VERSION 5.8 ;
BUSBITCHARS "[]" ;
DIVIDERCHAR "/" ;
UNITS
    DATABASE MICRONS 1000 ;
END UNITS

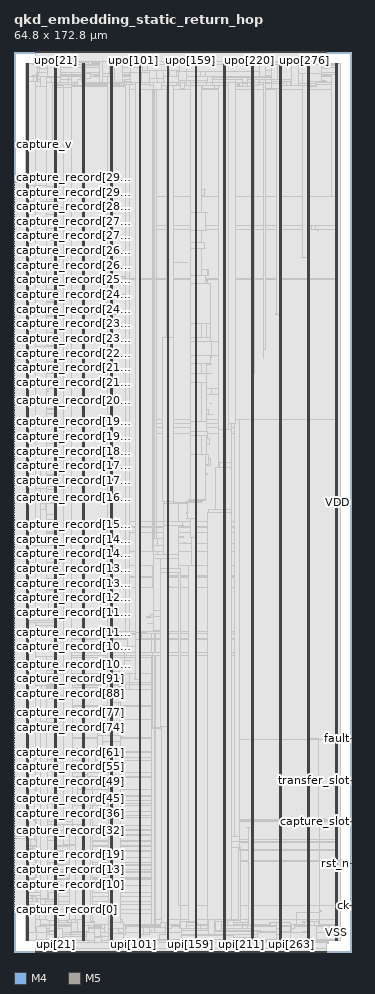
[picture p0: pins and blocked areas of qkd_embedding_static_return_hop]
MACRO qkd_embedding_static_return_hop
  FOREIGN qkd_embedding_static_return_hop 0 0 ;
  CLASS BLOCK ;
  SIZE 64.8 BY 172.8 ;
  PIN capture_record[0]
    DIRECTION INPUT ;
    USE SIGNAL ;
    PORT
      LAYER M4 ;
        RECT  -0.072 8.208 0.072 8.232 ;
    END
  END capture_record[0]
  PIN capture_record[100]
    DIRECTION INPUT ;
    USE SIGNAL ;
    PORT
      LAYER M4 ;
        RECT  -0.072 55.2 0.072 55.224 ;
    END
  END capture_record[100]
  PIN capture_record[101]
    DIRECTION INPUT ;
    USE SIGNAL ;
    PORT
      LAYER M4 ;
        RECT  -0.072 55.68 0.072 55.704 ;
    END
  END capture_record[101]
  PIN capture_record[102]
    DIRECTION INPUT ;
    USE SIGNAL ;
    PORT
      LAYER M4 ;
        RECT  -0.072 56.16 0.072 56.184 ;
    END
  END capture_record[102]
  PIN capture_record[103]
    DIRECTION INPUT ;
    USE SIGNAL ;
    PORT
      LAYER M4 ;
        RECT  -0.072 56.592 0.072 56.616 ;
    END
  END capture_record[103]
  PIN capture_record[104]
    DIRECTION INPUT ;
    USE SIGNAL ;
    PORT
      LAYER M4 ;
        RECT  -0.072 57.072 0.072 57.096 ;
    END
  END capture_record[104]
  PIN capture_record[105]
    DIRECTION INPUT ;
    USE SIGNAL ;
    PORT
      LAYER M4 ;
        RECT  -0.072 57.552 0.072 57.576 ;
    END
  END capture_record[105]
  PIN capture_record[106]
    DIRECTION INPUT ;
    USE SIGNAL ;
    PORT
      LAYER M4 ;
        RECT  -0.072 58.032 0.072 58.056 ;
    END
  END capture_record[106]
  PIN capture_record[107]
    DIRECTION INPUT ;
    USE SIGNAL ;
    PORT
      LAYER M4 ;
        RECT  -0.072 58.512 0.072 58.536 ;
    END
  END capture_record[107]
  PIN capture_record[108]
    DIRECTION INPUT ;
    USE SIGNAL ;
    PORT
      LAYER M4 ;
        RECT  -0.072 58.944 0.072 58.968 ;
    END
  END capture_record[108]
  PIN capture_record[109]
    DIRECTION INPUT ;
    USE SIGNAL ;
    PORT
      LAYER M4 ;
        RECT  -0.072 59.424 0.072 59.448 ;
    END
  END capture_record[109]
  PIN capture_record[10]
    DIRECTION INPUT ;
    USE SIGNAL ;
    PORT
      LAYER M4 ;
        RECT  -0.072 12.912 0.072 12.936 ;
    END
  END capture_record[10]
  PIN capture_record[110]
    DIRECTION INPUT ;
    USE SIGNAL ;
    PORT
      LAYER M4 ;
        RECT  -0.072 59.904 0.072 59.928 ;
    END
  END capture_record[110]
  PIN capture_record[111]
    DIRECTION INPUT ;
    USE SIGNAL ;
    PORT
      LAYER M4 ;
        RECT  -0.072 60.384 0.072 60.408 ;
    END
  END capture_record[111]
  PIN capture_record[112]
    DIRECTION INPUT ;
    USE SIGNAL ;
    PORT
      LAYER M4 ;
        RECT  -0.072 60.864 0.072 60.888 ;
    END
  END capture_record[112]
  PIN capture_record[113]
    DIRECTION INPUT ;
    USE SIGNAL ;
    PORT
      LAYER M4 ;
        RECT  -0.072 61.296 0.072 61.32 ;
    END
  END capture_record[113]
  PIN capture_record[114]
    DIRECTION INPUT ;
    USE SIGNAL ;
    PORT
      LAYER M4 ;
        RECT  -0.072 61.776 0.072 61.8 ;
    END
  END capture_record[114]
  PIN capture_record[115]
    DIRECTION INPUT ;
    USE SIGNAL ;
    PORT
      LAYER M4 ;
        RECT  -0.072 62.256 0.072 62.28 ;
    END
  END capture_record[115]
  PIN capture_record[116]
    DIRECTION INPUT ;
    USE SIGNAL ;
    PORT
      LAYER M4 ;
        RECT  -0.072 62.736 0.072 62.76 ;
    END
  END capture_record[116]
  PIN capture_record[117]
    DIRECTION INPUT ;
    USE SIGNAL ;
    PORT
      LAYER M4 ;
        RECT  -0.072 63.168 0.072 63.192 ;
    END
  END capture_record[117]
  PIN capture_record[118]
    DIRECTION INPUT ;
    USE SIGNAL ;
    PORT
      LAYER M4 ;
        RECT  -0.072 63.648 0.072 63.672 ;
    END
  END capture_record[118]
  PIN capture_record[119]
    DIRECTION INPUT ;
    USE SIGNAL ;
    PORT
      LAYER M4 ;
        RECT  -0.072 64.128 0.072 64.152 ;
    END
  END capture_record[119]
  PIN capture_record[11]
    DIRECTION INPUT ;
    USE SIGNAL ;
    PORT
      LAYER M4 ;
        RECT  -0.072 13.392 0.072 13.416 ;
    END
  END capture_record[11]
  PIN capture_record[120]
    DIRECTION INPUT ;
    USE SIGNAL ;
    PORT
      LAYER M4 ;
        RECT  -0.072 64.608 0.072 64.632 ;
    END
  END capture_record[120]
  PIN capture_record[121]
    DIRECTION INPUT ;
    USE SIGNAL ;
    PORT
      LAYER M4 ;
        RECT  -0.072 65.088 0.072 65.112 ;
    END
  END capture_record[121]
  PIN capture_record[122]
    DIRECTION INPUT ;
    USE SIGNAL ;
    PORT
      LAYER M4 ;
        RECT  -0.072 65.52 0.072 65.544 ;
    END
  END capture_record[122]
  PIN capture_record[123]
    DIRECTION INPUT ;
    USE SIGNAL ;
    PORT
      LAYER M4 ;
        RECT  -0.072 66 0.072 66.024 ;
    END
  END capture_record[123]
  PIN capture_record[124]
    DIRECTION INPUT ;
    USE SIGNAL ;
    PORT
      LAYER M4 ;
        RECT  -0.072 66.48 0.072 66.504 ;
    END
  END capture_record[124]
  PIN capture_record[125]
    DIRECTION INPUT ;
    USE SIGNAL ;
    PORT
      LAYER M4 ;
        RECT  -0.072 66.96 0.072 66.984 ;
    END
  END capture_record[125]
  PIN capture_record[126]
    DIRECTION INPUT ;
    USE SIGNAL ;
    PORT
      LAYER M4 ;
        RECT  -0.072 67.44 0.072 67.464 ;
    END
  END capture_record[126]
  PIN capture_record[127]
    DIRECTION INPUT ;
    USE SIGNAL ;
    PORT
      LAYER M4 ;
        RECT  -0.072 67.872 0.072 67.896 ;
    END
  END capture_record[127]
  PIN capture_record[128]
    DIRECTION INPUT ;
    USE SIGNAL ;
    PORT
      LAYER M4 ;
        RECT  -0.072 68.352 0.072 68.376 ;
    END
  END capture_record[128]
  PIN capture_record[129]
    DIRECTION INPUT ;
    USE SIGNAL ;
    PORT
      LAYER M4 ;
        RECT  -0.072 68.832 0.072 68.856 ;
    END
  END capture_record[129]
  PIN capture_record[12]
    DIRECTION INPUT ;
    USE SIGNAL ;
    PORT
      LAYER M4 ;
        RECT  -0.072 13.872 0.072 13.896 ;
    END
  END capture_record[12]
  PIN capture_record[130]
    DIRECTION INPUT ;
    USE SIGNAL ;
    PORT
      LAYER M4 ;
        RECT  -0.072 69.312 0.072 69.336 ;
    END
  END capture_record[130]
  PIN capture_record[131]
    DIRECTION INPUT ;
    USE SIGNAL ;
    PORT
      LAYER M4 ;
        RECT  -0.072 69.744 0.072 69.768 ;
    END
  END capture_record[131]
  PIN capture_record[132]
    DIRECTION INPUT ;
    USE SIGNAL ;
    PORT
      LAYER M4 ;
        RECT  -0.072 70.224 0.072 70.248 ;
    END
  END capture_record[132]
  PIN capture_record[133]
    DIRECTION INPUT ;
    USE SIGNAL ;
    PORT
      LAYER M4 ;
        RECT  -0.072 70.704 0.072 70.728 ;
    END
  END capture_record[133]
  PIN capture_record[134]
    DIRECTION INPUT ;
    USE SIGNAL ;
    PORT
      LAYER M4 ;
        RECT  -0.072 71.184 0.072 71.208 ;
    END
  END capture_record[134]
  PIN capture_record[135]
    DIRECTION INPUT ;
    USE SIGNAL ;
    PORT
      LAYER M4 ;
        RECT  -0.072 71.664 0.072 71.688 ;
    END
  END capture_record[135]
  PIN capture_record[136]
    DIRECTION INPUT ;
    USE SIGNAL ;
    PORT
      LAYER M4 ;
        RECT  -0.072 72.096 0.072 72.12 ;
    END
  END capture_record[136]
  PIN capture_record[137]
    DIRECTION INPUT ;
    USE SIGNAL ;
    PORT
      LAYER M4 ;
        RECT  -0.072 72.576 0.072 72.6 ;
    END
  END capture_record[137]
  PIN capture_record[138]
    DIRECTION INPUT ;
    USE SIGNAL ;
    PORT
      LAYER M4 ;
        RECT  -0.072 73.056 0.072 73.08 ;
    END
  END capture_record[138]
  PIN capture_record[139]
    DIRECTION INPUT ;
    USE SIGNAL ;
    PORT
      LAYER M4 ;
        RECT  -0.072 73.536 0.072 73.56 ;
    END
  END capture_record[139]
  PIN capture_record[13]
    DIRECTION INPUT ;
    USE SIGNAL ;
    PORT
      LAYER M4 ;
        RECT  -0.072 14.352 0.072 14.376 ;
    END
  END capture_record[13]
  PIN capture_record[140]
    DIRECTION INPUT ;
    USE SIGNAL ;
    PORT
      LAYER M4 ;
        RECT  -0.072 74.016 0.072 74.04 ;
    END
  END capture_record[140]
  PIN capture_record[141]
    DIRECTION INPUT ;
    USE SIGNAL ;
    PORT
      LAYER M4 ;
        RECT  -0.072 74.448 0.072 74.472 ;
    END
  END capture_record[141]
  PIN capture_record[142]
    DIRECTION INPUT ;
    USE SIGNAL ;
    PORT
      LAYER M4 ;
        RECT  -0.072 74.928 0.072 74.952 ;
    END
  END capture_record[142]
  PIN capture_record[143]
    DIRECTION INPUT ;
    USE SIGNAL ;
    PORT
      LAYER M4 ;
        RECT  -0.072 75.408 0.072 75.432 ;
    END
  END capture_record[143]
  PIN capture_record[144]
    DIRECTION INPUT ;
    USE SIGNAL ;
    PORT
      LAYER M4 ;
        RECT  -0.072 75.888 0.072 75.912 ;
    END
  END capture_record[144]
  PIN capture_record[145]
    DIRECTION INPUT ;
    USE SIGNAL ;
    PORT
      LAYER M4 ;
        RECT  -0.072 76.32 0.072 76.344 ;
    END
  END capture_record[145]
  PIN capture_record[146]
    DIRECTION INPUT ;
    USE SIGNAL ;
    PORT
      LAYER M4 ;
        RECT  -0.072 76.8 0.072 76.824 ;
    END
  END capture_record[146]
  PIN capture_record[147]
    DIRECTION INPUT ;
    USE SIGNAL ;
    PORT
      LAYER M4 ;
        RECT  -0.072 77.28 0.072 77.304 ;
    END
  END capture_record[147]
  PIN capture_record[148]
    DIRECTION INPUT ;
    USE SIGNAL ;
    PORT
      LAYER M4 ;
        RECT  -0.072 77.76 0.072 77.784 ;
    END
  END capture_record[148]
  PIN capture_record[149]
    DIRECTION INPUT ;
    USE SIGNAL ;
    PORT
      LAYER M4 ;
        RECT  -0.072 78.24 0.072 78.264 ;
    END
  END capture_record[149]
  PIN capture_record[14]
    DIRECTION INPUT ;
    USE SIGNAL ;
    PORT
      LAYER M4 ;
        RECT  -0.072 14.784 0.072 14.808 ;
    END
  END capture_record[14]
  PIN capture_record[150]
    DIRECTION INPUT ;
    USE SIGNAL ;
    PORT
      LAYER M4 ;
        RECT  -0.072 78.672 0.072 78.696 ;
    END
  END capture_record[150]
  PIN capture_record[151]
    DIRECTION INPUT ;
    USE SIGNAL ;
    PORT
      LAYER M4 ;
        RECT  -0.072 79.152 0.072 79.176 ;
    END
  END capture_record[151]
  PIN capture_record[152]
    DIRECTION INPUT ;
    USE SIGNAL ;
    PORT
      LAYER M4 ;
        RECT  -0.072 79.632 0.072 79.656 ;
    END
  END capture_record[152]
  PIN capture_record[153]
    DIRECTION INPUT ;
    USE SIGNAL ;
    PORT
      LAYER M4 ;
        RECT  -0.072 80.112 0.072 80.136 ;
    END
  END capture_record[153]
  PIN capture_record[154]
    DIRECTION INPUT ;
    USE SIGNAL ;
    PORT
      LAYER M4 ;
        RECT  -0.072 80.592 0.072 80.616 ;
    END
  END capture_record[154]
  PIN capture_record[155]
    DIRECTION INPUT ;
    USE SIGNAL ;
    PORT
      LAYER M4 ;
        RECT  -0.072 81.024 0.072 81.048 ;
    END
  END capture_record[155]
  PIN capture_record[156]
    DIRECTION INPUT ;
    USE SIGNAL ;
    PORT
      LAYER M4 ;
        RECT  -0.072 81.504 0.072 81.528 ;
    END
  END capture_record[156]
  PIN capture_record[157]
    DIRECTION INPUT ;
    USE SIGNAL ;
    PORT
      LAYER M4 ;
        RECT  -0.072 81.984 0.072 82.008 ;
    END
  END capture_record[157]
  PIN capture_record[158]
    DIRECTION INPUT ;
    USE SIGNAL ;
    PORT
      LAYER M4 ;
        RECT  -0.072 82.464 0.072 82.488 ;
    END
  END capture_record[158]
  PIN capture_record[159]
    DIRECTION INPUT ;
    USE SIGNAL ;
    PORT
      LAYER M4 ;
        RECT  -0.072 82.944 0.072 82.968 ;
    END
  END capture_record[159]
  PIN capture_record[15]
    DIRECTION INPUT ;
    USE SIGNAL ;
    PORT
      LAYER M4 ;
        RECT  -0.072 15.264 0.072 15.288 ;
    END
  END capture_record[15]
  PIN capture_record[160]
    DIRECTION INPUT ;
    USE SIGNAL ;
    PORT
      LAYER M4 ;
        RECT  -0.072 83.376 0.072 83.4 ;
    END
  END capture_record[160]
  PIN capture_record[161]
    DIRECTION INPUT ;
    USE SIGNAL ;
    PORT
      LAYER M4 ;
        RECT  -0.072 83.856 0.072 83.88 ;
    END
  END capture_record[161]
  PIN capture_record[162]
    DIRECTION INPUT ;
    USE SIGNAL ;
    PORT
      LAYER M4 ;
        RECT  -0.072 84.336 0.072 84.36 ;
    END
  END capture_record[162]
  PIN capture_record[163]
    DIRECTION INPUT ;
    USE SIGNAL ;
    PORT
      LAYER M4 ;
        RECT  -0.072 84.816 0.072 84.84 ;
    END
  END capture_record[163]
  PIN capture_record[164]
    DIRECTION INPUT ;
    USE SIGNAL ;
    PORT
      LAYER M4 ;
        RECT  -0.072 85.248 0.072 85.272 ;
    END
  END capture_record[164]
  PIN capture_record[165]
    DIRECTION INPUT ;
    USE SIGNAL ;
    PORT
      LAYER M4 ;
        RECT  -0.072 85.728 0.072 85.752 ;
    END
  END capture_record[165]
  PIN capture_record[166]
    DIRECTION INPUT ;
    USE SIGNAL ;
    PORT
      LAYER M4 ;
        RECT  -0.072 86.208 0.072 86.232 ;
    END
  END capture_record[166]
  PIN capture_record[167]
    DIRECTION INPUT ;
    USE SIGNAL ;
    PORT
      LAYER M4 ;
        RECT  -0.072 86.688 0.072 86.712 ;
    END
  END capture_record[167]
  PIN capture_record[168]
    DIRECTION INPUT ;
    USE SIGNAL ;
    PORT
      LAYER M4 ;
        RECT  -0.072 87.168 0.072 87.192 ;
    END
  END capture_record[168]
  PIN capture_record[169]
    DIRECTION INPUT ;
    USE SIGNAL ;
    PORT
      LAYER M4 ;
        RECT  -0.072 87.6 0.072 87.624 ;
    END
  END capture_record[169]
  PIN capture_record[16]
    DIRECTION INPUT ;
    USE SIGNAL ;
    PORT
      LAYER M4 ;
        RECT  -0.072 15.744 0.072 15.768 ;
    END
  END capture_record[16]
  PIN capture_record[170]
    DIRECTION INPUT ;
    USE SIGNAL ;
    PORT
      LAYER M4 ;
        RECT  -0.072 88.08 0.072 88.104 ;
    END
  END capture_record[170]
  PIN capture_record[171]
    DIRECTION INPUT ;
    USE SIGNAL ;
    PORT
      LAYER M4 ;
        RECT  -0.072 88.56 0.072 88.584 ;
    END
  END capture_record[171]
  PIN capture_record[172]
    DIRECTION INPUT ;
    USE SIGNAL ;
    PORT
      LAYER M4 ;
        RECT  -0.072 89.04 0.072 89.064 ;
    END
  END capture_record[172]
  PIN capture_record[173]
    DIRECTION INPUT ;
    USE SIGNAL ;
    PORT
      LAYER M4 ;
        RECT  -0.072 89.52 0.072 89.544 ;
    END
  END capture_record[173]
  PIN capture_record[174]
    DIRECTION INPUT ;
    USE SIGNAL ;
    PORT
      LAYER M4 ;
        RECT  -0.072 89.952 0.072 89.976 ;
    END
  END capture_record[174]
  PIN capture_record[175]
    DIRECTION INPUT ;
    USE SIGNAL ;
    PORT
      LAYER M4 ;
        RECT  -0.072 90.432 0.072 90.456 ;
    END
  END capture_record[175]
  PIN capture_record[176]
    DIRECTION INPUT ;
    USE SIGNAL ;
    PORT
      LAYER M4 ;
        RECT  -0.072 90.912 0.072 90.936 ;
    END
  END capture_record[176]
  PIN capture_record[177]
    DIRECTION INPUT ;
    USE SIGNAL ;
    PORT
      LAYER M4 ;
        RECT  -0.072 91.392 0.072 91.416 ;
    END
  END capture_record[177]
  PIN capture_record[178]
    DIRECTION INPUT ;
    USE SIGNAL ;
    PORT
      LAYER M4 ;
        RECT  -0.072 91.824 0.072 91.848 ;
    END
  END capture_record[178]
  PIN capture_record[179]
    DIRECTION INPUT ;
    USE SIGNAL ;
    PORT
      LAYER M4 ;
        RECT  -0.072 92.304 0.072 92.328 ;
    END
  END capture_record[179]
  PIN capture_record[17]
    DIRECTION INPUT ;
    USE SIGNAL ;
    PORT
      LAYER M4 ;
        RECT  -0.072 16.224 0.072 16.248 ;
    END
  END capture_record[17]
  PIN capture_record[180]
    DIRECTION INPUT ;
    USE SIGNAL ;
    PORT
      LAYER M4 ;
        RECT  -0.072 92.784 0.072 92.808 ;
    END
  END capture_record[180]
  PIN capture_record[181]
    DIRECTION INPUT ;
    USE SIGNAL ;
    PORT
      LAYER M4 ;
        RECT  -0.072 93.264 0.072 93.288 ;
    END
  END capture_record[181]
  PIN capture_record[182]
    DIRECTION INPUT ;
    USE SIGNAL ;
    PORT
      LAYER M4 ;
        RECT  -0.072 93.744 0.072 93.768 ;
    END
  END capture_record[182]
  PIN capture_record[183]
    DIRECTION INPUT ;
    USE SIGNAL ;
    PORT
      LAYER M4 ;
        RECT  -0.072 94.176 0.072 94.2 ;
    END
  END capture_record[183]
  PIN capture_record[184]
    DIRECTION INPUT ;
    USE SIGNAL ;
    PORT
      LAYER M4 ;
        RECT  -0.072 94.656 0.072 94.68 ;
    END
  END capture_record[184]
  PIN capture_record[185]
    DIRECTION INPUT ;
    USE SIGNAL ;
    PORT
      LAYER M4 ;
        RECT  -0.072 95.136 0.072 95.16 ;
    END
  END capture_record[185]
  PIN capture_record[186]
    DIRECTION INPUT ;
    USE SIGNAL ;
    PORT
      LAYER M4 ;
        RECT  -0.072 95.616 0.072 95.64 ;
    END
  END capture_record[186]
  PIN capture_record[187]
    DIRECTION INPUT ;
    USE SIGNAL ;
    PORT
      LAYER M4 ;
        RECT  -0.072 96.096 0.072 96.12 ;
    END
  END capture_record[187]
  PIN capture_record[188]
    DIRECTION INPUT ;
    USE SIGNAL ;
    PORT
      LAYER M4 ;
        RECT  -0.072 96.528 0.072 96.552 ;
    END
  END capture_record[188]
  PIN capture_record[189]
    DIRECTION INPUT ;
    USE SIGNAL ;
    PORT
      LAYER M4 ;
        RECT  -0.072 97.008 0.072 97.032 ;
    END
  END capture_record[189]
  PIN capture_record[18]
    DIRECTION INPUT ;
    USE SIGNAL ;
    PORT
      LAYER M4 ;
        RECT  -0.072 16.656 0.072 16.68 ;
    END
  END capture_record[18]
  PIN capture_record[190]
    DIRECTION INPUT ;
    USE SIGNAL ;
    PORT
      LAYER M4 ;
        RECT  -0.072 97.488 0.072 97.512 ;
    END
  END capture_record[190]
  PIN capture_record[191]
    DIRECTION INPUT ;
    USE SIGNAL ;
    PORT
      LAYER M4 ;
        RECT  -0.072 97.968 0.072 97.992 ;
    END
  END capture_record[191]
  PIN capture_record[192]
    DIRECTION INPUT ;
    USE SIGNAL ;
    PORT
      LAYER M4 ;
        RECT  -0.072 98.448 0.072 98.472 ;
    END
  END capture_record[192]
  PIN capture_record[193]
    DIRECTION INPUT ;
    USE SIGNAL ;
    PORT
      LAYER M4 ;
        RECT  -0.072 98.88 0.072 98.904 ;
    END
  END capture_record[193]
  PIN capture_record[194]
    DIRECTION INPUT ;
    USE SIGNAL ;
    PORT
      LAYER M4 ;
        RECT  -0.072 99.36 0.072 99.384 ;
    END
  END capture_record[194]
  PIN capture_record[195]
    DIRECTION INPUT ;
    USE SIGNAL ;
    PORT
      LAYER M4 ;
        RECT  -0.072 99.84 0.072 99.864 ;
    END
  END capture_record[195]
  PIN capture_record[196]
    DIRECTION INPUT ;
    USE SIGNAL ;
    PORT
      LAYER M4 ;
        RECT  -0.072 100.32 0.072 100.344 ;
    END
  END capture_record[196]
  PIN capture_record[197]
    DIRECTION INPUT ;
    USE SIGNAL ;
    PORT
      LAYER M4 ;
        RECT  -0.072 100.752 0.072 100.776 ;
    END
  END capture_record[197]
  PIN capture_record[198]
    DIRECTION INPUT ;
    USE SIGNAL ;
    PORT
      LAYER M4 ;
        RECT  -0.072 101.232 0.072 101.256 ;
    END
  END capture_record[198]
  PIN capture_record[199]
    DIRECTION INPUT ;
    USE SIGNAL ;
    PORT
      LAYER M4 ;
        RECT  -0.072 101.712 0.072 101.736 ;
    END
  END capture_record[199]
  PIN capture_record[19]
    DIRECTION INPUT ;
    USE SIGNAL ;
    PORT
      LAYER M4 ;
        RECT  -0.072 17.136 0.072 17.16 ;
    END
  END capture_record[19]
  PIN capture_record[1]
    DIRECTION INPUT ;
    USE SIGNAL ;
    PORT
      LAYER M4 ;
        RECT  -0.072 8.688 0.072 8.712 ;
    END
  END capture_record[1]
  PIN capture_record[200]
    DIRECTION INPUT ;
    USE SIGNAL ;
    PORT
      LAYER M4 ;
        RECT  -0.072 102.192 0.072 102.216 ;
    END
  END capture_record[200]
  PIN capture_record[201]
    DIRECTION INPUT ;
    USE SIGNAL ;
    PORT
      LAYER M4 ;
        RECT  -0.072 102.672 0.072 102.696 ;
    END
  END capture_record[201]
  PIN capture_record[202]
    DIRECTION INPUT ;
    USE SIGNAL ;
    PORT
      LAYER M4 ;
        RECT  -0.072 103.104 0.072 103.128 ;
    END
  END capture_record[202]
  PIN capture_record[203]
    DIRECTION INPUT ;
    USE SIGNAL ;
    PORT
      LAYER M4 ;
        RECT  -0.072 103.584 0.072 103.608 ;
    END
  END capture_record[203]
  PIN capture_record[204]
    DIRECTION INPUT ;
    USE SIGNAL ;
    PORT
      LAYER M4 ;
        RECT  -0.072 104.064 0.072 104.088 ;
    END
  END capture_record[204]
  PIN capture_record[205]
    DIRECTION INPUT ;
    USE SIGNAL ;
    PORT
      LAYER M4 ;
        RECT  -0.072 104.544 0.072 104.568 ;
    END
  END capture_record[205]
  PIN capture_record[206]
    DIRECTION INPUT ;
    USE SIGNAL ;
    PORT
      LAYER M4 ;
        RECT  -0.072 105.024 0.072 105.048 ;
    END
  END capture_record[206]
  PIN capture_record[207]
    DIRECTION INPUT ;
    USE SIGNAL ;
    PORT
      LAYER M4 ;
        RECT  -0.072 105.456 0.072 105.48 ;
    END
  END capture_record[207]
  PIN capture_record[208]
    DIRECTION INPUT ;
    USE SIGNAL ;
    PORT
      LAYER M4 ;
        RECT  -0.072 105.936 0.072 105.96 ;
    END
  END capture_record[208]
  PIN capture_record[209]
    DIRECTION INPUT ;
    USE SIGNAL ;
    PORT
      LAYER M4 ;
        RECT  -0.072 106.416 0.072 106.44 ;
    END
  END capture_record[209]
  PIN capture_record[20]
    DIRECTION INPUT ;
    USE SIGNAL ;
    PORT
      LAYER M4 ;
        RECT  -0.072 17.616 0.072 17.64 ;
    END
  END capture_record[20]
  PIN capture_record[210]
    DIRECTION INPUT ;
    USE SIGNAL ;
    PORT
      LAYER M4 ;
        RECT  -0.072 106.896 0.072 106.92 ;
    END
  END capture_record[210]
  PIN capture_record[211]
    DIRECTION INPUT ;
    USE SIGNAL ;
    PORT
      LAYER M4 ;
        RECT  -0.072 107.328 0.072 107.352 ;
    END
  END capture_record[211]
  PIN capture_record[212]
    DIRECTION INPUT ;
    USE SIGNAL ;
    PORT
      LAYER M4 ;
        RECT  -0.072 107.808 0.072 107.832 ;
    END
  END capture_record[212]
  PIN capture_record[213]
    DIRECTION INPUT ;
    USE SIGNAL ;
    PORT
      LAYER M4 ;
        RECT  -0.072 108.288 0.072 108.312 ;
    END
  END capture_record[213]
  PIN capture_record[214]
    DIRECTION INPUT ;
    USE SIGNAL ;
    PORT
      LAYER M4 ;
        RECT  -0.072 108.768 0.072 108.792 ;
    END
  END capture_record[214]
  PIN capture_record[215]
    DIRECTION INPUT ;
    USE SIGNAL ;
    PORT
      LAYER M4 ;
        RECT  -0.072 109.248 0.072 109.272 ;
    END
  END capture_record[215]
  PIN capture_record[216]
    DIRECTION INPUT ;
    USE SIGNAL ;
    PORT
      LAYER M4 ;
        RECT  -0.072 109.68 0.072 109.704 ;
    END
  END capture_record[216]
  PIN capture_record[217]
    DIRECTION INPUT ;
    USE SIGNAL ;
    PORT
      LAYER M4 ;
        RECT  -0.072 110.16 0.072 110.184 ;
    END
  END capture_record[217]
  PIN capture_record[218]
    DIRECTION INPUT ;
    USE SIGNAL ;
    PORT
      LAYER M4 ;
        RECT  -0.072 110.64 0.072 110.664 ;
    END
  END capture_record[218]
  PIN capture_record[219]
    DIRECTION INPUT ;
    USE SIGNAL ;
    PORT
      LAYER M4 ;
        RECT  -0.072 111.12 0.072 111.144 ;
    END
  END capture_record[219]
  PIN capture_record[21]
    DIRECTION INPUT ;
    USE SIGNAL ;
    PORT
      LAYER M4 ;
        RECT  -0.072 18.096 0.072 18.12 ;
    END
  END capture_record[21]
  PIN capture_record[220]
    DIRECTION INPUT ;
    USE SIGNAL ;
    PORT
      LAYER M4 ;
        RECT  -0.072 111.6 0.072 111.624 ;
    END
  END capture_record[220]
  PIN capture_record[221]
    DIRECTION INPUT ;
    USE SIGNAL ;
    PORT
      LAYER M4 ;
        RECT  -0.072 112.032 0.072 112.056 ;
    END
  END capture_record[221]
  PIN capture_record[222]
    DIRECTION INPUT ;
    USE SIGNAL ;
    PORT
      LAYER M4 ;
        RECT  -0.072 112.512 0.072 112.536 ;
    END
  END capture_record[222]
  PIN capture_record[223]
    DIRECTION INPUT ;
    USE SIGNAL ;
    PORT
      LAYER M4 ;
        RECT  -0.072 112.992 0.072 113.016 ;
    END
  END capture_record[223]
  PIN capture_record[224]
    DIRECTION INPUT ;
    USE SIGNAL ;
    PORT
      LAYER M4 ;
        RECT  -0.072 113.472 0.072 113.496 ;
    END
  END capture_record[224]
  PIN capture_record[225]
    DIRECTION INPUT ;
    USE SIGNAL ;
    PORT
      LAYER M4 ;
        RECT  -0.072 113.904 0.072 113.928 ;
    END
  END capture_record[225]
  PIN capture_record[226]
    DIRECTION INPUT ;
    USE SIGNAL ;
    PORT
      LAYER M4 ;
        RECT  -0.072 114.384 0.072 114.408 ;
    END
  END capture_record[226]
  PIN capture_record[227]
    DIRECTION INPUT ;
    USE SIGNAL ;
    PORT
      LAYER M4 ;
        RECT  -0.072 114.864 0.072 114.888 ;
    END
  END capture_record[227]
  PIN capture_record[228]
    DIRECTION INPUT ;
    USE SIGNAL ;
    PORT
      LAYER M4 ;
        RECT  -0.072 115.344 0.072 115.368 ;
    END
  END capture_record[228]
  PIN capture_record[229]
    DIRECTION INPUT ;
    USE SIGNAL ;
    PORT
      LAYER M4 ;
        RECT  -0.072 115.824 0.072 115.848 ;
    END
  END capture_record[229]
  PIN capture_record[22]
    DIRECTION INPUT ;
    USE SIGNAL ;
    PORT
      LAYER M4 ;
        RECT  -0.072 18.576 0.072 18.6 ;
    END
  END capture_record[22]
  PIN capture_record[230]
    DIRECTION INPUT ;
    USE SIGNAL ;
    PORT
      LAYER M4 ;
        RECT  -0.072 116.256 0.072 116.28 ;
    END
  END capture_record[230]
  PIN capture_record[231]
    DIRECTION INPUT ;
    USE SIGNAL ;
    PORT
      LAYER M4 ;
        RECT  -0.072 116.736 0.072 116.76 ;
    END
  END capture_record[231]
  PIN capture_record[232]
    DIRECTION INPUT ;
    USE SIGNAL ;
    PORT
      LAYER M4 ;
        RECT  -0.072 117.216 0.072 117.24 ;
    END
  END capture_record[232]
  PIN capture_record[233]
    DIRECTION INPUT ;
    USE SIGNAL ;
    PORT
      LAYER M4 ;
        RECT  -0.072 117.696 0.072 117.72 ;
    END
  END capture_record[233]
  PIN capture_record[234]
    DIRECTION INPUT ;
    USE SIGNAL ;
    PORT
      LAYER M4 ;
        RECT  -0.072 118.176 0.072 118.2 ;
    END
  END capture_record[234]
  PIN capture_record[235]
    DIRECTION INPUT ;
    USE SIGNAL ;
    PORT
      LAYER M4 ;
        RECT  -0.072 118.608 0.072 118.632 ;
    END
  END capture_record[235]
  PIN capture_record[236]
    DIRECTION INPUT ;
    USE SIGNAL ;
    PORT
      LAYER M4 ;
        RECT  -0.072 119.088 0.072 119.112 ;
    END
  END capture_record[236]
  PIN capture_record[237]
    DIRECTION INPUT ;
    USE SIGNAL ;
    PORT
      LAYER M4 ;
        RECT  -0.072 119.568 0.072 119.592 ;
    END
  END capture_record[237]
  PIN capture_record[238]
    DIRECTION INPUT ;
    USE SIGNAL ;
    PORT
      LAYER M4 ;
        RECT  -0.072 120.048 0.072 120.072 ;
    END
  END capture_record[238]
  PIN capture_record[239]
    DIRECTION INPUT ;
    USE SIGNAL ;
    PORT
      LAYER M4 ;
        RECT  -0.072 120.528 0.072 120.552 ;
    END
  END capture_record[239]
  PIN capture_record[23]
    DIRECTION INPUT ;
    USE SIGNAL ;
    PORT
      LAYER M4 ;
        RECT  -0.072 19.008 0.072 19.032 ;
    END
  END capture_record[23]
  PIN capture_record[240]
    DIRECTION INPUT ;
    USE SIGNAL ;
    PORT
      LAYER M4 ;
        RECT  -0.072 120.96 0.072 120.984 ;
    END
  END capture_record[240]
  PIN capture_record[241]
    DIRECTION INPUT ;
    USE SIGNAL ;
    PORT
      LAYER M4 ;
        RECT  -0.072 121.44 0.072 121.464 ;
    END
  END capture_record[241]
  PIN capture_record[242]
    DIRECTION INPUT ;
    USE SIGNAL ;
    PORT
      LAYER M4 ;
        RECT  -0.072 121.92 0.072 121.944 ;
    END
  END capture_record[242]
  PIN capture_record[243]
    DIRECTION INPUT ;
    USE SIGNAL ;
    PORT
      LAYER M4 ;
        RECT  -0.072 122.4 0.072 122.424 ;
    END
  END capture_record[243]
  PIN capture_record[244]
    DIRECTION INPUT ;
    USE SIGNAL ;
    PORT
      LAYER M4 ;
        RECT  -0.072 122.832 0.072 122.856 ;
    END
  END capture_record[244]
  PIN capture_record[245]
    DIRECTION INPUT ;
    USE SIGNAL ;
    PORT
      LAYER M4 ;
        RECT  -0.072 123.312 0.072 123.336 ;
    END
  END capture_record[245]
  PIN capture_record[246]
    DIRECTION INPUT ;
    USE SIGNAL ;
    PORT
      LAYER M4 ;
        RECT  -0.072 123.792 0.072 123.816 ;
    END
  END capture_record[246]
  PIN capture_record[247]
    DIRECTION INPUT ;
    USE SIGNAL ;
    PORT
      LAYER M4 ;
        RECT  -0.072 124.272 0.072 124.296 ;
    END
  END capture_record[247]
  PIN capture_record[248]
    DIRECTION INPUT ;
    USE SIGNAL ;
    PORT
      LAYER M4 ;
        RECT  -0.072 124.752 0.072 124.776 ;
    END
  END capture_record[248]
  PIN capture_record[249]
    DIRECTION INPUT ;
    USE SIGNAL ;
    PORT
      LAYER M4 ;
        RECT  -0.072 125.184 0.072 125.208 ;
    END
  END capture_record[249]
  PIN capture_record[24]
    DIRECTION INPUT ;
    USE SIGNAL ;
    PORT
      LAYER M4 ;
        RECT  -0.072 19.488 0.072 19.512 ;
    END
  END capture_record[24]
  PIN capture_record[250]
    DIRECTION INPUT ;
    USE SIGNAL ;
    PORT
      LAYER M4 ;
        RECT  -0.072 125.664 0.072 125.688 ;
    END
  END capture_record[250]
  PIN capture_record[251]
    DIRECTION INPUT ;
    USE SIGNAL ;
    PORT
      LAYER M4 ;
        RECT  -0.072 126.144 0.072 126.168 ;
    END
  END capture_record[251]
  PIN capture_record[252]
    DIRECTION INPUT ;
    USE SIGNAL ;
    PORT
      LAYER M4 ;
        RECT  -0.072 126.624 0.072 126.648 ;
    END
  END capture_record[252]
  PIN capture_record[253]
    DIRECTION INPUT ;
    USE SIGNAL ;
    PORT
      LAYER M4 ;
        RECT  -0.072 127.104 0.072 127.128 ;
    END
  END capture_record[253]
  PIN capture_record[254]
    DIRECTION INPUT ;
    USE SIGNAL ;
    PORT
      LAYER M4 ;
        RECT  -0.072 127.536 0.072 127.56 ;
    END
  END capture_record[254]
  PIN capture_record[255]
    DIRECTION INPUT ;
    USE SIGNAL ;
    PORT
      LAYER M4 ;
        RECT  -0.072 128.016 0.072 128.04 ;
    END
  END capture_record[255]
  PIN capture_record[256]
    DIRECTION INPUT ;
    USE SIGNAL ;
    PORT
      LAYER M4 ;
        RECT  -0.072 128.496 0.072 128.52 ;
    END
  END capture_record[256]
  PIN capture_record[257]
    DIRECTION INPUT ;
    USE SIGNAL ;
    PORT
      LAYER M4 ;
        RECT  -0.072 128.976 0.072 129 ;
    END
  END capture_record[257]
  PIN capture_record[258]
    DIRECTION INPUT ;
    USE SIGNAL ;
    PORT
      LAYER M4 ;
        RECT  -0.072 129.408 0.072 129.432 ;
    END
  END capture_record[258]
  PIN capture_record[259]
    DIRECTION INPUT ;
    USE SIGNAL ;
    PORT
      LAYER M4 ;
        RECT  -0.072 129.888 0.072 129.912 ;
    END
  END capture_record[259]
  PIN capture_record[25]
    DIRECTION INPUT ;
    USE SIGNAL ;
    PORT
      LAYER M4 ;
        RECT  -0.072 19.968 0.072 19.992 ;
    END
  END capture_record[25]
  PIN capture_record[260]
    DIRECTION INPUT ;
    USE SIGNAL ;
    PORT
      LAYER M4 ;
        RECT  -0.072 130.368 0.072 130.392 ;
    END
  END capture_record[260]
  PIN capture_record[261]
    DIRECTION INPUT ;
    USE SIGNAL ;
    PORT
      LAYER M4 ;
        RECT  -0.072 130.848 0.072 130.872 ;
    END
  END capture_record[261]
  PIN capture_record[262]
    DIRECTION INPUT ;
    USE SIGNAL ;
    PORT
      LAYER M4 ;
        RECT  -0.072 131.328 0.072 131.352 ;
    END
  END capture_record[262]
  PIN capture_record[263]
    DIRECTION INPUT ;
    USE SIGNAL ;
    PORT
      LAYER M4 ;
        RECT  -0.072 131.76 0.072 131.784 ;
    END
  END capture_record[263]
  PIN capture_record[264]
    DIRECTION INPUT ;
    USE SIGNAL ;
    PORT
      LAYER M4 ;
        RECT  -0.072 132.24 0.072 132.264 ;
    END
  END capture_record[264]
  PIN capture_record[265]
    DIRECTION INPUT ;
    USE SIGNAL ;
    PORT
      LAYER M4 ;
        RECT  -0.072 132.72 0.072 132.744 ;
    END
  END capture_record[265]
  PIN capture_record[266]
    DIRECTION INPUT ;
    USE SIGNAL ;
    PORT
      LAYER M4 ;
        RECT  -0.072 133.2 0.072 133.224 ;
    END
  END capture_record[266]
  PIN capture_record[267]
    DIRECTION INPUT ;
    USE SIGNAL ;
    PORT
      LAYER M4 ;
        RECT  -0.072 133.68 0.072 133.704 ;
    END
  END capture_record[267]
  PIN capture_record[268]
    DIRECTION INPUT ;
    USE SIGNAL ;
    PORT
      LAYER M4 ;
        RECT  -0.072 134.112 0.072 134.136 ;
    END
  END capture_record[268]
  PIN capture_record[269]
    DIRECTION INPUT ;
    USE SIGNAL ;
    PORT
      LAYER M4 ;
        RECT  -0.072 134.592 0.072 134.616 ;
    END
  END capture_record[269]
  PIN capture_record[26]
    DIRECTION INPUT ;
    USE SIGNAL ;
    PORT
      LAYER M4 ;
        RECT  -0.072 20.448 0.072 20.472 ;
    END
  END capture_record[26]
  PIN capture_record[270]
    DIRECTION INPUT ;
    USE SIGNAL ;
    PORT
      LAYER M4 ;
        RECT  -0.072 135.072 0.072 135.096 ;
    END
  END capture_record[270]
  PIN capture_record[271]
    DIRECTION INPUT ;
    USE SIGNAL ;
    PORT
      LAYER M4 ;
        RECT  -0.072 135.552 0.072 135.576 ;
    END
  END capture_record[271]
  PIN capture_record[272]
    DIRECTION INPUT ;
    USE SIGNAL ;
    PORT
      LAYER M4 ;
        RECT  -0.072 136.032 0.072 136.056 ;
    END
  END capture_record[272]
  PIN capture_record[273]
    DIRECTION INPUT ;
    USE SIGNAL ;
    PORT
      LAYER M4 ;
        RECT  -0.072 136.464 0.072 136.488 ;
    END
  END capture_record[273]
  PIN capture_record[274]
    DIRECTION INPUT ;
    USE SIGNAL ;
    PORT
      LAYER M4 ;
        RECT  -0.072 136.944 0.072 136.968 ;
    END
  END capture_record[274]
  PIN capture_record[275]
    DIRECTION INPUT ;
    USE SIGNAL ;
    PORT
      LAYER M4 ;
        RECT  -0.072 137.424 0.072 137.448 ;
    END
  END capture_record[275]
  PIN capture_record[276]
    DIRECTION INPUT ;
    USE SIGNAL ;
    PORT
      LAYER M4 ;
        RECT  -0.072 137.904 0.072 137.928 ;
    END
  END capture_record[276]
  PIN capture_record[277]
    DIRECTION INPUT ;
    USE SIGNAL ;
    PORT
      LAYER M4 ;
        RECT  -0.072 138.336 0.072 138.36 ;
    END
  END capture_record[277]
  PIN capture_record[278]
    DIRECTION INPUT ;
    USE SIGNAL ;
    PORT
      LAYER M4 ;
        RECT  -0.072 138.816 0.072 138.84 ;
    END
  END capture_record[278]
  PIN capture_record[279]
    DIRECTION INPUT ;
    USE SIGNAL ;
    PORT
      LAYER M4 ;
        RECT  -0.072 139.296 0.072 139.32 ;
    END
  END capture_record[279]
  PIN capture_record[27]
    DIRECTION INPUT ;
    USE SIGNAL ;
    PORT
      LAYER M4 ;
        RECT  -0.072 20.928 0.072 20.952 ;
    END
  END capture_record[27]
  PIN capture_record[280]
    DIRECTION INPUT ;
    USE SIGNAL ;
    PORT
      LAYER M4 ;
        RECT  -0.072 139.776 0.072 139.8 ;
    END
  END capture_record[280]
  PIN capture_record[281]
    DIRECTION INPUT ;
    USE SIGNAL ;
    PORT
      LAYER M4 ;
        RECT  -0.072 140.256 0.072 140.28 ;
    END
  END capture_record[281]
  PIN capture_record[282]
    DIRECTION INPUT ;
    USE SIGNAL ;
    PORT
      LAYER M4 ;
        RECT  -0.072 140.688 0.072 140.712 ;
    END
  END capture_record[282]
  PIN capture_record[283]
    DIRECTION INPUT ;
    USE SIGNAL ;
    PORT
      LAYER M4 ;
        RECT  -0.072 141.168 0.072 141.192 ;
    END
  END capture_record[283]
  PIN capture_record[284]
    DIRECTION INPUT ;
    USE SIGNAL ;
    PORT
      LAYER M4 ;
        RECT  -0.072 141.648 0.072 141.672 ;
    END
  END capture_record[284]
  PIN capture_record[285]
    DIRECTION INPUT ;
    USE SIGNAL ;
    PORT
      LAYER M4 ;
        RECT  -0.072 142.128 0.072 142.152 ;
    END
  END capture_record[285]
  PIN capture_record[286]
    DIRECTION INPUT ;
    USE SIGNAL ;
    PORT
      LAYER M4 ;
        RECT  -0.072 142.608 0.072 142.632 ;
    END
  END capture_record[286]
  PIN capture_record[287]
    DIRECTION INPUT ;
    USE SIGNAL ;
    PORT
      LAYER M4 ;
        RECT  -0.072 143.04 0.072 143.064 ;
    END
  END capture_record[287]
  PIN capture_record[288]
    DIRECTION INPUT ;
    USE SIGNAL ;
    PORT
      LAYER M4 ;
        RECT  -0.072 143.52 0.072 143.544 ;
    END
  END capture_record[288]
  PIN capture_record[289]
    DIRECTION INPUT ;
    USE SIGNAL ;
    PORT
      LAYER M4 ;
        RECT  -0.072 144 0.072 144.024 ;
    END
  END capture_record[289]
  PIN capture_record[28]
    DIRECTION INPUT ;
    USE SIGNAL ;
    PORT
      LAYER M4 ;
        RECT  -0.072 21.36 0.072 21.384 ;
    END
  END capture_record[28]
  PIN capture_record[290]
    DIRECTION INPUT ;
    USE SIGNAL ;
    PORT
      LAYER M4 ;
        RECT  -0.072 144.48 0.072 144.504 ;
    END
  END capture_record[290]
  PIN capture_record[291]
    DIRECTION INPUT ;
    USE SIGNAL ;
    PORT
      LAYER M4 ;
        RECT  -0.072 144.912 0.072 144.936 ;
    END
  END capture_record[291]
  PIN capture_record[292]
    DIRECTION INPUT ;
    USE SIGNAL ;
    PORT
      LAYER M4 ;
        RECT  -0.072 145.392 0.072 145.416 ;
    END
  END capture_record[292]
  PIN capture_record[293]
    DIRECTION INPUT ;
    USE SIGNAL ;
    PORT
      LAYER M4 ;
        RECT  -0.072 145.872 0.072 145.896 ;
    END
  END capture_record[293]
  PIN capture_record[294]
    DIRECTION INPUT ;
    USE SIGNAL ;
    PORT
      LAYER M4 ;
        RECT  -0.072 146.352 0.072 146.376 ;
    END
  END capture_record[294]
  PIN capture_record[295]
    DIRECTION INPUT ;
    USE SIGNAL ;
    PORT
      LAYER M4 ;
        RECT  -0.072 146.832 0.072 146.856 ;
    END
  END capture_record[295]
  PIN capture_record[296]
    DIRECTION INPUT ;
    USE SIGNAL ;
    PORT
      LAYER M4 ;
        RECT  -0.072 147.264 0.072 147.288 ;
    END
  END capture_record[296]
  PIN capture_record[297]
    DIRECTION INPUT ;
    USE SIGNAL ;
    PORT
      LAYER M4 ;
        RECT  -0.072 147.744 0.072 147.768 ;
    END
  END capture_record[297]
  PIN capture_record[29]
    DIRECTION INPUT ;
    USE SIGNAL ;
    PORT
      LAYER M4 ;
        RECT  -0.072 21.84 0.072 21.864 ;
    END
  END capture_record[29]
  PIN capture_record[2]
    DIRECTION INPUT ;
    USE SIGNAL ;
    PORT
      LAYER M4 ;
        RECT  -0.072 9.168 0.072 9.192 ;
    END
  END capture_record[2]
  PIN capture_record[30]
    DIRECTION INPUT ;
    USE SIGNAL ;
    PORT
      LAYER M4 ;
        RECT  -0.072 22.32 0.072 22.344 ;
    END
  END capture_record[30]
  PIN capture_record[31]
    DIRECTION INPUT ;
    USE SIGNAL ;
    PORT
      LAYER M4 ;
        RECT  -0.072 22.8 0.072 22.824 ;
    END
  END capture_record[31]
  PIN capture_record[32]
    DIRECTION INPUT ;
    USE SIGNAL ;
    PORT
      LAYER M4 ;
        RECT  -0.072 23.28 0.072 23.304 ;
    END
  END capture_record[32]
  PIN capture_record[33]
    DIRECTION INPUT ;
    USE SIGNAL ;
    PORT
      LAYER M4 ;
        RECT  -0.072 23.712 0.072 23.736 ;
    END
  END capture_record[33]
  PIN capture_record[34]
    DIRECTION INPUT ;
    USE SIGNAL ;
    PORT
      LAYER M4 ;
        RECT  -0.072 24.192 0.072 24.216 ;
    END
  END capture_record[34]
  PIN capture_record[35]
    DIRECTION INPUT ;
    USE SIGNAL ;
    PORT
      LAYER M4 ;
        RECT  -0.072 24.672 0.072 24.696 ;
    END
  END capture_record[35]
  PIN capture_record[36]
    DIRECTION INPUT ;
    USE SIGNAL ;
    PORT
      LAYER M4 ;
        RECT  -0.072 25.152 0.072 25.176 ;
    END
  END capture_record[36]
  PIN capture_record[37]
    DIRECTION INPUT ;
    USE SIGNAL ;
    PORT
      LAYER M4 ;
        RECT  -0.072 25.584 0.072 25.608 ;
    END
  END capture_record[37]
  PIN capture_record[38]
    DIRECTION INPUT ;
    USE SIGNAL ;
    PORT
      LAYER M4 ;
        RECT  -0.072 26.064 0.072 26.088 ;
    END
  END capture_record[38]
  PIN capture_record[39]
    DIRECTION INPUT ;
    USE SIGNAL ;
    PORT
      LAYER M4 ;
        RECT  -0.072 26.544 0.072 26.568 ;
    END
  END capture_record[39]
  PIN capture_record[3]
    DIRECTION INPUT ;
    USE SIGNAL ;
    PORT
      LAYER M4 ;
        RECT  -0.072 9.648 0.072 9.672 ;
    END
  END capture_record[3]
  PIN capture_record[40]
    DIRECTION INPUT ;
    USE SIGNAL ;
    PORT
      LAYER M4 ;
        RECT  -0.072 27.024 0.072 27.048 ;
    END
  END capture_record[40]
  PIN capture_record[41]
    DIRECTION INPUT ;
    USE SIGNAL ;
    PORT
      LAYER M4 ;
        RECT  -0.072 27.504 0.072 27.528 ;
    END
  END capture_record[41]
  PIN capture_record[42]
    DIRECTION INPUT ;
    USE SIGNAL ;
    PORT
      LAYER M4 ;
        RECT  -0.072 27.936 0.072 27.96 ;
    END
  END capture_record[42]
  PIN capture_record[43]
    DIRECTION INPUT ;
    USE SIGNAL ;
    PORT
      LAYER M4 ;
        RECT  -0.072 28.416 0.072 28.44 ;
    END
  END capture_record[43]
  PIN capture_record[44]
    DIRECTION INPUT ;
    USE SIGNAL ;
    PORT
      LAYER M4 ;
        RECT  -0.072 28.896 0.072 28.92 ;
    END
  END capture_record[44]
  PIN capture_record[45]
    DIRECTION INPUT ;
    USE SIGNAL ;
    PORT
      LAYER M4 ;
        RECT  -0.072 29.376 0.072 29.4 ;
    END
  END capture_record[45]
  PIN capture_record[46]
    DIRECTION INPUT ;
    USE SIGNAL ;
    PORT
      LAYER M4 ;
        RECT  -0.072 29.856 0.072 29.88 ;
    END
  END capture_record[46]
  PIN capture_record[47]
    DIRECTION INPUT ;
    USE SIGNAL ;
    PORT
      LAYER M4 ;
        RECT  -0.072 30.288 0.072 30.312 ;
    END
  END capture_record[47]
  PIN capture_record[48]
    DIRECTION INPUT ;
    USE SIGNAL ;
    PORT
      LAYER M4 ;
        RECT  -0.072 30.768 0.072 30.792 ;
    END
  END capture_record[48]
  PIN capture_record[49]
    DIRECTION INPUT ;
    USE SIGNAL ;
    PORT
      LAYER M4 ;
        RECT  -0.072 31.248 0.072 31.272 ;
    END
  END capture_record[49]
  PIN capture_record[4]
    DIRECTION INPUT ;
    USE SIGNAL ;
    PORT
      LAYER M4 ;
        RECT  -0.072 10.08 0.072 10.104 ;
    END
  END capture_record[4]
  PIN capture_record[50]
    DIRECTION INPUT ;
    USE SIGNAL ;
    PORT
      LAYER M4 ;
        RECT  -0.072 31.728 0.072 31.752 ;
    END
  END capture_record[50]
  PIN capture_record[51]
    DIRECTION INPUT ;
    USE SIGNAL ;
    PORT
      LAYER M4 ;
        RECT  -0.072 32.16 0.072 32.184 ;
    END
  END capture_record[51]
  PIN capture_record[52]
    DIRECTION INPUT ;
    USE SIGNAL ;
    PORT
      LAYER M4 ;
        RECT  -0.072 32.64 0.072 32.664 ;
    END
  END capture_record[52]
  PIN capture_record[53]
    DIRECTION INPUT ;
    USE SIGNAL ;
    PORT
      LAYER M4 ;
        RECT  -0.072 33.12 0.072 33.144 ;
    END
  END capture_record[53]
  PIN capture_record[54]
    DIRECTION INPUT ;
    USE SIGNAL ;
    PORT
      LAYER M4 ;
        RECT  -0.072 33.6 0.072 33.624 ;
    END
  END capture_record[54]
  PIN capture_record[55]
    DIRECTION INPUT ;
    USE SIGNAL ;
    PORT
      LAYER M4 ;
        RECT  -0.072 34.08 0.072 34.104 ;
    END
  END capture_record[55]
  PIN capture_record[56]
    DIRECTION INPUT ;
    USE SIGNAL ;
    PORT
      LAYER M4 ;
        RECT  -0.072 34.512 0.072 34.536 ;
    END
  END capture_record[56]
  PIN capture_record[57]
    DIRECTION INPUT ;
    USE SIGNAL ;
    PORT
      LAYER M4 ;
        RECT  -0.072 34.992 0.072 35.016 ;
    END
  END capture_record[57]
  PIN capture_record[58]
    DIRECTION INPUT ;
    USE SIGNAL ;
    PORT
      LAYER M4 ;
        RECT  -0.072 35.472 0.072 35.496 ;
    END
  END capture_record[58]
  PIN capture_record[59]
    DIRECTION INPUT ;
    USE SIGNAL ;
    PORT
      LAYER M4 ;
        RECT  -0.072 35.952 0.072 35.976 ;
    END
  END capture_record[59]
  PIN capture_record[5]
    DIRECTION INPUT ;
    USE SIGNAL ;
    PORT
      LAYER M4 ;
        RECT  -0.072 10.56 0.072 10.584 ;
    END
  END capture_record[5]
  PIN capture_record[60]
    DIRECTION INPUT ;
    USE SIGNAL ;
    PORT
      LAYER M4 ;
        RECT  -0.072 36.432 0.072 36.456 ;
    END
  END capture_record[60]
  PIN capture_record[61]
    DIRECTION INPUT ;
    USE SIGNAL ;
    PORT
      LAYER M4 ;
        RECT  -0.072 36.864 0.072 36.888 ;
    END
  END capture_record[61]
  PIN capture_record[62]
    DIRECTION INPUT ;
    USE SIGNAL ;
    PORT
      LAYER M4 ;
        RECT  -0.072 37.344 0.072 37.368 ;
    END
  END capture_record[62]
  PIN capture_record[63]
    DIRECTION INPUT ;
    USE SIGNAL ;
    PORT
      LAYER M4 ;
        RECT  -0.072 37.824 0.072 37.848 ;
    END
  END capture_record[63]
  PIN capture_record[64]
    DIRECTION INPUT ;
    USE SIGNAL ;
    PORT
      LAYER M4 ;
        RECT  -0.072 38.304 0.072 38.328 ;
    END
  END capture_record[64]
  PIN capture_record[65]
    DIRECTION INPUT ;
    USE SIGNAL ;
    PORT
      LAYER M4 ;
        RECT  -0.072 38.736 0.072 38.76 ;
    END
  END capture_record[65]
  PIN capture_record[66]
    DIRECTION INPUT ;
    USE SIGNAL ;
    PORT
      LAYER M4 ;
        RECT  -0.072 39.216 0.072 39.24 ;
    END
  END capture_record[66]
  PIN capture_record[67]
    DIRECTION INPUT ;
    USE SIGNAL ;
    PORT
      LAYER M4 ;
        RECT  -0.072 39.696 0.072 39.72 ;
    END
  END capture_record[67]
  PIN capture_record[68]
    DIRECTION INPUT ;
    USE SIGNAL ;
    PORT
      LAYER M4 ;
        RECT  -0.072 40.176 0.072 40.2 ;
    END
  END capture_record[68]
  PIN capture_record[69]
    DIRECTION INPUT ;
    USE SIGNAL ;
    PORT
      LAYER M4 ;
        RECT  -0.072 40.656 0.072 40.68 ;
    END
  END capture_record[69]
  PIN capture_record[6]
    DIRECTION INPUT ;
    USE SIGNAL ;
    PORT
      LAYER M4 ;
        RECT  -0.072 11.04 0.072 11.064 ;
    END
  END capture_record[6]
  PIN capture_record[70]
    DIRECTION INPUT ;
    USE SIGNAL ;
    PORT
      LAYER M4 ;
        RECT  -0.072 41.088 0.072 41.112 ;
    END
  END capture_record[70]
  PIN capture_record[71]
    DIRECTION INPUT ;
    USE SIGNAL ;
    PORT
      LAYER M4 ;
        RECT  -0.072 41.568 0.072 41.592 ;
    END
  END capture_record[71]
  PIN capture_record[72]
    DIRECTION INPUT ;
    USE SIGNAL ;
    PORT
      LAYER M4 ;
        RECT  -0.072 42.048 0.072 42.072 ;
    END
  END capture_record[72]
  PIN capture_record[73]
    DIRECTION INPUT ;
    USE SIGNAL ;
    PORT
      LAYER M4 ;
        RECT  -0.072 42.528 0.072 42.552 ;
    END
  END capture_record[73]
  PIN capture_record[74]
    DIRECTION INPUT ;
    USE SIGNAL ;
    PORT
      LAYER M4 ;
        RECT  -0.072 43.008 0.072 43.032 ;
    END
  END capture_record[74]
  PIN capture_record[75]
    DIRECTION INPUT ;
    USE SIGNAL ;
    PORT
      LAYER M4 ;
        RECT  -0.072 43.44 0.072 43.464 ;
    END
  END capture_record[75]
  PIN capture_record[76]
    DIRECTION INPUT ;
    USE SIGNAL ;
    PORT
      LAYER M4 ;
        RECT  -0.072 43.92 0.072 43.944 ;
    END
  END capture_record[76]
  PIN capture_record[77]
    DIRECTION INPUT ;
    USE SIGNAL ;
    PORT
      LAYER M4 ;
        RECT  -0.072 44.4 0.072 44.424 ;
    END
  END capture_record[77]
  PIN capture_record[78]
    DIRECTION INPUT ;
    USE SIGNAL ;
    PORT
      LAYER M4 ;
        RECT  -0.072 44.88 0.072 44.904 ;
    END
  END capture_record[78]
  PIN capture_record[79]
    DIRECTION INPUT ;
    USE SIGNAL ;
    PORT
      LAYER M4 ;
        RECT  -0.072 45.36 0.072 45.384 ;
    END
  END capture_record[79]
  PIN capture_record[7]
    DIRECTION INPUT ;
    USE SIGNAL ;
    PORT
      LAYER M4 ;
        RECT  -0.072 11.52 0.072 11.544 ;
    END
  END capture_record[7]
  PIN capture_record[80]
    DIRECTION INPUT ;
    USE SIGNAL ;
    PORT
      LAYER M4 ;
        RECT  -0.072 45.792 0.072 45.816 ;
    END
  END capture_record[80]
  PIN capture_record[81]
    DIRECTION INPUT ;
    USE SIGNAL ;
    PORT
      LAYER M4 ;
        RECT  -0.072 46.272 0.072 46.296 ;
    END
  END capture_record[81]
  PIN capture_record[82]
    DIRECTION INPUT ;
    USE SIGNAL ;
    PORT
      LAYER M4 ;
        RECT  -0.072 46.752 0.072 46.776 ;
    END
  END capture_record[82]
  PIN capture_record[83]
    DIRECTION INPUT ;
    USE SIGNAL ;
    PORT
      LAYER M4 ;
        RECT  -0.072 47.232 0.072 47.256 ;
    END
  END capture_record[83]
  PIN capture_record[84]
    DIRECTION INPUT ;
    USE SIGNAL ;
    PORT
      LAYER M4 ;
        RECT  -0.072 47.664 0.072 47.688 ;
    END
  END capture_record[84]
  PIN capture_record[85]
    DIRECTION INPUT ;
    USE SIGNAL ;
    PORT
      LAYER M4 ;
        RECT  -0.072 48.144 0.072 48.168 ;
    END
  END capture_record[85]
  PIN capture_record[86]
    DIRECTION INPUT ;
    USE SIGNAL ;
    PORT
      LAYER M4 ;
        RECT  -0.072 48.624 0.072 48.648 ;
    END
  END capture_record[86]
  PIN capture_record[87]
    DIRECTION INPUT ;
    USE SIGNAL ;
    PORT
      LAYER M4 ;
        RECT  -0.072 49.104 0.072 49.128 ;
    END
  END capture_record[87]
  PIN capture_record[88]
    DIRECTION INPUT ;
    USE SIGNAL ;
    PORT
      LAYER M4 ;
        RECT  -0.072 49.584 0.072 49.608 ;
    END
  END capture_record[88]
  PIN capture_record[89]
    DIRECTION INPUT ;
    USE SIGNAL ;
    PORT
      LAYER M4 ;
        RECT  -0.072 50.016 0.072 50.04 ;
    END
  END capture_record[89]
  PIN capture_record[8]
    DIRECTION INPUT ;
    USE SIGNAL ;
    PORT
      LAYER M4 ;
        RECT  -0.072 12 0.072 12.024 ;
    END
  END capture_record[8]
  PIN capture_record[90]
    DIRECTION INPUT ;
    USE SIGNAL ;
    PORT
      LAYER M4 ;
        RECT  -0.072 50.496 0.072 50.52 ;
    END
  END capture_record[90]
  PIN capture_record[91]
    DIRECTION INPUT ;
    USE SIGNAL ;
    PORT
      LAYER M4 ;
        RECT  -0.072 50.976 0.072 51 ;
    END
  END capture_record[91]
  PIN capture_record[92]
    DIRECTION INPUT ;
    USE SIGNAL ;
    PORT
      LAYER M4 ;
        RECT  -0.072 51.456 0.072 51.48 ;
    END
  END capture_record[92]
  PIN capture_record[93]
    DIRECTION INPUT ;
    USE SIGNAL ;
    PORT
      LAYER M4 ;
        RECT  -0.072 51.936 0.072 51.96 ;
    END
  END capture_record[93]
  PIN capture_record[94]
    DIRECTION INPUT ;
    USE SIGNAL ;
    PORT
      LAYER M4 ;
        RECT  -0.072 52.368 0.072 52.392 ;
    END
  END capture_record[94]
  PIN capture_record[95]
    DIRECTION INPUT ;
    USE SIGNAL ;
    PORT
      LAYER M4 ;
        RECT  -0.072 52.848 0.072 52.872 ;
    END
  END capture_record[95]
  PIN capture_record[96]
    DIRECTION INPUT ;
    USE SIGNAL ;
    PORT
      LAYER M4 ;
        RECT  -0.072 53.328 0.072 53.352 ;
    END
  END capture_record[96]
  PIN capture_record[97]
    DIRECTION INPUT ;
    USE SIGNAL ;
    PORT
      LAYER M4 ;
        RECT  -0.072 53.808 0.072 53.832 ;
    END
  END capture_record[97]
  PIN capture_record[98]
    DIRECTION INPUT ;
    USE SIGNAL ;
    PORT
      LAYER M4 ;
        RECT  -0.072 54.24 0.072 54.264 ;
    END
  END capture_record[98]
  PIN capture_record[99]
    DIRECTION INPUT ;
    USE SIGNAL ;
    PORT
      LAYER M4 ;
        RECT  -0.072 54.72 0.072 54.744 ;
    END
  END capture_record[99]
  PIN capture_record[9]
    DIRECTION INPUT ;
    USE SIGNAL ;
    PORT
      LAYER M4 ;
        RECT  -0.072 12.432 0.072 12.456 ;
    END
  END capture_record[9]
  PIN capture_slot
    DIRECTION INPUT ;
    USE SIGNAL ;
    PORT
      LAYER M4 ;
        RECT  64.728 25.008 64.872 25.032 ;
    END
    PORT
      LAYER M4 ;
        RECT  63.241 25.008 64.764 25.032 ;
    END
  END capture_slot
  PIN capture_v
    DIRECTION INPUT ;
    USE SIGNAL ;
    PORT
      LAYER M4 ;
        RECT  -0.072 154.992 0.072 155.016 ;
    END
    PORT
      LAYER M4 ;
        RECT  0.06 154.992 2.408 155.016 ;
    END
  END capture_v
  PIN ck
    DIRECTION INPUT ;
    USE SIGNAL ;
    PORT
      LAYER M4 ;
        RECT  64.728 8.976 64.872 9 ;
    END
    PORT
      LAYER M4 ;
        RECT  62.104 8.976 64.764 9 ;
    END
  END ck
  PIN fault
    DIRECTION OUTPUT ;
    USE SIGNAL ;
    PORT
      LAYER M4 ;
        RECT  64.728 40.992 64.872 41.016 ;
    END
    PORT
      LAYER M4 ;
        RECT  63.277 40.992 64.764 41.016 ;
    END
  END fault
  PIN rst_n
    DIRECTION INPUT ;
    USE SIGNAL ;
    PORT
      LAYER M4 ;
        RECT  64.728 16.992 64.872 17.016 ;
    END
    PORT
      LAYER M4 ;
        RECT  63.817 16.992 64.764 17.016 ;
    END
  END rst_n
  PIN transfer_slot
    DIRECTION INPUT ;
    USE SIGNAL ;
    PORT
      LAYER M4 ;
        RECT  64.728 32.976 64.872 33 ;
    END
    PORT
      LAYER M4 ;
        RECT  63.817 32.976 64.764 33 ;
    END
  END transfer_slot
  PIN upi[0]
    DIRECTION INPUT ;
    USE SIGNAL ;
    PORT
      LAYER M5 ;
        RECT  4.08 -0.072 4.104 0.072 ;
    END
  END upi[0]
  PIN upi[100]
    DIRECTION INPUT ;
    USE SIGNAL ;
    PORT
      LAYER M5 ;
        RECT  22.8 -0.072 22.824 0.072 ;
    END
  END upi[100]
  PIN upi[101]
    DIRECTION INPUT ;
    USE SIGNAL ;
    PORT
      LAYER M5 ;
        RECT  22.992 -0.072 23.016 0.072 ;
    END
  END upi[101]
  PIN upi[102]
    DIRECTION INPUT ;
    USE SIGNAL ;
    PORT
      LAYER M5 ;
        RECT  23.184 -0.072 23.208 0.072 ;
    END
  END upi[102]
  PIN upi[103]
    DIRECTION INPUT ;
    USE SIGNAL ;
    PORT
      LAYER M5 ;
        RECT  23.376 -0.072 23.4 0.072 ;
    END
  END upi[103]
  PIN upi[104]
    DIRECTION INPUT ;
    USE SIGNAL ;
    PORT
      LAYER M5 ;
        RECT  23.568 -0.072 23.592 0.072 ;
    END
  END upi[104]
  PIN upi[105]
    DIRECTION INPUT ;
    USE SIGNAL ;
    PORT
      LAYER M5 ;
        RECT  23.76 -0.072 23.784 0.072 ;
    END
  END upi[105]
  PIN upi[106]
    DIRECTION INPUT ;
    USE SIGNAL ;
    PORT
      LAYER M5 ;
        RECT  23.952 -0.072 23.976 0.072 ;
    END
  END upi[106]
  PIN upi[107]
    DIRECTION INPUT ;
    USE SIGNAL ;
    PORT
      LAYER M5 ;
        RECT  24.144 -0.072 24.168 0.072 ;
    END
  END upi[107]
  PIN upi[108]
    DIRECTION INPUT ;
    USE SIGNAL ;
    PORT
      LAYER M5 ;
        RECT  24.288 -0.072 24.312 0.072 ;
    END
  END upi[108]
  PIN upi[109]
    DIRECTION INPUT ;
    USE SIGNAL ;
    PORT
      LAYER M5 ;
        RECT  24.48 -0.072 24.504 0.072 ;
    END
  END upi[109]
  PIN upi[10]
    DIRECTION INPUT ;
    USE SIGNAL ;
    PORT
      LAYER M5 ;
        RECT  5.952 -0.072 5.976 0.072 ;
    END
  END upi[10]
  PIN upi[110]
    DIRECTION INPUT ;
    USE SIGNAL ;
    PORT
      LAYER M5 ;
        RECT  24.672 -0.072 24.696 0.072 ;
    END
  END upi[110]
  PIN upi[111]
    DIRECTION INPUT ;
    USE SIGNAL ;
    PORT
      LAYER M5 ;
        RECT  24.864 -0.072 24.888 0.072 ;
    END
  END upi[111]
  PIN upi[112]
    DIRECTION INPUT ;
    USE SIGNAL ;
    PORT
      LAYER M5 ;
        RECT  25.056 -0.072 25.08 0.072 ;
    END
  END upi[112]
  PIN upi[113]
    DIRECTION INPUT ;
    USE SIGNAL ;
    PORT
      LAYER M5 ;
        RECT  25.248 -0.072 25.272 0.072 ;
    END
  END upi[113]
  PIN upi[114]
    DIRECTION INPUT ;
    USE SIGNAL ;
    PORT
      LAYER M5 ;
        RECT  25.44 -0.072 25.464 0.072 ;
    END
  END upi[114]
  PIN upi[115]
    DIRECTION INPUT ;
    USE SIGNAL ;
    PORT
      LAYER M5 ;
        RECT  25.632 -0.072 25.656 0.072 ;
    END
  END upi[115]
  PIN upi[116]
    DIRECTION INPUT ;
    USE SIGNAL ;
    PORT
      LAYER M5 ;
        RECT  25.824 -0.072 25.848 0.072 ;
    END
  END upi[116]
  PIN upi[117]
    DIRECTION INPUT ;
    USE SIGNAL ;
    PORT
      LAYER M5 ;
        RECT  26.016 -0.072 26.04 0.072 ;
    END
  END upi[117]
  PIN upi[118]
    DIRECTION INPUT ;
    USE SIGNAL ;
    PORT
      LAYER M5 ;
        RECT  26.16 -0.072 26.184 0.072 ;
    END
  END upi[118]
  PIN upi[119]
    DIRECTION INPUT ;
    USE SIGNAL ;
    PORT
      LAYER M5 ;
        RECT  26.352 -0.072 26.376 0.072 ;
    END
  END upi[119]
  PIN upi[11]
    DIRECTION INPUT ;
    USE SIGNAL ;
    PORT
      LAYER M5 ;
        RECT  6.144 -0.072 6.168 0.072 ;
    END
  END upi[11]
  PIN upi[120]
    DIRECTION INPUT ;
    USE SIGNAL ;
    PORT
      LAYER M5 ;
        RECT  26.544 -0.072 26.568 0.072 ;
    END
  END upi[120]
  PIN upi[121]
    DIRECTION INPUT ;
    USE SIGNAL ;
    PORT
      LAYER M5 ;
        RECT  26.736 -0.072 26.76 0.072 ;
    END
  END upi[121]
  PIN upi[122]
    DIRECTION INPUT ;
    USE SIGNAL ;
    PORT
      LAYER M5 ;
        RECT  26.928 -0.072 26.952 0.072 ;
    END
  END upi[122]
  PIN upi[123]
    DIRECTION INPUT ;
    USE SIGNAL ;
    PORT
      LAYER M5 ;
        RECT  27.12 -0.072 27.144 0.072 ;
    END
  END upi[123]
  PIN upi[124]
    DIRECTION INPUT ;
    USE SIGNAL ;
    PORT
      LAYER M5 ;
        RECT  27.312 -0.072 27.336 0.072 ;
    END
  END upi[124]
  PIN upi[125]
    DIRECTION INPUT ;
    USE SIGNAL ;
    PORT
      LAYER M5 ;
        RECT  27.504 -0.072 27.528 0.072 ;
    END
  END upi[125]
  PIN upi[126]
    DIRECTION INPUT ;
    USE SIGNAL ;
    PORT
      LAYER M5 ;
        RECT  27.696 -0.072 27.72 0.072 ;
    END
  END upi[126]
  PIN upi[127]
    DIRECTION INPUT ;
    USE SIGNAL ;
    PORT
      LAYER M5 ;
        RECT  27.888 -0.072 27.912 0.072 ;
    END
  END upi[127]
  PIN upi[128]
    DIRECTION INPUT ;
    USE SIGNAL ;
    PORT
      LAYER M5 ;
        RECT  28.032 -0.072 28.056 0.072 ;
    END
  END upi[128]
  PIN upi[129]
    DIRECTION INPUT ;
    USE SIGNAL ;
    PORT
      LAYER M5 ;
        RECT  28.224 -0.072 28.248 0.072 ;
    END
  END upi[129]
  PIN upi[12]
    DIRECTION INPUT ;
    USE SIGNAL ;
    PORT
      LAYER M5 ;
        RECT  6.336 -0.072 6.36 0.072 ;
    END
  END upi[12]
  PIN upi[130]
    DIRECTION INPUT ;
    USE SIGNAL ;
    PORT
      LAYER M5 ;
        RECT  28.416 -0.072 28.44 0.072 ;
    END
  END upi[130]
  PIN upi[131]
    DIRECTION INPUT ;
    USE SIGNAL ;
    PORT
      LAYER M5 ;
        RECT  28.608 -0.072 28.632 0.072 ;
    END
  END upi[131]
  PIN upi[132]
    DIRECTION INPUT ;
    USE SIGNAL ;
    PORT
      LAYER M5 ;
        RECT  28.8 -0.072 28.824 0.072 ;
    END
  END upi[132]
  PIN upi[133]
    DIRECTION INPUT ;
    USE SIGNAL ;
    PORT
      LAYER M5 ;
        RECT  28.992 -0.072 29.016 0.072 ;
    END
  END upi[133]
  PIN upi[134]
    DIRECTION INPUT ;
    USE SIGNAL ;
    PORT
      LAYER M5 ;
        RECT  29.184 -0.072 29.208 0.072 ;
    END
  END upi[134]
  PIN upi[135]
    DIRECTION INPUT ;
    USE SIGNAL ;
    PORT
      LAYER M5 ;
        RECT  29.376 -0.072 29.4 0.072 ;
    END
  END upi[135]
  PIN upi[136]
    DIRECTION INPUT ;
    USE SIGNAL ;
    PORT
      LAYER M5 ;
        RECT  29.568 -0.072 29.592 0.072 ;
    END
  END upi[136]
  PIN upi[137]
    DIRECTION INPUT ;
    USE SIGNAL ;
    PORT
      LAYER M5 ;
        RECT  29.76 -0.072 29.784 0.072 ;
    END
  END upi[137]
  PIN upi[138]
    DIRECTION INPUT ;
    USE SIGNAL ;
    PORT
      LAYER M5 ;
        RECT  29.904 -0.072 29.928 0.072 ;
    END
  END upi[138]
  PIN upi[139]
    DIRECTION INPUT ;
    USE SIGNAL ;
    PORT
      LAYER M5 ;
        RECT  30.096 -0.072 30.12 0.072 ;
    END
  END upi[139]
  PIN upi[13]
    DIRECTION INPUT ;
    USE SIGNAL ;
    PORT
      LAYER M5 ;
        RECT  6.528 -0.072 6.552 0.072 ;
    END
  END upi[13]
  PIN upi[140]
    DIRECTION INPUT ;
    USE SIGNAL ;
    PORT
      LAYER M5 ;
        RECT  30.288 -0.072 30.312 0.072 ;
    END
  END upi[140]
  PIN upi[141]
    DIRECTION INPUT ;
    USE SIGNAL ;
    PORT
      LAYER M5 ;
        RECT  30.48 -0.072 30.504 0.072 ;
    END
  END upi[141]
  PIN upi[142]
    DIRECTION INPUT ;
    USE SIGNAL ;
    PORT
      LAYER M5 ;
        RECT  30.672 -0.072 30.696 0.072 ;
    END
  END upi[142]
  PIN upi[143]
    DIRECTION INPUT ;
    USE SIGNAL ;
    PORT
      LAYER M5 ;
        RECT  30.864 -0.072 30.888 0.072 ;
    END
  END upi[143]
  PIN upi[144]
    DIRECTION INPUT ;
    USE SIGNAL ;
    PORT
      LAYER M5 ;
        RECT  31.056 -0.072 31.08 0.072 ;
    END
  END upi[144]
  PIN upi[145]
    DIRECTION INPUT ;
    USE SIGNAL ;
    PORT
      LAYER M5 ;
        RECT  31.248 -0.072 31.272 0.072 ;
    END
  END upi[145]
  PIN upi[146]
    DIRECTION INPUT ;
    USE SIGNAL ;
    PORT
      LAYER M5 ;
        RECT  31.44 -0.072 31.464 0.072 ;
    END
  END upi[146]
  PIN upi[147]
    DIRECTION INPUT ;
    USE SIGNAL ;
    PORT
      LAYER M5 ;
        RECT  31.632 -0.072 31.656 0.072 ;
    END
  END upi[147]
  PIN upi[148]
    DIRECTION INPUT ;
    USE SIGNAL ;
    PORT
      LAYER M5 ;
        RECT  31.824 -0.072 31.848 0.072 ;
    END
  END upi[148]
  PIN upi[149]
    DIRECTION INPUT ;
    USE SIGNAL ;
    PORT
      LAYER M5 ;
        RECT  31.968 -0.072 31.992 0.072 ;
    END
  END upi[149]
  PIN upi[14]
    DIRECTION INPUT ;
    USE SIGNAL ;
    PORT
      LAYER M5 ;
        RECT  6.72 -0.072 6.744 0.072 ;
    END
  END upi[14]
  PIN upi[150]
    DIRECTION INPUT ;
    USE SIGNAL ;
    PORT
      LAYER M5 ;
        RECT  32.16 -0.072 32.184 0.072 ;
    END
  END upi[150]
  PIN upi[151]
    DIRECTION INPUT ;
    USE SIGNAL ;
    PORT
      LAYER M5 ;
        RECT  32.352 -0.072 32.376 0.072 ;
    END
  END upi[151]
  PIN upi[152]
    DIRECTION INPUT ;
    USE SIGNAL ;
    PORT
      LAYER M5 ;
        RECT  32.544 -0.072 32.568 0.072 ;
    END
  END upi[152]
  PIN upi[153]
    DIRECTION INPUT ;
    USE SIGNAL ;
    PORT
      LAYER M5 ;
        RECT  32.736 -0.072 32.76 0.072 ;
    END
  END upi[153]
  PIN upi[154]
    DIRECTION INPUT ;
    USE SIGNAL ;
    PORT
      LAYER M5 ;
        RECT  32.928 -0.072 32.952 0.072 ;
    END
  END upi[154]
  PIN upi[155]
    DIRECTION INPUT ;
    USE SIGNAL ;
    PORT
      LAYER M5 ;
        RECT  33.12 -0.072 33.144 0.072 ;
    END
  END upi[155]
  PIN upi[156]
    DIRECTION INPUT ;
    USE SIGNAL ;
    PORT
      LAYER M5 ;
        RECT  33.312 -0.072 33.336 0.072 ;
    END
  END upi[156]
  PIN upi[157]
    DIRECTION INPUT ;
    USE SIGNAL ;
    PORT
      LAYER M5 ;
        RECT  33.504 -0.072 33.528 0.072 ;
    END
  END upi[157]
  PIN upi[158]
    DIRECTION INPUT ;
    USE SIGNAL ;
    PORT
      LAYER M5 ;
        RECT  33.696 -0.072 33.72 0.072 ;
    END
  END upi[158]
  PIN upi[159]
    DIRECTION INPUT ;
    USE SIGNAL ;
    PORT
      LAYER M5 ;
        RECT  33.84 -0.072 33.864 0.072 ;
    END
  END upi[159]
  PIN upi[15]
    DIRECTION INPUT ;
    USE SIGNAL ;
    PORT
      LAYER M5 ;
        RECT  6.912 -0.072 6.936 0.072 ;
    END
  END upi[15]
  PIN upi[160]
    DIRECTION INPUT ;
    USE SIGNAL ;
    PORT
      LAYER M5 ;
        RECT  34.032 -0.072 34.056 0.072 ;
    END
  END upi[160]
  PIN upi[161]
    DIRECTION INPUT ;
    USE SIGNAL ;
    PORT
      LAYER M5 ;
        RECT  34.224 -0.072 34.248 0.072 ;
    END
  END upi[161]
  PIN upi[162]
    DIRECTION INPUT ;
    USE SIGNAL ;
    PORT
      LAYER M5 ;
        RECT  34.416 -0.072 34.44 0.072 ;
    END
  END upi[162]
  PIN upi[163]
    DIRECTION INPUT ;
    USE SIGNAL ;
    PORT
      LAYER M5 ;
        RECT  34.608 -0.072 34.632 0.072 ;
    END
  END upi[163]
  PIN upi[164]
    DIRECTION INPUT ;
    USE SIGNAL ;
    PORT
      LAYER M5 ;
        RECT  34.8 -0.072 34.824 0.072 ;
    END
  END upi[164]
  PIN upi[165]
    DIRECTION INPUT ;
    USE SIGNAL ;
    PORT
      LAYER M5 ;
        RECT  34.992 -0.072 35.016 0.072 ;
    END
  END upi[165]
  PIN upi[166]
    DIRECTION INPUT ;
    USE SIGNAL ;
    PORT
      LAYER M5 ;
        RECT  35.184 -0.072 35.208 0.072 ;
    END
  END upi[166]
  PIN upi[167]
    DIRECTION INPUT ;
    USE SIGNAL ;
    PORT
      LAYER M5 ;
        RECT  35.376 -0.072 35.4 0.072 ;
    END
  END upi[167]
  PIN upi[168]
    DIRECTION INPUT ;
    USE SIGNAL ;
    PORT
      LAYER M5 ;
        RECT  35.568 -0.072 35.592 0.072 ;
    END
  END upi[168]
  PIN upi[169]
    DIRECTION INPUT ;
    USE SIGNAL ;
    PORT
      LAYER M5 ;
        RECT  35.712 -0.072 35.736 0.072 ;
    END
  END upi[169]
  PIN upi[16]
    DIRECTION INPUT ;
    USE SIGNAL ;
    PORT
      LAYER M5 ;
        RECT  7.056 -0.072 7.08 0.072 ;
    END
  END upi[16]
  PIN upi[170]
    DIRECTION INPUT ;
    USE SIGNAL ;
    PORT
      LAYER M5 ;
        RECT  35.904 -0.072 35.928 0.072 ;
    END
  END upi[170]
  PIN upi[171]
    DIRECTION INPUT ;
    USE SIGNAL ;
    PORT
      LAYER M5 ;
        RECT  36.096 -0.072 36.12 0.072 ;
    END
  END upi[171]
  PIN upi[172]
    DIRECTION INPUT ;
    USE SIGNAL ;
    PORT
      LAYER M5 ;
        RECT  36.288 -0.072 36.312 0.072 ;
    END
  END upi[172]
  PIN upi[173]
    DIRECTION INPUT ;
    USE SIGNAL ;
    PORT
      LAYER M5 ;
        RECT  36.48 -0.072 36.504 0.072 ;
    END
  END upi[173]
  PIN upi[174]
    DIRECTION INPUT ;
    USE SIGNAL ;
    PORT
      LAYER M5 ;
        RECT  36.672 -0.072 36.696 0.072 ;
    END
  END upi[174]
  PIN upi[175]
    DIRECTION INPUT ;
    USE SIGNAL ;
    PORT
      LAYER M5 ;
        RECT  36.864 -0.072 36.888 0.072 ;
    END
  END upi[175]
  PIN upi[176]
    DIRECTION INPUT ;
    USE SIGNAL ;
    PORT
      LAYER M5 ;
        RECT  37.056 -0.072 37.08 0.072 ;
    END
  END upi[176]
  PIN upi[177]
    DIRECTION INPUT ;
    USE SIGNAL ;
    PORT
      LAYER M5 ;
        RECT  37.248 -0.072 37.272 0.072 ;
    END
  END upi[177]
  PIN upi[178]
    DIRECTION INPUT ;
    USE SIGNAL ;
    PORT
      LAYER M5 ;
        RECT  37.44 -0.072 37.464 0.072 ;
    END
  END upi[178]
  PIN upi[179]
    DIRECTION INPUT ;
    USE SIGNAL ;
    PORT
      LAYER M5 ;
        RECT  37.584 -0.072 37.608 0.072 ;
    END
  END upi[179]
  PIN upi[17]
    DIRECTION INPUT ;
    USE SIGNAL ;
    PORT
      LAYER M5 ;
        RECT  7.248 -0.072 7.272 0.072 ;
    END
  END upi[17]
  PIN upi[180]
    DIRECTION INPUT ;
    USE SIGNAL ;
    PORT
      LAYER M5 ;
        RECT  37.776 -0.072 37.8 0.072 ;
    END
  END upi[180]
  PIN upi[181]
    DIRECTION INPUT ;
    USE SIGNAL ;
    PORT
      LAYER M5 ;
        RECT  37.968 -0.072 37.992 0.072 ;
    END
  END upi[181]
  PIN upi[182]
    DIRECTION INPUT ;
    USE SIGNAL ;
    PORT
      LAYER M5 ;
        RECT  38.16 -0.072 38.184 0.072 ;
    END
  END upi[182]
  PIN upi[183]
    DIRECTION INPUT ;
    USE SIGNAL ;
    PORT
      LAYER M5 ;
        RECT  38.352 -0.072 38.376 0.072 ;
    END
  END upi[183]
  PIN upi[184]
    DIRECTION INPUT ;
    USE SIGNAL ;
    PORT
      LAYER M5 ;
        RECT  38.544 -0.072 38.568 0.072 ;
    END
  END upi[184]
  PIN upi[185]
    DIRECTION INPUT ;
    USE SIGNAL ;
    PORT
      LAYER M5 ;
        RECT  38.736 -0.072 38.76 0.072 ;
    END
  END upi[185]
  PIN upi[186]
    DIRECTION INPUT ;
    USE SIGNAL ;
    PORT
      LAYER M5 ;
        RECT  38.928 -0.072 38.952 0.072 ;
    END
  END upi[186]
  PIN upi[187]
    DIRECTION INPUT ;
    USE SIGNAL ;
    PORT
      LAYER M5 ;
        RECT  39.12 -0.072 39.144 0.072 ;
    END
  END upi[187]
  PIN upi[188]
    DIRECTION INPUT ;
    USE SIGNAL ;
    PORT
      LAYER M5 ;
        RECT  39.312 -0.072 39.336 0.072 ;
    END
  END upi[188]
  PIN upi[189]
    DIRECTION INPUT ;
    USE SIGNAL ;
    PORT
      LAYER M5 ;
        RECT  39.456 -0.072 39.48 0.072 ;
    END
  END upi[189]
  PIN upi[18]
    DIRECTION INPUT ;
    USE SIGNAL ;
    PORT
      LAYER M5 ;
        RECT  7.44 -0.072 7.464 0.072 ;
    END
  END upi[18]
  PIN upi[190]
    DIRECTION INPUT ;
    USE SIGNAL ;
    PORT
      LAYER M5 ;
        RECT  39.648 -0.072 39.672 0.072 ;
    END
  END upi[190]
  PIN upi[191]
    DIRECTION INPUT ;
    USE SIGNAL ;
    PORT
      LAYER M5 ;
        RECT  39.84 -0.072 39.864 0.072 ;
    END
  END upi[191]
  PIN upi[192]
    DIRECTION INPUT ;
    USE SIGNAL ;
    PORT
      LAYER M5 ;
        RECT  40.032 -0.072 40.056 0.072 ;
    END
  END upi[192]
  PIN upi[193]
    DIRECTION INPUT ;
    USE SIGNAL ;
    PORT
      LAYER M5 ;
        RECT  40.224 -0.072 40.248 0.072 ;
    END
  END upi[193]
  PIN upi[194]
    DIRECTION INPUT ;
    USE SIGNAL ;
    PORT
      LAYER M5 ;
        RECT  40.416 -0.072 40.44 0.072 ;
    END
  END upi[194]
  PIN upi[195]
    DIRECTION INPUT ;
    USE SIGNAL ;
    PORT
      LAYER M5 ;
        RECT  40.608 -0.072 40.632 0.072 ;
    END
  END upi[195]
  PIN upi[196]
    DIRECTION INPUT ;
    USE SIGNAL ;
    PORT
      LAYER M5 ;
        RECT  40.8 -0.072 40.824 0.072 ;
    END
  END upi[196]
  PIN upi[197]
    DIRECTION INPUT ;
    USE SIGNAL ;
    PORT
      LAYER M5 ;
        RECT  40.992 -0.072 41.016 0.072 ;
    END
  END upi[197]
  PIN upi[198]
    DIRECTION INPUT ;
    USE SIGNAL ;
    PORT
      LAYER M5 ;
        RECT  41.184 -0.072 41.208 0.072 ;
    END
  END upi[198]
  PIN upi[199]
    DIRECTION INPUT ;
    USE SIGNAL ;
    PORT
      LAYER M5 ;
        RECT  41.376 -0.072 41.4 0.072 ;
    END
  END upi[199]
  PIN upi[19]
    DIRECTION INPUT ;
    USE SIGNAL ;
    PORT
      LAYER M5 ;
        RECT  7.632 -0.072 7.656 0.072 ;
    END
  END upi[19]
  PIN upi[1]
    DIRECTION INPUT ;
    USE SIGNAL ;
    PORT
      LAYER M5 ;
        RECT  4.272 -0.072 4.296 0.072 ;
    END
  END upi[1]
  PIN upi[200]
    DIRECTION INPUT ;
    USE SIGNAL ;
    PORT
      LAYER M5 ;
        RECT  41.52 -0.072 41.544 0.072 ;
    END
  END upi[200]
  PIN upi[201]
    DIRECTION INPUT ;
    USE SIGNAL ;
    PORT
      LAYER M5 ;
        RECT  41.712 -0.072 41.736 0.072 ;
    END
  END upi[201]
  PIN upi[202]
    DIRECTION INPUT ;
    USE SIGNAL ;
    PORT
      LAYER M5 ;
        RECT  41.904 -0.072 41.928 0.072 ;
    END
  END upi[202]
  PIN upi[203]
    DIRECTION INPUT ;
    USE SIGNAL ;
    PORT
      LAYER M5 ;
        RECT  42.096 -0.072 42.12 0.072 ;
    END
  END upi[203]
  PIN upi[204]
    DIRECTION INPUT ;
    USE SIGNAL ;
    PORT
      LAYER M5 ;
        RECT  42.288 -0.072 42.312 0.072 ;
    END
  END upi[204]
  PIN upi[205]
    DIRECTION INPUT ;
    USE SIGNAL ;
    PORT
      LAYER M5 ;
        RECT  42.48 -0.072 42.504 0.072 ;
    END
  END upi[205]
  PIN upi[206]
    DIRECTION INPUT ;
    USE SIGNAL ;
    PORT
      LAYER M5 ;
        RECT  42.672 -0.072 42.696 0.072 ;
    END
  END upi[206]
  PIN upi[207]
    DIRECTION INPUT ;
    USE SIGNAL ;
    PORT
      LAYER M5 ;
        RECT  42.864 -0.072 42.888 0.072 ;
    END
  END upi[207]
  PIN upi[208]
    DIRECTION INPUT ;
    USE SIGNAL ;
    PORT
      LAYER M5 ;
        RECT  43.056 -0.072 43.08 0.072 ;
    END
  END upi[208]
  PIN upi[209]
    DIRECTION INPUT ;
    USE SIGNAL ;
    PORT
      LAYER M5 ;
        RECT  43.248 -0.072 43.272 0.072 ;
    END
  END upi[209]
  PIN upi[20]
    DIRECTION INPUT ;
    USE SIGNAL ;
    PORT
      LAYER M5 ;
        RECT  7.824 -0.072 7.848 0.072 ;
    END
  END upi[20]
  PIN upi[210]
    DIRECTION INPUT ;
    USE SIGNAL ;
    PORT
      LAYER M5 ;
        RECT  43.392 -0.072 43.416 0.072 ;
    END
  END upi[210]
  PIN upi[211]
    DIRECTION INPUT ;
    USE SIGNAL ;
    PORT
      LAYER M5 ;
        RECT  43.584 -0.072 43.608 0.072 ;
    END
  END upi[211]
  PIN upi[212]
    DIRECTION INPUT ;
    USE SIGNAL ;
    PORT
      LAYER M5 ;
        RECT  43.776 -0.072 43.8 0.072 ;
    END
  END upi[212]
  PIN upi[213]
    DIRECTION INPUT ;
    USE SIGNAL ;
    PORT
      LAYER M5 ;
        RECT  43.968 -0.072 43.992 0.072 ;
    END
  END upi[213]
  PIN upi[214]
    DIRECTION INPUT ;
    USE SIGNAL ;
    PORT
      LAYER M5 ;
        RECT  44.16 -0.072 44.184 0.072 ;
    END
  END upi[214]
  PIN upi[215]
    DIRECTION INPUT ;
    USE SIGNAL ;
    PORT
      LAYER M5 ;
        RECT  44.352 -0.072 44.376 0.072 ;
    END
  END upi[215]
  PIN upi[216]
    DIRECTION INPUT ;
    USE SIGNAL ;
    PORT
      LAYER M5 ;
        RECT  44.544 -0.072 44.568 0.072 ;
    END
  END upi[216]
  PIN upi[217]
    DIRECTION INPUT ;
    USE SIGNAL ;
    PORT
      LAYER M5 ;
        RECT  44.736 -0.072 44.76 0.072 ;
    END
  END upi[217]
  PIN upi[218]
    DIRECTION INPUT ;
    USE SIGNAL ;
    PORT
      LAYER M5 ;
        RECT  44.928 -0.072 44.952 0.072 ;
    END
  END upi[218]
  PIN upi[219]
    DIRECTION INPUT ;
    USE SIGNAL ;
    PORT
      LAYER M5 ;
        RECT  45.12 -0.072 45.144 0.072 ;
    END
  END upi[219]
  PIN upi[21]
    DIRECTION INPUT ;
    USE SIGNAL ;
    PORT
      LAYER M5 ;
        RECT  8.016 -0.072 8.04 0.072 ;
    END
  END upi[21]
  PIN upi[220]
    DIRECTION INPUT ;
    USE SIGNAL ;
    PORT
      LAYER M5 ;
        RECT  45.264 -0.072 45.288 0.072 ;
    END
  END upi[220]
  PIN upi[221]
    DIRECTION INPUT ;
    USE SIGNAL ;
    PORT
      LAYER M5 ;
        RECT  45.456 -0.072 45.48 0.072 ;
    END
  END upi[221]
  PIN upi[222]
    DIRECTION INPUT ;
    USE SIGNAL ;
    PORT
      LAYER M5 ;
        RECT  45.648 -0.072 45.672 0.072 ;
    END
  END upi[222]
  PIN upi[223]
    DIRECTION INPUT ;
    USE SIGNAL ;
    PORT
      LAYER M5 ;
        RECT  45.84 -0.072 45.864 0.072 ;
    END
  END upi[223]
  PIN upi[224]
    DIRECTION INPUT ;
    USE SIGNAL ;
    PORT
      LAYER M5 ;
        RECT  46.032 -0.072 46.056 0.072 ;
    END
  END upi[224]
  PIN upi[225]
    DIRECTION INPUT ;
    USE SIGNAL ;
    PORT
      LAYER M5 ;
        RECT  46.224 -0.072 46.248 0.072 ;
    END
  END upi[225]
  PIN upi[226]
    DIRECTION INPUT ;
    USE SIGNAL ;
    PORT
      LAYER M5 ;
        RECT  46.416 -0.072 46.44 0.072 ;
    END
  END upi[226]
  PIN upi[227]
    DIRECTION INPUT ;
    USE SIGNAL ;
    PORT
      LAYER M5 ;
        RECT  46.608 -0.072 46.632 0.072 ;
    END
  END upi[227]
  PIN upi[228]
    DIRECTION INPUT ;
    USE SIGNAL ;
    PORT
      LAYER M5 ;
        RECT  46.8 -0.072 46.824 0.072 ;
    END
  END upi[228]
  PIN upi[229]
    DIRECTION INPUT ;
    USE SIGNAL ;
    PORT
      LAYER M5 ;
        RECT  46.992 -0.072 47.016 0.072 ;
    END
  END upi[229]
  PIN upi[22]
    DIRECTION INPUT ;
    USE SIGNAL ;
    PORT
      LAYER M5 ;
        RECT  8.208 -0.072 8.232 0.072 ;
    END
  END upi[22]
  PIN upi[230]
    DIRECTION INPUT ;
    USE SIGNAL ;
    PORT
      LAYER M5 ;
        RECT  47.136 -0.072 47.16 0.072 ;
    END
  END upi[230]
  PIN upi[231]
    DIRECTION INPUT ;
    USE SIGNAL ;
    PORT
      LAYER M5 ;
        RECT  47.328 -0.072 47.352 0.072 ;
    END
  END upi[231]
  PIN upi[232]
    DIRECTION INPUT ;
    USE SIGNAL ;
    PORT
      LAYER M5 ;
        RECT  47.52 -0.072 47.544 0.072 ;
    END
  END upi[232]
  PIN upi[233]
    DIRECTION INPUT ;
    USE SIGNAL ;
    PORT
      LAYER M5 ;
        RECT  47.712 -0.072 47.736 0.072 ;
    END
  END upi[233]
  PIN upi[234]
    DIRECTION INPUT ;
    USE SIGNAL ;
    PORT
      LAYER M5 ;
        RECT  47.904 -0.072 47.928 0.072 ;
    END
  END upi[234]
  PIN upi[235]
    DIRECTION INPUT ;
    USE SIGNAL ;
    PORT
      LAYER M5 ;
        RECT  48.096 -0.072 48.12 0.072 ;
    END
  END upi[235]
  PIN upi[236]
    DIRECTION INPUT ;
    USE SIGNAL ;
    PORT
      LAYER M5 ;
        RECT  48.288 -0.072 48.312 0.072 ;
    END
  END upi[236]
  PIN upi[237]
    DIRECTION INPUT ;
    USE SIGNAL ;
    PORT
      LAYER M5 ;
        RECT  48.48 -0.072 48.504 0.072 ;
    END
  END upi[237]
  PIN upi[238]
    DIRECTION INPUT ;
    USE SIGNAL ;
    PORT
      LAYER M5 ;
        RECT  48.672 -0.072 48.696 0.072 ;
    END
  END upi[238]
  PIN upi[239]
    DIRECTION INPUT ;
    USE SIGNAL ;
    PORT
      LAYER M5 ;
        RECT  48.864 -0.072 48.888 0.072 ;
    END
  END upi[239]
  PIN upi[23]
    DIRECTION INPUT ;
    USE SIGNAL ;
    PORT
      LAYER M5 ;
        RECT  8.4 -0.072 8.424 0.072 ;
    END
  END upi[23]
  PIN upi[240]
    DIRECTION INPUT ;
    USE SIGNAL ;
    PORT
      LAYER M5 ;
        RECT  49.008 -0.072 49.032 0.072 ;
    END
  END upi[240]
  PIN upi[241]
    DIRECTION INPUT ;
    USE SIGNAL ;
    PORT
      LAYER M5 ;
        RECT  49.2 -0.072 49.224 0.072 ;
    END
  END upi[241]
  PIN upi[242]
    DIRECTION INPUT ;
    USE SIGNAL ;
    PORT
      LAYER M5 ;
        RECT  49.392 -0.072 49.416 0.072 ;
    END
  END upi[242]
  PIN upi[243]
    DIRECTION INPUT ;
    USE SIGNAL ;
    PORT
      LAYER M5 ;
        RECT  49.584 -0.072 49.608 0.072 ;
    END
  END upi[243]
  PIN upi[244]
    DIRECTION INPUT ;
    USE SIGNAL ;
    PORT
      LAYER M5 ;
        RECT  49.776 -0.072 49.8 0.072 ;
    END
  END upi[244]
  PIN upi[245]
    DIRECTION INPUT ;
    USE SIGNAL ;
    PORT
      LAYER M5 ;
        RECT  49.968 -0.072 49.992 0.072 ;
    END
  END upi[245]
  PIN upi[246]
    DIRECTION INPUT ;
    USE SIGNAL ;
    PORT
      LAYER M5 ;
        RECT  50.16 -0.072 50.184 0.072 ;
    END
  END upi[246]
  PIN upi[247]
    DIRECTION INPUT ;
    USE SIGNAL ;
    PORT
      LAYER M5 ;
        RECT  50.352 -0.072 50.376 0.072 ;
    END
  END upi[247]
  PIN upi[248]
    DIRECTION INPUT ;
    USE SIGNAL ;
    PORT
      LAYER M5 ;
        RECT  50.544 -0.072 50.568 0.072 ;
    END
  END upi[248]
  PIN upi[249]
    DIRECTION INPUT ;
    USE SIGNAL ;
    PORT
      LAYER M5 ;
        RECT  50.736 -0.072 50.76 0.072 ;
    END
  END upi[249]
  PIN upi[24]
    DIRECTION INPUT ;
    USE SIGNAL ;
    PORT
      LAYER M5 ;
        RECT  8.592 -0.072 8.616 0.072 ;
    END
  END upi[24]
  PIN upi[250]
    DIRECTION INPUT ;
    USE SIGNAL ;
    PORT
      LAYER M5 ;
        RECT  50.928 -0.072 50.952 0.072 ;
    END
  END upi[250]
  PIN upi[251]
    DIRECTION INPUT ;
    USE SIGNAL ;
    PORT
      LAYER M5 ;
        RECT  51.072 -0.072 51.096 0.072 ;
    END
  END upi[251]
  PIN upi[252]
    DIRECTION INPUT ;
    USE SIGNAL ;
    PORT
      LAYER M5 ;
        RECT  51.264 -0.072 51.288 0.072 ;
    END
  END upi[252]
  PIN upi[253]
    DIRECTION INPUT ;
    USE SIGNAL ;
    PORT
      LAYER M5 ;
        RECT  51.456 -0.072 51.48 0.072 ;
    END
  END upi[253]
  PIN upi[254]
    DIRECTION INPUT ;
    USE SIGNAL ;
    PORT
      LAYER M5 ;
        RECT  51.648 -0.072 51.672 0.072 ;
    END
  END upi[254]
  PIN upi[255]
    DIRECTION INPUT ;
    USE SIGNAL ;
    PORT
      LAYER M5 ;
        RECT  51.84 -0.072 51.864 0.072 ;
    END
  END upi[255]
  PIN upi[256]
    DIRECTION INPUT ;
    USE SIGNAL ;
    PORT
      LAYER M5 ;
        RECT  52.032 -0.072 52.056 0.072 ;
    END
  END upi[256]
  PIN upi[257]
    DIRECTION INPUT ;
    USE SIGNAL ;
    PORT
      LAYER M5 ;
        RECT  52.224 -0.072 52.248 0.072 ;
    END
  END upi[257]
  PIN upi[258]
    DIRECTION INPUT ;
    USE SIGNAL ;
    PORT
      LAYER M5 ;
        RECT  52.416 -0.072 52.44 0.072 ;
    END
  END upi[258]
  PIN upi[259]
    DIRECTION INPUT ;
    USE SIGNAL ;
    PORT
      LAYER M5 ;
        RECT  52.608 -0.072 52.632 0.072 ;
    END
  END upi[259]
  PIN upi[25]
    DIRECTION INPUT ;
    USE SIGNAL ;
    PORT
      LAYER M5 ;
        RECT  8.784 -0.072 8.808 0.072 ;
    END
  END upi[25]
  PIN upi[260]
    DIRECTION INPUT ;
    USE SIGNAL ;
    PORT
      LAYER M5 ;
        RECT  52.8 -0.072 52.824 0.072 ;
    END
  END upi[260]
  PIN upi[261]
    DIRECTION INPUT ;
    USE SIGNAL ;
    PORT
      LAYER M5 ;
        RECT  52.944 -0.072 52.968 0.072 ;
    END
  END upi[261]
  PIN upi[262]
    DIRECTION INPUT ;
    USE SIGNAL ;
    PORT
      LAYER M5 ;
        RECT  53.136 -0.072 53.16 0.072 ;
    END
  END upi[262]
  PIN upi[263]
    DIRECTION INPUT ;
    USE SIGNAL ;
    PORT
      LAYER M5 ;
        RECT  53.328 -0.072 53.352 0.072 ;
    END
  END upi[263]
  PIN upi[264]
    DIRECTION INPUT ;
    USE SIGNAL ;
    PORT
      LAYER M5 ;
        RECT  53.52 -0.072 53.544 0.072 ;
    END
  END upi[264]
  PIN upi[265]
    DIRECTION INPUT ;
    USE SIGNAL ;
    PORT
      LAYER M5 ;
        RECT  53.712 -0.072 53.736 0.072 ;
    END
  END upi[265]
  PIN upi[266]
    DIRECTION INPUT ;
    USE SIGNAL ;
    PORT
      LAYER M5 ;
        RECT  53.904 -0.072 53.928 0.072 ;
    END
  END upi[266]
  PIN upi[267]
    DIRECTION INPUT ;
    USE SIGNAL ;
    PORT
      LAYER M5 ;
        RECT  54.096 -0.072 54.12 0.072 ;
    END
  END upi[267]
  PIN upi[268]
    DIRECTION INPUT ;
    USE SIGNAL ;
    PORT
      LAYER M5 ;
        RECT  54.288 -0.072 54.312 0.072 ;
    END
  END upi[268]
  PIN upi[269]
    DIRECTION INPUT ;
    USE SIGNAL ;
    PORT
      LAYER M5 ;
        RECT  54.48 -0.072 54.504 0.072 ;
    END
  END upi[269]
  PIN upi[26]
    DIRECTION INPUT ;
    USE SIGNAL ;
    PORT
      LAYER M5 ;
        RECT  8.928 -0.072 8.952 0.072 ;
    END
  END upi[26]
  PIN upi[270]
    DIRECTION INPUT ;
    USE SIGNAL ;
    PORT
      LAYER M5 ;
        RECT  54.672 -0.072 54.696 0.072 ;
    END
  END upi[270]
  PIN upi[271]
    DIRECTION INPUT ;
    USE SIGNAL ;
    PORT
      LAYER M5 ;
        RECT  54.816 -0.072 54.84 0.072 ;
    END
  END upi[271]
  PIN upi[272]
    DIRECTION INPUT ;
    USE SIGNAL ;
    PORT
      LAYER M5 ;
        RECT  55.008 -0.072 55.032 0.072 ;
    END
  END upi[272]
  PIN upi[273]
    DIRECTION INPUT ;
    USE SIGNAL ;
    PORT
      LAYER M5 ;
        RECT  55.2 -0.072 55.224 0.072 ;
    END
  END upi[273]
  PIN upi[274]
    DIRECTION INPUT ;
    USE SIGNAL ;
    PORT
      LAYER M5 ;
        RECT  55.392 -0.072 55.416 0.072 ;
    END
  END upi[274]
  PIN upi[275]
    DIRECTION INPUT ;
    USE SIGNAL ;
    PORT
      LAYER M5 ;
        RECT  55.584 -0.072 55.608 0.072 ;
    END
  END upi[275]
  PIN upi[276]
    DIRECTION INPUT ;
    USE SIGNAL ;
    PORT
      LAYER M5 ;
        RECT  55.776 -0.072 55.8 0.072 ;
    END
  END upi[276]
  PIN upi[277]
    DIRECTION INPUT ;
    USE SIGNAL ;
    PORT
      LAYER M5 ;
        RECT  55.968 -0.072 55.992 0.072 ;
    END
  END upi[277]
  PIN upi[278]
    DIRECTION INPUT ;
    USE SIGNAL ;
    PORT
      LAYER M5 ;
        RECT  56.16 -0.072 56.184 0.072 ;
    END
  END upi[278]
  PIN upi[279]
    DIRECTION INPUT ;
    USE SIGNAL ;
    PORT
      LAYER M5 ;
        RECT  56.352 -0.072 56.376 0.072 ;
    END
  END upi[279]
  PIN upi[27]
    DIRECTION INPUT ;
    USE SIGNAL ;
    PORT
      LAYER M5 ;
        RECT  9.12 -0.072 9.144 0.072 ;
    END
  END upi[27]
  PIN upi[280]
    DIRECTION INPUT ;
    USE SIGNAL ;
    PORT
      LAYER M5 ;
        RECT  56.544 -0.072 56.568 0.072 ;
    END
  END upi[280]
  PIN upi[281]
    DIRECTION INPUT ;
    USE SIGNAL ;
    PORT
      LAYER M5 ;
        RECT  56.688 -0.072 56.712 0.072 ;
    END
  END upi[281]
  PIN upi[282]
    DIRECTION INPUT ;
    USE SIGNAL ;
    PORT
      LAYER M5 ;
        RECT  56.88 -0.072 56.904 0.072 ;
    END
  END upi[282]
  PIN upi[283]
    DIRECTION INPUT ;
    USE SIGNAL ;
    PORT
      LAYER M5 ;
        RECT  57.072 -0.072 57.096 0.072 ;
    END
  END upi[283]
  PIN upi[284]
    DIRECTION INPUT ;
    USE SIGNAL ;
    PORT
      LAYER M5 ;
        RECT  57.264 -0.072 57.288 0.072 ;
    END
  END upi[284]
  PIN upi[285]
    DIRECTION INPUT ;
    USE SIGNAL ;
    PORT
      LAYER M5 ;
        RECT  57.456 -0.072 57.48 0.072 ;
    END
  END upi[285]
  PIN upi[286]
    DIRECTION INPUT ;
    USE SIGNAL ;
    PORT
      LAYER M5 ;
        RECT  57.648 -0.072 57.672 0.072 ;
    END
  END upi[286]
  PIN upi[287]
    DIRECTION INPUT ;
    USE SIGNAL ;
    PORT
      LAYER M5 ;
        RECT  57.84 -0.072 57.864 0.072 ;
    END
  END upi[287]
  PIN upi[288]
    DIRECTION INPUT ;
    USE SIGNAL ;
    PORT
      LAYER M5 ;
        RECT  58.032 -0.072 58.056 0.072 ;
    END
  END upi[288]
  PIN upi[289]
    DIRECTION INPUT ;
    USE SIGNAL ;
    PORT
      LAYER M5 ;
        RECT  58.224 -0.072 58.248 0.072 ;
    END
  END upi[289]
  PIN upi[28]
    DIRECTION INPUT ;
    USE SIGNAL ;
    PORT
      LAYER M5 ;
        RECT  9.312 -0.072 9.336 0.072 ;
    END
  END upi[28]
  PIN upi[290]
    DIRECTION INPUT ;
    USE SIGNAL ;
    PORT
      LAYER M5 ;
        RECT  58.416 -0.072 58.44 0.072 ;
    END
  END upi[290]
  PIN upi[291]
    DIRECTION INPUT ;
    USE SIGNAL ;
    PORT
      LAYER M5 ;
        RECT  58.56 -0.072 58.584 0.072 ;
    END
  END upi[291]
  PIN upi[292]
    DIRECTION INPUT ;
    USE SIGNAL ;
    PORT
      LAYER M5 ;
        RECT  58.752 -0.072 58.776 0.072 ;
    END
  END upi[292]
  PIN upi[293]
    DIRECTION INPUT ;
    USE SIGNAL ;
    PORT
      LAYER M5 ;
        RECT  58.944 -0.072 58.968 0.072 ;
    END
  END upi[293]
  PIN upi[294]
    DIRECTION INPUT ;
    USE SIGNAL ;
    PORT
      LAYER M5 ;
        RECT  59.136 -0.072 59.16 0.072 ;
    END
  END upi[294]
  PIN upi[295]
    DIRECTION INPUT ;
    USE SIGNAL ;
    PORT
      LAYER M5 ;
        RECT  59.328 -0.072 59.352 0.072 ;
    END
  END upi[295]
  PIN upi[296]
    DIRECTION INPUT ;
    USE SIGNAL ;
    PORT
      LAYER M5 ;
        RECT  59.52 -0.072 59.544 0.072 ;
    END
  END upi[296]
  PIN upi[297]
    DIRECTION INPUT ;
    USE SIGNAL ;
    PORT
      LAYER M5 ;
        RECT  59.712 -0.072 59.736 0.072 ;
    END
  END upi[297]
  PIN upi[298]
    DIRECTION INPUT ;
    USE SIGNAL ;
    PORT
      LAYER M5 ;
        RECT  59.904 -0.072 59.928 0.072 ;
    END
  END upi[298]
  PIN upi[29]
    DIRECTION INPUT ;
    USE SIGNAL ;
    PORT
      LAYER M5 ;
        RECT  9.504 -0.072 9.528 0.072 ;
    END
  END upi[29]
  PIN upi[2]
    DIRECTION INPUT ;
    USE SIGNAL ;
    PORT
      LAYER M5 ;
        RECT  4.464 -0.072 4.488 0.072 ;
    END
  END upi[2]
  PIN upi[30]
    DIRECTION INPUT ;
    USE SIGNAL ;
    PORT
      LAYER M5 ;
        RECT  9.696 -0.072 9.72 0.072 ;
    END
  END upi[30]
  PIN upi[31]
    DIRECTION INPUT ;
    USE SIGNAL ;
    PORT
      LAYER M5 ;
        RECT  9.888 -0.072 9.912 0.072 ;
    END
  END upi[31]
  PIN upi[32]
    DIRECTION INPUT ;
    USE SIGNAL ;
    PORT
      LAYER M5 ;
        RECT  10.08 -0.072 10.104 0.072 ;
    END
  END upi[32]
  PIN upi[33]
    DIRECTION INPUT ;
    USE SIGNAL ;
    PORT
      LAYER M5 ;
        RECT  10.272 -0.072 10.296 0.072 ;
    END
  END upi[33]
  PIN upi[34]
    DIRECTION INPUT ;
    USE SIGNAL ;
    PORT
      LAYER M5 ;
        RECT  10.464 -0.072 10.488 0.072 ;
    END
  END upi[34]
  PIN upi[35]
    DIRECTION INPUT ;
    USE SIGNAL ;
    PORT
      LAYER M5 ;
        RECT  10.656 -0.072 10.68 0.072 ;
    END
  END upi[35]
  PIN upi[36]
    DIRECTION INPUT ;
    USE SIGNAL ;
    PORT
      LAYER M5 ;
        RECT  10.848 -0.072 10.872 0.072 ;
    END
  END upi[36]
  PIN upi[37]
    DIRECTION INPUT ;
    USE SIGNAL ;
    PORT
      LAYER M5 ;
        RECT  10.992 -0.072 11.016 0.072 ;
    END
  END upi[37]
  PIN upi[38]
    DIRECTION INPUT ;
    USE SIGNAL ;
    PORT
      LAYER M5 ;
        RECT  11.184 -0.072 11.208 0.072 ;
    END
  END upi[38]
  PIN upi[39]
    DIRECTION INPUT ;
    USE SIGNAL ;
    PORT
      LAYER M5 ;
        RECT  11.376 -0.072 11.4 0.072 ;
    END
  END upi[39]
  PIN upi[3]
    DIRECTION INPUT ;
    USE SIGNAL ;
    PORT
      LAYER M5 ;
        RECT  4.656 -0.072 4.68 0.072 ;
    END
  END upi[3]
  PIN upi[40]
    DIRECTION INPUT ;
    USE SIGNAL ;
    PORT
      LAYER M5 ;
        RECT  11.568 -0.072 11.592 0.072 ;
    END
  END upi[40]
  PIN upi[41]
    DIRECTION INPUT ;
    USE SIGNAL ;
    PORT
      LAYER M5 ;
        RECT  11.76 -0.072 11.784 0.072 ;
    END
  END upi[41]
  PIN upi[42]
    DIRECTION INPUT ;
    USE SIGNAL ;
    PORT
      LAYER M5 ;
        RECT  11.952 -0.072 11.976 0.072 ;
    END
  END upi[42]
  PIN upi[43]
    DIRECTION INPUT ;
    USE SIGNAL ;
    PORT
      LAYER M5 ;
        RECT  12.144 -0.072 12.168 0.072 ;
    END
  END upi[43]
  PIN upi[44]
    DIRECTION INPUT ;
    USE SIGNAL ;
    PORT
      LAYER M5 ;
        RECT  12.336 -0.072 12.36 0.072 ;
    END
  END upi[44]
  PIN upi[45]
    DIRECTION INPUT ;
    USE SIGNAL ;
    PORT
      LAYER M5 ;
        RECT  12.528 -0.072 12.552 0.072 ;
    END
  END upi[45]
  PIN upi[46]
    DIRECTION INPUT ;
    USE SIGNAL ;
    PORT
      LAYER M5 ;
        RECT  12.72 -0.072 12.744 0.072 ;
    END
  END upi[46]
  PIN upi[47]
    DIRECTION INPUT ;
    USE SIGNAL ;
    PORT
      LAYER M5 ;
        RECT  12.864 -0.072 12.888 0.072 ;
    END
  END upi[47]
  PIN upi[48]
    DIRECTION INPUT ;
    USE SIGNAL ;
    PORT
      LAYER M5 ;
        RECT  13.056 -0.072 13.08 0.072 ;
    END
  END upi[48]
  PIN upi[49]
    DIRECTION INPUT ;
    USE SIGNAL ;
    PORT
      LAYER M5 ;
        RECT  13.248 -0.072 13.272 0.072 ;
    END
  END upi[49]
  PIN upi[4]
    DIRECTION INPUT ;
    USE SIGNAL ;
    PORT
      LAYER M5 ;
        RECT  4.848 -0.072 4.872 0.072 ;
    END
  END upi[4]
  PIN upi[50]
    DIRECTION INPUT ;
    USE SIGNAL ;
    PORT
      LAYER M5 ;
        RECT  13.44 -0.072 13.464 0.072 ;
    END
  END upi[50]
  PIN upi[51]
    DIRECTION INPUT ;
    USE SIGNAL ;
    PORT
      LAYER M5 ;
        RECT  13.632 -0.072 13.656 0.072 ;
    END
  END upi[51]
  PIN upi[52]
    DIRECTION INPUT ;
    USE SIGNAL ;
    PORT
      LAYER M5 ;
        RECT  13.824 -0.072 13.848 0.072 ;
    END
  END upi[52]
  PIN upi[53]
    DIRECTION INPUT ;
    USE SIGNAL ;
    PORT
      LAYER M5 ;
        RECT  14.016 -0.072 14.04 0.072 ;
    END
  END upi[53]
  PIN upi[54]
    DIRECTION INPUT ;
    USE SIGNAL ;
    PORT
      LAYER M5 ;
        RECT  14.208 -0.072 14.232 0.072 ;
    END
  END upi[54]
  PIN upi[55]
    DIRECTION INPUT ;
    USE SIGNAL ;
    PORT
      LAYER M5 ;
        RECT  14.4 -0.072 14.424 0.072 ;
    END
  END upi[55]
  PIN upi[56]
    DIRECTION INPUT ;
    USE SIGNAL ;
    PORT
      LAYER M5 ;
        RECT  14.592 -0.072 14.616 0.072 ;
    END
  END upi[56]
  PIN upi[57]
    DIRECTION INPUT ;
    USE SIGNAL ;
    PORT
      LAYER M5 ;
        RECT  14.736 -0.072 14.76 0.072 ;
    END
  END upi[57]
  PIN upi[58]
    DIRECTION INPUT ;
    USE SIGNAL ;
    PORT
      LAYER M5 ;
        RECT  14.928 -0.072 14.952 0.072 ;
    END
  END upi[58]
  PIN upi[59]
    DIRECTION INPUT ;
    USE SIGNAL ;
    PORT
      LAYER M5 ;
        RECT  15.12 -0.072 15.144 0.072 ;
    END
  END upi[59]
  PIN upi[5]
    DIRECTION INPUT ;
    USE SIGNAL ;
    PORT
      LAYER M5 ;
        RECT  5.04 -0.072 5.064 0.072 ;
    END
  END upi[5]
  PIN upi[60]
    DIRECTION INPUT ;
    USE SIGNAL ;
    PORT
      LAYER M5 ;
        RECT  15.312 -0.072 15.336 0.072 ;
    END
  END upi[60]
  PIN upi[61]
    DIRECTION INPUT ;
    USE SIGNAL ;
    PORT
      LAYER M5 ;
        RECT  15.504 -0.072 15.528 0.072 ;
    END
  END upi[61]
  PIN upi[62]
    DIRECTION INPUT ;
    USE SIGNAL ;
    PORT
      LAYER M5 ;
        RECT  15.696 -0.072 15.72 0.072 ;
    END
  END upi[62]
  PIN upi[63]
    DIRECTION INPUT ;
    USE SIGNAL ;
    PORT
      LAYER M5 ;
        RECT  15.888 -0.072 15.912 0.072 ;
    END
  END upi[63]
  PIN upi[64]
    DIRECTION INPUT ;
    USE SIGNAL ;
    PORT
      LAYER M5 ;
        RECT  16.08 -0.072 16.104 0.072 ;
    END
  END upi[64]
  PIN upi[65]
    DIRECTION INPUT ;
    USE SIGNAL ;
    PORT
      LAYER M5 ;
        RECT  16.272 -0.072 16.296 0.072 ;
    END
  END upi[65]
  PIN upi[66]
    DIRECTION INPUT ;
    USE SIGNAL ;
    PORT
      LAYER M5 ;
        RECT  16.464 -0.072 16.488 0.072 ;
    END
  END upi[66]
  PIN upi[67]
    DIRECTION INPUT ;
    USE SIGNAL ;
    PORT
      LAYER M5 ;
        RECT  16.608 -0.072 16.632 0.072 ;
    END
  END upi[67]
  PIN upi[68]
    DIRECTION INPUT ;
    USE SIGNAL ;
    PORT
      LAYER M5 ;
        RECT  16.8 -0.072 16.824 0.072 ;
    END
  END upi[68]
  PIN upi[69]
    DIRECTION INPUT ;
    USE SIGNAL ;
    PORT
      LAYER M5 ;
        RECT  16.992 -0.072 17.016 0.072 ;
    END
  END upi[69]
  PIN upi[6]
    DIRECTION INPUT ;
    USE SIGNAL ;
    PORT
      LAYER M5 ;
        RECT  5.184 -0.072 5.208 0.072 ;
    END
  END upi[6]
  PIN upi[70]
    DIRECTION INPUT ;
    USE SIGNAL ;
    PORT
      LAYER M5 ;
        RECT  17.184 -0.072 17.208 0.072 ;
    END
  END upi[70]
  PIN upi[71]
    DIRECTION INPUT ;
    USE SIGNAL ;
    PORT
      LAYER M5 ;
        RECT  17.376 -0.072 17.4 0.072 ;
    END
  END upi[71]
  PIN upi[72]
    DIRECTION INPUT ;
    USE SIGNAL ;
    PORT
      LAYER M5 ;
        RECT  17.568 -0.072 17.592 0.072 ;
    END
  END upi[72]
  PIN upi[73]
    DIRECTION INPUT ;
    USE SIGNAL ;
    PORT
      LAYER M5 ;
        RECT  17.76 -0.072 17.784 0.072 ;
    END
  END upi[73]
  PIN upi[74]
    DIRECTION INPUT ;
    USE SIGNAL ;
    PORT
      LAYER M5 ;
        RECT  17.952 -0.072 17.976 0.072 ;
    END
  END upi[74]
  PIN upi[75]
    DIRECTION INPUT ;
    USE SIGNAL ;
    PORT
      LAYER M5 ;
        RECT  18.144 -0.072 18.168 0.072 ;
    END
  END upi[75]
  PIN upi[76]
    DIRECTION INPUT ;
    USE SIGNAL ;
    PORT
      LAYER M5 ;
        RECT  18.336 -0.072 18.36 0.072 ;
    END
  END upi[76]
  PIN upi[77]
    DIRECTION INPUT ;
    USE SIGNAL ;
    PORT
      LAYER M5 ;
        RECT  18.48 -0.072 18.504 0.072 ;
    END
  END upi[77]
  PIN upi[78]
    DIRECTION INPUT ;
    USE SIGNAL ;
    PORT
      LAYER M5 ;
        RECT  18.672 -0.072 18.696 0.072 ;
    END
  END upi[78]
  PIN upi[79]
    DIRECTION INPUT ;
    USE SIGNAL ;
    PORT
      LAYER M5 ;
        RECT  18.864 -0.072 18.888 0.072 ;
    END
  END upi[79]
  PIN upi[7]
    DIRECTION INPUT ;
    USE SIGNAL ;
    PORT
      LAYER M5 ;
        RECT  5.376 -0.072 5.4 0.072 ;
    END
  END upi[7]
  PIN upi[80]
    DIRECTION INPUT ;
    USE SIGNAL ;
    PORT
      LAYER M5 ;
        RECT  19.056 -0.072 19.08 0.072 ;
    END
  END upi[80]
  PIN upi[81]
    DIRECTION INPUT ;
    USE SIGNAL ;
    PORT
      LAYER M5 ;
        RECT  19.248 -0.072 19.272 0.072 ;
    END
  END upi[81]
  PIN upi[82]
    DIRECTION INPUT ;
    USE SIGNAL ;
    PORT
      LAYER M5 ;
        RECT  19.44 -0.072 19.464 0.072 ;
    END
  END upi[82]
  PIN upi[83]
    DIRECTION INPUT ;
    USE SIGNAL ;
    PORT
      LAYER M5 ;
        RECT  19.632 -0.072 19.656 0.072 ;
    END
  END upi[83]
  PIN upi[84]
    DIRECTION INPUT ;
    USE SIGNAL ;
    PORT
      LAYER M5 ;
        RECT  19.824 -0.072 19.848 0.072 ;
    END
  END upi[84]
  PIN upi[85]
    DIRECTION INPUT ;
    USE SIGNAL ;
    PORT
      LAYER M5 ;
        RECT  20.016 -0.072 20.04 0.072 ;
    END
  END upi[85]
  PIN upi[86]
    DIRECTION INPUT ;
    USE SIGNAL ;
    PORT
      LAYER M5 ;
        RECT  20.208 -0.072 20.232 0.072 ;
    END
  END upi[86]
  PIN upi[87]
    DIRECTION INPUT ;
    USE SIGNAL ;
    PORT
      LAYER M5 ;
        RECT  20.352 -0.072 20.376 0.072 ;
    END
  END upi[87]
  PIN upi[88]
    DIRECTION INPUT ;
    USE SIGNAL ;
    PORT
      LAYER M5 ;
        RECT  20.544 -0.072 20.568 0.072 ;
    END
  END upi[88]
  PIN upi[89]
    DIRECTION INPUT ;
    USE SIGNAL ;
    PORT
      LAYER M5 ;
        RECT  20.736 -0.072 20.76 0.072 ;
    END
  END upi[89]
  PIN upi[8]
    DIRECTION INPUT ;
    USE SIGNAL ;
    PORT
      LAYER M5 ;
        RECT  5.568 -0.072 5.592 0.072 ;
    END
  END upi[8]
  PIN upi[90]
    DIRECTION INPUT ;
    USE SIGNAL ;
    PORT
      LAYER M5 ;
        RECT  20.928 -0.072 20.952 0.072 ;
    END
  END upi[90]
  PIN upi[91]
    DIRECTION INPUT ;
    USE SIGNAL ;
    PORT
      LAYER M5 ;
        RECT  21.12 -0.072 21.144 0.072 ;
    END
  END upi[91]
  PIN upi[92]
    DIRECTION INPUT ;
    USE SIGNAL ;
    PORT
      LAYER M5 ;
        RECT  21.312 -0.072 21.336 0.072 ;
    END
  END upi[92]
  PIN upi[93]
    DIRECTION INPUT ;
    USE SIGNAL ;
    PORT
      LAYER M5 ;
        RECT  21.504 -0.072 21.528 0.072 ;
    END
  END upi[93]
  PIN upi[94]
    DIRECTION INPUT ;
    USE SIGNAL ;
    PORT
      LAYER M5 ;
        RECT  21.696 -0.072 21.72 0.072 ;
    END
  END upi[94]
  PIN upi[95]
    DIRECTION INPUT ;
    USE SIGNAL ;
    PORT
      LAYER M5 ;
        RECT  21.888 -0.072 21.912 0.072 ;
    END
  END upi[95]
  PIN upi[96]
    DIRECTION INPUT ;
    USE SIGNAL ;
    PORT
      LAYER M5 ;
        RECT  22.08 -0.072 22.104 0.072 ;
    END
  END upi[96]
  PIN upi[97]
    DIRECTION INPUT ;
    USE SIGNAL ;
    PORT
      LAYER M5 ;
        RECT  22.272 -0.072 22.296 0.072 ;
    END
  END upi[97]
  PIN upi[98]
    DIRECTION INPUT ;
    USE SIGNAL ;
    PORT
      LAYER M5 ;
        RECT  22.416 -0.072 22.44 0.072 ;
    END
  END upi[98]
  PIN upi[99]
    DIRECTION INPUT ;
    USE SIGNAL ;
    PORT
      LAYER M5 ;
        RECT  22.608 -0.072 22.632 0.072 ;
    END
  END upi[99]
  PIN upi[9]
    DIRECTION INPUT ;
    USE SIGNAL ;
    PORT
      LAYER M5 ;
        RECT  5.76 -0.072 5.784 0.072 ;
    END
  END upi[9]
  PIN upo[0]
    DIRECTION OUTPUT ;
    USE SIGNAL ;
    PORT
      LAYER M5 ;
        RECT  4.08 172.728 4.104 172.872 ;
    END
  END upo[0]
  PIN upo[100]
    DIRECTION OUTPUT ;
    USE SIGNAL ;
    PORT
      LAYER M5 ;
        RECT  22.8 172.728 22.824 172.872 ;
    END
  END upo[100]
  PIN upo[101]
    DIRECTION OUTPUT ;
    USE SIGNAL ;
    PORT
      LAYER M5 ;
        RECT  22.992 172.728 23.016 172.872 ;
    END
  END upo[101]
  PIN upo[102]
    DIRECTION OUTPUT ;
    USE SIGNAL ;
    PORT
      LAYER M5 ;
        RECT  23.184 172.728 23.208 172.872 ;
    END
  END upo[102]
  PIN upo[103]
    DIRECTION OUTPUT ;
    USE SIGNAL ;
    PORT
      LAYER M5 ;
        RECT  23.376 172.728 23.4 172.872 ;
    END
  END upo[103]
  PIN upo[104]
    DIRECTION OUTPUT ;
    USE SIGNAL ;
    PORT
      LAYER M5 ;
        RECT  23.568 172.728 23.592 172.872 ;
    END
  END upo[104]
  PIN upo[105]
    DIRECTION OUTPUT ;
    USE SIGNAL ;
    PORT
      LAYER M5 ;
        RECT  23.76 172.728 23.784 172.872 ;
    END
  END upo[105]
  PIN upo[106]
    DIRECTION OUTPUT ;
    USE SIGNAL ;
    PORT
      LAYER M5 ;
        RECT  23.952 172.728 23.976 172.872 ;
    END
  END upo[106]
  PIN upo[107]
    DIRECTION OUTPUT ;
    USE SIGNAL ;
    PORT
      LAYER M5 ;
        RECT  24.144 172.728 24.168 172.872 ;
    END
  END upo[107]
  PIN upo[108]
    DIRECTION OUTPUT ;
    USE SIGNAL ;
    PORT
      LAYER M5 ;
        RECT  24.288 172.728 24.312 172.872 ;
    END
  END upo[108]
  PIN upo[109]
    DIRECTION OUTPUT ;
    USE SIGNAL ;
    PORT
      LAYER M5 ;
        RECT  24.48 172.728 24.504 172.872 ;
    END
  END upo[109]
  PIN upo[10]
    DIRECTION OUTPUT ;
    USE SIGNAL ;
    PORT
      LAYER M5 ;
        RECT  5.952 172.728 5.976 172.872 ;
    END
  END upo[10]
  PIN upo[110]
    DIRECTION OUTPUT ;
    USE SIGNAL ;
    PORT
      LAYER M5 ;
        RECT  24.672 172.728 24.696 172.872 ;
    END
  END upo[110]
  PIN upo[111]
    DIRECTION OUTPUT ;
    USE SIGNAL ;
    PORT
      LAYER M5 ;
        RECT  24.864 172.728 24.888 172.872 ;
    END
  END upo[111]
  PIN upo[112]
    DIRECTION OUTPUT ;
    USE SIGNAL ;
    PORT
      LAYER M5 ;
        RECT  25.056 172.728 25.08 172.872 ;
    END
  END upo[112]
  PIN upo[113]
    DIRECTION OUTPUT ;
    USE SIGNAL ;
    PORT
      LAYER M5 ;
        RECT  25.248 172.728 25.272 172.872 ;
    END
  END upo[113]
  PIN upo[114]
    DIRECTION OUTPUT ;
    USE SIGNAL ;
    PORT
      LAYER M5 ;
        RECT  25.44 172.728 25.464 172.872 ;
    END
  END upo[114]
  PIN upo[115]
    DIRECTION OUTPUT ;
    USE SIGNAL ;
    PORT
      LAYER M5 ;
        RECT  25.632 172.728 25.656 172.872 ;
    END
  END upo[115]
  PIN upo[116]
    DIRECTION OUTPUT ;
    USE SIGNAL ;
    PORT
      LAYER M5 ;
        RECT  25.824 172.728 25.848 172.872 ;
    END
  END upo[116]
  PIN upo[117]
    DIRECTION OUTPUT ;
    USE SIGNAL ;
    PORT
      LAYER M5 ;
        RECT  26.016 172.728 26.04 172.872 ;
    END
  END upo[117]
  PIN upo[118]
    DIRECTION OUTPUT ;
    USE SIGNAL ;
    PORT
      LAYER M5 ;
        RECT  26.16 172.728 26.184 172.872 ;
    END
  END upo[118]
  PIN upo[119]
    DIRECTION OUTPUT ;
    USE SIGNAL ;
    PORT
      LAYER M5 ;
        RECT  26.352 172.728 26.376 172.872 ;
    END
  END upo[119]
  PIN upo[11]
    DIRECTION OUTPUT ;
    USE SIGNAL ;
    PORT
      LAYER M5 ;
        RECT  6.144 172.728 6.168 172.872 ;
    END
  END upo[11]
  PIN upo[120]
    DIRECTION OUTPUT ;
    USE SIGNAL ;
    PORT
      LAYER M5 ;
        RECT  26.544 172.728 26.568 172.872 ;
    END
  END upo[120]
  PIN upo[121]
    DIRECTION OUTPUT ;
    USE SIGNAL ;
    PORT
      LAYER M5 ;
        RECT  26.736 172.728 26.76 172.872 ;
    END
  END upo[121]
  PIN upo[122]
    DIRECTION OUTPUT ;
    USE SIGNAL ;
    PORT
      LAYER M5 ;
        RECT  26.928 172.728 26.952 172.872 ;
    END
  END upo[122]
  PIN upo[123]
    DIRECTION OUTPUT ;
    USE SIGNAL ;
    PORT
      LAYER M5 ;
        RECT  27.12 172.728 27.144 172.872 ;
    END
  END upo[123]
  PIN upo[124]
    DIRECTION OUTPUT ;
    USE SIGNAL ;
    PORT
      LAYER M5 ;
        RECT  27.312 172.728 27.336 172.872 ;
    END
  END upo[124]
  PIN upo[125]
    DIRECTION OUTPUT ;
    USE SIGNAL ;
    PORT
      LAYER M5 ;
        RECT  27.504 172.728 27.528 172.872 ;
    END
  END upo[125]
  PIN upo[126]
    DIRECTION OUTPUT ;
    USE SIGNAL ;
    PORT
      LAYER M5 ;
        RECT  27.696 172.728 27.72 172.872 ;
    END
  END upo[126]
  PIN upo[127]
    DIRECTION OUTPUT ;
    USE SIGNAL ;
    PORT
      LAYER M5 ;
        RECT  27.888 172.728 27.912 172.872 ;
    END
  END upo[127]
  PIN upo[128]
    DIRECTION OUTPUT ;
    USE SIGNAL ;
    PORT
      LAYER M5 ;
        RECT  28.032 172.728 28.056 172.872 ;
    END
  END upo[128]
  PIN upo[129]
    DIRECTION OUTPUT ;
    USE SIGNAL ;
    PORT
      LAYER M5 ;
        RECT  28.224 172.728 28.248 172.872 ;
    END
  END upo[129]
  PIN upo[12]
    DIRECTION OUTPUT ;
    USE SIGNAL ;
    PORT
      LAYER M5 ;
        RECT  6.336 172.728 6.36 172.872 ;
    END
  END upo[12]
  PIN upo[130]
    DIRECTION OUTPUT ;
    USE SIGNAL ;
    PORT
      LAYER M5 ;
        RECT  28.416 172.728 28.44 172.872 ;
    END
  END upo[130]
  PIN upo[131]
    DIRECTION OUTPUT ;
    USE SIGNAL ;
    PORT
      LAYER M5 ;
        RECT  28.608 172.728 28.632 172.872 ;
    END
  END upo[131]
  PIN upo[132]
    DIRECTION OUTPUT ;
    USE SIGNAL ;
    PORT
      LAYER M5 ;
        RECT  28.8 172.728 28.824 172.872 ;
    END
  END upo[132]
  PIN upo[133]
    DIRECTION OUTPUT ;
    USE SIGNAL ;
    PORT
      LAYER M5 ;
        RECT  28.992 172.728 29.016 172.872 ;
    END
  END upo[133]
  PIN upo[134]
    DIRECTION OUTPUT ;
    USE SIGNAL ;
    PORT
      LAYER M5 ;
        RECT  29.184 172.728 29.208 172.872 ;
    END
  END upo[134]
  PIN upo[135]
    DIRECTION OUTPUT ;
    USE SIGNAL ;
    PORT
      LAYER M5 ;
        RECT  29.376 172.728 29.4 172.872 ;
    END
  END upo[135]
  PIN upo[136]
    DIRECTION OUTPUT ;
    USE SIGNAL ;
    PORT
      LAYER M5 ;
        RECT  29.568 172.728 29.592 172.872 ;
    END
  END upo[136]
  PIN upo[137]
    DIRECTION OUTPUT ;
    USE SIGNAL ;
    PORT
      LAYER M5 ;
        RECT  29.76 172.728 29.784 172.872 ;
    END
  END upo[137]
  PIN upo[138]
    DIRECTION OUTPUT ;
    USE SIGNAL ;
    PORT
      LAYER M5 ;
        RECT  29.904 172.728 29.928 172.872 ;
    END
  END upo[138]
  PIN upo[139]
    DIRECTION OUTPUT ;
    USE SIGNAL ;
    PORT
      LAYER M5 ;
        RECT  30.096 172.728 30.12 172.872 ;
    END
  END upo[139]
  PIN upo[13]
    DIRECTION OUTPUT ;
    USE SIGNAL ;
    PORT
      LAYER M5 ;
        RECT  6.528 172.728 6.552 172.872 ;
    END
  END upo[13]
  PIN upo[140]
    DIRECTION OUTPUT ;
    USE SIGNAL ;
    PORT
      LAYER M5 ;
        RECT  30.288 172.728 30.312 172.872 ;
    END
  END upo[140]
  PIN upo[141]
    DIRECTION OUTPUT ;
    USE SIGNAL ;
    PORT
      LAYER M5 ;
        RECT  30.48 172.728 30.504 172.872 ;
    END
  END upo[141]
  PIN upo[142]
    DIRECTION OUTPUT ;
    USE SIGNAL ;
    PORT
      LAYER M5 ;
        RECT  30.672 172.728 30.696 172.872 ;
    END
  END upo[142]
  PIN upo[143]
    DIRECTION OUTPUT ;
    USE SIGNAL ;
    PORT
      LAYER M5 ;
        RECT  30.864 172.728 30.888 172.872 ;
    END
  END upo[143]
  PIN upo[144]
    DIRECTION OUTPUT ;
    USE SIGNAL ;
    PORT
      LAYER M5 ;
        RECT  31.056 172.728 31.08 172.872 ;
    END
  END upo[144]
  PIN upo[145]
    DIRECTION OUTPUT ;
    USE SIGNAL ;
    PORT
      LAYER M5 ;
        RECT  31.248 172.728 31.272 172.872 ;
    END
  END upo[145]
  PIN upo[146]
    DIRECTION OUTPUT ;
    USE SIGNAL ;
    PORT
      LAYER M5 ;
        RECT  31.44 172.728 31.464 172.872 ;
    END
  END upo[146]
  PIN upo[147]
    DIRECTION OUTPUT ;
    USE SIGNAL ;
    PORT
      LAYER M5 ;
        RECT  31.632 172.728 31.656 172.872 ;
    END
  END upo[147]
  PIN upo[148]
    DIRECTION OUTPUT ;
    USE SIGNAL ;
    PORT
      LAYER M5 ;
        RECT  31.824 172.728 31.848 172.872 ;
    END
  END upo[148]
  PIN upo[149]
    DIRECTION OUTPUT ;
    USE SIGNAL ;
    PORT
      LAYER M5 ;
        RECT  31.968 172.728 31.992 172.872 ;
    END
  END upo[149]
  PIN upo[14]
    DIRECTION OUTPUT ;
    USE SIGNAL ;
    PORT
      LAYER M5 ;
        RECT  6.72 172.728 6.744 172.872 ;
    END
  END upo[14]
  PIN upo[150]
    DIRECTION OUTPUT ;
    USE SIGNAL ;
    PORT
      LAYER M5 ;
        RECT  32.16 172.728 32.184 172.872 ;
    END
  END upo[150]
  PIN upo[151]
    DIRECTION OUTPUT ;
    USE SIGNAL ;
    PORT
      LAYER M5 ;
        RECT  32.352 172.728 32.376 172.872 ;
    END
  END upo[151]
  PIN upo[152]
    DIRECTION OUTPUT ;
    USE SIGNAL ;
    PORT
      LAYER M5 ;
        RECT  32.544 172.728 32.568 172.872 ;
    END
  END upo[152]
  PIN upo[153]
    DIRECTION OUTPUT ;
    USE SIGNAL ;
    PORT
      LAYER M5 ;
        RECT  32.736 172.728 32.76 172.872 ;
    END
  END upo[153]
  PIN upo[154]
    DIRECTION OUTPUT ;
    USE SIGNAL ;
    PORT
      LAYER M5 ;
        RECT  32.928 172.728 32.952 172.872 ;
    END
  END upo[154]
  PIN upo[155]
    DIRECTION OUTPUT ;
    USE SIGNAL ;
    PORT
      LAYER M5 ;
        RECT  33.12 172.728 33.144 172.872 ;
    END
  END upo[155]
  PIN upo[156]
    DIRECTION OUTPUT ;
    USE SIGNAL ;
    PORT
      LAYER M5 ;
        RECT  33.312 172.728 33.336 172.872 ;
    END
  END upo[156]
  PIN upo[157]
    DIRECTION OUTPUT ;
    USE SIGNAL ;
    PORT
      LAYER M5 ;
        RECT  33.504 172.728 33.528 172.872 ;
    END
  END upo[157]
  PIN upo[158]
    DIRECTION OUTPUT ;
    USE SIGNAL ;
    PORT
      LAYER M5 ;
        RECT  33.696 172.728 33.72 172.872 ;
    END
  END upo[158]
  PIN upo[159]
    DIRECTION OUTPUT ;
    USE SIGNAL ;
    PORT
      LAYER M5 ;
        RECT  33.84 172.728 33.864 172.872 ;
    END
  END upo[159]
  PIN upo[15]
    DIRECTION OUTPUT ;
    USE SIGNAL ;
    PORT
      LAYER M5 ;
        RECT  6.912 172.728 6.936 172.872 ;
    END
  END upo[15]
  PIN upo[160]
    DIRECTION OUTPUT ;
    USE SIGNAL ;
    PORT
      LAYER M5 ;
        RECT  34.032 172.728 34.056 172.872 ;
    END
  END upo[160]
  PIN upo[161]
    DIRECTION OUTPUT ;
    USE SIGNAL ;
    PORT
      LAYER M5 ;
        RECT  34.224 172.728 34.248 172.872 ;
    END
  END upo[161]
  PIN upo[162]
    DIRECTION OUTPUT ;
    USE SIGNAL ;
    PORT
      LAYER M5 ;
        RECT  34.416 172.728 34.44 172.872 ;
    END
  END upo[162]
  PIN upo[163]
    DIRECTION OUTPUT ;
    USE SIGNAL ;
    PORT
      LAYER M5 ;
        RECT  34.608 172.728 34.632 172.872 ;
    END
  END upo[163]
  PIN upo[164]
    DIRECTION OUTPUT ;
    USE SIGNAL ;
    PORT
      LAYER M5 ;
        RECT  34.8 172.728 34.824 172.872 ;
    END
  END upo[164]
  PIN upo[165]
    DIRECTION OUTPUT ;
    USE SIGNAL ;
    PORT
      LAYER M5 ;
        RECT  34.992 172.728 35.016 172.872 ;
    END
  END upo[165]
  PIN upo[166]
    DIRECTION OUTPUT ;
    USE SIGNAL ;
    PORT
      LAYER M5 ;
        RECT  35.184 172.728 35.208 172.872 ;
    END
  END upo[166]
  PIN upo[167]
    DIRECTION OUTPUT ;
    USE SIGNAL ;
    PORT
      LAYER M5 ;
        RECT  35.376 172.728 35.4 172.872 ;
    END
  END upo[167]
  PIN upo[168]
    DIRECTION OUTPUT ;
    USE SIGNAL ;
    PORT
      LAYER M5 ;
        RECT  35.568 172.728 35.592 172.872 ;
    END
  END upo[168]
  PIN upo[169]
    DIRECTION OUTPUT ;
    USE SIGNAL ;
    PORT
      LAYER M5 ;
        RECT  35.712 172.728 35.736 172.872 ;
    END
  END upo[169]
  PIN upo[16]
    DIRECTION OUTPUT ;
    USE SIGNAL ;
    PORT
      LAYER M5 ;
        RECT  7.056 172.728 7.08 172.872 ;
    END
  END upo[16]
  PIN upo[170]
    DIRECTION OUTPUT ;
    USE SIGNAL ;
    PORT
      LAYER M5 ;
        RECT  35.904 172.728 35.928 172.872 ;
    END
  END upo[170]
  PIN upo[171]
    DIRECTION OUTPUT ;
    USE SIGNAL ;
    PORT
      LAYER M5 ;
        RECT  36.096 172.728 36.12 172.872 ;
    END
  END upo[171]
  PIN upo[172]
    DIRECTION OUTPUT ;
    USE SIGNAL ;
    PORT
      LAYER M5 ;
        RECT  36.288 172.728 36.312 172.872 ;
    END
  END upo[172]
  PIN upo[173]
    DIRECTION OUTPUT ;
    USE SIGNAL ;
    PORT
      LAYER M5 ;
        RECT  36.48 172.728 36.504 172.872 ;
    END
  END upo[173]
  PIN upo[174]
    DIRECTION OUTPUT ;
    USE SIGNAL ;
    PORT
      LAYER M5 ;
        RECT  36.672 172.728 36.696 172.872 ;
    END
  END upo[174]
  PIN upo[175]
    DIRECTION OUTPUT ;
    USE SIGNAL ;
    PORT
      LAYER M5 ;
        RECT  36.864 172.728 36.888 172.872 ;
    END
  END upo[175]
  PIN upo[176]
    DIRECTION OUTPUT ;
    USE SIGNAL ;
    PORT
      LAYER M5 ;
        RECT  37.056 172.728 37.08 172.872 ;
    END
  END upo[176]
  PIN upo[177]
    DIRECTION OUTPUT ;
    USE SIGNAL ;
    PORT
      LAYER M5 ;
        RECT  37.248 172.728 37.272 172.872 ;
    END
  END upo[177]
  PIN upo[178]
    DIRECTION OUTPUT ;
    USE SIGNAL ;
    PORT
      LAYER M5 ;
        RECT  37.44 172.728 37.464 172.872 ;
    END
  END upo[178]
  PIN upo[179]
    DIRECTION OUTPUT ;
    USE SIGNAL ;
    PORT
      LAYER M5 ;
        RECT  37.584 172.728 37.608 172.872 ;
    END
  END upo[179]
  PIN upo[17]
    DIRECTION OUTPUT ;
    USE SIGNAL ;
    PORT
      LAYER M5 ;
        RECT  7.248 172.728 7.272 172.872 ;
    END
  END upo[17]
  PIN upo[180]
    DIRECTION OUTPUT ;
    USE SIGNAL ;
    PORT
      LAYER M5 ;
        RECT  37.776 172.728 37.8 172.872 ;
    END
  END upo[180]
  PIN upo[181]
    DIRECTION OUTPUT ;
    USE SIGNAL ;
    PORT
      LAYER M5 ;
        RECT  37.968 172.728 37.992 172.872 ;
    END
  END upo[181]
  PIN upo[182]
    DIRECTION OUTPUT ;
    USE SIGNAL ;
    PORT
      LAYER M5 ;
        RECT  38.16 172.728 38.184 172.872 ;
    END
  END upo[182]
  PIN upo[183]
    DIRECTION OUTPUT ;
    USE SIGNAL ;
    PORT
      LAYER M5 ;
        RECT  38.352 172.728 38.376 172.872 ;
    END
  END upo[183]
  PIN upo[184]
    DIRECTION OUTPUT ;
    USE SIGNAL ;
    PORT
      LAYER M5 ;
        RECT  38.544 172.728 38.568 172.872 ;
    END
  END upo[184]
  PIN upo[185]
    DIRECTION OUTPUT ;
    USE SIGNAL ;
    PORT
      LAYER M5 ;
        RECT  38.736 172.728 38.76 172.872 ;
    END
  END upo[185]
  PIN upo[186]
    DIRECTION OUTPUT ;
    USE SIGNAL ;
    PORT
      LAYER M5 ;
        RECT  38.928 172.728 38.952 172.872 ;
    END
  END upo[186]
  PIN upo[187]
    DIRECTION OUTPUT ;
    USE SIGNAL ;
    PORT
      LAYER M5 ;
        RECT  39.12 172.728 39.144 172.872 ;
    END
  END upo[187]
  PIN upo[188]
    DIRECTION OUTPUT ;
    USE SIGNAL ;
    PORT
      LAYER M5 ;
        RECT  39.312 172.728 39.336 172.872 ;
    END
  END upo[188]
  PIN upo[189]
    DIRECTION OUTPUT ;
    USE SIGNAL ;
    PORT
      LAYER M5 ;
        RECT  39.456 172.728 39.48 172.872 ;
    END
  END upo[189]
  PIN upo[18]
    DIRECTION OUTPUT ;
    USE SIGNAL ;
    PORT
      LAYER M5 ;
        RECT  7.44 172.728 7.464 172.872 ;
    END
  END upo[18]
  PIN upo[190]
    DIRECTION OUTPUT ;
    USE SIGNAL ;
    PORT
      LAYER M5 ;
        RECT  39.648 172.728 39.672 172.872 ;
    END
  END upo[190]
  PIN upo[191]
    DIRECTION OUTPUT ;
    USE SIGNAL ;
    PORT
      LAYER M5 ;
        RECT  39.84 172.728 39.864 172.872 ;
    END
  END upo[191]
  PIN upo[192]
    DIRECTION OUTPUT ;
    USE SIGNAL ;
    PORT
      LAYER M5 ;
        RECT  40.032 172.728 40.056 172.872 ;
    END
  END upo[192]
  PIN upo[193]
    DIRECTION OUTPUT ;
    USE SIGNAL ;
    PORT
      LAYER M5 ;
        RECT  40.224 172.728 40.248 172.872 ;
    END
  END upo[193]
  PIN upo[194]
    DIRECTION OUTPUT ;
    USE SIGNAL ;
    PORT
      LAYER M5 ;
        RECT  40.416 172.728 40.44 172.872 ;
    END
  END upo[194]
  PIN upo[195]
    DIRECTION OUTPUT ;
    USE SIGNAL ;
    PORT
      LAYER M5 ;
        RECT  40.608 172.728 40.632 172.872 ;
    END
  END upo[195]
  PIN upo[196]
    DIRECTION OUTPUT ;
    USE SIGNAL ;
    PORT
      LAYER M5 ;
        RECT  40.8 172.728 40.824 172.872 ;
    END
  END upo[196]
  PIN upo[197]
    DIRECTION OUTPUT ;
    USE SIGNAL ;
    PORT
      LAYER M5 ;
        RECT  40.992 172.728 41.016 172.872 ;
    END
  END upo[197]
  PIN upo[198]
    DIRECTION OUTPUT ;
    USE SIGNAL ;
    PORT
      LAYER M5 ;
        RECT  41.184 172.728 41.208 172.872 ;
    END
  END upo[198]
  PIN upo[199]
    DIRECTION OUTPUT ;
    USE SIGNAL ;
    PORT
      LAYER M5 ;
        RECT  41.376 172.728 41.4 172.872 ;
    END
  END upo[199]
  PIN upo[19]
    DIRECTION OUTPUT ;
    USE SIGNAL ;
    PORT
      LAYER M5 ;
        RECT  7.632 172.728 7.656 172.872 ;
    END
  END upo[19]
  PIN upo[1]
    DIRECTION OUTPUT ;
    USE SIGNAL ;
    PORT
      LAYER M5 ;
        RECT  4.272 172.728 4.296 172.872 ;
    END
  END upo[1]
  PIN upo[200]
    DIRECTION OUTPUT ;
    USE SIGNAL ;
    PORT
      LAYER M5 ;
        RECT  41.52 172.728 41.544 172.872 ;
    END
  END upo[200]
  PIN upo[201]
    DIRECTION OUTPUT ;
    USE SIGNAL ;
    PORT
      LAYER M5 ;
        RECT  41.712 172.728 41.736 172.872 ;
    END
  END upo[201]
  PIN upo[202]
    DIRECTION OUTPUT ;
    USE SIGNAL ;
    PORT
      LAYER M5 ;
        RECT  41.904 172.728 41.928 172.872 ;
    END
  END upo[202]
  PIN upo[203]
    DIRECTION OUTPUT ;
    USE SIGNAL ;
    PORT
      LAYER M5 ;
        RECT  42.096 172.728 42.12 172.872 ;
    END
  END upo[203]
  PIN upo[204]
    DIRECTION OUTPUT ;
    USE SIGNAL ;
    PORT
      LAYER M5 ;
        RECT  42.288 172.728 42.312 172.872 ;
    END
  END upo[204]
  PIN upo[205]
    DIRECTION OUTPUT ;
    USE SIGNAL ;
    PORT
      LAYER M5 ;
        RECT  42.48 172.728 42.504 172.872 ;
    END
  END upo[205]
  PIN upo[206]
    DIRECTION OUTPUT ;
    USE SIGNAL ;
    PORT
      LAYER M5 ;
        RECT  42.672 172.728 42.696 172.872 ;
    END
  END upo[206]
  PIN upo[207]
    DIRECTION OUTPUT ;
    USE SIGNAL ;
    PORT
      LAYER M5 ;
        RECT  42.864 172.728 42.888 172.872 ;
    END
  END upo[207]
  PIN upo[208]
    DIRECTION OUTPUT ;
    USE SIGNAL ;
    PORT
      LAYER M5 ;
        RECT  43.056 172.728 43.08 172.872 ;
    END
  END upo[208]
  PIN upo[209]
    DIRECTION OUTPUT ;
    USE SIGNAL ;
    PORT
      LAYER M5 ;
        RECT  43.248 172.728 43.272 172.872 ;
    END
  END upo[209]
  PIN upo[20]
    DIRECTION OUTPUT ;
    USE SIGNAL ;
    PORT
      LAYER M5 ;
        RECT  7.824 172.728 7.848 172.872 ;
    END
  END upo[20]
  PIN upo[210]
    DIRECTION OUTPUT ;
    USE SIGNAL ;
    PORT
      LAYER M5 ;
        RECT  43.392 172.728 43.416 172.872 ;
    END
  END upo[210]
  PIN upo[211]
    DIRECTION OUTPUT ;
    USE SIGNAL ;
    PORT
      LAYER M5 ;
        RECT  43.584 172.728 43.608 172.872 ;
    END
  END upo[211]
  PIN upo[212]
    DIRECTION OUTPUT ;
    USE SIGNAL ;
    PORT
      LAYER M5 ;
        RECT  43.776 172.728 43.8 172.872 ;
    END
  END upo[212]
  PIN upo[213]
    DIRECTION OUTPUT ;
    USE SIGNAL ;
    PORT
      LAYER M5 ;
        RECT  43.968 172.728 43.992 172.872 ;
    END
  END upo[213]
  PIN upo[214]
    DIRECTION OUTPUT ;
    USE SIGNAL ;
    PORT
      LAYER M5 ;
        RECT  44.16 172.728 44.184 172.872 ;
    END
  END upo[214]
  PIN upo[215]
    DIRECTION OUTPUT ;
    USE SIGNAL ;
    PORT
      LAYER M5 ;
        RECT  44.352 172.728 44.376 172.872 ;
    END
  END upo[215]
  PIN upo[216]
    DIRECTION OUTPUT ;
    USE SIGNAL ;
    PORT
      LAYER M5 ;
        RECT  44.544 172.728 44.568 172.872 ;
    END
  END upo[216]
  PIN upo[217]
    DIRECTION OUTPUT ;
    USE SIGNAL ;
    PORT
      LAYER M5 ;
        RECT  44.736 172.728 44.76 172.872 ;
    END
  END upo[217]
  PIN upo[218]
    DIRECTION OUTPUT ;
    USE SIGNAL ;
    PORT
      LAYER M5 ;
        RECT  44.928 172.728 44.952 172.872 ;
    END
  END upo[218]
  PIN upo[219]
    DIRECTION OUTPUT ;
    USE SIGNAL ;
    PORT
      LAYER M5 ;
        RECT  45.12 172.728 45.144 172.872 ;
    END
  END upo[219]
  PIN upo[21]
    DIRECTION OUTPUT ;
    USE SIGNAL ;
    PORT
      LAYER M5 ;
        RECT  8.016 172.728 8.04 172.872 ;
    END
  END upo[21]
  PIN upo[220]
    DIRECTION OUTPUT ;
    USE SIGNAL ;
    PORT
      LAYER M5 ;
        RECT  45.264 172.728 45.288 172.872 ;
    END
  END upo[220]
  PIN upo[221]
    DIRECTION OUTPUT ;
    USE SIGNAL ;
    PORT
      LAYER M5 ;
        RECT  45.456 172.728 45.48 172.872 ;
    END
  END upo[221]
  PIN upo[222]
    DIRECTION OUTPUT ;
    USE SIGNAL ;
    PORT
      LAYER M5 ;
        RECT  45.648 172.728 45.672 172.872 ;
    END
  END upo[222]
  PIN upo[223]
    DIRECTION OUTPUT ;
    USE SIGNAL ;
    PORT
      LAYER M5 ;
        RECT  45.84 172.728 45.864 172.872 ;
    END
  END upo[223]
  PIN upo[224]
    DIRECTION OUTPUT ;
    USE SIGNAL ;
    PORT
      LAYER M5 ;
        RECT  46.032 172.728 46.056 172.872 ;
    END
  END upo[224]
  PIN upo[225]
    DIRECTION OUTPUT ;
    USE SIGNAL ;
    PORT
      LAYER M5 ;
        RECT  46.224 172.728 46.248 172.872 ;
    END
  END upo[225]
  PIN upo[226]
    DIRECTION OUTPUT ;
    USE SIGNAL ;
    PORT
      LAYER M5 ;
        RECT  46.416 172.728 46.44 172.872 ;
    END
  END upo[226]
  PIN upo[227]
    DIRECTION OUTPUT ;
    USE SIGNAL ;
    PORT
      LAYER M5 ;
        RECT  46.608 172.728 46.632 172.872 ;
    END
  END upo[227]
  PIN upo[228]
    DIRECTION OUTPUT ;
    USE SIGNAL ;
    PORT
      LAYER M5 ;
        RECT  46.8 172.728 46.824 172.872 ;
    END
  END upo[228]
  PIN upo[229]
    DIRECTION OUTPUT ;
    USE SIGNAL ;
    PORT
      LAYER M5 ;
        RECT  46.992 172.728 47.016 172.872 ;
    END
  END upo[229]
  PIN upo[22]
    DIRECTION OUTPUT ;
    USE SIGNAL ;
    PORT
      LAYER M5 ;
        RECT  8.208 172.728 8.232 172.872 ;
    END
  END upo[22]
  PIN upo[230]
    DIRECTION OUTPUT ;
    USE SIGNAL ;
    PORT
      LAYER M5 ;
        RECT  47.136 172.728 47.16 172.872 ;
    END
  END upo[230]
  PIN upo[231]
    DIRECTION OUTPUT ;
    USE SIGNAL ;
    PORT
      LAYER M5 ;
        RECT  47.328 172.728 47.352 172.872 ;
    END
  END upo[231]
  PIN upo[232]
    DIRECTION OUTPUT ;
    USE SIGNAL ;
    PORT
      LAYER M5 ;
        RECT  47.52 172.728 47.544 172.872 ;
    END
  END upo[232]
  PIN upo[233]
    DIRECTION OUTPUT ;
    USE SIGNAL ;
    PORT
      LAYER M5 ;
        RECT  47.712 172.728 47.736 172.872 ;
    END
  END upo[233]
  PIN upo[234]
    DIRECTION OUTPUT ;
    USE SIGNAL ;
    PORT
      LAYER M5 ;
        RECT  47.904 172.728 47.928 172.872 ;
    END
  END upo[234]
  PIN upo[235]
    DIRECTION OUTPUT ;
    USE SIGNAL ;
    PORT
      LAYER M5 ;
        RECT  48.096 172.728 48.12 172.872 ;
    END
  END upo[235]
  PIN upo[236]
    DIRECTION OUTPUT ;
    USE SIGNAL ;
    PORT
      LAYER M5 ;
        RECT  48.288 172.728 48.312 172.872 ;
    END
  END upo[236]
  PIN upo[237]
    DIRECTION OUTPUT ;
    USE SIGNAL ;
    PORT
      LAYER M5 ;
        RECT  48.48 172.728 48.504 172.872 ;
    END
  END upo[237]
  PIN upo[238]
    DIRECTION OUTPUT ;
    USE SIGNAL ;
    PORT
      LAYER M5 ;
        RECT  48.672 172.728 48.696 172.872 ;
    END
  END upo[238]
  PIN upo[239]
    DIRECTION OUTPUT ;
    USE SIGNAL ;
    PORT
      LAYER M5 ;
        RECT  48.864 172.728 48.888 172.872 ;
    END
  END upo[239]
  PIN upo[23]
    DIRECTION OUTPUT ;
    USE SIGNAL ;
    PORT
      LAYER M5 ;
        RECT  8.4 172.728 8.424 172.872 ;
    END
  END upo[23]
  PIN upo[240]
    DIRECTION OUTPUT ;
    USE SIGNAL ;
    PORT
      LAYER M5 ;
        RECT  49.008 172.728 49.032 172.872 ;
    END
  END upo[240]
  PIN upo[241]
    DIRECTION OUTPUT ;
    USE SIGNAL ;
    PORT
      LAYER M5 ;
        RECT  49.2 172.728 49.224 172.872 ;
    END
  END upo[241]
  PIN upo[242]
    DIRECTION OUTPUT ;
    USE SIGNAL ;
    PORT
      LAYER M5 ;
        RECT  49.392 172.728 49.416 172.872 ;
    END
  END upo[242]
  PIN upo[243]
    DIRECTION OUTPUT ;
    USE SIGNAL ;
    PORT
      LAYER M5 ;
        RECT  49.584 172.728 49.608 172.872 ;
    END
  END upo[243]
  PIN upo[244]
    DIRECTION OUTPUT ;
    USE SIGNAL ;
    PORT
      LAYER M5 ;
        RECT  49.776 172.728 49.8 172.872 ;
    END
  END upo[244]
  PIN upo[245]
    DIRECTION OUTPUT ;
    USE SIGNAL ;
    PORT
      LAYER M5 ;
        RECT  49.968 172.728 49.992 172.872 ;
    END
  END upo[245]
  PIN upo[246]
    DIRECTION OUTPUT ;
    USE SIGNAL ;
    PORT
      LAYER M5 ;
        RECT  50.16 172.728 50.184 172.872 ;
    END
  END upo[246]
  PIN upo[247]
    DIRECTION OUTPUT ;
    USE SIGNAL ;
    PORT
      LAYER M5 ;
        RECT  50.352 172.728 50.376 172.872 ;
    END
  END upo[247]
  PIN upo[248]
    DIRECTION OUTPUT ;
    USE SIGNAL ;
    PORT
      LAYER M5 ;
        RECT  50.544 172.728 50.568 172.872 ;
    END
  END upo[248]
  PIN upo[249]
    DIRECTION OUTPUT ;
    USE SIGNAL ;
    PORT
      LAYER M5 ;
        RECT  50.736 172.728 50.76 172.872 ;
    END
  END upo[249]
  PIN upo[24]
    DIRECTION OUTPUT ;
    USE SIGNAL ;
    PORT
      LAYER M5 ;
        RECT  8.592 172.728 8.616 172.872 ;
    END
  END upo[24]
  PIN upo[250]
    DIRECTION OUTPUT ;
    USE SIGNAL ;
    PORT
      LAYER M5 ;
        RECT  50.928 172.728 50.952 172.872 ;
    END
  END upo[250]
  PIN upo[251]
    DIRECTION OUTPUT ;
    USE SIGNAL ;
    PORT
      LAYER M5 ;
        RECT  51.072 172.728 51.096 172.872 ;
    END
  END upo[251]
  PIN upo[252]
    DIRECTION OUTPUT ;
    USE SIGNAL ;
    PORT
      LAYER M5 ;
        RECT  51.264 172.728 51.288 172.872 ;
    END
  END upo[252]
  PIN upo[253]
    DIRECTION OUTPUT ;
    USE SIGNAL ;
    PORT
      LAYER M5 ;
        RECT  51.456 172.728 51.48 172.872 ;
    END
  END upo[253]
  PIN upo[254]
    DIRECTION OUTPUT ;
    USE SIGNAL ;
    PORT
      LAYER M5 ;
        RECT  51.648 172.728 51.672 172.872 ;
    END
  END upo[254]
  PIN upo[255]
    DIRECTION OUTPUT ;
    USE SIGNAL ;
    PORT
      LAYER M5 ;
        RECT  51.84 172.728 51.864 172.872 ;
    END
  END upo[255]
  PIN upo[256]
    DIRECTION OUTPUT ;
    USE SIGNAL ;
    PORT
      LAYER M5 ;
        RECT  52.032 172.728 52.056 172.872 ;
    END
  END upo[256]
  PIN upo[257]
    DIRECTION OUTPUT ;
    USE SIGNAL ;
    PORT
      LAYER M5 ;
        RECT  52.224 172.728 52.248 172.872 ;
    END
  END upo[257]
  PIN upo[258]
    DIRECTION OUTPUT ;
    USE SIGNAL ;
    PORT
      LAYER M5 ;
        RECT  52.416 172.728 52.44 172.872 ;
    END
  END upo[258]
  PIN upo[259]
    DIRECTION OUTPUT ;
    USE SIGNAL ;
    PORT
      LAYER M5 ;
        RECT  52.608 172.728 52.632 172.872 ;
    END
  END upo[259]
  PIN upo[25]
    DIRECTION OUTPUT ;
    USE SIGNAL ;
    PORT
      LAYER M5 ;
        RECT  8.784 172.728 8.808 172.872 ;
    END
  END upo[25]
  PIN upo[260]
    DIRECTION OUTPUT ;
    USE SIGNAL ;
    PORT
      LAYER M5 ;
        RECT  52.8 172.728 52.824 172.872 ;
    END
  END upo[260]
  PIN upo[261]
    DIRECTION OUTPUT ;
    USE SIGNAL ;
    PORT
      LAYER M5 ;
        RECT  52.944 172.728 52.968 172.872 ;
    END
  END upo[261]
  PIN upo[262]
    DIRECTION OUTPUT ;
    USE SIGNAL ;
    PORT
      LAYER M5 ;
        RECT  53.136 172.728 53.16 172.872 ;
    END
  END upo[262]
  PIN upo[263]
    DIRECTION OUTPUT ;
    USE SIGNAL ;
    PORT
      LAYER M5 ;
        RECT  53.328 172.728 53.352 172.872 ;
    END
  END upo[263]
  PIN upo[264]
    DIRECTION OUTPUT ;
    USE SIGNAL ;
    PORT
      LAYER M5 ;
        RECT  53.52 172.728 53.544 172.872 ;
    END
  END upo[264]
  PIN upo[265]
    DIRECTION OUTPUT ;
    USE SIGNAL ;
    PORT
      LAYER M5 ;
        RECT  53.712 172.728 53.736 172.872 ;
    END
  END upo[265]
  PIN upo[266]
    DIRECTION OUTPUT ;
    USE SIGNAL ;
    PORT
      LAYER M5 ;
        RECT  53.904 172.728 53.928 172.872 ;
    END
  END upo[266]
  PIN upo[267]
    DIRECTION OUTPUT ;
    USE SIGNAL ;
    PORT
      LAYER M5 ;
        RECT  54.096 172.728 54.12 172.872 ;
    END
  END upo[267]
  PIN upo[268]
    DIRECTION OUTPUT ;
    USE SIGNAL ;
    PORT
      LAYER M5 ;
        RECT  54.288 172.728 54.312 172.872 ;
    END
  END upo[268]
  PIN upo[269]
    DIRECTION OUTPUT ;
    USE SIGNAL ;
    PORT
      LAYER M5 ;
        RECT  54.48 172.728 54.504 172.872 ;
    END
  END upo[269]
  PIN upo[26]
    DIRECTION OUTPUT ;
    USE SIGNAL ;
    PORT
      LAYER M5 ;
        RECT  8.928 172.728 8.952 172.872 ;
    END
  END upo[26]
  PIN upo[270]
    DIRECTION OUTPUT ;
    USE SIGNAL ;
    PORT
      LAYER M5 ;
        RECT  54.672 172.728 54.696 172.872 ;
    END
  END upo[270]
  PIN upo[271]
    DIRECTION OUTPUT ;
    USE SIGNAL ;
    PORT
      LAYER M5 ;
        RECT  54.816 172.728 54.84 172.872 ;
    END
  END upo[271]
  PIN upo[272]
    DIRECTION OUTPUT ;
    USE SIGNAL ;
    PORT
      LAYER M5 ;
        RECT  55.008 172.728 55.032 172.872 ;
    END
  END upo[272]
  PIN upo[273]
    DIRECTION OUTPUT ;
    USE SIGNAL ;
    PORT
      LAYER M5 ;
        RECT  55.2 172.728 55.224 172.872 ;
    END
  END upo[273]
  PIN upo[274]
    DIRECTION OUTPUT ;
    USE SIGNAL ;
    PORT
      LAYER M5 ;
        RECT  55.392 172.728 55.416 172.872 ;
    END
  END upo[274]
  PIN upo[275]
    DIRECTION OUTPUT ;
    USE SIGNAL ;
    PORT
      LAYER M5 ;
        RECT  55.584 172.728 55.608 172.872 ;
    END
  END upo[275]
  PIN upo[276]
    DIRECTION OUTPUT ;
    USE SIGNAL ;
    PORT
      LAYER M5 ;
        RECT  55.776 172.728 55.8 172.872 ;
    END
  END upo[276]
  PIN upo[277]
    DIRECTION OUTPUT ;
    USE SIGNAL ;
    PORT
      LAYER M5 ;
        RECT  55.968 172.728 55.992 172.872 ;
    END
  END upo[277]
  PIN upo[278]
    DIRECTION OUTPUT ;
    USE SIGNAL ;
    PORT
      LAYER M5 ;
        RECT  56.16 172.728 56.184 172.872 ;
    END
  END upo[278]
  PIN upo[279]
    DIRECTION OUTPUT ;
    USE SIGNAL ;
    PORT
      LAYER M5 ;
        RECT  56.352 172.728 56.376 172.872 ;
    END
  END upo[279]
  PIN upo[27]
    DIRECTION OUTPUT ;
    USE SIGNAL ;
    PORT
      LAYER M5 ;
        RECT  9.12 172.728 9.144 172.872 ;
    END
  END upo[27]
  PIN upo[280]
    DIRECTION OUTPUT ;
    USE SIGNAL ;
    PORT
      LAYER M5 ;
        RECT  56.544 172.728 56.568 172.872 ;
    END
  END upo[280]
  PIN upo[281]
    DIRECTION OUTPUT ;
    USE SIGNAL ;
    PORT
      LAYER M5 ;
        RECT  56.688 172.728 56.712 172.872 ;
    END
  END upo[281]
  PIN upo[282]
    DIRECTION OUTPUT ;
    USE SIGNAL ;
    PORT
      LAYER M5 ;
        RECT  56.88 172.728 56.904 172.872 ;
    END
  END upo[282]
  PIN upo[283]
    DIRECTION OUTPUT ;
    USE SIGNAL ;
    PORT
      LAYER M5 ;
        RECT  57.072 172.728 57.096 172.872 ;
    END
  END upo[283]
  PIN upo[284]
    DIRECTION OUTPUT ;
    USE SIGNAL ;
    PORT
      LAYER M5 ;
        RECT  57.264 172.728 57.288 172.872 ;
    END
  END upo[284]
  PIN upo[285]
    DIRECTION OUTPUT ;
    USE SIGNAL ;
    PORT
      LAYER M5 ;
        RECT  57.456 172.728 57.48 172.872 ;
    END
  END upo[285]
  PIN upo[286]
    DIRECTION OUTPUT ;
    USE SIGNAL ;
    PORT
      LAYER M5 ;
        RECT  57.648 172.728 57.672 172.872 ;
    END
  END upo[286]
  PIN upo[287]
    DIRECTION OUTPUT ;
    USE SIGNAL ;
    PORT
      LAYER M5 ;
        RECT  57.84 172.728 57.864 172.872 ;
    END
  END upo[287]
  PIN upo[288]
    DIRECTION OUTPUT ;
    USE SIGNAL ;
    PORT
      LAYER M5 ;
        RECT  58.032 172.728 58.056 172.872 ;
    END
  END upo[288]
  PIN upo[289]
    DIRECTION OUTPUT ;
    USE SIGNAL ;
    PORT
      LAYER M5 ;
        RECT  58.224 172.728 58.248 172.872 ;
    END
  END upo[289]
  PIN upo[28]
    DIRECTION OUTPUT ;
    USE SIGNAL ;
    PORT
      LAYER M5 ;
        RECT  9.312 172.728 9.336 172.872 ;
    END
  END upo[28]
  PIN upo[290]
    DIRECTION OUTPUT ;
    USE SIGNAL ;
    PORT
      LAYER M5 ;
        RECT  58.416 172.728 58.44 172.872 ;
    END
  END upo[290]
  PIN upo[291]
    DIRECTION OUTPUT ;
    USE SIGNAL ;
    PORT
      LAYER M5 ;
        RECT  58.56 172.728 58.584 172.872 ;
    END
  END upo[291]
  PIN upo[292]
    DIRECTION OUTPUT ;
    USE SIGNAL ;
    PORT
      LAYER M5 ;
        RECT  58.752 172.728 58.776 172.872 ;
    END
  END upo[292]
  PIN upo[293]
    DIRECTION OUTPUT ;
    USE SIGNAL ;
    PORT
      LAYER M5 ;
        RECT  58.944 172.728 58.968 172.872 ;
    END
  END upo[293]
  PIN upo[294]
    DIRECTION OUTPUT ;
    USE SIGNAL ;
    PORT
      LAYER M5 ;
        RECT  59.136 172.728 59.16 172.872 ;
    END
  END upo[294]
  PIN upo[295]
    DIRECTION OUTPUT ;
    USE SIGNAL ;
    PORT
      LAYER M5 ;
        RECT  59.328 172.728 59.352 172.872 ;
    END
  END upo[295]
  PIN upo[296]
    DIRECTION OUTPUT ;
    USE SIGNAL ;
    PORT
      LAYER M5 ;
        RECT  59.52 172.728 59.544 172.872 ;
    END
  END upo[296]
  PIN upo[297]
    DIRECTION OUTPUT ;
    USE SIGNAL ;
    PORT
      LAYER M5 ;
        RECT  59.712 172.728 59.736 172.872 ;
    END
  END upo[297]
  PIN upo[298]
    DIRECTION OUTPUT ;
    USE SIGNAL ;
    PORT
      LAYER M5 ;
        RECT  59.904 172.728 59.928 172.872 ;
    END
  END upo[298]
  PIN upo[29]
    DIRECTION OUTPUT ;
    USE SIGNAL ;
    PORT
      LAYER M5 ;
        RECT  9.504 172.728 9.528 172.872 ;
    END
  END upo[29]
  PIN upo[2]
    DIRECTION OUTPUT ;
    USE SIGNAL ;
    PORT
      LAYER M5 ;
        RECT  4.464 172.728 4.488 172.872 ;
    END
  END upo[2]
  PIN upo[30]
    DIRECTION OUTPUT ;
    USE SIGNAL ;
    PORT
      LAYER M5 ;
        RECT  9.696 172.728 9.72 172.872 ;
    END
  END upo[30]
  PIN upo[31]
    DIRECTION OUTPUT ;
    USE SIGNAL ;
    PORT
      LAYER M5 ;
        RECT  9.888 172.728 9.912 172.872 ;
    END
  END upo[31]
  PIN upo[32]
    DIRECTION OUTPUT ;
    USE SIGNAL ;
    PORT
      LAYER M5 ;
        RECT  10.08 172.728 10.104 172.872 ;
    END
  END upo[32]
  PIN upo[33]
    DIRECTION OUTPUT ;
    USE SIGNAL ;
    PORT
      LAYER M5 ;
        RECT  10.272 172.728 10.296 172.872 ;
    END
  END upo[33]
  PIN upo[34]
    DIRECTION OUTPUT ;
    USE SIGNAL ;
    PORT
      LAYER M5 ;
        RECT  10.464 172.728 10.488 172.872 ;
    END
  END upo[34]
  PIN upo[35]
    DIRECTION OUTPUT ;
    USE SIGNAL ;
    PORT
      LAYER M5 ;
        RECT  10.656 172.728 10.68 172.872 ;
    END
  END upo[35]
  PIN upo[36]
    DIRECTION OUTPUT ;
    USE SIGNAL ;
    PORT
      LAYER M5 ;
        RECT  10.848 172.728 10.872 172.872 ;
    END
  END upo[36]
  PIN upo[37]
    DIRECTION OUTPUT ;
    USE SIGNAL ;
    PORT
      LAYER M5 ;
        RECT  10.992 172.728 11.016 172.872 ;
    END
  END upo[37]
  PIN upo[38]
    DIRECTION OUTPUT ;
    USE SIGNAL ;
    PORT
      LAYER M5 ;
        RECT  11.184 172.728 11.208 172.872 ;
    END
  END upo[38]
  PIN upo[39]
    DIRECTION OUTPUT ;
    USE SIGNAL ;
    PORT
      LAYER M5 ;
        RECT  11.376 172.728 11.4 172.872 ;
    END
  END upo[39]
  PIN upo[3]
    DIRECTION OUTPUT ;
    USE SIGNAL ;
    PORT
      LAYER M5 ;
        RECT  4.656 172.728 4.68 172.872 ;
    END
  END upo[3]
  PIN upo[40]
    DIRECTION OUTPUT ;
    USE SIGNAL ;
    PORT
      LAYER M5 ;
        RECT  11.568 172.728 11.592 172.872 ;
    END
  END upo[40]
  PIN upo[41]
    DIRECTION OUTPUT ;
    USE SIGNAL ;
    PORT
      LAYER M5 ;
        RECT  11.76 172.728 11.784 172.872 ;
    END
  END upo[41]
  PIN upo[42]
    DIRECTION OUTPUT ;
    USE SIGNAL ;
    PORT
      LAYER M5 ;
        RECT  11.952 172.728 11.976 172.872 ;
    END
  END upo[42]
  PIN upo[43]
    DIRECTION OUTPUT ;
    USE SIGNAL ;
    PORT
      LAYER M5 ;
        RECT  12.144 172.728 12.168 172.872 ;
    END
  END upo[43]
  PIN upo[44]
    DIRECTION OUTPUT ;
    USE SIGNAL ;
    PORT
      LAYER M5 ;
        RECT  12.336 172.728 12.36 172.872 ;
    END
  END upo[44]
  PIN upo[45]
    DIRECTION OUTPUT ;
    USE SIGNAL ;
    PORT
      LAYER M5 ;
        RECT  12.528 172.728 12.552 172.872 ;
    END
  END upo[45]
  PIN upo[46]
    DIRECTION OUTPUT ;
    USE SIGNAL ;
    PORT
      LAYER M5 ;
        RECT  12.72 172.728 12.744 172.872 ;
    END
  END upo[46]
  PIN upo[47]
    DIRECTION OUTPUT ;
    USE SIGNAL ;
    PORT
      LAYER M5 ;
        RECT  12.864 172.728 12.888 172.872 ;
    END
  END upo[47]
  PIN upo[48]
    DIRECTION OUTPUT ;
    USE SIGNAL ;
    PORT
      LAYER M5 ;
        RECT  13.056 172.728 13.08 172.872 ;
    END
  END upo[48]
  PIN upo[49]
    DIRECTION OUTPUT ;
    USE SIGNAL ;
    PORT
      LAYER M5 ;
        RECT  13.248 172.728 13.272 172.872 ;
    END
  END upo[49]
  PIN upo[4]
    DIRECTION OUTPUT ;
    USE SIGNAL ;
    PORT
      LAYER M5 ;
        RECT  4.848 172.728 4.872 172.872 ;
    END
  END upo[4]
  PIN upo[50]
    DIRECTION OUTPUT ;
    USE SIGNAL ;
    PORT
      LAYER M5 ;
        RECT  13.44 172.728 13.464 172.872 ;
    END
  END upo[50]
  PIN upo[51]
    DIRECTION OUTPUT ;
    USE SIGNAL ;
    PORT
      LAYER M5 ;
        RECT  13.632 172.728 13.656 172.872 ;
    END
  END upo[51]
  PIN upo[52]
    DIRECTION OUTPUT ;
    USE SIGNAL ;
    PORT
      LAYER M5 ;
        RECT  13.824 172.728 13.848 172.872 ;
    END
  END upo[52]
  PIN upo[53]
    DIRECTION OUTPUT ;
    USE SIGNAL ;
    PORT
      LAYER M5 ;
        RECT  14.016 172.728 14.04 172.872 ;
    END
  END upo[53]
  PIN upo[54]
    DIRECTION OUTPUT ;
    USE SIGNAL ;
    PORT
      LAYER M5 ;
        RECT  14.208 172.728 14.232 172.872 ;
    END
  END upo[54]
  PIN upo[55]
    DIRECTION OUTPUT ;
    USE SIGNAL ;
    PORT
      LAYER M5 ;
        RECT  14.4 172.728 14.424 172.872 ;
    END
  END upo[55]
  PIN upo[56]
    DIRECTION OUTPUT ;
    USE SIGNAL ;
    PORT
      LAYER M5 ;
        RECT  14.592 172.728 14.616 172.872 ;
    END
  END upo[56]
  PIN upo[57]
    DIRECTION OUTPUT ;
    USE SIGNAL ;
    PORT
      LAYER M5 ;
        RECT  14.736 172.728 14.76 172.872 ;
    END
  END upo[57]
  PIN upo[58]
    DIRECTION OUTPUT ;
    USE SIGNAL ;
    PORT
      LAYER M5 ;
        RECT  14.928 172.728 14.952 172.872 ;
    END
  END upo[58]
  PIN upo[59]
    DIRECTION OUTPUT ;
    USE SIGNAL ;
    PORT
      LAYER M5 ;
        RECT  15.12 172.728 15.144 172.872 ;
    END
  END upo[59]
  PIN upo[5]
    DIRECTION OUTPUT ;
    USE SIGNAL ;
    PORT
      LAYER M5 ;
        RECT  5.04 172.728 5.064 172.872 ;
    END
  END upo[5]
  PIN upo[60]
    DIRECTION OUTPUT ;
    USE SIGNAL ;
    PORT
      LAYER M5 ;
        RECT  15.312 172.728 15.336 172.872 ;
    END
  END upo[60]
  PIN upo[61]
    DIRECTION OUTPUT ;
    USE SIGNAL ;
    PORT
      LAYER M5 ;
        RECT  15.504 172.728 15.528 172.872 ;
    END
  END upo[61]
  PIN upo[62]
    DIRECTION OUTPUT ;
    USE SIGNAL ;
    PORT
      LAYER M5 ;
        RECT  15.696 172.728 15.72 172.872 ;
    END
  END upo[62]
  PIN upo[63]
    DIRECTION OUTPUT ;
    USE SIGNAL ;
    PORT
      LAYER M5 ;
        RECT  15.888 172.728 15.912 172.872 ;
    END
  END upo[63]
  PIN upo[64]
    DIRECTION OUTPUT ;
    USE SIGNAL ;
    PORT
      LAYER M5 ;
        RECT  16.08 172.728 16.104 172.872 ;
    END
  END upo[64]
  PIN upo[65]
    DIRECTION OUTPUT ;
    USE SIGNAL ;
    PORT
      LAYER M5 ;
        RECT  16.272 172.728 16.296 172.872 ;
    END
  END upo[65]
  PIN upo[66]
    DIRECTION OUTPUT ;
    USE SIGNAL ;
    PORT
      LAYER M5 ;
        RECT  16.464 172.728 16.488 172.872 ;
    END
  END upo[66]
  PIN upo[67]
    DIRECTION OUTPUT ;
    USE SIGNAL ;
    PORT
      LAYER M5 ;
        RECT  16.608 172.728 16.632 172.872 ;
    END
  END upo[67]
  PIN upo[68]
    DIRECTION OUTPUT ;
    USE SIGNAL ;
    PORT
      LAYER M5 ;
        RECT  16.8 172.728 16.824 172.872 ;
    END
  END upo[68]
  PIN upo[69]
    DIRECTION OUTPUT ;
    USE SIGNAL ;
    PORT
      LAYER M5 ;
        RECT  16.992 172.728 17.016 172.872 ;
    END
  END upo[69]
  PIN upo[6]
    DIRECTION OUTPUT ;
    USE SIGNAL ;
    PORT
      LAYER M5 ;
        RECT  5.184 172.728 5.208 172.872 ;
    END
  END upo[6]
  PIN upo[70]
    DIRECTION OUTPUT ;
    USE SIGNAL ;
    PORT
      LAYER M5 ;
        RECT  17.184 172.728 17.208 172.872 ;
    END
  END upo[70]
  PIN upo[71]
    DIRECTION OUTPUT ;
    USE SIGNAL ;
    PORT
      LAYER M5 ;
        RECT  17.376 172.728 17.4 172.872 ;
    END
  END upo[71]
  PIN upo[72]
    DIRECTION OUTPUT ;
    USE SIGNAL ;
    PORT
      LAYER M5 ;
        RECT  17.568 172.728 17.592 172.872 ;
    END
  END upo[72]
  PIN upo[73]
    DIRECTION OUTPUT ;
    USE SIGNAL ;
    PORT
      LAYER M5 ;
        RECT  17.76 172.728 17.784 172.872 ;
    END
  END upo[73]
  PIN upo[74]
    DIRECTION OUTPUT ;
    USE SIGNAL ;
    PORT
      LAYER M5 ;
        RECT  17.952 172.728 17.976 172.872 ;
    END
  END upo[74]
  PIN upo[75]
    DIRECTION OUTPUT ;
    USE SIGNAL ;
    PORT
      LAYER M5 ;
        RECT  18.144 172.728 18.168 172.872 ;
    END
  END upo[75]
  PIN upo[76]
    DIRECTION OUTPUT ;
    USE SIGNAL ;
    PORT
      LAYER M5 ;
        RECT  18.336 172.728 18.36 172.872 ;
    END
  END upo[76]
  PIN upo[77]
    DIRECTION OUTPUT ;
    USE SIGNAL ;
    PORT
      LAYER M5 ;
        RECT  18.48 172.728 18.504 172.872 ;
    END
  END upo[77]
  PIN upo[78]
    DIRECTION OUTPUT ;
    USE SIGNAL ;
    PORT
      LAYER M5 ;
        RECT  18.672 172.728 18.696 172.872 ;
    END
  END upo[78]
  PIN upo[79]
    DIRECTION OUTPUT ;
    USE SIGNAL ;
    PORT
      LAYER M5 ;
        RECT  18.864 172.728 18.888 172.872 ;
    END
  END upo[79]
  PIN upo[7]
    DIRECTION OUTPUT ;
    USE SIGNAL ;
    PORT
      LAYER M5 ;
        RECT  5.376 172.728 5.4 172.872 ;
    END
  END upo[7]
  PIN upo[80]
    DIRECTION OUTPUT ;
    USE SIGNAL ;
    PORT
      LAYER M5 ;
        RECT  19.056 172.728 19.08 172.872 ;
    END
  END upo[80]
  PIN upo[81]
    DIRECTION OUTPUT ;
    USE SIGNAL ;
    PORT
      LAYER M5 ;
        RECT  19.248 172.728 19.272 172.872 ;
    END
  END upo[81]
  PIN upo[82]
    DIRECTION OUTPUT ;
    USE SIGNAL ;
    PORT
      LAYER M5 ;
        RECT  19.44 172.728 19.464 172.872 ;
    END
  END upo[82]
  PIN upo[83]
    DIRECTION OUTPUT ;
    USE SIGNAL ;
    PORT
      LAYER M5 ;
        RECT  19.632 172.728 19.656 172.872 ;
    END
  END upo[83]
  PIN upo[84]
    DIRECTION OUTPUT ;
    USE SIGNAL ;
    PORT
      LAYER M5 ;
        RECT  19.824 172.728 19.848 172.872 ;
    END
  END upo[84]
  PIN upo[85]
    DIRECTION OUTPUT ;
    USE SIGNAL ;
    PORT
      LAYER M5 ;
        RECT  20.016 172.728 20.04 172.872 ;
    END
  END upo[85]
  PIN upo[86]
    DIRECTION OUTPUT ;
    USE SIGNAL ;
    PORT
      LAYER M5 ;
        RECT  20.208 172.728 20.232 172.872 ;
    END
  END upo[86]
  PIN upo[87]
    DIRECTION OUTPUT ;
    USE SIGNAL ;
    PORT
      LAYER M5 ;
        RECT  20.352 172.728 20.376 172.872 ;
    END
  END upo[87]
  PIN upo[88]
    DIRECTION OUTPUT ;
    USE SIGNAL ;
    PORT
      LAYER M5 ;
        RECT  20.544 172.728 20.568 172.872 ;
    END
  END upo[88]
  PIN upo[89]
    DIRECTION OUTPUT ;
    USE SIGNAL ;
    PORT
      LAYER M5 ;
        RECT  20.736 172.728 20.76 172.872 ;
    END
  END upo[89]
  PIN upo[8]
    DIRECTION OUTPUT ;
    USE SIGNAL ;
    PORT
      LAYER M5 ;
        RECT  5.568 172.728 5.592 172.872 ;
    END
  END upo[8]
  PIN upo[90]
    DIRECTION OUTPUT ;
    USE SIGNAL ;
    PORT
      LAYER M5 ;
        RECT  20.928 172.728 20.952 172.872 ;
    END
  END upo[90]
  PIN upo[91]
    DIRECTION OUTPUT ;
    USE SIGNAL ;
    PORT
      LAYER M5 ;
        RECT  21.12 172.728 21.144 172.872 ;
    END
  END upo[91]
  PIN upo[92]
    DIRECTION OUTPUT ;
    USE SIGNAL ;
    PORT
      LAYER M5 ;
        RECT  21.312 172.728 21.336 172.872 ;
    END
  END upo[92]
  PIN upo[93]
    DIRECTION OUTPUT ;
    USE SIGNAL ;
    PORT
      LAYER M5 ;
        RECT  21.504 172.728 21.528 172.872 ;
    END
  END upo[93]
  PIN upo[94]
    DIRECTION OUTPUT ;
    USE SIGNAL ;
    PORT
      LAYER M5 ;
        RECT  21.696 172.728 21.72 172.872 ;
    END
  END upo[94]
  PIN upo[95]
    DIRECTION OUTPUT ;
    USE SIGNAL ;
    PORT
      LAYER M5 ;
        RECT  21.888 172.728 21.912 172.872 ;
    END
  END upo[95]
  PIN upo[96]
    DIRECTION OUTPUT ;
    USE SIGNAL ;
    PORT
      LAYER M5 ;
        RECT  22.08 172.728 22.104 172.872 ;
    END
  END upo[96]
  PIN upo[97]
    DIRECTION OUTPUT ;
    USE SIGNAL ;
    PORT
      LAYER M5 ;
        RECT  22.272 172.728 22.296 172.872 ;
    END
  END upo[97]
  PIN upo[98]
    DIRECTION OUTPUT ;
    USE SIGNAL ;
    PORT
      LAYER M5 ;
        RECT  22.416 172.728 22.44 172.872 ;
    END
  END upo[98]
  PIN upo[99]
    DIRECTION OUTPUT ;
    USE SIGNAL ;
    PORT
      LAYER M5 ;
        RECT  22.608 172.728 22.632 172.872 ;
    END
  END upo[99]
  PIN upo[9]
    DIRECTION OUTPUT ;
    USE SIGNAL ;
    PORT
      LAYER M5 ;
        RECT  5.76 172.728 5.784 172.872 ;
    END
  END upo[9]
  PIN VDD
    DIRECTION INOUT ;
    USE POWER ;
    PORT
      LAYER M5 ;
        RECT  61.992 2.151 62.112 170.649 ;
        RECT  56.592 2.151 56.712 170.649 ;
        RECT  51.192 2.151 51.312 170.649 ;
        RECT  45.792 2.151 45.912 170.649 ;
        RECT  40.392 2.151 40.512 170.649 ;
        RECT  34.992 2.151 35.112 170.649 ;
        RECT  29.592 2.151 29.712 170.649 ;
        RECT  24.192 2.151 24.312 170.649 ;
        RECT  18.792 2.151 18.912 170.649 ;
        RECT  13.392 2.151 13.512 170.649 ;
        RECT  7.992 2.151 8.112 170.649 ;
        RECT  2.592 2.151 2.712 170.649 ;
    END
  END VDD
  PIN VSS
    DIRECTION INOUT ;
    USE GROUND ;
    PORT
      LAYER M5 ;
        RECT  61.8 2.137 61.92 170.663 ;
        RECT  56.4 2.137 56.52 170.663 ;
        RECT  51 2.137 51.12 170.663 ;
        RECT  45.6 2.137 45.72 170.663 ;
        RECT  40.2 2.137 40.32 170.663 ;
        RECT  34.8 2.137 34.92 170.663 ;
        RECT  29.4 2.137 29.52 170.663 ;
        RECT  24 2.137 24.12 170.663 ;
        RECT  18.6 2.137 18.72 170.663 ;
        RECT  13.2 2.137 13.32 170.663 ;
        RECT  7.8 2.137 7.92 170.663 ;
        RECT  2.4 2.137 2.52 170.663 ;
    END
  END VSS
  # OT_OBS_CLOSED layer=M5 d_um=1.536 added=188
  OBS
    LAYER RVTN ;
     RECT  2.16 2.16 62.64 2.295 ;
     RECT  2.16 2.565 62.64 2.835 ;
     RECT  2.16 3.105 62.64 3.375 ;
     RECT  2.16 3.645 62.64 3.915 ;
     RECT  2.16 4.185 62.64 4.455 ;
     RECT  2.16 4.725 62.64 4.995 ;
     RECT  2.16 5.265 62.64 5.535 ;
     RECT  2.16 5.805 62.64 6.075 ;
     RECT  2.16 6.345 62.64 6.615 ;
     RECT  2.16 6.885 62.64 7.155 ;
     RECT  2.16 7.425 62.64 7.695 ;
     RECT  2.16 7.965 62.64 8.235 ;
     RECT  2.16 8.505 62.64 8.775 ;
     RECT  2.16 9.045 62.64 9.315 ;
     RECT  2.16 9.585 62.64 9.855 ;
     RECT  2.16 10.125 62.64 10.395 ;
     RECT  2.16 10.665 62.64 10.935 ;
     RECT  2.16 11.205 62.64 11.475 ;
     RECT  2.16 11.745 62.64 12.015 ;
     RECT  2.16 12.285 62.64 12.555 ;
     RECT  2.16 12.825 62.64 13.095 ;
     RECT  2.16 13.365 62.64 13.635 ;
     RECT  2.16 13.905 62.64 14.175 ;
     RECT  2.16 14.445 62.64 14.715 ;
     RECT  2.16 14.985 62.64 15.255 ;
     RECT  2.16 15.525 62.64 15.795 ;
     RECT  2.16 16.065 62.64 16.335 ;
     RECT  2.16 16.605 62.64 16.875 ;
     RECT  2.16 17.145 62.64 17.415 ;
     RECT  2.16 17.685 62.64 17.955 ;
     RECT  2.16 18.225 62.64 18.495 ;
     RECT  2.16 18.765 62.64 19.035 ;
     RECT  2.16 19.305 62.64 19.575 ;
     RECT  2.16 19.845 62.64 20.115 ;
     RECT  2.16 20.385 62.64 20.655 ;
     RECT  2.16 20.925 62.64 21.195 ;
     RECT  2.16 21.465 62.64 21.735 ;
     RECT  2.16 22.005 62.64 22.275 ;
     RECT  2.16 22.545 62.64 22.815 ;
     RECT  2.16 23.085 62.64 23.355 ;
     RECT  2.16 23.625 62.64 23.895 ;
     RECT  2.16 24.165 62.64 24.435 ;
     RECT  2.16 24.705 62.64 24.975 ;
     RECT  2.16 25.245 62.64 25.515 ;
     RECT  2.16 25.785 62.64 26.055 ;
     RECT  2.16 26.325 62.64 26.595 ;
     RECT  2.16 26.865 62.64 27.135 ;
     RECT  2.16 27.405 62.64 27.675 ;
     RECT  2.16 27.945 62.64 28.215 ;
     RECT  2.16 28.485 62.64 28.755 ;
     RECT  2.16 29.025 62.64 29.295 ;
     RECT  2.16 29.565 62.64 29.835 ;
     RECT  2.16 30.105 62.64 30.375 ;
     RECT  2.16 30.645 62.64 30.915 ;
     RECT  2.16 31.185 62.64 31.455 ;
     RECT  2.16 31.725 62.64 31.995 ;
     RECT  2.16 32.265 62.64 32.535 ;
     RECT  2.16 32.805 62.64 33.075 ;
     RECT  2.16 33.345 62.64 33.615 ;
     RECT  2.16 33.885 62.64 34.155 ;
     RECT  2.16 34.425 62.64 34.695 ;
     RECT  2.16 34.965 62.64 35.235 ;
     RECT  2.16 35.505 62.64 35.775 ;
     RECT  2.16 36.045 62.64 36.315 ;
     RECT  2.16 36.585 62.64 36.855 ;
     RECT  2.16 37.125 62.64 37.395 ;
     RECT  2.16 37.665 62.64 37.935 ;
     RECT  2.16 38.205 62.64 38.475 ;
     RECT  2.16 38.745 62.64 39.015 ;
     RECT  2.16 39.285 62.64 39.555 ;
     RECT  2.16 39.825 62.64 40.095 ;
     RECT  2.16 40.365 62.64 40.635 ;
     RECT  2.16 40.905 62.64 41.175 ;
     RECT  2.16 41.445 62.64 41.715 ;
     RECT  2.16 41.985 62.64 42.255 ;
     RECT  2.16 42.525 62.64 42.795 ;
     RECT  2.16 43.065 62.64 43.335 ;
     RECT  2.16 43.605 62.64 43.875 ;
     RECT  2.16 44.145 62.64 44.415 ;
     RECT  2.16 44.685 62.64 44.955 ;
     RECT  2.16 45.225 62.64 45.495 ;
     RECT  2.16 45.765 62.64 46.035 ;
     RECT  2.16 46.305 62.64 46.575 ;
     RECT  2.16 46.845 62.64 47.115 ;
     RECT  2.16 47.385 62.64 47.655 ;
     RECT  2.16 47.925 62.64 48.195 ;
     RECT  2.16 48.465 62.64 48.735 ;
     RECT  2.16 49.005 62.64 49.275 ;
     RECT  2.16 49.545 62.64 49.815 ;
     RECT  2.16 50.085 62.64 50.355 ;
     RECT  2.16 50.625 62.64 50.895 ;
     RECT  2.16 51.165 62.64 51.435 ;
     RECT  2.16 51.705 62.64 51.975 ;
     RECT  2.16 52.245 62.64 52.515 ;
     RECT  2.16 52.785 62.64 53.055 ;
     RECT  2.16 53.325 62.64 53.595 ;
     RECT  2.16 53.865 62.64 54.135 ;
     RECT  2.16 54.405 62.64 54.675 ;
     RECT  2.16 54.945 62.64 55.215 ;
     RECT  2.16 55.485 62.64 55.755 ;
     RECT  2.16 56.025 62.64 56.295 ;
     RECT  2.16 56.565 62.64 56.835 ;
     RECT  2.16 57.105 62.64 57.375 ;
     RECT  2.16 57.645 62.64 57.915 ;
     RECT  2.16 58.185 62.64 58.455 ;
     RECT  2.16 58.725 62.64 58.995 ;
     RECT  2.16 59.265 62.64 59.535 ;
     RECT  2.16 59.805 62.64 60.075 ;
     RECT  2.16 60.345 62.64 60.615 ;
     RECT  2.16 60.885 62.64 61.155 ;
     RECT  2.16 61.425 62.64 61.695 ;
     RECT  2.16 61.965 62.64 62.235 ;
     RECT  2.16 62.505 62.64 62.775 ;
     RECT  2.16 63.045 62.64 63.315 ;
     RECT  2.16 63.585 62.64 63.855 ;
     RECT  2.16 64.125 62.64 64.395 ;
     RECT  2.16 64.665 62.64 64.935 ;
     RECT  2.16 65.205 62.64 65.475 ;
     RECT  2.16 65.745 62.64 66.015 ;
     RECT  2.16 66.285 62.64 66.555 ;
     RECT  2.16 66.825 62.64 67.095 ;
     RECT  2.16 67.365 62.64 67.635 ;
     RECT  2.16 67.905 62.64 68.175 ;
     RECT  2.16 68.445 62.64 68.715 ;
     RECT  2.16 68.985 62.64 69.255 ;
     RECT  2.16 69.525 62.64 69.795 ;
     RECT  2.16 70.065 62.64 70.335 ;
     RECT  2.16 70.605 62.64 70.875 ;
     RECT  2.16 71.145 62.64 71.415 ;
     RECT  2.16 71.685 62.64 71.955 ;
     RECT  2.16 72.225 62.64 72.495 ;
     RECT  2.16 72.765 62.64 73.035 ;
     RECT  2.16 73.305 62.64 73.575 ;
     RECT  2.16 73.845 62.64 74.115 ;
     RECT  2.16 74.385 62.64 74.655 ;
     RECT  2.16 74.925 62.64 75.195 ;
     RECT  2.16 75.465 62.64 75.735 ;
     RECT  2.16 76.005 62.64 76.275 ;
     RECT  2.16 76.545 62.64 76.815 ;
     RECT  2.16 77.085 62.64 77.355 ;
     RECT  2.16 77.625 62.64 77.895 ;
     RECT  2.16 78.165 62.64 78.435 ;
     RECT  2.16 78.705 62.64 78.975 ;
     RECT  2.16 79.245 62.64 79.515 ;
     RECT  2.16 79.785 62.64 80.055 ;
     RECT  2.16 80.325 62.64 80.595 ;
     RECT  2.16 80.865 62.64 81.135 ;
     RECT  2.16 81.405 62.64 81.675 ;
     RECT  2.16 81.945 62.64 82.215 ;
     RECT  2.16 82.485 62.64 82.755 ;
     RECT  2.16 83.025 62.64 83.295 ;
     RECT  2.16 83.565 62.64 83.835 ;
     RECT  2.16 84.105 62.64 84.375 ;
     RECT  2.16 84.645 62.64 84.915 ;
     RECT  2.16 85.185 62.64 85.455 ;
     RECT  2.16 85.725 62.64 85.995 ;
     RECT  2.16 86.265 62.64 86.535 ;
     RECT  2.16 86.805 62.64 87.075 ;
     RECT  2.16 87.345 62.64 87.615 ;
     RECT  2.16 87.885 62.64 88.155 ;
     RECT  2.16 88.425 62.64 88.695 ;
     RECT  2.16 88.965 62.64 89.235 ;
     RECT  2.16 89.505 62.64 89.775 ;
     RECT  2.16 90.045 62.64 90.315 ;
     RECT  2.16 90.585 62.64 90.855 ;
     RECT  2.16 91.125 62.64 91.395 ;
     RECT  2.16 91.665 62.64 91.935 ;
     RECT  2.16 92.205 62.64 92.475 ;
     RECT  2.16 92.745 62.64 93.015 ;
     RECT  2.16 93.285 62.64 93.555 ;
     RECT  2.16 93.825 62.64 94.095 ;
     RECT  2.16 94.365 62.64 94.635 ;
     RECT  2.16 94.905 62.64 95.175 ;
     RECT  2.16 95.445 62.64 95.715 ;
     RECT  2.16 95.985 62.64 96.255 ;
     RECT  2.16 96.525 62.64 96.795 ;
     RECT  2.16 97.065 62.64 97.335 ;
     RECT  2.16 97.605 62.64 97.875 ;
     RECT  2.16 98.145 62.64 98.415 ;
     RECT  2.16 98.685 62.64 98.955 ;
     RECT  2.16 99.225 62.64 99.495 ;
     RECT  2.16 99.765 62.64 100.035 ;
     RECT  2.16 100.305 62.64 100.575 ;
     RECT  2.16 100.845 62.64 101.115 ;
     RECT  2.16 101.385 62.64 101.655 ;
     RECT  2.16 101.925 62.64 102.195 ;
     RECT  2.16 102.465 62.64 102.735 ;
     RECT  2.16 103.005 62.64 103.275 ;
     RECT  2.16 103.545 62.64 103.815 ;
     RECT  2.16 104.085 62.64 104.355 ;
     RECT  2.16 104.625 62.64 104.895 ;
     RECT  2.16 105.165 62.64 105.435 ;
     RECT  2.16 105.705 62.64 105.975 ;
     RECT  2.16 106.245 62.64 106.515 ;
     RECT  2.16 106.785 62.64 107.055 ;
     RECT  2.16 107.325 62.64 107.595 ;
     RECT  2.16 107.865 62.64 108.135 ;
     RECT  2.16 108.405 62.64 108.675 ;
     RECT  2.16 108.945 62.64 109.215 ;
     RECT  2.16 109.485 62.64 109.755 ;
     RECT  2.16 110.025 62.64 110.295 ;
     RECT  2.16 110.565 62.64 110.835 ;
     RECT  2.16 111.105 62.64 111.375 ;
     RECT  2.16 111.645 62.64 111.915 ;
     RECT  2.16 112.185 62.64 112.455 ;
     RECT  2.16 112.725 62.64 112.995 ;
     RECT  2.16 113.265 62.64 113.535 ;
     RECT  2.16 113.805 62.64 114.075 ;
     RECT  2.16 114.345 62.64 114.615 ;
     RECT  2.16 114.885 62.64 115.155 ;
     RECT  2.16 115.425 62.64 115.695 ;
     RECT  2.16 115.965 62.64 116.235 ;
     RECT  2.16 116.505 62.64 116.775 ;
     RECT  2.16 117.045 62.64 117.315 ;
     RECT  2.16 117.585 62.64 117.855 ;
     RECT  2.16 118.125 62.64 118.395 ;
     RECT  2.16 118.665 62.64 118.935 ;
     RECT  2.16 119.205 62.64 119.475 ;
     RECT  2.16 119.745 62.64 120.015 ;
     RECT  2.16 120.285 62.64 120.555 ;
     RECT  2.16 120.825 62.64 121.095 ;
     RECT  2.16 121.365 62.64 121.635 ;
     RECT  2.16 121.905 62.64 122.175 ;
     RECT  2.16 122.445 62.64 122.715 ;
     RECT  2.16 122.985 62.64 123.255 ;
     RECT  2.16 123.525 62.64 123.795 ;
     RECT  2.16 124.065 62.64 124.335 ;
     RECT  2.16 124.605 62.64 124.875 ;
     RECT  2.16 125.145 62.64 125.415 ;
     RECT  2.16 125.685 62.64 125.955 ;
     RECT  2.16 126.225 62.64 126.495 ;
     RECT  2.16 126.765 62.64 127.035 ;
     RECT  2.16 127.305 62.64 127.575 ;
     RECT  2.16 127.845 62.64 128.115 ;
     RECT  2.16 128.385 62.64 128.655 ;
     RECT  2.16 128.925 62.64 129.195 ;
     RECT  2.16 129.465 62.64 129.735 ;
     RECT  2.16 130.005 62.64 130.275 ;
     RECT  2.16 130.545 62.64 130.815 ;
     RECT  2.16 131.085 62.64 131.355 ;
     RECT  2.16 131.625 62.64 131.895 ;
     RECT  2.16 132.165 62.64 132.435 ;
     RECT  2.16 132.705 62.64 132.975 ;
     RECT  2.16 133.245 62.64 133.515 ;
     RECT  2.16 133.785 62.64 134.055 ;
     RECT  2.16 134.325 62.64 134.595 ;
     RECT  2.16 134.865 62.64 135.135 ;
     RECT  2.16 135.405 62.64 135.675 ;
     RECT  2.16 135.945 62.64 136.215 ;
     RECT  2.16 136.485 62.64 136.755 ;
     RECT  2.16 137.025 62.64 137.295 ;
     RECT  2.16 137.565 62.64 137.835 ;
     RECT  2.16 138.105 62.64 138.375 ;
     RECT  2.16 138.645 62.64 138.915 ;
     RECT  2.16 139.185 62.64 139.455 ;
     RECT  2.16 139.725 62.64 139.995 ;
     RECT  2.16 140.265 62.64 140.535 ;
     RECT  2.16 140.805 62.64 141.075 ;
     RECT  2.16 141.345 62.64 141.615 ;
     RECT  2.16 141.885 62.64 142.155 ;
     RECT  2.16 142.425 62.64 142.695 ;
     RECT  2.16 142.965 62.64 143.235 ;
     RECT  2.16 143.505 62.64 143.775 ;
     RECT  2.16 144.045 62.64 144.315 ;
     RECT  2.16 144.585 62.64 144.855 ;
     RECT  2.16 145.125 62.64 145.395 ;
     RECT  2.16 145.665 62.64 145.935 ;
     RECT  2.16 146.205 62.64 146.475 ;
     RECT  2.16 146.745 62.64 147.015 ;
     RECT  2.16 147.285 62.64 147.555 ;
     RECT  2.16 147.825 62.64 148.095 ;
     RECT  2.16 148.365 62.64 148.635 ;
     RECT  2.16 148.905 62.64 149.175 ;
     RECT  2.16 149.445 62.64 149.715 ;
     RECT  2.16 149.985 62.64 150.255 ;
     RECT  2.16 150.525 62.64 150.795 ;
     RECT  2.16 151.065 62.64 151.335 ;
     RECT  2.16 151.605 62.64 151.875 ;
     RECT  2.16 152.145 62.64 152.415 ;
     RECT  2.16 152.685 62.64 152.955 ;
     RECT  2.16 153.225 62.64 153.495 ;
     RECT  2.16 153.765 62.64 154.035 ;
     RECT  2.16 154.305 62.64 154.575 ;
     RECT  2.16 154.845 62.64 155.115 ;
     RECT  2.16 155.385 62.64 155.655 ;
     RECT  2.16 155.925 62.64 156.195 ;
     RECT  2.16 156.465 62.64 156.735 ;
     RECT  2.16 157.005 62.64 157.275 ;
     RECT  2.16 157.545 62.64 157.815 ;
     RECT  2.16 158.085 62.64 158.355 ;
     RECT  2.16 158.625 62.64 158.895 ;
     RECT  2.16 159.165 62.64 159.435 ;
     RECT  2.16 159.705 62.64 159.975 ;
     RECT  2.16 160.245 62.64 160.515 ;
     RECT  2.16 160.785 62.64 161.055 ;
     RECT  2.16 161.325 62.64 161.595 ;
     RECT  2.16 161.865 62.64 162.135 ;
     RECT  2.16 162.405 62.64 162.675 ;
     RECT  2.16 162.945 62.64 163.215 ;
     RECT  2.16 163.485 62.64 163.755 ;
     RECT  2.16 164.025 62.64 164.295 ;
     RECT  2.16 164.565 62.64 164.835 ;
     RECT  2.16 165.105 62.64 165.375 ;
     RECT  2.16 165.645 62.64 165.915 ;
     RECT  2.16 166.185 62.64 166.455 ;
     RECT  2.16 166.725 62.64 166.995 ;
     RECT  2.16 167.265 62.64 167.535 ;
     RECT  2.16 167.805 62.64 168.075 ;
     RECT  2.16 168.345 62.64 168.615 ;
     RECT  2.16 168.885 62.64 169.155 ;
     RECT  2.16 169.425 62.64 169.695 ;
     RECT  2.16 169.965 62.64 170.235 ;
     RECT  2.16 170.505 62.64 170.64 ;
    LAYER RVTP ;
     RECT  2.16 2.295 62.64 2.565 ;
     RECT  2.16 2.835 62.64 3.105 ;
     RECT  2.16 3.375 62.64 3.645 ;
     RECT  2.16 3.915 62.64 4.185 ;
     RECT  2.16 4.455 62.64 4.725 ;
     RECT  2.16 4.995 62.64 5.265 ;
     RECT  2.16 5.535 62.64 5.805 ;
     RECT  2.16 6.075 62.64 6.345 ;
     RECT  2.16 6.615 62.64 6.885 ;
     RECT  2.16 7.155 62.64 7.425 ;
     RECT  2.16 7.695 62.64 7.965 ;
     RECT  2.16 8.235 62.64 8.505 ;
     RECT  2.16 8.775 62.64 9.045 ;
     RECT  2.16 9.315 62.64 9.585 ;
     RECT  2.16 9.855 62.64 10.125 ;
     RECT  2.16 10.395 62.64 10.665 ;
     RECT  2.16 10.935 62.64 11.205 ;
     RECT  2.16 11.475 62.64 11.745 ;
     RECT  2.16 12.015 62.64 12.285 ;
     RECT  2.16 12.555 62.64 12.825 ;
     RECT  2.16 13.095 62.64 13.365 ;
     RECT  2.16 13.635 62.64 13.905 ;
     RECT  2.16 14.175 62.64 14.445 ;
     RECT  2.16 14.715 62.64 14.985 ;
     RECT  2.16 15.255 62.64 15.525 ;
     RECT  2.16 15.795 62.64 16.065 ;
     RECT  2.16 16.335 62.64 16.605 ;
     RECT  2.16 16.875 62.64 17.145 ;
     RECT  2.16 17.415 62.64 17.685 ;
     RECT  2.16 17.955 62.64 18.225 ;
     RECT  2.16 18.495 62.64 18.765 ;
     RECT  2.16 19.035 62.64 19.305 ;
     RECT  2.16 19.575 62.64 19.845 ;
     RECT  2.16 20.115 62.64 20.385 ;
     RECT  2.16 20.655 62.64 20.925 ;
     RECT  2.16 21.195 62.64 21.465 ;
     RECT  2.16 21.735 62.64 22.005 ;
     RECT  2.16 22.275 62.64 22.545 ;
     RECT  2.16 22.815 62.64 23.085 ;
     RECT  2.16 23.355 62.64 23.625 ;
     RECT  2.16 23.895 62.64 24.165 ;
     RECT  2.16 24.435 62.64 24.705 ;
     RECT  2.16 24.975 62.64 25.245 ;
     RECT  2.16 25.515 62.64 25.785 ;
     RECT  2.16 26.055 62.64 26.325 ;
     RECT  2.16 26.595 62.64 26.865 ;
     RECT  2.16 27.135 62.64 27.405 ;
     RECT  2.16 27.675 62.64 27.945 ;
     RECT  2.16 28.215 62.64 28.485 ;
     RECT  2.16 28.755 62.64 29.025 ;
     RECT  2.16 29.295 62.64 29.565 ;
     RECT  2.16 29.835 62.64 30.105 ;
     RECT  2.16 30.375 62.64 30.645 ;
     RECT  2.16 30.915 62.64 31.185 ;
     RECT  2.16 31.455 62.64 31.725 ;
     RECT  2.16 31.995 62.64 32.265 ;
     RECT  2.16 32.535 62.64 32.805 ;
     RECT  2.16 33.075 62.64 33.345 ;
     RECT  2.16 33.615 62.64 33.885 ;
     RECT  2.16 34.155 62.64 34.425 ;
     RECT  2.16 34.695 62.64 34.965 ;
     RECT  2.16 35.235 62.64 35.505 ;
     RECT  2.16 35.775 62.64 36.045 ;
     RECT  2.16 36.315 62.64 36.585 ;
     RECT  2.16 36.855 62.64 37.125 ;
     RECT  2.16 37.395 62.64 37.665 ;
     RECT  2.16 37.935 62.64 38.205 ;
     RECT  2.16 38.475 62.64 38.745 ;
     RECT  2.16 39.015 62.64 39.285 ;
     RECT  2.16 39.555 62.64 39.825 ;
     RECT  2.16 40.095 62.64 40.365 ;
     RECT  2.16 40.635 62.64 40.905 ;
     RECT  2.16 41.175 62.64 41.445 ;
     RECT  2.16 41.715 62.64 41.985 ;
     RECT  2.16 42.255 62.64 42.525 ;
     RECT  2.16 42.795 62.64 43.065 ;
     RECT  2.16 43.335 62.64 43.605 ;
     RECT  2.16 43.875 62.64 44.145 ;
     RECT  2.16 44.415 62.64 44.685 ;
     RECT  2.16 44.955 62.64 45.225 ;
     RECT  2.16 45.495 62.64 45.765 ;
     RECT  2.16 46.035 62.64 46.305 ;
     RECT  2.16 46.575 62.64 46.845 ;
     RECT  2.16 47.115 62.64 47.385 ;
     RECT  2.16 47.655 62.64 47.925 ;
     RECT  2.16 48.195 62.64 48.465 ;
     RECT  2.16 48.735 62.64 49.005 ;
     RECT  2.16 49.275 62.64 49.545 ;
     RECT  2.16 49.815 62.64 50.085 ;
     RECT  2.16 50.355 62.64 50.625 ;
     RECT  2.16 50.895 62.64 51.165 ;
     RECT  2.16 51.435 62.64 51.705 ;
     RECT  2.16 51.975 62.64 52.245 ;
     RECT  2.16 52.515 62.64 52.785 ;
     RECT  2.16 53.055 62.64 53.325 ;
     RECT  2.16 53.595 62.64 53.865 ;
     RECT  2.16 54.135 62.64 54.405 ;
     RECT  2.16 54.675 62.64 54.945 ;
     RECT  2.16 55.215 62.64 55.485 ;
     RECT  2.16 55.755 62.64 56.025 ;
     RECT  2.16 56.295 62.64 56.565 ;
     RECT  2.16 56.835 62.64 57.105 ;
     RECT  2.16 57.375 62.64 57.645 ;
     RECT  2.16 57.915 62.64 58.185 ;
     RECT  2.16 58.455 62.64 58.725 ;
     RECT  2.16 58.995 62.64 59.265 ;
     RECT  2.16 59.535 62.64 59.805 ;
     RECT  2.16 60.075 62.64 60.345 ;
     RECT  2.16 60.615 62.64 60.885 ;
     RECT  2.16 61.155 62.64 61.425 ;
     RECT  2.16 61.695 62.64 61.965 ;
     RECT  2.16 62.235 62.64 62.505 ;
     RECT  2.16 62.775 62.64 63.045 ;
     RECT  2.16 63.315 62.64 63.585 ;
     RECT  2.16 63.855 62.64 64.125 ;
     RECT  2.16 64.395 62.64 64.665 ;
     RECT  2.16 64.935 62.64 65.205 ;
     RECT  2.16 65.475 62.64 65.745 ;
     RECT  2.16 66.015 62.64 66.285 ;
     RECT  2.16 66.555 62.64 66.825 ;
     RECT  2.16 67.095 62.64 67.365 ;
     RECT  2.16 67.635 62.64 67.905 ;
     RECT  2.16 68.175 62.64 68.445 ;
     RECT  2.16 68.715 62.64 68.985 ;
     RECT  2.16 69.255 62.64 69.525 ;
     RECT  2.16 69.795 62.64 70.065 ;
     RECT  2.16 70.335 62.64 70.605 ;
     RECT  2.16 70.875 62.64 71.145 ;
     RECT  2.16 71.415 62.64 71.685 ;
     RECT  2.16 71.955 62.64 72.225 ;
     RECT  2.16 72.495 62.64 72.765 ;
     RECT  2.16 73.035 62.64 73.305 ;
     RECT  2.16 73.575 62.64 73.845 ;
     RECT  2.16 74.115 62.64 74.385 ;
     RECT  2.16 74.655 62.64 74.925 ;
     RECT  2.16 75.195 62.64 75.465 ;
     RECT  2.16 75.735 62.64 76.005 ;
     RECT  2.16 76.275 62.64 76.545 ;
     RECT  2.16 76.815 62.64 77.085 ;
     RECT  2.16 77.355 62.64 77.625 ;
     RECT  2.16 77.895 62.64 78.165 ;
     RECT  2.16 78.435 62.64 78.705 ;
     RECT  2.16 78.975 62.64 79.245 ;
     RECT  2.16 79.515 62.64 79.785 ;
     RECT  2.16 80.055 62.64 80.325 ;
     RECT  2.16 80.595 62.64 80.865 ;
     RECT  2.16 81.135 62.64 81.405 ;
     RECT  2.16 81.675 62.64 81.945 ;
     RECT  2.16 82.215 62.64 82.485 ;
     RECT  2.16 82.755 62.64 83.025 ;
     RECT  2.16 83.295 62.64 83.565 ;
     RECT  2.16 83.835 62.64 84.105 ;
     RECT  2.16 84.375 62.64 84.645 ;
     RECT  2.16 84.915 62.64 85.185 ;
     RECT  2.16 85.455 62.64 85.725 ;
     RECT  2.16 85.995 62.64 86.265 ;
     RECT  2.16 86.535 62.64 86.805 ;
     RECT  2.16 87.075 62.64 87.345 ;
     RECT  2.16 87.615 62.64 87.885 ;
     RECT  2.16 88.155 62.64 88.425 ;
     RECT  2.16 88.695 62.64 88.965 ;
     RECT  2.16 89.235 62.64 89.505 ;
     RECT  2.16 89.775 62.64 90.045 ;
     RECT  2.16 90.315 62.64 90.585 ;
     RECT  2.16 90.855 62.64 91.125 ;
     RECT  2.16 91.395 62.64 91.665 ;
     RECT  2.16 91.935 62.64 92.205 ;
     RECT  2.16 92.475 62.64 92.745 ;
     RECT  2.16 93.015 62.64 93.285 ;
     RECT  2.16 93.555 62.64 93.825 ;
     RECT  2.16 94.095 62.64 94.365 ;
     RECT  2.16 94.635 62.64 94.905 ;
     RECT  2.16 95.175 62.64 95.445 ;
     RECT  2.16 95.715 62.64 95.985 ;
     RECT  2.16 96.255 62.64 96.525 ;
     RECT  2.16 96.795 62.64 97.065 ;
     RECT  2.16 97.335 62.64 97.605 ;
     RECT  2.16 97.875 62.64 98.145 ;
     RECT  2.16 98.415 62.64 98.685 ;
     RECT  2.16 98.955 62.64 99.225 ;
     RECT  2.16 99.495 62.64 99.765 ;
     RECT  2.16 100.035 62.64 100.305 ;
     RECT  2.16 100.575 62.64 100.845 ;
     RECT  2.16 101.115 62.64 101.385 ;
     RECT  2.16 101.655 62.64 101.925 ;
     RECT  2.16 102.195 62.64 102.465 ;
     RECT  2.16 102.735 62.64 103.005 ;
     RECT  2.16 103.275 62.64 103.545 ;
     RECT  2.16 103.815 62.64 104.085 ;
     RECT  2.16 104.355 62.64 104.625 ;
     RECT  2.16 104.895 62.64 105.165 ;
     RECT  2.16 105.435 62.64 105.705 ;
     RECT  2.16 105.975 62.64 106.245 ;
     RECT  2.16 106.515 62.64 106.785 ;
     RECT  2.16 107.055 62.64 107.325 ;
     RECT  2.16 107.595 62.64 107.865 ;
     RECT  2.16 108.135 62.64 108.405 ;
     RECT  2.16 108.675 62.64 108.945 ;
     RECT  2.16 109.215 62.64 109.485 ;
     RECT  2.16 109.755 62.64 110.025 ;
     RECT  2.16 110.295 62.64 110.565 ;
     RECT  2.16 110.835 62.64 111.105 ;
     RECT  2.16 111.375 62.64 111.645 ;
     RECT  2.16 111.915 62.64 112.185 ;
     RECT  2.16 112.455 62.64 112.725 ;
     RECT  2.16 112.995 62.64 113.265 ;
     RECT  2.16 113.535 62.64 113.805 ;
     RECT  2.16 114.075 62.64 114.345 ;
     RECT  2.16 114.615 62.64 114.885 ;
     RECT  2.16 115.155 62.64 115.425 ;
     RECT  2.16 115.695 62.64 115.965 ;
     RECT  2.16 116.235 62.64 116.505 ;
     RECT  2.16 116.775 62.64 117.045 ;
     RECT  2.16 117.315 62.64 117.585 ;
     RECT  2.16 117.855 62.64 118.125 ;
     RECT  2.16 118.395 62.64 118.665 ;
     RECT  2.16 118.935 62.64 119.205 ;
     RECT  2.16 119.475 62.64 119.745 ;
     RECT  2.16 120.015 62.64 120.285 ;
     RECT  2.16 120.555 62.64 120.825 ;
     RECT  2.16 121.095 62.64 121.365 ;
     RECT  2.16 121.635 62.64 121.905 ;
     RECT  2.16 122.175 62.64 122.445 ;
     RECT  2.16 122.715 62.64 122.985 ;
     RECT  2.16 123.255 62.64 123.525 ;
     RECT  2.16 123.795 62.64 124.065 ;
     RECT  2.16 124.335 62.64 124.605 ;
     RECT  2.16 124.875 62.64 125.145 ;
     RECT  2.16 125.415 62.64 125.685 ;
     RECT  2.16 125.955 62.64 126.225 ;
     RECT  2.16 126.495 62.64 126.765 ;
     RECT  2.16 127.035 62.64 127.305 ;
     RECT  2.16 127.575 62.64 127.845 ;
     RECT  2.16 128.115 62.64 128.385 ;
     RECT  2.16 128.655 62.64 128.925 ;
     RECT  2.16 129.195 62.64 129.465 ;
     RECT  2.16 129.735 62.64 130.005 ;
     RECT  2.16 130.275 62.64 130.545 ;
     RECT  2.16 130.815 62.64 131.085 ;
     RECT  2.16 131.355 62.64 131.625 ;
     RECT  2.16 131.895 62.64 132.165 ;
     RECT  2.16 132.435 62.64 132.705 ;
     RECT  2.16 132.975 62.64 133.245 ;
     RECT  2.16 133.515 62.64 133.785 ;
     RECT  2.16 134.055 62.64 134.325 ;
     RECT  2.16 134.595 62.64 134.865 ;
     RECT  2.16 135.135 62.64 135.405 ;
     RECT  2.16 135.675 62.64 135.945 ;
     RECT  2.16 136.215 62.64 136.485 ;
     RECT  2.16 136.755 62.64 137.025 ;
     RECT  2.16 137.295 62.64 137.565 ;
     RECT  2.16 137.835 62.64 138.105 ;
     RECT  2.16 138.375 62.64 138.645 ;
     RECT  2.16 138.915 62.64 139.185 ;
     RECT  2.16 139.455 62.64 139.725 ;
     RECT  2.16 139.995 62.64 140.265 ;
     RECT  2.16 140.535 62.64 140.805 ;
     RECT  2.16 141.075 62.64 141.345 ;
     RECT  2.16 141.615 62.64 141.885 ;
     RECT  2.16 142.155 62.64 142.425 ;
     RECT  2.16 142.695 62.64 142.965 ;
     RECT  2.16 143.235 62.64 143.505 ;
     RECT  2.16 143.775 62.64 144.045 ;
     RECT  2.16 144.315 62.64 144.585 ;
     RECT  2.16 144.855 62.64 145.125 ;
     RECT  2.16 145.395 62.64 145.665 ;
     RECT  2.16 145.935 62.64 146.205 ;
     RECT  2.16 146.475 62.64 146.745 ;
     RECT  2.16 147.015 62.64 147.285 ;
     RECT  2.16 147.555 62.64 147.825 ;
     RECT  2.16 148.095 62.64 148.365 ;
     RECT  2.16 148.635 62.64 148.905 ;
     RECT  2.16 149.175 62.64 149.445 ;
     RECT  2.16 149.715 62.64 149.985 ;
     RECT  2.16 150.255 62.64 150.525 ;
     RECT  2.16 150.795 62.64 151.065 ;
     RECT  2.16 151.335 62.64 151.605 ;
     RECT  2.16 151.875 62.64 152.145 ;
     RECT  2.16 152.415 62.64 152.685 ;
     RECT  2.16 152.955 62.64 153.225 ;
     RECT  2.16 153.495 62.64 153.765 ;
     RECT  2.16 154.035 62.64 154.305 ;
     RECT  2.16 154.575 62.64 154.845 ;
     RECT  2.16 155.115 62.64 155.385 ;
     RECT  2.16 155.655 62.64 155.925 ;
     RECT  2.16 156.195 62.64 156.465 ;
     RECT  2.16 156.735 62.64 157.005 ;
     RECT  2.16 157.275 62.64 157.545 ;
     RECT  2.16 157.815 62.64 158.085 ;
     RECT  2.16 158.355 62.64 158.625 ;
     RECT  2.16 158.895 62.64 159.165 ;
     RECT  2.16 159.435 62.64 159.705 ;
     RECT  2.16 159.975 62.64 160.245 ;
     RECT  2.16 160.515 62.64 160.785 ;
     RECT  2.16 161.055 62.64 161.325 ;
     RECT  2.16 161.595 62.64 161.865 ;
     RECT  2.16 162.135 62.64 162.405 ;
     RECT  2.16 162.675 62.64 162.945 ;
     RECT  2.16 163.215 62.64 163.485 ;
     RECT  2.16 163.755 62.64 164.025 ;
     RECT  2.16 164.295 62.64 164.565 ;
     RECT  2.16 164.835 62.64 165.105 ;
     RECT  2.16 165.375 62.64 165.645 ;
     RECT  2.16 165.915 62.64 166.185 ;
     RECT  2.16 166.455 62.64 166.725 ;
     RECT  2.16 166.995 62.64 167.265 ;
     RECT  2.16 167.535 62.64 167.805 ;
     RECT  2.16 168.075 62.64 168.345 ;
     RECT  2.16 168.615 62.64 168.885 ;
     RECT  2.16 169.155 62.64 169.425 ;
     RECT  2.16 169.695 62.64 169.965 ;
     RECT  2.16 170.235 62.64 170.505 ;
    LAYER M1 ;
     RECT  2.16 2.151 62.64 170.649 ;
    LAYER M2 ;
     RECT  0.067 11.952 2.16 11.97 ;
     RECT  0.067 22.212 2.16 22.77 ;
     RECT  0.067 27.882 2.16 27.9 ;
     RECT  0.535 33.012 2.16 33.03 ;
     RECT  0.067 43.848 2.16 43.866 ;
     RECT  0.067 49.482 2.16 49.5 ;
     RECT  0.535 73.512 2.16 73.53 ;
     RECT  0.067 78.642 2.16 78.66 ;
     RECT  0.067 83.772 2.16 83.79 ;
     RECT  0.067 94.572 2.16 94.59 ;
     RECT  0.535 105.408 2.16 105.426 ;
     RECT  0.535 140.202 2.16 140.22 ;
     RECT  0.067 145.332 2.16 145.35 ;
     RECT  2.16 2.151 26.959 170.649 ;
     RECT  26.959 2.106 27.347 170.649 ;
     RECT  27.347 2.151 62.64 170.649 ;
     RECT  62.64 25.02 63.275 25.038 ;
     RECT  62.64 40.986 63.311 41.004 ;
     RECT  62.64 17.658 63.851 17.676 ;
     RECT  62.64 33.048 63.851 33.066 ;
    LAYER M3 ;
     RECT  4.248 0.091 4.266 0.571 ;
     RECT  4.068 0.571 4.266 1.099 ;
     RECT  5.112 1.051 5.13 1.099 ;
     RECT  4.068 1.099 5.13 1.723 ;
     RECT  6.12 0.091 6.138 1.723 ;
     RECT  9.072 1.099 9.09 1.723 ;
     RECT  11.88 0.091 11.898 1.723 ;
     RECT  13.608 1.099 13.626 1.723 ;
     RECT  19.332 1.675 19.35 1.723 ;
     RECT  22.752 0.091 23.238 1.723 ;
     RECT  26.136 1.099 26.154 1.723 ;
     RECT  49.536 1.099 49.554 1.723 ;
     RECT  50.616 0.091 50.634 1.723 ;
     RECT  56.952 0.523 56.97 1.723 ;
     RECT  59.148 0.523 59.166 1.723 ;
     RECT  4.068 1.723 7.398 1.771 ;
     RECT  8.208 1.723 10.422 1.771 ;
     RECT  11.196 1.723 13.626 1.771 ;
     RECT  27.504 1.723 34.506 1.771 ;
     RECT  35.244 1.723 39.582 1.771 ;
     RECT  40.68 1.723 41.418 1.771 ;
     RECT  42.804 1.723 60.426 1.771 ;
     RECT  27.504 1.771 39.834 2.011 ;
     RECT  40.68 1.771 60.426 2.011 ;
     RECT  20.988 1.723 26.73 2.101 ;
     RECT  27.504 2.011 60.426 2.101 ;
     RECT  14.508 1.723 20.25 2.191 ;
     RECT  20.988 2.101 60.426 2.191 ;
     RECT  4.068 1.771 13.626 2.251 ;
     RECT  14.364 2.191 60.426 2.251 ;
     RECT  4.068 2.251 60.426 2.371 ;
     RECT  61.815 2.143 61.905 2.371 ;
     RECT  2.415 2.143 2.505 2.413 ;
     RECT  4.068 2.371 61.905 2.413 ;
     RECT  4.068 2.413 62.097 2.489 ;
     RECT  4.248 2.489 62.097 3.685 ;
     RECT  4.14 3.685 62.097 3.725 ;
     RECT  4.356 3.725 62.097 4.919 ;
     RECT  4.932 4.919 62.097 5.027 ;
     RECT  4.968 5.027 62.097 5.063 ;
     RECT  4.032 5.029 4.05 5.069 ;
     RECT  5.076 5.063 62.097 5.225 ;
     RECT  27.18 5.225 62.097 5.333 ;
     RECT  27.216 5.333 62.097 6.221 ;
     RECT  3.924 7.321 3.942 7.373 ;
     RECT  5.076 5.225 26.334 7.387 ;
     RECT  2.415 2.413 2.697 8.155 ;
     RECT  4.212 7.387 26.334 8.159 ;
     RECT  2.415 8.155 3.294 8.167 ;
     RECT  2.304 8.167 3.294 8.311 ;
     RECT  2.304 8.311 3.474 9.121 ;
     RECT  4.356 8.159 26.334 9.121 ;
     RECT  2.304 9.121 26.334 9.653 ;
     RECT  2.304 9.653 3.474 9.677 ;
     RECT  2.415 9.677 3.474 10.555 ;
     RECT  2.304 10.555 3.474 10.741 ;
     RECT  4.248 9.653 26.334 10.741 ;
     RECT  2.304 10.741 26.334 11.435 ;
     RECT  2.304 11.435 3.438 11.705 ;
     RECT  0.072 11.947 0.09 12.029 ;
     RECT  2.415 11.705 3.438 12.427 ;
     RECT  2.304 12.427 3.438 12.515 ;
     RECT  3.492 12.631 3.51 12.715 ;
     RECT  4.392 11.435 26.334 12.715 ;
     RECT  3.492 12.715 26.334 12.749 ;
     RECT  2.304 12.515 2.697 13.981 ;
     RECT  3.636 12.749 26.334 13.981 ;
     RECT  2.304 13.981 26.334 14.135 ;
     RECT  3.816 14.135 26.334 14.243 ;
     RECT  2.304 14.135 2.697 15.323 ;
     RECT  4.032 14.243 26.334 15.331 ;
     RECT  3.924 15.331 26.334 15.485 ;
     RECT  2.415 15.323 2.697 15.727 ;
     RECT  2.415 15.727 2.826 15.773 ;
     RECT  3.96 15.485 26.334 15.917 ;
     RECT  2.415 15.773 2.697 16.219 ;
     RECT  3.96 15.917 4.302 16.645 ;
     RECT  2.304 16.219 2.697 16.651 ;
     RECT  3.96 16.645 4.374 16.681 ;
     RECT  5.148 15.917 26.334 16.681 ;
     RECT  2.304 16.651 2.79 16.835 ;
     RECT  3.816 16.681 26.334 16.835 ;
     RECT  4.032 16.835 26.334 17.105 ;
     RECT  43.092 6.221 62.097 17.455 ;
     RECT  2.304 16.835 2.697 17.608 ;
     RECT  43.092 17.455 62.442 17.609 ;
     RECT  63.828 16.987 63.846 17.681 ;
     RECT  2.304 17.608 2.79 18.121 ;
     RECT  2.304 18.121 3.078 18.185 ;
     RECT  4.14 17.105 26.334 18.185 ;
     RECT  2.415 18.185 3.078 18.419 ;
     RECT  3.42 18.571 3.762 18.995 ;
     RECT  4.644 18.185 26.334 19.345 ;
     RECT  2.415 18.419 2.697 19.483 ;
     RECT  4.428 19.345 26.334 19.499 ;
     RECT  43.092 17.609 62.097 19.499 ;
     RECT  2.304 19.483 2.697 19.615 ;
     RECT  3.42 18.995 3.51 19.615 ;
     RECT  43.344 19.499 62.097 19.769 ;
     RECT  2.304 19.615 3.51 20.281 ;
     RECT  4.464 19.499 26.334 20.281 ;
     RECT  2.304 20.281 26.334 20.381 ;
     RECT  43.38 19.769 62.097 21.115 ;
     RECT  43.056 21.115 62.097 21.155 ;
     RECT  4.356 20.381 26.334 21.271 ;
     RECT  4.14 21.271 26.334 21.425 ;
     RECT  4.716 21.425 26.334 21.461 ;
     RECT  2.304 20.381 3.186 21.541 ;
     RECT  2.304 21.541 3.222 21.643 ;
     RECT  43.128 21.155 62.097 21.659 ;
     RECT  2.304 21.643 3.942 21.695 ;
     RECT  2.304 21.695 2.697 21.965 ;
     RECT  3.42 21.695 3.942 22.351 ;
     RECT  5.112 21.461 26.334 22.351 ;
     RECT  3.42 22.351 26.334 22.505 ;
     RECT  0.072 22.207 0.09 22.829 ;
     RECT  3.996 22.505 5.166 23.251 ;
     RECT  5.94 22.505 26.334 23.251 ;
     RECT  2.415 21.965 2.697 23.275 ;
     RECT  3.996 23.251 26.334 23.431 ;
     RECT  2.304 23.275 2.697 23.855 ;
     RECT  3.924 23.431 26.334 24.359 ;
     RECT  3.924 24.359 5.166 24.395 ;
     RECT  2.34 23.855 2.697 24.667 ;
     RECT  63.252 25.003 63.27 25.043 ;
     RECT  43.236 21.659 62.097 25.051 ;
     RECT  2.304 24.667 2.697 25.205 ;
     RECT  4.14 24.395 5.166 25.321 ;
     RECT  43.236 25.051 62.154 25.321 ;
     RECT  3.816 25.321 5.166 25.475 ;
     RECT  43.236 25.321 62.334 25.475 ;
     RECT  4.068 25.475 4.302 25.511 ;
     RECT  5.148 25.475 5.166 25.825 ;
     RECT  5.94 24.359 26.334 25.825 ;
     RECT  2.415 25.205 2.697 26.059 ;
     RECT  4.284 25.511 4.302 26.203 ;
     RECT  5.148 25.825 26.334 26.203 ;
     RECT  4.284 26.203 26.334 26.237 ;
     RECT  4.284 26.237 5.166 26.249 ;
     RECT  2.304 26.059 2.697 26.285 ;
     RECT  4.896 26.249 5.166 26.519 ;
     RECT  2.415 26.285 2.697 26.527 ;
     RECT  2.415 26.527 2.826 26.573 ;
     RECT  2.415 26.573 2.697 27.019 ;
     RECT  5.94 26.237 26.334 27.059 ;
     RECT  3.708 26.401 4.158 27.337 ;
     RECT  5.148 26.519 5.166 27.355 ;
     RECT  5.94 27.059 10.026 27.355 ;
     RECT  2.304 27.019 2.697 27.635 ;
     RECT  3.636 27.337 4.158 27.751 ;
     RECT  3.636 27.751 4.374 27.841 ;
     RECT  5.148 27.355 10.026 27.841 ;
     RECT  3.636 27.841 10.026 27.869 ;
     RECT  3.636 27.869 5.166 27.905 ;
     RECT  0.072 27.877 0.09 27.965 ;
     RECT  5.94 27.869 10.026 28.111 ;
     RECT  11.124 27.059 26.334 28.111 ;
     RECT  4.284 27.905 5.166 28.175 ;
     RECT  5.94 28.111 10.062 28.525 ;
     RECT  10.8 28.111 26.334 28.525 ;
     RECT  4.5 28.175 5.166 28.715 ;
     RECT  2.415 27.635 2.697 28.891 ;
     RECT  2.304 28.891 2.697 28.939 ;
     RECT  2.304 28.939 3.294 28.985 ;
     RECT  5.94 28.525 26.334 29.021 ;
     RECT  2.34 28.985 3.294 29.029 ;
     RECT  2.34 29.029 3.438 29.219 ;
     RECT  2.34 29.219 3.15 29.255 ;
     RECT  5.148 28.715 5.166 29.467 ;
     RECT  2.34 29.255 2.826 29.525 ;
     RECT  4.5 29.467 5.166 29.605 ;
     RECT  4.176 29.605 5.166 29.659 ;
     RECT  5.94 29.021 9.918 29.659 ;
     RECT  4.176 29.659 9.918 29.795 ;
     RECT  2.415 29.525 2.826 29.885 ;
     RECT  4.356 29.795 9.918 29.911 ;
     RECT  10.764 29.021 26.334 29.911 ;
     RECT  4.356 29.911 26.334 30.029 ;
     RECT  10.764 30.029 26.334 30.065 ;
     RECT  2.415 29.885 2.697 30.283 ;
     RECT  2.304 30.283 2.697 30.335 ;
     RECT  0.072 30.763 0.09 30.893 ;
     RECT  4.356 30.029 5.166 30.991 ;
     RECT  10.836 30.065 26.334 31.109 ;
     RECT  3.996 30.991 5.166 31.145 ;
     RECT  2.415 30.335 2.697 31.243 ;
     RECT  4.356 31.145 5.166 31.339 ;
     RECT  5.94 30.029 9.918 31.339 ;
     RECT  4.356 31.339 9.918 31.373 ;
     RECT  2.304 31.243 2.697 31.793 ;
     RECT  4.5 31.373 9.918 32.341 ;
     RECT  3.96 32.341 9.918 32.477 ;
     RECT  2.415 31.793 2.697 32.635 ;
     RECT  2.304 32.635 2.697 32.765 ;
     RECT  3.996 32.477 9.918 32.999 ;
     RECT  3.996 32.999 4.05 33.035 ;
     RECT  63.828 32.971 63.846 33.071 ;
     RECT  0.54 33.007 0.558 33.149 ;
     RECT  3.996 33.035 4.014 33.305 ;
     RECT  11.124 31.109 26.334 33.511 ;
     RECT  2.415 32.765 2.697 33.547 ;
     RECT  10.836 33.511 26.334 33.611 ;
     RECT  3.564 33.691 3.582 33.845 ;
     RECT  2.415 33.547 2.826 34.051 ;
     RECT  2.415 34.051 3.402 34.075 ;
     RECT  5.148 32.999 9.918 34.219 ;
     RECT  2.304 34.075 3.402 34.253 ;
     RECT  4.824 34.219 9.918 34.385 ;
     RECT  11.124 33.611 26.334 34.429 ;
     RECT  10.836 34.429 26.334 34.529 ;
     RECT  2.304 34.253 2.697 34.655 ;
     RECT  3.456 34.735 3.474 34.799 ;
     RECT  5.148 34.385 9.918 34.799 ;
     RECT  4.356 34.771 4.374 35.041 ;
     RECT  3.816 35.041 4.374 35.195 ;
     RECT  2.415 34.655 2.697 35.437 ;
     RECT  2.415 35.437 2.754 35.947 ;
     RECT  2.304 35.947 2.754 36.005 ;
     RECT  2.415 36.005 2.754 36.121 ;
     RECT  4.356 35.195 4.374 36.211 ;
     RECT  5.22 34.799 9.918 36.211 ;
     RECT  2.415 36.121 2.898 36.239 ;
     RECT  4.356 36.211 9.918 36.481 ;
     RECT  11.124 34.529 26.334 36.751 ;
     RECT  2.415 36.239 2.697 36.859 ;
     RECT  2.304 36.859 2.697 36.923 ;
     RECT  3.996 36.481 9.918 36.931 ;
     RECT  3.924 36.931 9.918 37.085 ;
     RECT  2.415 36.923 2.697 37.327 ;
     RECT  2.415 37.327 2.826 37.373 ;
     RECT  10.836 36.751 26.334 37.391 ;
     RECT  4.284 37.085 9.918 37.613 ;
     RECT  2.415 37.373 2.697 37.819 ;
     RECT  3.636 38.011 3.978 38.129 ;
     RECT  11.124 37.391 26.334 38.281 ;
     RECT  2.304 37.819 2.697 38.435 ;
     RECT  10.836 38.281 26.334 38.435 ;
     RECT  3.816 38.129 3.978 38.515 ;
     RECT  5.04 37.613 9.918 38.515 ;
     RECT  3.816 38.515 9.918 38.939 ;
     RECT  3.816 38.939 3.978 38.975 ;
     RECT  2.415 38.435 2.697 39.208 ;
     RECT  3.96 38.975 3.978 39.515 ;
     RECT  2.412 39.208 2.697 39.691 ;
     RECT  4.716 38.939 9.918 39.865 ;
     RECT  4.536 39.865 9.918 40.405 ;
     RECT  4.356 40.405 9.918 40.441 ;
     RECT  43.236 25.475 62.097 40.711 ;
     RECT  3.924 40.441 9.918 40.829 ;
     RECT  3.924 40.829 3.942 40.865 ;
     RECT  4.68 40.829 9.918 40.865 ;
     RECT  43.236 40.711 62.298 40.865 ;
     RECT  63.288 40.981 63.306 41.021 ;
     RECT  11.124 38.435 26.334 41.071 ;
     RECT  10.836 41.071 26.334 41.171 ;
     RECT  5.148 40.865 9.918 42.061 ;
     RECT  4.428 42.061 9.918 42.151 ;
     RECT  3.852 42.151 9.918 42.221 ;
     RECT  3.852 42.221 4.014 42.251 ;
     RECT  2.304 39.691 2.697 42.755 ;
     RECT  3.996 42.251 4.014 43.025 ;
     RECT  3.672 43.141 3.69 43.295 ;
     RECT  2.412 42.755 2.697 43.565 ;
     RECT  5.148 42.221 9.918 43.765 ;
     RECT  4.644 43.765 9.918 43.771 ;
     RECT  0.072 43.843 0.09 43.949 ;
     RECT  4.284 43.771 9.918 44.069 ;
     RECT  4.284 44.069 4.302 44.105 ;
     RECT  2.415 43.565 2.697 44.347 ;
     RECT  2.412 44.347 2.697 44.429 ;
     RECT  3.96 44.419 3.978 44.645 ;
     RECT  5.148 44.069 9.918 44.851 ;
     RECT  4.788 44.851 9.918 44.879 ;
     RECT  4.788 44.879 5.166 45.023 ;
     RECT  2.415 44.429 2.697 45.355 ;
     RECT  2.304 45.355 2.697 45.455 ;
     RECT  5.148 45.023 5.166 45.841 ;
     RECT  3.708 45.193 3.726 46.111 ;
     RECT  4.464 45.841 5.166 46.111 ;
     RECT  2.415 45.455 2.697 46.237 ;
     RECT  3.708 46.111 5.166 46.409 ;
     RECT  3.708 46.409 3.726 47.191 ;
     RECT  4.536 46.409 5.166 47.191 ;
     RECT  11.124 41.171 26.334 47.191 ;
     RECT  2.412 46.237 2.697 47.227 ;
     RECT  10.836 47.191 26.334 47.309 ;
     RECT  2.304 47.227 2.697 47.345 ;
     RECT  3.708 47.191 5.166 47.345 ;
     RECT  5.148 47.345 5.166 47.899 ;
     RECT  5.94 44.879 9.918 47.899 ;
     RECT  3.708 47.345 4.374 47.933 ;
     RECT  2.415 47.345 2.697 48.127 ;
     RECT  2.412 48.127 2.697 48.619 ;
     RECT  5.148 47.899 9.918 49.037 ;
     RECT  2.304 48.619 2.697 49.235 ;
     RECT  3.708 47.933 3.726 49.477 ;
     RECT  3.6 49.477 3.726 49.517 ;
     RECT  0.072 49.477 0.09 49.613 ;
     RECT  5.148 49.037 5.166 49.963 ;
     RECT  2.415 49.235 2.697 50.011 ;
     RECT  5.148 49.963 5.202 50.125 ;
     RECT  5.94 49.037 9.918 50.155 ;
     RECT  5.94 50.155 10.026 50.251 ;
     RECT  4.536 50.125 5.202 50.279 ;
     RECT  11.124 47.309 26.334 50.459 ;
     RECT  5.148 50.279 5.202 50.539 ;
     RECT  5.94 50.251 10.35 50.539 ;
     RECT  2.304 50.011 2.697 50.585 ;
     RECT  5.148 50.539 10.35 50.731 ;
     RECT  11.124 50.459 21.474 50.731 ;
     RECT  5.148 50.731 21.474 51.359 ;
     RECT  10.872 51.359 21.474 51.439 ;
     RECT  22.212 50.459 26.334 51.439 ;
     RECT  2.415 50.585 2.697 51.451 ;
     RECT  5.148 51.359 9.918 51.475 ;
     RECT  2.304 51.451 2.697 51.503 ;
     RECT  4.572 51.475 9.918 51.629 ;
     RECT  10.872 51.439 26.334 51.665 ;
     RECT  10.872 51.665 21.474 51.869 ;
     RECT  3.708 49.517 3.726 52.321 ;
     RECT  4.572 51.629 5.166 52.321 ;
     RECT  2.412 51.503 2.697 52.363 ;
     RECT  3.708 52.321 5.166 52.439 ;
     RECT  4.752 52.439 5.166 52.448 ;
     RECT  2.304 52.363 2.697 53.393 ;
     RECT  3.708 52.439 3.726 53.401 ;
     RECT  11.124 51.869 21.474 53.515 ;
     RECT  22.212 51.665 26.334 53.515 ;
     RECT  3.708 53.401 3.762 53.519 ;
     RECT  3.708 53.519 3.726 53.527 ;
     RECT  5.148 52.448 5.166 53.563 ;
     RECT  5.94 51.629 9.918 53.563 ;
     RECT  3.6 53.527 3.726 53.597 ;
     RECT  5.148 53.563 9.918 54.091 ;
     RECT  4.752 54.091 9.918 54.301 ;
     RECT  4.572 54.301 9.918 54.329 ;
     RECT  2.415 53.393 2.697 54.715 ;
     RECT  3.708 53.597 3.726 54.751 ;
     RECT  3.42 54.751 3.726 54.869 ;
     RECT  2.304 54.715 2.697 54.905 ;
     RECT  4.572 54.329 5.166 55.255 ;
     RECT  4.536 55.255 5.166 55.859 ;
     RECT  2.415 54.905 2.697 56.155 ;
     RECT  11.124 53.515 26.334 56.533 ;
     RECT  2.304 56.155 2.697 56.633 ;
     RECT  10.8 56.533 26.334 56.633 ;
     RECT  5.148 55.859 5.166 56.641 ;
     RECT  5.94 54.329 9.918 56.641 ;
     RECT  11.124 56.633 26.334 57.019 ;
     RECT  27.216 6.221 42.318 57.019 ;
     RECT  2.415 56.633 2.697 57.037 ;
     RECT  2.415 57.037 2.826 57.101 ;
     RECT  3.708 54.869 3.726 57.145 ;
     RECT  3.708 57.145 4.374 57.181 ;
     RECT  5.148 56.641 9.918 57.181 ;
     RECT  3.672 57.181 9.918 57.335 ;
     RECT  11.124 57.019 42.318 57.569 ;
     RECT  3.708 57.335 9.918 57.581 ;
     RECT  4.536 57.581 9.918 57.773 ;
     RECT  3.708 57.581 3.726 58.795 ;
     RECT  3.564 58.795 3.726 58.835 ;
     RECT  3.708 58.835 3.726 58.891 ;
     RECT  5.148 57.773 9.918 58.955 ;
     RECT  3.708 58.891 4.374 59.071 ;
     RECT  5.148 58.955 5.166 59.071 ;
     RECT  2.415 57.101 2.697 59.419 ;
     RECT  2.304 59.419 2.697 60.035 ;
     RECT  11.124 57.569 26.334 60.043 ;
     RECT  27.216 57.569 42.318 60.043 ;
     RECT  11.124 60.043 42.318 60.143 ;
     RECT  3.708 59.071 5.166 60.151 ;
     RECT  3.492 60.151 5.166 60.235 ;
     RECT  2.415 60.035 2.697 60.376 ;
     RECT  3.492 60.235 5.202 60.376 ;
     RECT  2.415 60.376 5.202 60.413 ;
     RECT  3.42 60.413 5.202 60.421 ;
     RECT  5.94 58.955 9.918 60.421 ;
     RECT  3.42 60.421 9.918 60.461 ;
     RECT  3.708 60.461 9.918 60.575 ;
     RECT  2.415 60.413 2.697 60.817 ;
     RECT  11.124 60.143 26.406 61.123 ;
     RECT  27.216 60.143 42.318 61.123 ;
     RECT  3.708 60.575 4.374 61.321 ;
     RECT  5.148 60.575 5.166 61.321 ;
     RECT  5.94 60.575 9.918 61.321 ;
     RECT  2.304 60.817 2.697 61.385 ;
     RECT  11.124 61.123 42.318 61.529 ;
     RECT  2.415 61.385 2.697 62.251 ;
     RECT  2.304 62.251 2.697 62.303 ;
     RECT  2.415 62.303 2.697 63.163 ;
     RECT  3.708 61.321 9.918 63.239 ;
     RECT  3.708 63.239 5.166 63.509 ;
     RECT  3.708 63.509 4.266 63.545 ;
     RECT  2.304 63.163 2.697 64.021 ;
     RECT  5.148 63.509 5.166 64.027 ;
     RECT  5.94 63.239 9.918 64.027 ;
     RECT  5.148 64.027 9.918 64.355 ;
     RECT  2.304 64.021 2.826 64.411 ;
     RECT  3.708 63.545 3.726 64.411 ;
     RECT  2.304 64.411 3.726 64.895 ;
     RECT  2.304 64.895 2.754 65.165 ;
     RECT  5.148 64.355 5.166 65.281 ;
     RECT  5.94 64.355 9.918 65.281 ;
     RECT  3.708 64.895 3.726 65.371 ;
     RECT  4.788 65.281 9.918 65.705 ;
     RECT  2.415 65.165 2.754 65.983 ;
     RECT  2.415 65.983 2.826 66.029 ;
     RECT  3.708 65.371 3.978 66.091 ;
     RECT  4.788 65.705 5.202 66.091 ;
     RECT  2.415 66.029 2.697 66.475 ;
     RECT  3.708 66.091 5.202 66.479 ;
     RECT  3.708 66.479 5.166 66.623 ;
     RECT  4.536 66.623 5.166 66.893 ;
     RECT  2.304 66.475 2.697 67.595 ;
     RECT  3.708 66.623 3.726 67.711 ;
     RECT  4.716 66.893 5.166 67.711 ;
     RECT  3.708 67.711 5.166 67.771 ;
     RECT  5.94 65.705 9.918 67.771 ;
     RECT  3.708 67.771 9.918 67.829 ;
     RECT  3.708 67.829 4.194 67.865 ;
     RECT  2.415 67.595 2.697 68.347 ;
     RECT  3.708 67.865 3.726 68.347 ;
     RECT  2.304 68.347 3.726 68.675 ;
     RECT  3.708 68.675 3.726 68.953 ;
     RECT  3.708 68.953 3.978 69.331 ;
     RECT  5.148 67.829 9.918 69.331 ;
     RECT  2.304 68.675 2.697 69.341 ;
     RECT  3.708 69.331 9.918 69.485 ;
     RECT  5.148 69.485 9.918 69.581 ;
     RECT  2.415 69.341 2.697 69.727 ;
     RECT  2.415 69.727 2.826 69.773 ;
     RECT  22.212 61.529 42.318 69.899 ;
     RECT  2.415 69.773 2.697 70.219 ;
     RECT  3.708 69.485 3.978 70.267 ;
     RECT  3.708 70.267 4.374 70.411 ;
     RECT  5.148 69.581 5.166 70.411 ;
     RECT  3.708 70.411 5.166 71.755 ;
     RECT  5.94 69.581 9.918 71.755 ;
     RECT  22.212 69.899 26.514 71.959 ;
     RECT  27.36 69.899 42.318 71.959 ;
     RECT  22.212 71.959 42.318 72.149 ;
     RECT  27.288 72.149 42.318 72.293 ;
     RECT  2.304 70.219 2.697 73.103 ;
     RECT  3.708 71.755 9.918 73.229 ;
     RECT  3.708 73.229 5.202 73.265 ;
     RECT  4.788 73.265 5.202 73.409 ;
     RECT  0.54 73.507 0.558 73.565 ;
     RECT  5.148 73.409 5.202 73.769 ;
     RECT  2.415 73.103 2.697 74.011 ;
     RECT  2.304 74.011 2.697 74.047 ;
     RECT  3.708 73.265 4.014 74.047 ;
     RECT  27.36 72.293 42.318 74.155 ;
     RECT  22.212 72.149 26.514 74.281 ;
     RECT  27.288 74.155 42.318 74.281 ;
     RECT  2.304 74.047 4.014 74.461 ;
     RECT  2.304 74.461 4.05 74.615 ;
     RECT  5.148 73.769 5.166 74.779 ;
     RECT  5.94 73.229 9.918 74.779 ;
     RECT  3.708 74.615 4.05 75.001 ;
     RECT  3.708 75.001 4.374 75.155 ;
     RECT  2.415 74.615 2.697 75.397 ;
     RECT  2.415 75.397 2.826 75.541 ;
     RECT  3.708 75.155 3.726 75.541 ;
     RECT  2.415 75.541 3.726 75.581 ;
     RECT  2.415 75.581 2.697 75.883 ;
     RECT  2.304 75.883 2.697 75.965 ;
     RECT  3.708 75.581 3.726 76.045 ;
     RECT  3.708 76.045 4.374 76.081 ;
     RECT  5.148 74.779 9.918 76.081 ;
     RECT  2.415 75.965 2.697 76.309 ;
     RECT  2.415 76.309 2.826 76.349 ;
     RECT  3.708 76.081 9.918 76.505 ;
     RECT  22.212 74.281 42.318 76.811 ;
     RECT  4.536 76.505 9.918 77.009 ;
     RECT  4.536 77.009 5.166 77.045 ;
     RECT  2.415 76.349 2.697 77.275 ;
     RECT  5.112 77.045 5.166 77.279 ;
     RECT  2.304 77.275 2.697 77.935 ;
     RECT  3.708 76.505 3.726 77.935 ;
     RECT  2.304 77.935 3.726 78.125 ;
     RECT  5.148 77.279 5.166 78.283 ;
     RECT  27.396 76.811 42.318 78.367 ;
     RECT  2.304 78.125 2.697 78.395 ;
     RECT  27.36 78.367 42.318 78.503 ;
     RECT  3.456 78.125 3.726 78.511 ;
     RECT  4.536 78.283 5.166 78.511 ;
     RECT  3.456 78.511 5.166 78.629 ;
     RECT  3.456 78.629 3.87 78.665 ;
     RECT  0.072 78.637 0.09 78.701 ;
     RECT  4.896 78.629 5.166 78.899 ;
     RECT  3.456 78.665 3.762 78.935 ;
     RECT  2.415 78.395 2.697 79.147 ;
     RECT  2.412 79.147 2.697 79.627 ;
     RECT  2.304 79.627 2.697 79.675 ;
     RECT  3.708 78.935 3.762 79.675 ;
     RECT  2.304 79.675 4.014 80.015 ;
     RECT  3.708 80.015 4.014 80.221 ;
     RECT  5.148 78.899 5.166 80.395 ;
     RECT  5.94 77.009 9.918 80.395 ;
     RECT  3.708 80.221 4.374 80.401 ;
     RECT  5.148 80.395 9.918 80.401 ;
     RECT  22.212 76.811 26.514 80.491 ;
     RECT  27.396 78.503 42.318 80.491 ;
     RECT  3.708 80.401 9.918 80.555 ;
     RECT  22.212 80.491 42.318 80.591 ;
     RECT  4.572 80.555 9.918 80.825 ;
     RECT  22.212 80.591 26.514 81.571 ;
     RECT  27.396 80.591 42.318 81.571 ;
     RECT  3.708 80.555 3.726 81.595 ;
     RECT  5.004 80.825 9.918 81.595 ;
     RECT  22.212 81.571 42.318 81.671 ;
     RECT  2.304 80.015 2.697 82.021 ;
     RECT  3.708 81.595 9.918 82.205 ;
     RECT  22.212 81.671 26.514 82.651 ;
     RECT  27.396 81.671 42.318 82.651 ;
     RECT  22.212 82.651 42.318 82.751 ;
     RECT  4.752 82.205 9.918 82.985 ;
     RECT  2.304 82.021 2.826 83.371 ;
     RECT  3.708 82.205 3.726 83.371 ;
     RECT  2.304 83.371 2.898 83.489 ;
     RECT  2.304 83.489 2.697 83.525 ;
     RECT  3.708 83.371 3.834 83.605 ;
     RECT  4.752 82.985 5.166 83.605 ;
     RECT  0.072 83.767 0.09 83.885 ;
     RECT  3.708 83.605 5.166 83.911 ;
     RECT  5.94 82.985 9.918 83.911 ;
     RECT  3.708 83.911 9.918 84.029 ;
     RECT  3.708 84.029 5.166 84.605 ;
     RECT  2.415 83.525 2.697 84.811 ;
     RECT  3.708 84.605 3.726 85.459 ;
     RECT  4.5 84.605 5.166 85.459 ;
     RECT  2.304 84.811 2.697 85.955 ;
     RECT  3.708 85.459 5.166 86.189 ;
     RECT  2.415 85.955 2.697 86.197 ;
     RECT  3.708 86.189 4.374 86.225 ;
     RECT  2.415 86.197 2.826 86.237 ;
     RECT  5.148 86.189 5.166 86.341 ;
     RECT  5.94 84.029 9.918 86.341 ;
     RECT  2.415 86.237 2.697 86.683 ;
     RECT  2.412 86.683 2.697 86.765 ;
     RECT  5.148 86.341 9.918 87.035 ;
     RECT  3.708 86.225 3.726 87.043 ;
     RECT  3.708 87.043 4.05 87.151 ;
     RECT  5.148 87.035 5.166 87.151 ;
     RECT  3.6 87.151 5.166 87.305 ;
     RECT  2.415 86.765 2.697 87.583 ;
     RECT  2.415 87.583 2.826 87.629 ;
     RECT  3.708 87.305 5.166 87.787 ;
     RECT  5.94 87.035 9.918 87.787 ;
     RECT  3.708 87.787 9.918 87.809 ;
     RECT  2.415 87.629 2.79 88.349 ;
     RECT  2.415 88.349 2.697 88.555 ;
     RECT  3.708 87.809 4.374 88.771 ;
     RECT  5.148 87.809 9.918 88.771 ;
     RECT  2.304 88.555 2.697 89.195 ;
     RECT  3.708 88.771 9.918 89.465 ;
     RECT  2.415 89.195 2.697 89.947 ;
     RECT  4.536 89.465 9.918 90.275 ;
     RECT  3.708 89.465 3.726 90.931 ;
     RECT  3.708 90.931 4.23 91.049 ;
     RECT  2.304 89.947 2.697 91.085 ;
     RECT  2.415 91.085 2.697 91.147 ;
     RECT  3.708 91.049 3.726 91.147 ;
     RECT  2.415 91.147 3.726 91.355 ;
     RECT  5.148 90.275 9.918 91.471 ;
     RECT  4.572 91.471 9.918 91.625 ;
     RECT  2.415 91.355 2.697 91.819 ;
     RECT  4.824 91.625 9.918 92.551 ;
     RECT  3.708 91.355 3.726 92.911 ;
     RECT  4.788 92.551 9.918 92.911 ;
     RECT  2.304 91.819 2.697 92.975 ;
     RECT  3.708 92.911 9.918 93.659 ;
     RECT  2.415 92.975 2.697 94.171 ;
     RECT  2.304 94.171 2.697 94.325 ;
     RECT  3.708 93.659 5.166 94.567 ;
     RECT  3.708 94.567 5.202 94.603 ;
     RECT  0.072 94.567 0.09 94.685 ;
     RECT  3.636 94.603 5.202 94.703 ;
     RECT  3.636 94.703 5.166 94.865 ;
     RECT  2.415 94.325 2.697 95.107 ;
     RECT  3.708 94.865 5.166 95.135 ;
     RECT  4.68 95.135 5.166 95.369 ;
     RECT  11.124 61.529 21.474 95.521 ;
     RECT  2.412 95.107 2.697 95.611 ;
     RECT  10.8 95.521 21.474 95.639 ;
     RECT  5.148 95.369 5.166 95.719 ;
     RECT  5.94 93.659 9.918 95.719 ;
     RECT  5.148 95.719 9.918 95.945 ;
     RECT  2.304 95.611 2.697 96.215 ;
     RECT  5.148 95.945 5.166 96.331 ;
     RECT  4.824 96.331 5.166 96.449 ;
     RECT  3.708 95.135 3.906 96.601 ;
     RECT  3.708 96.601 4.05 96.719 ;
     RECT  5.148 96.449 5.166 96.859 ;
     RECT  5.94 95.945 9.918 96.859 ;
     RECT  2.415 96.215 2.697 97.141 ;
     RECT  2.415 97.141 2.898 97.259 ;
     RECT  2.415 97.259 2.697 97.483 ;
     RECT  3.708 96.719 4.014 97.565 ;
     RECT  5.148 96.859 9.918 97.681 ;
     RECT  2.412 97.483 2.697 97.963 ;
     RECT  2.304 97.963 2.697 98.105 ;
     RECT  3.708 97.565 3.726 98.491 ;
     RECT  4.824 97.681 9.918 98.491 ;
     RECT  2.415 98.105 2.697 98.875 ;
     RECT  3.708 98.491 9.918 98.879 ;
     RECT  3.708 98.879 5.166 99.185 ;
     RECT  4.536 99.185 5.166 99.197 ;
     RECT  27.396 82.751 42.318 99.563 ;
     RECT  2.304 98.875 2.697 99.571 ;
     RECT  3.708 99.185 3.726 99.571 ;
     RECT  2.304 99.571 3.726 99.725 ;
     RECT  4.752 99.197 5.166 99.773 ;
     RECT  3.708 99.725 3.726 100.615 ;
     RECT  4.788 99.773 5.166 100.615 ;
     RECT  27.396 99.563 42.246 100.651 ;
     RECT  3.708 100.615 5.166 100.849 ;
     RECT  5.94 98.879 9.918 100.849 ;
     RECT  3.708 100.849 9.918 101.039 ;
     RECT  3.708 101.039 4.266 101.075 ;
     RECT  2.304 99.725 2.697 101.345 ;
     RECT  27.396 100.651 42.282 101.419 ;
     RECT  27.396 101.419 42.426 101.459 ;
     RECT  5.148 101.039 9.918 101.615 ;
     RECT  2.415 101.345 2.697 101.707 ;
     RECT  5.148 101.615 5.166 102.043 ;
     RECT  2.415 101.707 2.754 102.187 ;
     RECT  27.396 101.459 42.21 102.235 ;
     RECT  3.708 101.075 3.726 102.271 ;
     RECT  4.464 102.043 5.166 102.271 ;
     RECT  27.396 102.235 42.462 102.271 ;
     RECT  43.236 40.865 62.097 102.271 ;
     RECT  3.708 102.271 5.166 102.425 ;
     RECT  4.464 102.425 5.166 102.523 ;
     RECT  5.94 101.615 9.918 102.523 ;
     RECT  2.415 102.187 2.79 102.667 ;
     RECT  2.304 102.667 2.79 102.811 ;
     RECT  3.708 102.425 3.726 102.811 ;
     RECT  2.304 102.811 3.726 102.965 ;
     RECT  3.708 102.965 3.726 103.351 ;
     RECT  4.464 102.523 9.918 103.351 ;
     RECT  2.304 102.965 2.697 104.093 ;
     RECT  2.412 104.093 2.697 104.161 ;
     RECT  3.708 103.351 9.918 104.161 ;
     RECT  2.412 104.161 9.918 104.315 ;
     RECT  2.412 104.315 2.697 105.019 ;
     RECT  2.304 105.019 2.697 105.125 ;
     RECT  0.54 105.403 0.558 105.485 ;
     RECT  3.708 104.315 9.918 105.665 ;
     RECT  2.415 105.125 2.697 105.907 ;
     RECT  3.708 105.665 5.166 106.861 ;
     RECT  2.304 105.907 2.697 107.015 ;
     RECT  3.492 106.861 5.166 107.015 ;
     RECT  4.896 107.015 5.166 107.249 ;
     RECT  2.415 107.015 2.697 107.797 ;
     RECT  2.415 107.797 2.826 107.837 ;
     RECT  3.708 107.015 4.158 107.941 ;
     RECT  3.708 107.941 4.194 108.211 ;
     RECT  5.004 107.249 5.166 108.211 ;
     RECT  2.415 107.837 2.697 108.283 ;
     RECT  3.708 108.211 5.166 108.283 ;
     RECT  5.94 105.665 9.918 108.283 ;
     RECT  2.304 108.283 2.697 108.365 ;
     RECT  3.708 108.283 9.918 109.175 ;
     RECT  2.415 108.365 2.697 109.243 ;
     RECT  3.708 109.175 5.166 110.242 ;
     RECT  4.68 110.242 5.166 110.489 ;
     RECT  5.112 110.489 5.166 111.037 ;
     RECT  5.94 109.175 9.918 111.037 ;
     RECT  3.708 110.242 3.798 111.109 ;
     RECT  5.112 111.037 9.918 111.299 ;
     RECT  2.304 109.243 2.697 111.641 ;
     RECT  3.708 111.109 3.978 111.685 ;
     RECT  3.636 111.685 3.978 111.839 ;
     RECT  3.708 111.839 3.978 111.955 ;
     RECT  3.708 111.955 4.158 111.991 ;
     RECT  2.412 111.641 2.697 112.145 ;
     RECT  3.708 111.991 4.302 112.261 ;
     RECT  5.22 111.299 9.918 112.261 ;
     RECT  3.708 112.261 9.918 112.415 ;
     RECT  2.415 112.145 2.697 112.987 ;
     RECT  2.304 112.987 2.697 113.341 ;
     RECT  3.708 112.415 3.726 113.341 ;
     RECT  2.304 113.341 3.726 113.431 ;
     RECT  4.536 112.415 9.918 113.431 ;
     RECT  2.304 113.431 9.918 113.459 ;
     RECT  3.564 113.459 4.014 113.531 ;
     RECT  3.564 113.531 3.978 113.765 ;
     RECT  5.148 113.459 9.918 114.269 ;
     RECT  3.708 113.765 3.978 114.305 ;
     RECT  2.304 113.459 2.697 114.413 ;
     RECT  5.148 114.269 5.166 114.421 ;
     RECT  5.004 114.421 5.166 114.575 ;
     RECT  2.412 114.413 2.697 115.339 ;
     RECT  3.708 114.305 3.906 115.465 ;
     RECT  3.708 115.465 4.374 115.501 ;
     RECT  5.148 114.575 5.166 115.501 ;
     RECT  3.708 115.501 5.166 115.655 ;
     RECT  2.304 115.339 2.697 115.925 ;
     RECT  4.536 115.655 5.166 116.041 ;
     RECT  5.94 114.269 9.918 116.041 ;
     RECT  2.415 115.925 2.697 116.239 ;
     RECT  2.415 116.239 2.826 116.285 ;
     RECT  4.536 116.041 9.918 116.429 ;
     RECT  2.415 116.285 2.697 116.707 ;
     RECT  4.536 116.429 5.166 117.005 ;
     RECT  2.412 116.707 2.697 117.211 ;
     RECT  2.304 117.211 2.697 117.355 ;
     RECT  3.708 115.655 3.726 117.355 ;
     RECT  5.148 117.005 5.166 117.403 ;
     RECT  5.94 116.429 9.918 117.403 ;
     RECT  2.304 117.355 3.726 117.815 ;
     RECT  5.148 117.403 9.918 117.931 ;
     RECT  2.415 117.815 3.726 118.319 ;
     RECT  4.536 117.931 9.918 118.471 ;
     RECT  4.464 118.471 9.918 118.895 ;
     RECT  3.708 118.319 3.726 119.011 ;
     RECT  4.464 118.895 5.166 119.011 ;
     RECT  3.708 119.011 5.166 119.165 ;
     RECT  2.415 118.319 2.826 119.245 ;
     RECT  3.708 119.165 3.978 119.245 ;
     RECT  2.415 119.245 3.978 119.563 ;
     RECT  4.716 119.165 5.166 119.659 ;
     RECT  5.904 118.895 9.918 119.659 ;
     RECT  2.304 119.563 3.978 119.693 ;
     RECT  2.304 119.693 2.79 119.705 ;
     RECT  4.716 119.659 9.918 119.939 ;
     RECT  5.112 119.939 9.918 119.975 ;
     RECT  3.708 119.693 3.978 120.091 ;
     RECT  3.708 120.091 4.374 120.245 ;
     RECT  2.415 119.705 2.79 120.487 ;
     RECT  3.708 120.245 3.762 120.515 ;
     RECT  5.148 119.975 9.918 120.515 ;
     RECT  2.415 120.487 2.826 120.955 ;
     RECT  2.304 120.955 2.826 121.003 ;
     RECT  3.708 120.515 3.726 121.003 ;
     RECT  5.148 120.515 5.166 121.243 ;
     RECT  5.94 120.515 9.918 121.243 ;
     RECT  2.304 121.003 3.726 121.325 ;
     RECT  3.564 121.325 3.726 121.631 ;
     RECT  5.148 121.243 9.918 121.945 ;
     RECT  2.304 121.325 2.697 121.973 ;
     RECT  4.536 121.945 9.918 122.135 ;
     RECT  11.124 95.639 21.474 122.413 ;
     RECT  10.836 122.413 21.474 122.513 ;
     RECT  2.415 121.973 2.697 122.521 ;
     RECT  3.708 121.631 3.726 122.521 ;
     RECT  2.415 122.521 3.726 122.669 ;
     RECT  2.415 122.669 2.697 122.827 ;
     RECT  3.708 122.669 3.726 123.331 ;
     RECT  2.304 122.827 2.697 123.485 ;
     RECT  3.708 123.331 4.374 123.601 ;
     RECT  5.148 122.135 9.918 123.601 ;
     RECT  3.708 123.601 9.918 123.755 ;
     RECT  2.415 123.485 2.697 123.871 ;
     RECT  3.708 123.755 3.726 123.871 ;
     RECT  2.415 123.871 3.726 124.267 ;
     RECT  2.412 124.267 3.726 124.301 ;
     RECT  4.68 123.755 9.918 124.681 ;
     RECT  4.644 124.681 9.918 124.733 ;
     RECT  2.412 124.301 2.697 124.747 ;
     RECT  3.708 124.301 3.726 124.771 ;
     RECT  2.304 124.747 2.697 124.835 ;
     RECT  4.68 124.733 9.918 124.835 ;
     RECT  3.708 124.771 3.942 124.943 ;
     RECT  2.415 124.835 2.697 125.176 ;
     RECT  2.415 125.176 2.754 125.221 ;
     RECT  3.708 124.943 3.726 125.221 ;
     RECT  5.148 124.835 9.918 125.339 ;
     RECT  2.415 125.221 3.726 125.375 ;
     RECT  3.708 125.375 3.726 125.761 ;
     RECT  3.708 125.761 4.05 125.915 ;
     RECT  5.148 125.339 5.166 125.923 ;
     RECT  4.716 125.923 5.166 125.981 ;
     RECT  11.124 122.513 21.474 126.031 ;
     RECT  2.415 125.375 2.697 126.139 ;
     RECT  10.836 126.031 21.474 126.149 ;
     RECT  5.148 125.981 5.166 126.301 ;
     RECT  5.94 125.339 9.918 126.301 ;
     RECT  3.708 125.915 3.726 126.763 ;
     RECT  3.708 126.763 4.374 126.841 ;
     RECT  5.148 126.301 9.918 126.841 ;
     RECT  3.564 126.841 9.918 126.995 ;
     RECT  3.708 126.995 9.918 127.229 ;
     RECT  2.304 126.139 2.697 127.265 ;
     RECT  2.412 127.265 2.697 127.565 ;
     RECT  2.415 127.565 2.697 128.107 ;
     RECT  3.708 127.229 5.166 128.107 ;
     RECT  0.072 128.011 0.09 128.141 ;
     RECT  2.415 128.107 5.166 128.345 ;
     RECT  2.415 128.345 2.79 128.491 ;
     RECT  3.636 128.345 5.166 128.573 ;
     RECT  2.304 128.491 2.79 128.615 ;
     RECT  3.672 128.573 5.166 128.651 ;
     RECT  22.212 82.751 26.514 129.211 ;
     RECT  27.396 102.271 62.097 129.211 ;
     RECT  22.212 129.211 62.097 129.389 ;
     RECT  2.415 128.615 2.79 129.397 ;
     RECT  2.415 129.397 2.826 129.437 ;
     RECT  3.708 128.651 5.166 129.695 ;
     RECT  2.415 129.437 2.697 129.883 ;
     RECT  2.304 129.883 2.697 129.965 ;
     RECT  4.536 129.695 5.166 130.235 ;
     RECT  2.415 129.965 2.697 130.477 ;
     RECT  3.708 129.695 3.726 130.477 ;
     RECT  2.415 130.477 3.726 130.507 ;
     RECT  2.415 130.507 4.302 131.045 ;
     RECT  3.708 131.045 4.302 131.275 ;
     RECT  5.148 130.235 5.166 131.275 ;
     RECT  3.708 131.275 5.166 131.549 ;
     RECT  2.415 131.045 2.826 131.755 ;
     RECT  2.304 131.755 2.826 131.971 ;
     RECT  3.708 131.549 4.302 131.971 ;
     RECT  5.148 131.549 5.166 131.995 ;
     RECT  5.94 127.229 9.918 131.995 ;
     RECT  2.304 131.971 4.302 132.029 ;
     RECT  5.148 131.995 9.918 132.125 ;
     RECT  2.304 132.029 2.934 132.431 ;
     RECT  3.708 132.029 4.302 132.859 ;
     RECT  5.148 132.125 5.166 132.859 ;
     RECT  3.708 132.859 5.166 133.439 ;
     RECT  3.708 133.439 4.374 133.475 ;
     RECT  5.148 133.439 5.166 133.675 ;
     RECT  5.94 132.125 9.918 133.675 ;
     RECT  2.304 132.431 2.697 133.745 ;
     RECT  2.415 133.745 2.697 133.861 ;
     RECT  3.708 133.475 3.726 133.861 ;
     RECT  2.415 133.861 3.726 134.251 ;
     RECT  2.415 134.251 4.374 134.401 ;
     RECT  5.148 133.675 9.918 134.401 ;
     RECT  2.415 134.401 9.918 134.519 ;
     RECT  2.415 134.519 3.978 134.573 ;
     RECT  2.415 134.573 2.862 134.587 ;
     RECT  2.304 134.587 2.862 134.663 ;
     RECT  2.415 134.663 2.862 134.789 ;
     RECT  4.968 134.519 9.918 135.059 ;
     RECT  3.708 134.573 3.978 135.095 ;
     RECT  2.415 134.789 2.826 135.547 ;
     RECT  2.304 135.547 2.826 135.571 ;
     RECT  3.708 135.095 3.726 135.571 ;
     RECT  2.304 135.571 3.726 136.061 ;
     RECT  2.415 136.061 3.726 136.205 ;
     RECT  2.415 136.205 2.826 136.493 ;
     RECT  5.148 135.059 9.918 136.561 ;
     RECT  4.716 136.561 9.918 136.715 ;
     RECT  2.415 136.493 2.697 137.419 ;
     RECT  4.932 136.715 9.918 137.767 ;
     RECT  2.304 137.419 2.697 137.911 ;
     RECT  3.708 136.205 3.726 137.911 ;
     RECT  4.536 137.767 9.918 137.911 ;
     RECT  2.304 137.911 9.918 137.933 ;
     RECT  2.415 137.933 9.918 137.981 ;
     RECT  27.396 129.389 62.097 138.641 ;
     RECT  2.415 137.981 2.697 138.811 ;
     RECT  3.708 137.981 9.918 138.839 ;
     RECT  2.304 138.811 2.697 139.531 ;
     RECT  3.708 138.839 4.374 139.531 ;
     RECT  27.396 138.641 57.078 139.531 ;
     RECT  57.816 138.641 62.097 139.531 ;
     RECT  2.304 139.531 4.374 139.675 ;
     RECT  5.22 138.839 9.918 139.675 ;
     RECT  2.304 139.675 9.918 139.709 ;
     RECT  2.304 139.709 2.697 139.955 ;
     RECT  0.54 140.197 0.558 140.285 ;
     RECT  3.708 139.709 9.918 140.495 ;
     RECT  4.5 140.495 9.918 140.639 ;
     RECT  2.415 139.955 2.697 140.683 ;
     RECT  2.304 140.683 2.697 140.765 ;
     RECT  2.415 140.765 2.697 141.643 ;
     RECT  2.304 141.643 2.697 141.683 ;
     RECT  3.708 140.495 3.726 141.691 ;
     RECT  4.536 140.639 9.918 141.691 ;
     RECT  2.415 141.683 2.697 142.117 ;
     RECT  2.415 142.117 2.826 142.157 ;
     RECT  2.415 142.157 2.697 142.603 ;
     RECT  2.304 142.603 2.697 143.275 ;
     RECT  3.708 141.691 9.918 143.275 ;
     RECT  2.304 143.275 9.918 143.312 ;
     RECT  2.304 143.312 2.697 143.465 ;
     RECT  3.708 143.312 9.918 143.699 ;
     RECT  5.184 143.699 9.918 144.149 ;
     RECT  3.708 143.699 4.338 144.239 ;
     RECT  3.708 144.239 4.158 144.275 ;
     RECT  2.412 143.465 2.697 144.475 ;
     RECT  2.304 144.475 2.697 145.085 ;
     RECT  27.396 139.531 62.097 145.085 ;
     RECT  3.708 144.275 3.726 145.291 ;
     RECT  0.072 145.327 0.09 145.421 ;
     RECT  5.22 144.149 9.918 145.471 ;
     RECT  3.42 145.291 3.726 145.705 ;
     RECT  3.42 145.705 4.086 145.741 ;
     RECT  2.415 145.085 2.697 145.867 ;
     RECT  3.42 145.741 4.266 145.895 ;
     RECT  3.708 145.895 4.266 146.173 ;
     RECT  5.04 145.471 9.918 146.173 ;
     RECT  2.34 145.867 2.697 146.347 ;
     RECT  2.304 146.347 2.697 146.861 ;
     RECT  3.708 146.173 9.918 146.939 ;
     RECT  5.148 146.939 9.918 146.975 ;
     RECT  2.415 146.861 2.697 147.217 ;
     RECT  2.415 147.217 2.826 147.293 ;
     RECT  3.708 146.939 4.41 147.479 ;
     RECT  3.708 147.479 3.978 147.551 ;
     RECT  3.708 147.551 3.726 147.631 ;
     RECT  3.6 147.631 3.726 148.019 ;
     RECT  2.415 147.293 2.79 148.055 ;
     RECT  2.415 148.055 2.697 154.987 ;
     RECT  3.708 148.019 3.726 155.011 ;
     RECT  5.148 146.975 5.166 155.011 ;
     RECT  5.94 146.975 9.918 155.011 ;
     RECT  2.304 154.987 2.697 155.075 ;
     RECT  5.148 155.011 9.918 155.309 ;
     RECT  3.708 155.011 3.978 155.345 ;
     RECT  5.148 155.309 5.166 155.389 ;
     RECT  22.212 129.389 26.514 165.541 ;
     RECT  27.396 145.085 60.966 165.541 ;
     RECT  11.124 126.149 21.474 166.225 ;
     RECT  5.94 155.309 9.918 166.261 ;
     RECT  5.94 166.261 10.278 166.351 ;
     RECT  11.052 166.225 21.474 166.351 ;
     RECT  5.94 166.351 21.474 166.621 ;
     RECT  22.212 165.541 60.966 166.621 ;
     RECT  4.536 155.389 5.166 166.891 ;
     RECT  5.94 166.621 60.966 166.891 ;
     RECT  3.708 155.345 3.726 167.035 ;
     RECT  4.536 166.891 60.966 167.035 ;
     RECT  3.708 167.035 60.966 168.139 ;
     RECT  3.564 168.139 60.966 168.269 ;
     RECT  4.284 168.269 60.966 168.421 ;
     RECT  61.815 145.085 62.097 168.421 ;
     RECT  4.284 168.421 62.097 168.809 ;
     RECT  4.5 168.809 62.097 169.771 ;
     RECT  4.248 169.771 62.097 170.131 ;
     RECT  4.104 170.131 62.097 170.311 ;
     RECT  2.415 155.075 2.697 170.387 ;
     RECT  3.564 170.311 62.097 170.387 ;
     RECT  3.564 170.387 61.905 170.429 ;
     RECT  3.564 170.429 33.39 170.477 ;
     RECT  37.512 170.429 38.97 170.477 ;
     RECT  40.215 170.429 42.534 170.477 ;
     RECT  43.308 170.429 60.39 170.477 ;
     RECT  3.564 170.477 4.806 170.573 ;
     RECT  12.24 170.477 33.354 170.573 ;
     RECT  41.22 170.477 42.534 170.609 ;
     RECT  45.615 170.477 60.39 170.609 ;
     RECT  2.415 170.387 2.505 170.657 ;
     RECT  12.24 170.573 28.062 170.657 ;
     RECT  40.215 170.477 40.305 170.657 ;
     RECT  45.615 170.609 51.174 170.657 ;
     RECT  61.815 170.429 61.905 170.657 ;
     RECT  19.368 170.657 28.062 170.765 ;
     RECT  12.24 170.657 18.198 170.813 ;
     RECT  46.008 170.657 51.174 170.813 ;
     RECT  19.368 170.765 25.326 170.957 ;
     RECT  34.236 170.429 36.666 170.957 ;
     RECT  52.092 170.609 60.39 170.957 ;
     RECT  5.616 170.477 11.322 171.005 ;
     RECT  13.356 170.813 18.198 171.005 ;
     RECT  19.368 170.957 24.462 171.005 ;
     RECT  26.064 170.765 28.062 171.005 ;
     RECT  28.872 170.573 33.354 171.005 ;
     RECT  34.236 170.957 36.486 171.005 ;
     RECT  37.512 170.477 38.106 171.005 ;
     RECT  41.22 170.609 41.418 171.005 ;
     RECT  42.156 170.609 42.534 171.005 ;
     RECT  43.308 170.477 44.766 171.005 ;
     RECT  47.232 170.813 51.174 171.005 ;
     RECT  52.092 170.957 58.842 171.005 ;
     RECT  59.832 170.957 59.85 171.005 ;
     RECT  4.068 170.573 4.806 171.053 ;
     RECT  13.788 171.005 14.562 171.053 ;
     RECT  29.556 171.005 30.006 171.053 ;
     RECT  31.464 171.005 32.166 171.053 ;
     RECT  42.408 171.005 42.534 171.053 ;
     RECT  4.104 171.053 4.806 171.149 ;
     RECT  5.616 171.005 6.174 171.533 ;
     RECT  4.788 171.149 4.806 171.581 ;
     RECT  5.616 171.533 6.102 171.581 ;
     RECT  7.452 171.005 7.47 171.581 ;
     RECT  8.28 171.005 11.322 171.581 ;
     RECT  12.24 170.813 12.582 171.581 ;
     RECT  13.788 171.053 14.418 171.581 ;
     RECT  15.372 171.005 16.326 171.581 ;
     RECT  17.316 171.005 17.982 171.581 ;
     RECT  19.476 171.005 21.978 171.581 ;
     RECT  22.86 171.005 23.67 171.581 ;
     RECT  24.444 171.005 24.462 171.581 ;
     RECT  34.236 171.005 35.01 171.581 ;
     RECT  36.072 171.005 36.342 171.581 ;
     RECT  37.512 171.005 37.53 171.581 ;
     RECT  38.952 170.477 38.97 171.581 ;
     RECT  41.4 171.005 41.418 171.581 ;
     RECT  42.408 171.053 42.426 171.581 ;
     RECT  43.596 171.005 43.614 171.581 ;
     RECT  46.008 170.813 46.314 171.581 ;
     RECT  47.232 171.005 49.266 171.581 ;
     RECT  52.092 171.005 54.522 171.581 ;
     RECT  55.764 171.005 56.322 171.581 ;
     RECT  58.032 171.005 58.842 171.581 ;
     RECT  9.324 171.581 11.034 171.629 ;
     RECT  15.768 171.581 16.326 171.629 ;
     RECT  19.656 171.581 20.034 171.629 ;
     RECT  56.304 171.581 56.322 171.629 ;
     RECT  9.324 171.629 9.63 172.157 ;
     RECT  10.368 171.629 11.034 172.157 ;
     RECT  12.564 171.581 12.582 172.157 ;
     RECT  16.308 171.629 16.326 172.157 ;
     RECT  17.46 171.581 17.982 172.157 ;
     RECT  20.808 171.581 21.438 172.157 ;
     RECT  27.18 171.005 27.198 172.157 ;
     RECT  29.556 171.053 29.826 172.157 ;
     RECT  31.464 171.053 31.482 172.157 ;
     RECT  34.992 171.581 35.01 172.157 ;
     RECT  46.008 171.581 46.026 172.157 ;
     RECT  47.232 171.581 48.33 172.157 ;
     RECT  50.004 171.005 50.994 172.157 ;
     RECT  52.524 171.581 53.01 172.157 ;
     RECT  54.504 171.581 54.522 172.157 ;
     RECT  57.168 171.005 57.186 172.157 ;
     RECT  58.032 171.581 58.05 172.157 ;
     RECT  58.824 171.581 58.842 172.157 ;
     RECT  9.612 172.157 9.63 172.733 ;
     RECT  10.656 172.157 11.034 172.733 ;
     RECT  21.42 172.157 21.438 172.733 ;
     RECT  29.808 172.157 29.826 172.733 ;
     RECT  36.324 171.581 36.342 172.733 ;
     RECT  47.232 172.157 47.25 172.733 ;
     RECT  47.988 172.157 48.006 172.733 ;
     RECT  50.256 172.157 50.994 172.733 ;
    LAYER M4 ;
     RECT  0.06 8.208 0.101 147.768 ;
     RECT  0.101 8.208 2.408 21.864 ;
     RECT  0.101 23.28 2.408 147.768 ;
     RECT  2.408 2.148 2.512 170.652 ;
     RECT  2.512 2.418 2.704 170.382 ;
     RECT  2.704 35.472 2.765 35.496 ;
     RECT  2.704 65.52 2.765 66.024 ;
     RECT  2.704 101.712 2.765 102.216 ;
     RECT  2.704 124.272 2.765 125.208 ;
     RECT  2.704 15.744 2.801 17.64 ;
     RECT  2.704 60.384 2.801 60.456 ;
     RECT  2.765 102.192 2.801 102.216 ;
     RECT  2.704 147.264 2.801 147.768 ;
     RECT  2.801 15.744 2.837 15.768 ;
     RECT  2.704 26.544 2.837 26.568 ;
     RECT  2.704 28.944 2.837 29.88 ;
     RECT  2.704 33.6 2.837 34.248 ;
     RECT  2.704 37.344 2.837 37.368 ;
     RECT  2.704 57.072 2.837 57.096 ;
     RECT  2.765 66 2.837 66.024 ;
     RECT  2.704 69.744 2.837 69.768 ;
     RECT  2.704 75.408 2.837 76.344 ;
     RECT  2.704 86.208 2.837 86.232 ;
     RECT  2.704 87.6 2.837 87.624 ;
     RECT  2.704 107.808 2.837 107.832 ;
     RECT  2.704 116.256 2.837 116.28 ;
     RECT  2.704 117.408 2.837 118.2 ;
     RECT  2.704 128.112 2.837 129.432 ;
     RECT  2.704 130.512 2.837 132.024 ;
     RECT  2.704 134.544 2.837 136.488 ;
     RECT  2.704 142.128 2.837 142.152 ;
     RECT  2.801 147.264 2.837 147.288 ;
     RECT  2.837 128.112 3.017 128.568 ;
     RECT  2.704 78.048 3.305 78.072 ;
     RECT  2.704 119.664 3.34 121.032 ;
     RECT  2.704 10.272 3.443 11.448 ;
     RECT  2.704 63.216 3.443 64.44 ;
     RECT  3.443 10.272 3.485 10.824 ;
     RECT  2.704 68.352 3.733 68.376 ;
     RECT  2.704 74.064 3.877 74.088 ;
     RECT  2.704 8.16 3.913 8.184 ;
     RECT  3.877 74.064 3.917 74.328 ;
     RECT  2.837 28.944 3.973 28.968 ;
     RECT  2.704 143.28 3.973 143.304 ;
     RECT  2.704 145.296 3.973 145.32 ;
     RECT  3.949 147.072 3.973 147.096 ;
     RECT  3.973 28.944 4.019 29.496 ;
     RECT  3.973 145.296 4.019 147.096 ;
     RECT  3.941 27.312 4.025 27.336 ;
     RECT  2.704 79.152 4.025 79.704 ;
     RECT  4.019 145.728 4.033 147.096 ;
     RECT  3.949 38.256 4.069 38.856 ;
     RECT  4.028 171.024 4.093 171.048 ;
     RECT  4.033 145.728 4.097 146.52 ;
     RECT  2.837 132 4.129 132.024 ;
     RECT  3.949 32.448 4.165 32.472 ;
     RECT  2.837 34.224 4.165 34.248 ;
     RECT  4.069 37.488 4.201 38.856 ;
     RECT  4.124 3.696 4.211 3.72 ;
     RECT  4.021 5.04 4.211 5.064 ;
     RECT  4.172 15.888 4.213 15.912 ;
     RECT  4.057 0.576 4.237 0.6 ;
     RECT  3.485 10.272 4.309 10.296 ;
     RECT  2.704 139.68 4.309 139.704 ;
     RECT  2.704 58.8 4.316 58.824 ;
     RECT  2.704 82.176 4.316 82.2 ;
     RECT  3.985 12.72 4.345 12.744 ;
     RECT  2.801 60.432 4.345 60.456 ;
     RECT  3.733 71.808 4.345 71.832 ;
     RECT  2.837 75.552 4.345 75.576 ;
     RECT  2.837 134.544 4.345 134.568 ;
     RECT  4.069 167.04 4.345 167.064 ;
     RECT  2.704 168.144 4.345 168.168 ;
     RECT  4.019 29.472 4.357 29.496 ;
     RECT  4.165 34.224 4.385 34.824 ;
     RECT  4.316 81.6 4.385 82.2 ;
     RECT  4.201 36.96 4.403 38.856 ;
     RECT  4.316 58.8 4.403 58.92 ;
     RECT  2.704 19.92 4.405 19.944 ;
     RECT  3.913 21.648 4.405 21.672 ;
     RECT  3.733 111.168 4.417 111.192 ;
     RECT  4.345 167.04 4.417 168.168 ;
     RECT  4.345 30.816 4.429 31.368 ;
     RECT  4.345 57.552 4.429 57.576 ;
     RECT  4.345 80.352 4.429 80.376 ;
     RECT  4.093 171.024 4.453 171.144 ;
     RECT  4.405 19.92 4.493 20.184 ;
     RECT  4.345 40.416 4.501 40.44 ;
     RECT  4.345 115.488 4.501 115.512 ;
     RECT  3.017 128.544 4.501 128.568 ;
     RECT  2.837 130.512 4.501 130.536 ;
     RECT  4.129 132 4.501 132.12 ;
     RECT  4.417 167.04 4.501 168.792 ;
     RECT  4.237 0.096 4.525 0.6 ;
     RECT  4.229 1.728 4.525 1.752 ;
     RECT  4.345 60.24 4.525 60.456 ;
     RECT  3.949 65.568 4.525 65.592 ;
     RECT  4.025 79.152 4.525 79.272 ;
     RECT  3.985 94.08 4.525 94.104 ;
     RECT  4.453 99.744 4.525 99.768 ;
     RECT  4.345 103.728 4.525 103.752 ;
     RECT  2.765 124.272 4.525 124.296 ;
     RECT  2.704 137.952 4.525 137.976 ;
     RECT  3.973 143.28 4.525 144.12 ;
     RECT  4.525 0.096 4.529 1.752 ;
     RECT  4.357 29.472 4.529 29.688 ;
     RECT  4.345 100.848 4.54 100.872 ;
     RECT  4.405 18.816 4.547 18.84 ;
     RECT  4.405 21.648 4.547 21.768 ;
     RECT  4.501 115.488 4.547 116.232 ;
     RECT  4.501 130.512 4.547 132.888 ;
     RECT  4.309 139.68 4.547 140.232 ;
     RECT  4.501 166.944 4.547 168.792 ;
     RECT  4.453 24.48 4.549 24.504 ;
     RECT  4.508 55.824 4.561 55.848 ;
     RECT  4.213 15.888 4.565 16.68 ;
     RECT  4.453 170.976 4.565 171.144 ;
     RECT  4.547 131.28 4.588 132.888 ;
     RECT  4.501 141.264 4.588 142.056 ;
     RECT  4.345 12.72 4.595 13.704 ;
     RECT  4.549 24.48 4.595 25.176 ;
     RECT  4.561 55.152 4.595 55.848 ;
     RECT  4.525 123.648 4.604 124.296 ;
     RECT  4.525 11.376 4.609 11.4 ;
     RECT  4.595 25.152 4.636 25.176 ;
     RECT  4.604 123.648 4.645 124.728 ;
     RECT  4.345 126.768 4.645 126.792 ;
     RECT  4.549 17.664 4.673 17.688 ;
     RECT  4.645 123.648 4.691 126.792 ;
     RECT  3.733 67.824 4.7 68.376 ;
     RECT  4.345 71.808 4.703 71.88 ;
     RECT  4.345 105.408 4.705 105.432 ;
     RECT  4.493 19.92 4.709 19.944 ;
     RECT  3.443 63.216 4.709 64.056 ;
     RECT  4.691 123.648 4.709 126.264 ;
     RECT  4.547 168.144 4.739 168.792 ;
     RECT  2.704 53.568 4.741 53.592 ;
     RECT  4.345 70.272 4.741 70.296 ;
     RECT  4.595 13.008 4.745 13.32 ;
     RECT  4.705 104.88 4.745 105.432 ;
     RECT  4.709 125.184 4.745 126.264 ;
     RECT  4.588 131.28 4.745 132.024 ;
     RECT  4.547 139.68 4.745 139.704 ;
     RECT  4.525 94.08 4.781 94.68 ;
     RECT  4.525 99.168 4.781 99.768 ;
     RECT  4.525 103.152 4.781 103.752 ;
     RECT  4.525 143.04 4.781 144.12 ;
     RECT  4.7 67.728 4.787 68.376 ;
     RECT  4.741 69.552 4.787 70.296 ;
     RECT  4.547 166.944 4.817 166.968 ;
     RECT  4.385 34.224 4.853 34.248 ;
     RECT  4.403 37.008 4.853 38.856 ;
     RECT  4.529 0.096 4.883 1.128 ;
     RECT  4.309 10.224 4.885 10.296 ;
     RECT  4.703 71.52 4.921 71.88 ;
     RECT  3.913 7.344 4.931 8.184 ;
     RECT  4.844 15.648 4.931 15.672 ;
     RECT  4.885 10.224 4.979 10.872 ;
     RECT  4.837 169.872 4.988 169.896 ;
     RECT  4.979 10.224 5.029 10.584 ;
     RECT  4.739 168.144 5.041 168.6 ;
     RECT  4.988 169.872 5.075 170.472 ;
     RECT  4.931 7.776 5.077 8.184 ;
     RECT  4.345 75.552 5.125 76.152 ;
     RECT  5.101 77.184 5.125 77.208 ;
     RECT  2.704 49.488 5.132 49.512 ;
     RECT  2.704 91.152 5.137 91.176 ;
     RECT  4.129 83.76 5.141 83.784 ;
     RECT  4.853 37.008 5.149 38.664 ;
     RECT  4.549 26.208 5.173 26.232 ;
     RECT  5.132 49.488 5.173 49.992 ;
     RECT  5.137 91.152 5.173 91.8 ;
     RECT  5.075 169.872 5.173 170.424 ;
     RECT  5.029 9.648 5.177 10.584 ;
     RECT  4.309 92.928 5.177 92.952 ;
     RECT  4.453 102.048 5.18 102.072 ;
     RECT  4.781 103.152 5.18 103.176 ;
     RECT  2.704 122.64 5.18 122.664 ;
     RECT  4.501 40.416 5.209 40.728 ;
     RECT  5.18 122.64 5.209 123.384 ;
     RECT  5.149 38.112 5.213 38.664 ;
     RECT  4.525 60.24 5.213 61.368 ;
     RECT  4.883 1.056 5.219 1.128 ;
     RECT  5.173 49.008 5.219 50.568 ;
     RECT  4.417 110.208 5.219 111.192 ;
     RECT  4.525 112.272 5.221 112.296 ;
     RECT  4.501 128.544 5.221 129.288 ;
     RECT  5.173 90.192 5.241 91.8 ;
     RECT  5.221 112.272 5.241 112.872 ;
     RECT  4.745 13.008 5.249 13.032 ;
     RECT  5.209 39.888 5.249 40.728 ;
     RECT  5.18 102.048 5.249 103.176 ;
     RECT  5.249 102.048 5.267 102.552 ;
     RECT  3.917 74.304 5.276 74.328 ;
     RECT  5.125 75.552 5.276 77.208 ;
     RECT  4.345 134.256 5.276 134.568 ;
     RECT  5.219 50.544 5.281 50.568 ;
     RECT  4.529 29.664 5.285 29.688 ;
     RECT  4.787 67.776 5.285 68.376 ;
     RECT  4.525 137.904 5.285 137.976 ;
     RECT  4.921 71.52 5.317 72.408 ;
     RECT  5.221 128.544 5.317 129.432 ;
     RECT  5.173 169.68 5.321 170.424 ;
     RECT  5.281 50.544 5.353 51.24 ;
     RECT  4.385 81.6 5.353 82.056 ;
     RECT  4.781 143.28 5.353 144.12 ;
     RECT  5.276 74.304 5.363 77.208 ;
     RECT  4.525 78.288 5.363 79.272 ;
     RECT  5.276 133.68 5.363 134.568 ;
     RECT  5.281 80.4 5.365 80.424 ;
     RECT  3.34 119.664 5.365 120.504 ;
     RECT  5.209 122.544 5.365 123.384 ;
     RECT  5.353 81.6 5.389 82.104 ;
     RECT  4.709 64.032 5.393 64.056 ;
     RECT  4.604 2.256 5.411 2.28 ;
     RECT  5.324 92.832 5.411 92.856 ;
     RECT  5.267 102.048 5.411 102.072 ;
     RECT  5.363 134.016 5.413 134.568 ;
     RECT  2.837 135.6 5.413 136.2 ;
     RECT  5.353 143.28 5.437 144.216 ;
     RECT  5.321 170.4 5.437 170.424 ;
     RECT  5.365 119.664 5.452 123.384 ;
     RECT  5.285 137.904 5.461 137.928 ;
     RECT  5.177 10.224 5.465 10.584 ;
     RECT  4.403 58.8 5.465 58.824 ;
     RECT  5.363 75.552 5.465 77.208 ;
     RECT  5.413 134.016 5.5 136.2 ;
     RECT  5.077 7.776 5.501 8.52 ;
     RECT  5.285 67.776 5.501 67.848 ;
     RECT  4.745 125.184 5.501 125.208 ;
     RECT  5.452 122.064 5.507 123.384 ;
     RECT  5.241 112.848 5.529 112.872 ;
     RECT  4.417 42.192 5.564 42.216 ;
     RECT  4.633 43.776 5.564 43.8 ;
     RECT  4.345 88.944 5.564 88.968 ;
     RECT  5.241 90.192 5.564 90.408 ;
     RECT  2.837 117.408 5.569 117.432 ;
     RECT  4.844 118.512 5.569 118.536 ;
     RECT  3.877 96.864 5.573 96.888 ;
     RECT  5.173 26.208 5.605 26.712 ;
     RECT  4.511 57.744 5.605 57.768 ;
     RECT  4.525 65.568 5.605 66.12 ;
     RECT  5.389 81.456 5.605 82.104 ;
     RECT  4.417 108.288 5.605 108.312 ;
     RECT  5.569 117.408 5.605 118.536 ;
     RECT  5.5 135.504 5.605 136.2 ;
     RECT  4.345 47.904 5.609 47.928 ;
     RECT  5.605 117.408 5.609 118.584 ;
     RECT  5.452 119.664 5.609 120.504 ;
     RECT  4.429 31.344 5.645 31.368 ;
     RECT  5.564 42.192 5.645 42.744 ;
     RECT  5.605 135.504 5.645 136.632 ;
     RECT  5.645 42.72 5.651 42.744 ;
     RECT  5.564 43.776 5.651 44.328 ;
     RECT  5.564 88.944 5.651 90.408 ;
     RECT  5.605 107.712 5.651 108.312 ;
     RECT  4.741 52.416 5.653 52.44 ;
     RECT  4.741 53.568 5.653 54.12 ;
     RECT  5.609 117.936 5.653 118.584 ;
     RECT  5.645 136.608 5.653 136.632 ;
     RECT  5.461 137.856 5.653 137.928 ;
     RECT  5.605 26.208 5.673 27.384 ;
     RECT  5.653 52.416 5.681 54.12 ;
     RECT  5.673 26.64 5.689 27.384 ;
     RECT  5.681 52.416 5.699 53.592 ;
     RECT  5.653 136.608 5.699 137.928 ;
     RECT  5.213 60.432 5.708 61.368 ;
     RECT  4.645 171.552 5.749 171.576 ;
     RECT  5.708 60.432 5.785 61.608 ;
     RECT  5.101 15.312 5.789 15.336 ;
     RECT  5.785 60.432 5.789 62.136 ;
     RECT  5.605 81.456 5.789 82.68 ;
     RECT  5.653 118.56 5.789 118.584 ;
     RECT  5.353 50.544 5.795 51.288 ;
     RECT  5.789 61.584 5.795 62.136 ;
     RECT  5.317 71.52 5.795 72.984 ;
     RECT  5.501 8.16 5.821 8.52 ;
     RECT  4.565 16.656 5.821 16.68 ;
     RECT  5.821 16.656 5.825 17.112 ;
     RECT  5.795 50.544 5.825 51.24 ;
     RECT  5.605 57.744 5.825 58.632 ;
     RECT  5.465 76.368 5.825 77.208 ;
     RECT  5.241 91.776 5.825 91.8 ;
     RECT  5.507 122.064 5.825 123.336 ;
     RECT  5.699 137.088 5.825 137.928 ;
     RECT  5.041 168.576 5.825 168.6 ;
     RECT  4.165 32.448 5.897 32.904 ;
     RECT  5.789 60.432 5.897 60.6 ;
     RECT  5.651 88.944 5.897 88.968 ;
     RECT  5.609 120.192 5.897 120.504 ;
     RECT  5.437 143.28 5.897 143.304 ;
     RECT  5.219 111.024 5.933 111.192 ;
     RECT  5.821 8.16 5.969 9.192 ;
     RECT  4.345 23.328 5.989 23.352 ;
     RECT  4.525 85.488 5.996 85.512 ;
     RECT  5.317 128.544 5.996 129.672 ;
     RECT  4.781 99.744 6.001 99.768 ;
     RECT  4.588 141.264 6.001 141.288 ;
     RECT  5.989 22.752 6.035 23.352 ;
     RECT  5.996 84.912 6.037 85.512 ;
     RECT  5.996 128.544 6.037 129.912 ;
     RECT  5.249 39.888 6.041 39.912 ;
     RECT  4.787 69.552 6.041 69.576 ;
     RECT  5.795 72.96 6.041 72.984 ;
     RECT  5.363 79.152 6.041 79.272 ;
     RECT  5.789 81.456 6.041 81.48 ;
     RECT  4.781 94.656 6.041 94.68 ;
     RECT  6.001 99.744 6.041 99.912 ;
     RECT  5.653 139.104 6.041 139.128 ;
     RECT  6.001 140.736 6.041 141.288 ;
     RECT  4.885 6.192 6.065 6.216 ;
     RECT  6.035 22.752 6.076 22.776 ;
     RECT  5.605 65.52 6.077 66.12 ;
     RECT  6.037 84.912 6.083 86.088 ;
     RECT  6.037 128.352 6.083 129.912 ;
     RECT  5.689 26.64 6.113 26.76 ;
     RECT  5.749 171.504 6.113 171.576 ;
     RECT  6.065 6.192 6.149 6.264 ;
     RECT  5.897 32.448 6.149 32.472 ;
     RECT  4.921 4.992 6.181 5.016 ;
     RECT  5.213 38.16 6.181 38.28 ;
     RECT  6.113 171.504 6.185 171.528 ;
     RECT  5.969 8.16 6.221 8.184 ;
     RECT  5.857 87.792 6.229 87.816 ;
     RECT  5.795 62.112 6.257 62.136 ;
     RECT  6.181 168.144 6.265 168.168 ;
     RECT  6.229 87.168 6.275 87.816 ;
     RECT  5.605 113.952 6.361 113.976 ;
     RECT  5.969 9.168 6.365 9.192 ;
     RECT  6.109 0.096 6.371 0.12 ;
     RECT  5.465 10.224 6.401 10.248 ;
     RECT  6.361 113.952 6.401 114.456 ;
     RECT  6.149 6.192 6.433 6.216 ;
     RECT  5.699 52.944 6.437 52.968 ;
     RECT  6.433 6 6.473 6.216 ;
     RECT  5.605 18.816 6.505 18.84 ;
     RECT  6.401 114.432 6.517 114.456 ;
     RECT  5.557 1.728 6.541 2.232 ;
     RECT  6.505 18.144 6.541 18.84 ;
     RECT  6.517 114.432 6.563 114.984 ;
     RECT  5.651 107.712 6.581 107.736 ;
     RECT  5.569 64.224 6.613 64.248 ;
     RECT  5.501 67.776 6.613 67.8 ;
     RECT  5.5 134.016 6.613 134.04 ;
     RECT  6.613 133.968 6.614 134.04 ;
     RECT  5.789 82.656 6.653 82.68 ;
     RECT  6.572 11.424 6.659 11.448 ;
     RECT  6.077 65.52 6.659 65.544 ;
     RECT  6.605 10.128 6.689 10.152 ;
     RECT  6.541 18.144 6.689 19.368 ;
     RECT  4.745 104.88 6.689 104.904 ;
     RECT  6.181 4.56 6.721 5.016 ;
     RECT  6.473 6 6.721 6.024 ;
     RECT  6.541 1.728 6.755 2.28 ;
     RECT  5.825 17.088 6.755 17.112 ;
     RECT  6.229 3.408 6.757 3.432 ;
     RECT  6.721 4.56 6.757 6.024 ;
     RECT  6.181 38.16 6.793 38.76 ;
     RECT  6.709 15.6 6.797 15.624 ;
     RECT  6.793 38.16 6.829 39.048 ;
     RECT  5.897 60.576 6.829 60.6 ;
     RECT  5.825 77.184 6.829 77.208 ;
     RECT  5.365 166.08 6.829 166.104 ;
     RECT  6.757 3.408 6.833 6.024 ;
     RECT  5.825 122.256 6.833 123.336 ;
     RECT  4.745 132 6.853 132.024 ;
     RECT  6.829 35.568 6.901 35.592 ;
     RECT  6.853 42.768 6.901 42.792 ;
     RECT  5.219 49.008 6.901 49.032 ;
     RECT  6.113 26.64 6.949 26.712 ;
     RECT  6.325 170.976 7.045 171 ;
     RECT  5.825 58.608 7.093 58.632 ;
     RECT  7.093 58.56 7.117 58.632 ;
     RECT  5.897 120.192 7.117 120.216 ;
     RECT  6.829 60.576 7.141 60.696 ;
     RECT  4.885 21.36 7.225 21.384 ;
     RECT  6.829 166.08 7.237 166.488 ;
     RECT  6.517 167.904 7.237 167.928 ;
     RECT  6.949 26.208 7.253 26.712 ;
     RECT  6.901 34.704 7.381 35.592 ;
     RECT  7.045 170.928 7.397 171 ;
     RECT  6.755 1.728 7.765 2.04 ;
     RECT  6.833 3.408 7.765 5.016 ;
     RECT  7.765 1.728 7.808 5.016 ;
     RECT  6.833 6 7.808 6.024 ;
     RECT  6.865 14.832 7.808 14.952 ;
     RECT  6.689 18.144 7.808 18.84 ;
     RECT  7.225 21.36 7.808 21.432 ;
     RECT  6.937 24.912 7.808 24.936 ;
     RECT  7.253 26.208 7.808 26.808 ;
     RECT  7.081 28.464 7.808 28.488 ;
     RECT  6.037 30.48 7.808 30.504 ;
     RECT  7.117 31.92 7.808 31.944 ;
     RECT  7.381 34.464 7.808 35.592 ;
     RECT  5.149 37.008 7.808 37.032 ;
     RECT  6.829 38.016 7.808 39.048 ;
     RECT  6.853 41.04 7.808 41.64 ;
     RECT  6.901 42.768 7.808 43.368 ;
     RECT  7.052 45.552 7.808 45.576 ;
     RECT  7.093 47.28 7.808 47.304 ;
     RECT  6.901 48.624 7.808 49.032 ;
     RECT  5.825 51.072 7.808 51.24 ;
     RECT  4.595 55.152 7.808 55.176 ;
     RECT  6.577 56.688 7.808 56.712 ;
     RECT  7.117 58.56 7.808 58.68 ;
     RECT  7.141 60.576 7.808 61.608 ;
     RECT  6.577 62.64 7.808 62.664 ;
     RECT  6.613 63.648 7.808 64.248 ;
     RECT  6.613 67.248 7.808 67.8 ;
     RECT  5.795 71.52 7.808 71.784 ;
     RECT  7.1 75.552 7.808 75.576 ;
     RECT  6.829 77.136 7.808 77.208 ;
     RECT  6.041 79.152 7.808 79.224 ;
     RECT  6.083 86.064 7.808 86.088 ;
     RECT  6.275 87.168 7.808 87.192 ;
     RECT  5.651 90.384 7.808 90.408 ;
     RECT  5.653 95.76 7.808 95.784 ;
     RECT  7.1 98.256 7.808 98.28 ;
     RECT  6.041 99.888 7.808 99.912 ;
     RECT  6.86 101.28 7.808 101.304 ;
     RECT  5.933 111.024 7.808 111.096 ;
     RECT  6.563 114.96 7.808 114.984 ;
     RECT  4.547 116.208 7.808 116.232 ;
     RECT  7.117 120.192 7.808 120.264 ;
     RECT  6.833 122.256 7.808 122.52 ;
     RECT  4.745 126.24 7.808 126.264 ;
     RECT  6.083 128.352 7.808 128.616 ;
     RECT  6.083 129.648 7.808 129.672 ;
     RECT  6.853 132 7.808 132.216 ;
     RECT  6.614 133.968 7.808 133.992 ;
     RECT  5.645 135.504 7.808 135.528 ;
     RECT  5.825 137.856 7.808 137.928 ;
     RECT  6.041 140.736 7.808 140.76 ;
     RECT  6.037 142.992 7.808 143.016 ;
     RECT  6.901 144.528 7.808 144.552 ;
     RECT  4.097 146.496 7.808 146.52 ;
     RECT  6.505 155.232 7.808 155.256 ;
     RECT  7.237 166.08 7.808 167.928 ;
     RECT  7.397 170.928 7.808 171.576 ;
     RECT  7.808 1.728 8.104 171.576 ;
     RECT  8.104 111.024 8.165 111.048 ;
     RECT  8.104 43.344 8.201 43.368 ;
     RECT  8.104 55.152 8.201 55.176 ;
     RECT  8.104 60.576 8.201 60.696 ;
     RECT  8.104 21.408 8.237 25.656 ;
     RECT  8.104 1.728 8.243 3.432 ;
     RECT  8.104 13.488 8.243 13.512 ;
     RECT  8.104 18.816 8.273 18.84 ;
     RECT  8.104 17.088 8.291 17.112 ;
     RECT  8.104 14.928 8.332 15.096 ;
     RECT  8.237 22.176 8.381 25.656 ;
     RECT  8.201 60.672 8.381 60.696 ;
     RECT  8.104 79.2 8.381 79.224 ;
     RECT  8.104 128.352 8.381 128.616 ;
     RECT  8.104 144.528 8.435 144.744 ;
     RECT  8.104 142.992 8.453 143.064 ;
     RECT  8.435 144.72 8.476 144.744 ;
     RECT  8.381 128.592 8.525 128.616 ;
     RECT  8.104 11.52 8.531 11.544 ;
     RECT  8.381 22.176 8.531 23.352 ;
     RECT  8.332 14.928 8.597 14.952 ;
     RECT  8.453 142.992 8.597 143.016 ;
     RECT  8.104 28.464 8.633 28.824 ;
     RECT  8.531 22.8 8.921 23.352 ;
     RECT  8.381 24.48 8.956 25.656 ;
     RECT  8.243 3.408 8.993 3.432 ;
     RECT  8.243 1.728 9.061 2.28 ;
     RECT  8.104 170.976 9.109 171.576 ;
     RECT  8.104 166.128 9.137 167.592 ;
     RECT  9.061 1.104 9.155 2.28 ;
     RECT  8.956 25.056 9.209 25.656 ;
     RECT  9.109 170.448 9.269 171.576 ;
     RECT  9.155 1.728 9.349 2.28 ;
     RECT  9.137 166.128 9.353 167.016 ;
     RECT  9.269 170.448 9.353 172.152 ;
     RECT  9.133 4.56 9.395 4.584 ;
     RECT  9.349 1.728 9.433 2.904 ;
     RECT  9.353 166.128 9.457 166.488 ;
     RECT  8.104 34.464 9.497 34.728 ;
     RECT  8.104 51.216 9.541 51.24 ;
     RECT  9.457 165.888 9.541 166.488 ;
     RECT  9.493 49.344 9.565 49.368 ;
     RECT  9.541 166.128 9.587 166.488 ;
     RECT  9.565 49.008 9.649 49.368 ;
     RECT  8.104 32.352 9.685 32.376 ;
     RECT  9.685 32.208 9.731 32.376 ;
     RECT  8.921 22.8 9.733 23.064 ;
     RECT  9.649 49.344 9.733 49.368 ;
     RECT  9.541 50.688 9.733 51.24 ;
     RECT  9.733 49.344 9.749 51.24 ;
     RECT  9.589 20.496 9.821 20.52 ;
     RECT  9.685 34.224 9.821 34.248 ;
     RECT  9.749 50.16 10.037 51.24 ;
     RECT  8.633 28.8 10.069 28.824 ;
     RECT  9.209 25.056 10.109 25.08 ;
     RECT  9.353 170.448 10.109 171.624 ;
     RECT  9.433 2.88 10.115 2.904 ;
     RECT  10.028 26.448 10.115 26.472 ;
     RECT  10.069 28.8 10.115 29.064 ;
     RECT  9.733 22.128 10.181 23.064 ;
     RECT  9.493 168.096 10.321 168.12 ;
     RECT  10.037 50.688 10.357 51.24 ;
     RECT  10.109 170.976 10.357 171.624 ;
     RECT  9.493 172.704 10.357 172.728 ;
     RECT  8.104 5.664 10.361 6.024 ;
     RECT  10.357 50.688 10.361 51.288 ;
     RECT  10.321 167.568 10.405 168.12 ;
     RECT  10.405 167.952 10.429 168.12 ;
     RECT  10.361 50.736 10.453 51.288 ;
     RECT  10.181 22.128 10.547 22.776 ;
     RECT  10.361 5.712 10.549 6.024 ;
     RECT  10.508 20.736 10.595 20.76 ;
     RECT  10.537 19.392 10.621 19.416 ;
     RECT  9.433 1.728 10.645 1.848 ;
     RECT  10.453 50.736 10.765 51.864 ;
     RECT  10.115 29.04 10.789 29.064 ;
     RECT  10.429 167.952 10.801 168.168 ;
     RECT  10.357 170.976 10.883 172.728 ;
     RECT  10.837 3.408 10.892 3.432 ;
     RECT  10.765 51.168 10.901 51.864 ;
     RECT  10.645 1.728 10.933 1.896 ;
     RECT  10.789 29.04 10.933 29.64 ;
     RECT  10.933 1.728 11.027 2.28 ;
     RECT  9.587 166.128 11.041 166.152 ;
     RECT  10.883 172.704 11.045 172.728 ;
     RECT  10.901 51.216 11.077 51.864 ;
     RECT  11.041 168.72 11.125 168.744 ;
     RECT  10.892 3.408 11.185 3.864 ;
     RECT  10.883 170.976 11.257 171.576 ;
     RECT  10.933 29.04 11.297 29.976 ;
     RECT  10.547 22.752 11.305 22.776 ;
     RECT  11.185 3.408 11.363 4.584 ;
     RECT  11.363 3.408 11.365 3.432 ;
     RECT  11.363 4.56 11.411 4.584 ;
     RECT  10.549 5.712 11.581 6.264 ;
     RECT  11.041 166.128 11.581 166.344 ;
     RECT  11.365 2.832 11.621 3.432 ;
     RECT  11.581 166.128 11.621 166.68 ;
     RECT  11.557 169.824 11.725 169.848 ;
     RECT  11.257 170.88 11.725 171.576 ;
     RECT  11.581 5.712 11.795 6.312 ;
     RECT  11.725 169.824 11.837 171.576 ;
     RECT  11.795 5.712 11.845 6.264 ;
     RECT  11.833 23.376 11.917 23.4 ;
     RECT  11.845 5.088 12.017 6.264 ;
     RECT  11.077 51.216 12.017 52.104 ;
     RECT  11.621 2.832 12.131 3.24 ;
     RECT  12.017 5.712 12.133 6.264 ;
     RECT  11.869 0.096 12.179 0.12 ;
     RECT  11.621 166.32 12.265 166.68 ;
     RECT  11.837 170.4 12.485 171.576 ;
     RECT  12.509 172.128 12.593 172.152 ;
     RECT  11.027 1.728 12.668 1.848 ;
     RECT  12.553 4.656 12.769 4.68 ;
     RECT  12.445 34.608 12.769 34.632 ;
     RECT  12.769 34.608 12.877 34.824 ;
     RECT  12.877 34.608 13.093 35.688 ;
     RECT  12.265 166.32 13.093 167.592 ;
     RECT  12.485 170.4 13.093 171 ;
     RECT  13.093 166.32 13.129 167.688 ;
     RECT  13.129 166.32 13.165 168.648 ;
     RECT  12.668 1.728 13.208 2.28 ;
     RECT  12.769 3.84 13.208 4.68 ;
     RECT  12.133 5.808 13.208 6.264 ;
     RECT  12.373 24.528 13.208 24.552 ;
     RECT  11.297 29.952 13.208 29.976 ;
     RECT  12.188 30.96 13.208 30.984 ;
     RECT  9.731 32.208 13.208 32.232 ;
     RECT  13.093 33.6 13.208 33.624 ;
     RECT  13.093 34.608 13.208 35.832 ;
     RECT  8.104 38.4 13.208 39.048 ;
     RECT  12.017 51.216 13.208 51.24 ;
     RECT  8.104 129.648 13.208 129.672 ;
     RECT  13.165 166.32 13.208 168.84 ;
     RECT  13.093 170.208 13.208 171 ;
     RECT  13.208 1.728 13.504 171 ;
     RECT  13.504 1.728 13.597 5.832 ;
     RECT  13.429 172.608 13.619 172.632 ;
     RECT  13.504 31.2 13.715 31.944 ;
     RECT  13.504 34.032 13.745 34.776 ;
     RECT  13.504 166.656 13.745 168.936 ;
     RECT  13.715 31.872 13.756 31.944 ;
     RECT  13.504 170.448 13.777 171 ;
     RECT  13.745 166.656 13.781 168.744 ;
     RECT  13.597 1.104 13.859 5.832 ;
     RECT  13.756 31.872 14.069 31.896 ;
     RECT  13.745 34.032 14.133 34.056 ;
     RECT  13.504 35.808 14.243 35.88 ;
     RECT  13.859 1.728 14.321 5.832 ;
     RECT  13.504 37.584 14.429 39.048 ;
     RECT  14.321 3.744 14.501 5.832 ;
     RECT  13.781 167.76 14.609 168.744 ;
     RECT  14.429 38.16 14.627 39.048 ;
     RECT  14.569 29.664 14.653 29.688 ;
     RECT  14.321 1.728 14.933 2.76 ;
     RECT  13.777 170.448 14.933 171.576 ;
     RECT  14.501 4.368 15.001 5.832 ;
     RECT  14.965 33.072 15.059 33.096 ;
     RECT  15.001 4.368 15.085 6.264 ;
     RECT  15.085 4.368 15.395 5.832 ;
     RECT  14.933 1.728 15.401 1.896 ;
     RECT  15.395 4.368 15.545 5.544 ;
     RECT  14.609 168.096 15.545 168.552 ;
     RECT  14.933 170.976 15.685 171.576 ;
     RECT  14.243 35.856 15.731 35.88 ;
     RECT  15.685 36.864 15.772 36.888 ;
     RECT  14.627 38.208 15.781 39.048 ;
     RECT  15.781 38.208 15.788 39.288 ;
     RECT  15.685 170.976 15.797 171.624 ;
     RECT  15.788 38.16 15.875 39.288 ;
     RECT  15.545 4.368 15.905 4.776 ;
     RECT  15.797 170.976 15.923 171.048 ;
     RECT  15.865 40.464 15.971 40.488 ;
     RECT  15.545 168.096 16.013 168.12 ;
     RECT  15.901 2.832 16.333 2.856 ;
     RECT  16.253 172.128 16.337 172.152 ;
     RECT  13.781 166.656 16.453 166.68 ;
     RECT  16.333 2.832 16.501 2.904 ;
     RECT  15.905 4.56 16.693 4.776 ;
     RECT  15.865 43.248 16.697 43.272 ;
     RECT  15.923 170.976 16.789 171 ;
     RECT  15.401 1.728 16.801 1.8 ;
     RECT  16.501 2.832 16.801 3.24 ;
     RECT  16.801 1.728 16.835 3.24 ;
     RECT  16.693 4.56 16.873 5.016 ;
     RECT  16.453 166.656 16.945 166.824 ;
     RECT  16.801 168.72 16.985 168.744 ;
     RECT  15.875 38.496 17.029 39.288 ;
     RECT  16.789 170.448 17.057 171 ;
     RECT  17.029 38.496 17.075 40.2 ;
     RECT  16.945 166.656 17.093 167.256 ;
     RECT  17.075 40.176 17.116 40.2 ;
     RECT  17.057 170.976 17.173 171 ;
     RECT  17.132 43.2 17.345 43.224 ;
     RECT  17.093 166.656 17.345 167.016 ;
     RECT  16.873 4.56 17.413 5.208 ;
     RECT  17.173 170.976 17.449 171.576 ;
     RECT  17.449 170.976 17.987 172.152 ;
     RECT  17.987 172.128 17.993 172.152 ;
     RECT  17.989 168.144 18.061 168.168 ;
     RECT  17.948 40.416 18.085 40.44 ;
     RECT  16.693 41.616 18.085 41.64 ;
     RECT  17.075 38.496 18.161 38.52 ;
     RECT  16.835 1.728 18.181 2.28 ;
     RECT  17.413 3.84 18.181 5.208 ;
     RECT  18.181 1.728 18.341 5.208 ;
     RECT  18.373 45.936 18.421 45.96 ;
     RECT  18.332 47.088 18.421 47.112 ;
     RECT  13.504 51.216 18.421 51.24 ;
     RECT  18.025 53.04 18.421 53.064 ;
     RECT  18.061 168.144 18.421 168.744 ;
     RECT  18.341 1.728 18.469 5.736 ;
     RECT  18.421 51.216 18.469 53.064 ;
     RECT  17.345 166.656 18.469 166.68 ;
     RECT  18.421 168.144 18.469 169.128 ;
     RECT  18.469 48.96 18.565 48.984 ;
     RECT  18.469 1.728 18.608 5.784 ;
     RECT  18.161 38.208 18.608 38.52 ;
     RECT  18.085 40.416 18.608 41.64 ;
     RECT  18.349 44.832 18.608 44.856 ;
     RECT  18.421 45.936 18.608 47.112 ;
     RECT  18.565 48.192 18.608 48.984 ;
     RECT  18.469 50.592 18.608 53.064 ;
     RECT  13.504 129.648 18.608 129.672 ;
     RECT  18.469 166.656 18.608 169.128 ;
     RECT  17.987 170.976 18.608 171 ;
     RECT  18.421 172.608 18.707 172.632 ;
     RECT  18.608 1.728 18.904 171 ;
     RECT  18.904 48.192 18.929 48.216 ;
     RECT  18.904 49.68 19.001 50.088 ;
     RECT  18.904 166.656 19.139 168.408 ;
     RECT  18.904 45.696 19.217 46.584 ;
     RECT  18.904 1.728 19.288 6.216 ;
     RECT  18.904 170.976 19.421 171 ;
     RECT  19.288 1.68 19.475 6.216 ;
     RECT  19.139 166.656 19.541 168.12 ;
     RECT  19.421 170.976 19.645 171.576 ;
     RECT  19.645 170.976 19.757 171.624 ;
     RECT  19.475 1.728 19.801 6.216 ;
     RECT  18.904 41.472 19.829 41.496 ;
     RECT  19.801 3.408 19.957 6.216 ;
     RECT  19.801 1.728 20.003 2.28 ;
     RECT  19.217 46.56 20.005 46.584 ;
     RECT  18.904 43.92 20.017 44.616 ;
     RECT  19.897 47.904 20.041 48.456 ;
     RECT  19.001 49.68 20.041 49.704 ;
     RECT  18.904 51.168 20.041 51.24 ;
     RECT  19.957 3.408 20.045 6.264 ;
     RECT  20.041 47.904 20.051 51.24 ;
     RECT  20.005 46.56 20.081 46.68 ;
     RECT  20.051 48.432 20.081 51.24 ;
     RECT  20.081 46.656 20.092 46.68 ;
     RECT  20.081 48.96 20.147 51.24 ;
     RECT  20.017 44.592 20.149 44.616 ;
     RECT  18.904 52.272 20.195 52.296 ;
     RECT  20.149 53.856 20.221 53.88 ;
     RECT  19.541 166.656 20.221 166.68 ;
     RECT  20.221 53.568 20.236 53.88 ;
     RECT  20.221 47.328 20.305 47.352 ;
     RECT  20.149 44.592 20.513 45.048 ;
     RECT  18.904 38.496 20.531 38.52 ;
     RECT  20.513 44.592 20.531 44.808 ;
     RECT  20.236 53.568 20.531 53.592 ;
     RECT  19.757 171.552 20.533 171.624 ;
     RECT  20.147 50.976 20.621 51.24 ;
     RECT  20.341 170.448 20.657 170.472 ;
     RECT  20.221 166.416 20.725 166.68 ;
     RECT  18.904 129.648 20.761 129.672 ;
     RECT  20.045 4.512 20.801 6.264 ;
     RECT  20.533 171.552 20.837 172.152 ;
     RECT  20.473 41.424 20.873 41.448 ;
     RECT  20.837 171.552 20.917 171.576 ;
     RECT  20.725 166.416 20.933 167.016 ;
     RECT  20.003 1.728 21.011 2.232 ;
     RECT  20.933 166.416 21.011 167.064 ;
     RECT  20.917 170.976 21.017 171.576 ;
     RECT  20.045 3.408 21.061 3.48 ;
     RECT  20.801 4.512 21.061 5.736 ;
     RECT  21.061 3.408 21.107 5.736 ;
     RECT  20.941 51.264 21.107 51.288 ;
     RECT  20.761 129.36 21.125 129.672 ;
     RECT  19.541 168.096 21.125 168.12 ;
     RECT  20.617 54.672 21.251 54.696 ;
     RECT  21.164 56.208 21.251 56.232 ;
     RECT  21.205 57.84 21.301 57.864 ;
     RECT  21.011 166.656 21.301 167.064 ;
     RECT  21.107 3.408 21.341 5.16 ;
     RECT  21.301 57.84 21.341 58.152 ;
     RECT  21.341 3.744 21.413 5.16 ;
     RECT  21.301 172.704 21.449 172.728 ;
     RECT  21.413 4.512 21.521 5.16 ;
     RECT  21.265 169.872 21.539 169.896 ;
     RECT  21.341 58.128 21.661 58.152 ;
     RECT  21.661 58.128 21.701 58.68 ;
     RECT  21.701 58.656 21.779 58.68 ;
     RECT  21.685 170.4 22.025 170.424 ;
     RECT  21.017 171.552 22.069 171.576 ;
     RECT  21.521 5.136 22.313 5.16 ;
     RECT  22.165 168.768 22.421 168.792 ;
     RECT  21.373 55.968 22.457 55.992 ;
     RECT  21.301 166.656 22.493 167.592 ;
     RECT  21.061 53.52 22.529 53.544 ;
     RECT  21.011 1.728 22.556 1.8 ;
     RECT  22.556 1.728 22.643 2.28 ;
     RECT  20.531 44.592 22.813 44.616 ;
     RECT  22.813 44.592 22.853 44.712 ;
     RECT  21.733 60.96 22.853 60.984 ;
     RECT  22.493 167.04 22.997 167.592 ;
     RECT  22.741 0.096 23.411 0.12 ;
     RECT  22.997 167.232 23.461 167.592 ;
     RECT  23.137 168.72 23.461 168.744 ;
     RECT  22.643 1.728 23.713 1.752 ;
     RECT  23.713 1.728 24.008 1.8 ;
     RECT  24.001 3.84 24.008 3.864 ;
     RECT  22.853 44.688 24.008 44.712 ;
     RECT  23.209 52.416 24.008 52.44 ;
     RECT  23.461 54.096 24.008 54.12 ;
     RECT  23.245 59.808 24.008 59.832 ;
     RECT  21.125 129.36 24.008 129.384 ;
     RECT  23.461 167.232 24.008 168.744 ;
     RECT  23.749 169.824 24.008 169.848 ;
     RECT  22.069 170.976 24.008 171.576 ;
     RECT  24.008 1.728 24.304 171.576 ;
     RECT  24.304 60.096 24.419 60.12 ;
     RECT  24.277 172.704 24.419 172.728 ;
     RECT  24.304 168.912 24.473 171.576 ;
     RECT  24.304 1.728 24.515 2.28 ;
     RECT  24.473 168.912 24.517 171 ;
     RECT  24.304 166.992 24.581 167.016 ;
     RECT  24.517 168.912 24.611 168.936 ;
     RECT  24.517 169.968 24.611 171 ;
     RECT  24.304 3.408 24.905 4.68 ;
     RECT  24.515 1.728 24.913 1.848 ;
     RECT  24.304 61.344 25.373 61.368 ;
     RECT  25.297 168.72 25.481 168.744 ;
     RECT  25.333 167.568 25.549 167.592 ;
     RECT  24.913 1.728 25.705 1.8 ;
     RECT  24.905 3.408 25.945 3.432 ;
     RECT  24.905 4.656 25.945 4.68 ;
     RECT  25.945 3.408 25.985 4.68 ;
     RECT  26.005 166.368 26.017 166.392 ;
     RECT  25.621 169.2 26.057 169.272 ;
     RECT  25.705 1.728 26.125 1.752 ;
     RECT  25.513 64.32 26.125 64.344 ;
     RECT  25.549 167.52 26.233 167.592 ;
     RECT  26.057 169.248 26.377 169.272 ;
     RECT  26.125 1.104 26.387 1.752 ;
     RECT  26.377 169.248 26.417 169.368 ;
     RECT  24.304 57.552 26.521 57.576 ;
     RECT  26.017 166.368 26.533 166.44 ;
     RECT  24.304 44.688 26.579 44.712 ;
     RECT  26.521 57.024 26.605 57.576 ;
     RECT  24.611 170.448 26.669 171 ;
     RECT  26.533 166.368 26.737 166.488 ;
     RECT  26.669 170.448 26.771 170.472 ;
     RECT  25.621 63.12 26.773 63.144 ;
     RECT  24.304 129.36 26.773 129.384 ;
     RECT  26.693 61.776 26.777 61.8 ;
     RECT  26.773 129.216 26.813 129.384 ;
     RECT  26.125 64.32 26.821 64.824 ;
     RECT  26.387 1.728 26.845 1.752 ;
     RECT  26.821 64.32 26.867 65.64 ;
     RECT  26.417 169.296 26.867 169.368 ;
     RECT  26.773 63.12 26.885 63.24 ;
     RECT  26.867 64.32 26.885 64.392 ;
     RECT  26.845 66.672 26.957 66.696 ;
     RECT  26.867 65.616 27.029 65.64 ;
     RECT  25.985 3.696 27.065 4.68 ;
     RECT  26.737 165.888 27.173 166.488 ;
     RECT  26.917 172.128 27.209 172.152 ;
     RECT  27.173 166.416 27.301 166.488 ;
     RECT  26.233 167.472 27.301 167.592 ;
     RECT  26.845 1.728 27.353 2.28 ;
     RECT  27.301 166.416 27.452 167.592 ;
     RECT  27.445 75.552 27.532 75.576 ;
     RECT  27.452 166.416 27.539 167.64 ;
     RECT  27.539 166.416 27.569 167.304 ;
     RECT  27.5 78.048 27.587 78.072 ;
     RECT  27.569 166.416 27.641 167.064 ;
     RECT  26.867 169.296 27.731 169.32 ;
     RECT  27.493 170.4 27.781 170.424 ;
     RECT  26.885 63.216 27.785 63.24 ;
     RECT  27.393 76.896 27.925 76.92 ;
     RECT  26.533 43.008 28.165 43.032 ;
     RECT  27.641 166.416 28.172 167.016 ;
     RECT  27.877 3.408 28.181 3.432 ;
     RECT  26.885 64.32 28.211 64.344 ;
     RECT  27.065 4.656 28.22 4.68 ;
     RECT  28.172 165.696 28.259 167.016 ;
     RECT  27.925 76.32 28.289 76.92 ;
     RECT  27.353 1.728 28.357 1.752 ;
     RECT  27.781 170.4 28.433 171 ;
     RECT  27.997 69.984 28.453 70.968 ;
     RECT  28.549 86.592 28.741 86.616 ;
     RECT  28.289 76.32 28.897 76.392 ;
     RECT  28.22 4.656 28.997 5.64 ;
     RECT  28.249 64.416 29.005 64.44 ;
     RECT  28.861 168.72 29.077 168.744 ;
     RECT  28.259 166.464 29.221 167.016 ;
     RECT  29.077 168.72 29.221 169.272 ;
     RECT  28.165 43.008 29.257 43.32 ;
     RECT  28.321 68.352 29.269 68.376 ;
     RECT  28.357 1.728 29.408 2.328 ;
     RECT  28.997 4.512 29.408 5.64 ;
     RECT  29.257 42.192 29.408 43.32 ;
     RECT  26.605 57.552 29.408 57.576 ;
     RECT  29.005 64.416 29.408 65.016 ;
     RECT  28.249 66.624 29.408 66.648 ;
     RECT  29.269 67.776 29.408 68.376 ;
     RECT  28.453 69.456 29.408 70.968 ;
     RECT  28.453 72.384 29.408 72.408 ;
     RECT  28.897 76.224 29.408 76.392 ;
     RECT  27.457 79.44 29.408 79.464 ;
     RECT  28.741 86.304 29.408 86.616 ;
     RECT  28.537 117.984 29.408 118.008 ;
     RECT  26.813 129.216 29.408 129.24 ;
     RECT  29.221 166.464 29.408 169.272 ;
     RECT  28.433 170.448 29.408 171 ;
     RECT  29.269 172.704 29.545 172.728 ;
     RECT  29.545 172.128 29.629 172.728 ;
     RECT  29.408 1.728 29.704 171 ;
     RECT  29.629 172.704 29.837 172.728 ;
     RECT  29.704 166.224 29.909 169.272 ;
     RECT  29.704 128.832 29.939 129.24 ;
     RECT  29.704 170.928 29.977 171 ;
     RECT  29.704 70.08 30.017 70.104 ;
     RECT  29.939 128.832 30.131 128.856 ;
     RECT  29.977 170.928 30.131 171.048 ;
     RECT  29.704 118.512 30.169 118.536 ;
     RECT  29.704 4.512 30.269 5.208 ;
     RECT  30.269 4.656 30.305 5.208 ;
     RECT  29.909 168.144 30.557 169.272 ;
     RECT  29.909 166.224 30.701 166.968 ;
     RECT  29.704 1.728 30.707 1.896 ;
     RECT  30.557 168.144 30.737 168.168 ;
     RECT  29.704 72.912 30.745 72.936 ;
     RECT  30.305 5.04 30.881 5.208 ;
     RECT  30.131 170.928 31.013 171 ;
     RECT  31.013 170.88 31.097 171 ;
     RECT  29.704 76.224 31.235 76.248 ;
     RECT  31.409 172.128 31.493 172.152 ;
     RECT  29.704 86.304 31.525 86.328 ;
     RECT  31.525 168.24 31.597 168.264 ;
     RECT  30.557 169.248 31.597 169.272 ;
     RECT  30.701 166.32 31.621 166.968 ;
     RECT  31.525 86.112 31.673 86.328 ;
     RECT  31.597 168.24 31.817 169.272 ;
     RECT  30.881 5.184 31.849 5.208 ;
     RECT  31.673 86.16 31.859 86.328 ;
     RECT  31.849 5.184 31.861 5.736 ;
     RECT  31.859 86.16 31.897 86.184 ;
     RECT  31.849 72.96 31.921 72.984 ;
     RECT  31.817 168.24 31.925 169.128 ;
     RECT  31.921 72.96 31.933 73.56 ;
     RECT  30.707 1.728 31.957 1.848 ;
     RECT  31.861 4.512 31.957 5.736 ;
     RECT  31.621 166.32 31.957 167.016 ;
     RECT  31.933 73.536 32.005 73.56 ;
     RECT  31.957 1.728 32.108 2.328 ;
     RECT  31.097 170.976 32.137 171 ;
     RECT  32.108 1.728 32.195 2.856 ;
     RECT  30.841 81.888 32.281 81.912 ;
     RECT  32.281 81.888 32.365 82.68 ;
     RECT  32.137 170.976 32.387 171.048 ;
     RECT  31.957 4.512 32.533 5.928 ;
     RECT  32.387 170.976 32.533 171 ;
     RECT  31.189 79.68 32.573 79.704 ;
     RECT  32.533 4.032 32.605 5.928 ;
     RECT  32.365 81.888 32.609 81.912 ;
     RECT  32.533 170.4 32.717 171 ;
     RECT  31.957 165.84 32.789 167.016 ;
     RECT  31.925 168.24 32.789 168.264 ;
     RECT  32.605 3.936 32.825 5.928 ;
     RECT  32.461 78.624 32.969 78.648 ;
     RECT  32.789 166.416 33.109 167.016 ;
     RECT  33.164 84.288 33.251 84.312 ;
     RECT  29.704 132.336 33.365 132.36 ;
     RECT  32.717 170.448 33.365 171 ;
     RECT  33.205 85.344 33.437 85.368 ;
     RECT  32.825 3.936 33.493 5.88 ;
     RECT  33.365 170.448 33.539 170.472 ;
     RECT  32.965 86.448 33.548 86.472 ;
     RECT  33.548 86.448 33.577 86.664 ;
     RECT  32.195 1.728 33.589 2.28 ;
     RECT  33.493 3.312 33.589 5.88 ;
     RECT  33.541 74.112 33.625 74.136 ;
     RECT  33.589 1.728 33.653 5.88 ;
     RECT  33.653 1.728 33.761 3.96 ;
     RECT  33.761 3.936 33.833 3.96 ;
     RECT  33.109 166.416 33.877 167.4 ;
     RECT  33.829 168.672 33.877 168.696 ;
     RECT  33.577 86.448 33.901 86.952 ;
     RECT  33.653 5.184 33.932 5.88 ;
     RECT  33.836 79.632 33.973 79.656 ;
     RECT  33.901 80.688 33.973 80.712 ;
     RECT  33.877 166.416 34.021 168.696 ;
     RECT  34.021 166.416 34.261 168.936 ;
     RECT  34.181 171.552 34.405 171.576 ;
     RECT  34.261 165.936 34.513 168.936 ;
     RECT  33.932 5.184 34.693 5.928 ;
     RECT  34.405 170.976 34.733 171.576 ;
     RECT  33.761 1.728 34.808 2.904 ;
     RECT  34.693 4.992 34.808 5.928 ;
     RECT  31.525 8.976 34.808 9 ;
     RECT  33.973 79.632 34.808 80.712 ;
     RECT  33.205 83.232 34.808 83.256 ;
     RECT  33.901 86.448 34.808 87.576 ;
     RECT  34.513 165.888 34.808 168.936 ;
     RECT  34.733 170.976 34.808 171 ;
     RECT  34.789 172.128 34.981 172.152 ;
     RECT  34.981 172.128 35.021 172.632 ;
     RECT  34.808 1.728 35.104 171 ;
     RECT  35.104 132.48 35.219 132.888 ;
     RECT  35.104 134.256 35.219 135.048 ;
     RECT  35.104 1.728 35.245 2.856 ;
     RECT  35.104 3.984 35.245 5.736 ;
     RECT  35.021 172.608 35.267 172.632 ;
     RECT  35.104 169.152 35.308 169.176 ;
     RECT  35.104 170.4 35.315 171 ;
     RECT  35.104 86.352 35.381 87.384 ;
     RECT  35.104 138.288 35.411 141.96 ;
     RECT  35.104 90 35.507 90.792 ;
     RECT  35.411 138.96 35.561 141.96 ;
     RECT  35.104 131.088 35.633 131.112 ;
     RECT  35.561 138.96 35.705 141.24 ;
     RECT  35.245 3.984 35.843 5.16 ;
     RECT  35.219 132.48 35.843 132.504 ;
     RECT  35.245 1.728 35.849 2.28 ;
     RECT  35.219 135.024 35.891 135.048 ;
     RECT  35.104 137.184 35.891 137.208 ;
     RECT  35.315 170.976 35.893 171 ;
     RECT  35.843 4.032 35.929 5.16 ;
     RECT  35.849 1.728 35.932 2.184 ;
     RECT  35.104 136.128 35.957 136.152 ;
     RECT  35.381 86.352 36.035 86.76 ;
     RECT  35.507 90.768 36.065 90.792 ;
     RECT  35.705 140.064 36.065 141.24 ;
     RECT  35.893 170.976 36.101 171.576 ;
     RECT  35.932 1.728 36.131 2.088 ;
     RECT  36.035 86.592 36.173 86.76 ;
     RECT  35.104 165.888 36.173 168.168 ;
     RECT  36.236 115.584 36.277 115.608 ;
     RECT  36.236 116.928 36.277 116.952 ;
     RECT  36.205 118.032 36.277 118.056 ;
     RECT  36.133 113.04 36.323 113.064 ;
     RECT  36.205 114.144 36.323 114.168 ;
     RECT  36.277 115.584 36.323 118.056 ;
     RECT  36.085 172.704 36.353 172.728 ;
     RECT  35.104 129.888 36.385 129.912 ;
     RECT  36.101 170.976 36.457 171 ;
     RECT  36.277 110.496 36.469 110.52 ;
     RECT  36.313 107.712 36.493 107.736 ;
     RECT  36.469 110.496 36.515 111.048 ;
     RECT  36.385 101.28 36.517 101.304 ;
     RECT  36.493 107.712 36.533 108.12 ;
     RECT  36.449 136.224 36.533 136.248 ;
     RECT  36.065 140.976 36.533 141.24 ;
     RECT  36.313 98.736 36.563 99.192 ;
     RECT  36.517 101.28 36.563 101.88 ;
     RECT  36.205 106.032 36.569 106.056 ;
     RECT  35.104 145.296 36.569 146.472 ;
     RECT  36.517 100.224 36.605 100.248 ;
     RECT  36.457 170.112 36.637 171 ;
     RECT  36.569 145.296 36.641 145.32 ;
     RECT  35.705 138.96 36.668 138.984 ;
     RECT  36.563 101.856 36.677 101.88 ;
     RECT  36.469 135.072 36.677 135.096 ;
     RECT  36.569 146.448 36.677 146.472 ;
     RECT  36.637 169.152 36.677 171 ;
     RECT  36.385 95.712 36.709 95.736 ;
     RECT  36.668 138.96 36.709 139.656 ;
     RECT  36.677 169.152 36.721 170.136 ;
     RECT  36.313 103.2 36.745 103.752 ;
     RECT  36.323 116.4 36.749 116.424 ;
     RECT  36.241 120.288 36.753 120.312 ;
     RECT  36.277 121.44 36.753 121.464 ;
     RECT  36.173 86.736 36.755 86.76 ;
     RECT  36.709 138.528 36.755 139.656 ;
     RECT  36.721 169.248 36.785 170.136 ;
     RECT  35.929 4.032 36.853 4.92 ;
     RECT  36.449 109.392 36.857 109.416 ;
     RECT  36.709 95.568 36.929 95.736 ;
     RECT  36.385 129.888 36.929 130.008 ;
     RECT  36.755 138.528 36.929 138.552 ;
     RECT  36.853 3.984 36.956 4.92 ;
     RECT  36.956 3.216 37.043 4.92 ;
     RECT  36.956 105.84 37.043 105.864 ;
     RECT  36.753 120.288 37.043 121.464 ;
     RECT  36.205 123.072 37.045 123.096 ;
     RECT  36.205 124.8 37.045 124.824 ;
     RECT  35.104 126.336 37.045 126.36 ;
     RECT  37.043 3.408 37.105 4.92 ;
     RECT  37.045 124.8 37.109 126.36 ;
     RECT  36.709 141.936 37.109 141.96 ;
     RECT  36.563 98.736 37.141 98.76 ;
     RECT  36.277 128.832 37.141 128.856 ;
     RECT  36.853 91.776 37.145 91.8 ;
     RECT  37.109 124.8 37.145 125.448 ;
     RECT  36.131 1.728 37.177 1.8 ;
     RECT  37.141 128.256 37.181 128.856 ;
     RECT  37.141 98.496 37.187 98.76 ;
     RECT  37.045 123.072 37.217 123.72 ;
     RECT  37.145 124.8 37.217 124.824 ;
     RECT  37.141 99.84 37.225 99.864 ;
     RECT  36.601 131.088 37.237 131.112 ;
     RECT  37.043 121.44 37.253 121.464 ;
     RECT  37.177 1.728 37.261 2.28 ;
     RECT  36.929 129.984 37.283 130.008 ;
     RECT  37.237 130.992 37.283 131.112 ;
     RECT  36.493 93.504 37.285 93.528 ;
     RECT  36.929 95.568 37.285 95.592 ;
     RECT  37.213 84.384 37.297 84.408 ;
     RECT  37.213 168.096 37.297 168.12 ;
     RECT  36.323 117.792 37.325 117.816 ;
     RECT  37.283 130.992 37.325 131.016 ;
     RECT  37.105 3.408 37.427 5.736 ;
     RECT  37.285 93.504 37.433 95.592 ;
     RECT  36.745 103.2 37.433 104.088 ;
     RECT  37.427 3.408 37.469 5.16 ;
     RECT  37.069 97.392 37.523 97.416 ;
     RECT  37.429 171.552 37.541 171.576 ;
     RECT  37.043 120.288 37.573 120.312 ;
     RECT  37.187 98.496 37.577 98.52 ;
     RECT  37.469 4.8 37.613 5.16 ;
     RECT  37.217 123.072 37.613 123.096 ;
     RECT  37.573 119.664 37.619 120.312 ;
     RECT  37.433 93.504 37.649 94.68 ;
     RECT  36.785 169.248 37.649 169.272 ;
     RECT  37.181 128.256 37.667 128.28 ;
     RECT  37.357 168.144 37.681 168.168 ;
     RECT  37.619 119.664 37.685 119.688 ;
     RECT  37.649 94.656 37.721 94.68 ;
     RECT  37.649 93.504 37.757 93.528 ;
     RECT  37.069 113.856 37.765 113.88 ;
     RECT  37.765 113.856 37.789 114.264 ;
     RECT  37.789 113.856 37.811 114.552 ;
     RECT  36.533 108.096 37.813 108.12 ;
     RECT  37.745 112.848 37.829 112.872 ;
     RECT  37.811 114.24 37.852 114.552 ;
     RECT  37.813 107.136 37.859 108.12 ;
     RECT  37.772 115.824 37.859 115.848 ;
     RECT  37.583 117.216 37.859 117.24 ;
     RECT  37.609 105.36 37.865 105.384 ;
     RECT  36.515 111.024 37.865 111.048 ;
     RECT  37.852 114.528 37.873 114.552 ;
     RECT  37.859 107.136 37.9 107.16 ;
     RECT  37.321 84.96 37.955 84.984 ;
     RECT  37.433 103.2 38.045 103.224 ;
     RECT  37.765 170.976 38.117 171 ;
     RECT  37.613 4.896 38.401 5.16 ;
     RECT  37.897 6.24 38.401 6.264 ;
     RECT  37.681 168.144 38.513 168.216 ;
     RECT  37.261 1.728 38.533 1.8 ;
     RECT  36.173 165.888 38.545 167.064 ;
     RECT  38.513 168.144 38.545 168.168 ;
     RECT  37.469 3.408 38.581 3.432 ;
     RECT  38.401 4.896 38.581 6.264 ;
     RECT  38.684 92.928 38.771 92.952 ;
     RECT  38.684 170.448 38.771 170.472 ;
     RECT  38.897 171.552 38.981 171.576 ;
     RECT  38.533 1.728 39.109 1.848 ;
     RECT  38.581 3.408 39.233 6.264 ;
     RECT  39.301 93.936 39.445 93.96 ;
     RECT  39.109 1.728 39.593 2.232 ;
     RECT  38.545 165.888 39.661 168.168 ;
     RECT  39.593 1.776 39.697 2.232 ;
     RECT  39.661 165.84 39.769 168.168 ;
     RECT  39.445 93.504 39.781 93.96 ;
     RECT  39.697 1.776 39.973 2.28 ;
     RECT  39.233 3.408 39.973 5.928 ;
     RECT  39.925 172.608 39.973 172.632 ;
     RECT  39.973 172.368 40.021 172.632 ;
     RECT  40.021 172.368 40.163 172.68 ;
     RECT  39.973 1.776 40.208 5.928 ;
     RECT  35.104 8.976 40.208 9 ;
     RECT  39.781 93.504 40.208 94.488 ;
     RECT  40.049 96.288 40.208 96.312 ;
     RECT  39.769 165.84 40.208 168.744 ;
     RECT  40.163 172.464 40.259 172.632 ;
     RECT  40.259 172.608 40.451 172.632 ;
     RECT  40.208 1.776 40.504 170.652 ;
     RECT  40.504 1.776 40.597 2.04 ;
     RECT  40.597 1.728 40.601 2.04 ;
     RECT  40.504 96.864 40.643 97.032 ;
     RECT  40.504 3.216 40.673 6.216 ;
     RECT  40.504 170.4 40.745 170.652 ;
     RECT  40.504 166.224 40.781 167.208 ;
     RECT  40.673 3.216 40.787 3.768 ;
     RECT  40.745 170.448 41.027 170.652 ;
     RECT  40.781 166.272 41.033 167.208 ;
     RECT  40.787 3.312 41.219 3.768 ;
     RECT  40.643 96.864 41.219 96.888 ;
     RECT  40.504 168.72 41.257 168.744 ;
     RECT  41.165 170.976 41.345 171 ;
     RECT  41.033 166.416 41.429 167.208 ;
     RECT  40.504 98.64 41.473 98.664 ;
     RECT  41.429 166.512 41.573 167.208 ;
     RECT  41.573 166.512 41.681 167.112 ;
     RECT  41.749 100.32 41.833 100.344 ;
     RECT  41.219 3.744 42.085 3.768 ;
     RECT  41.345 170.976 42.437 171.576 ;
     RECT  42.38 101.424 42.467 101.448 ;
     RECT  41.681 166.512 42.469 167.064 ;
     RECT  42.437 170.976 42.505 171.048 ;
     RECT  42.421 168.144 42.509 168.168 ;
     RECT  42.085 3.744 42.541 4.008 ;
     RECT  42.505 170.4 42.617 171.048 ;
     RECT  42.469 166.272 42.853 167.064 ;
     RECT  40.673 4.992 42.869 6.216 ;
     RECT  40.601 1.728 42.901 1.848 ;
     RECT  42.541 3.168 42.901 4.008 ;
     RECT  42.853 166.272 43.085 167.592 ;
     RECT  42.869 4.992 43.235 5.928 ;
     RECT  43.045 21.12 43.235 21.144 ;
     RECT  43.085 166.272 43.265 167.064 ;
     RECT  42.901 1.728 43.285 4.008 ;
     RECT  43.235 4.992 43.285 5.736 ;
     RECT  43.237 169.056 43.324 169.08 ;
     RECT  42.997 19.968 43.333 19.992 ;
     RECT  43.081 102.288 43.337 102.312 ;
     RECT  43.261 22.224 43.345 22.248 ;
     RECT  43.333 19.392 43.427 19.992 ;
     RECT  43.427 19.968 43.481 19.992 ;
     RECT  42.617 170.928 43.541 171.048 ;
     RECT  43.541 170.928 43.625 171.576 ;
     RECT  43.285 1.728 43.811 5.736 ;
     RECT  43.265 166.272 43.877 167.016 ;
     RECT  43.625 170.928 43.945 171 ;
     RECT  43.811 1.728 44.201 2.904 ;
     RECT  44.201 2.784 44.476 2.904 ;
     RECT  43.801 168.48 44.525 168.504 ;
     RECT  43.945 170.4 44.777 171 ;
     RECT  43.811 3.888 44.845 5.736 ;
     RECT  44.476 2.832 44.917 2.904 ;
     RECT  44.845 3.888 44.917 5.832 ;
     RECT  43.877 166.272 44.917 166.68 ;
     RECT  44.533 167.856 44.917 167.88 ;
     RECT  44.917 2.832 44.965 5.832 ;
     RECT  44.777 170.4 45.253 170.808 ;
     RECT  44.201 1.728 45.529 1.8 ;
     RECT  44.965 2.832 45.529 6.216 ;
     RECT  45.529 1.728 45.608 6.216 ;
     RECT  40.504 8.976 45.608 9 ;
     RECT  44.629 23.952 45.608 23.976 ;
     RECT  44.917 166.272 45.608 167.88 ;
     RECT  44.737 169.248 45.608 169.272 ;
     RECT  45.253 170.352 45.608 170.808 ;
     RECT  45.608 1.728 45.904 170.808 ;
     RECT  45.829 0.144 46.019 0.168 ;
     RECT  45.904 108.816 46.045 108.84 ;
     RECT  45.904 109.968 46.067 109.992 ;
     RECT  45.904 166.416 46.181 168.168 ;
     RECT  45.904 170.064 46.213 170.808 ;
     RECT  45.829 172.128 46.213 172.152 ;
     RECT  45.904 111.12 46.253 111.144 ;
     RECT  46.213 170.064 46.325 172.152 ;
     RECT  46.325 170.064 46.541 170.808 ;
     RECT  45.904 1.728 46.693 2.28 ;
     RECT  46.325 172.128 46.789 172.152 ;
     RECT  46.181 166.416 46.937 167.544 ;
     RECT  46.937 166.416 46.973 166.92 ;
     RECT  45.904 3.984 47.077 4.104 ;
     RECT  47.077 3.792 47.081 4.104 ;
     RECT  47.081 3.792 47.297 4.056 ;
     RECT  46.789 172.128 47.317 172.728 ;
     RECT  47.297 3.792 47.441 3.96 ;
     RECT  47.317 171.552 47.701 172.728 ;
     RECT  47.701 170.976 47.833 172.728 ;
     RECT  47.833 170.352 47.873 172.728 ;
     RECT  47.873 170.352 47.981 170.424 ;
     RECT  47.9 113.952 47.987 113.976 ;
     RECT  47.873 171.552 48.017 172.728 ;
     RECT  46.973 166.656 48.277 166.92 ;
     RECT  48.221 115.68 48.305 115.704 ;
     RECT  48.017 171.552 48.341 172.152 ;
     RECT  46.693 1.728 48.481 1.8 ;
     RECT  48.481 1.728 48.707 2.28 ;
     RECT  47.869 168.144 48.805 168.168 ;
     RECT  47.981 170.4 48.809 170.424 ;
     RECT  48.341 171.552 48.853 171.576 ;
     RECT  45.904 5.088 48.913 5.208 ;
     RECT  48.277 166.656 48.949 167.016 ;
     RECT  48.707 1.728 48.997 1.8 ;
     RECT  48.661 169.248 48.997 169.272 ;
     RECT  48.913 4.944 49.021 5.208 ;
     RECT  49.021 4.944 49.169 5.736 ;
     RECT  48.949 166.416 49.189 167.016 ;
     RECT  48.805 168.144 49.189 168.264 ;
     RECT  49.189 166.416 49.277 168.264 ;
     RECT  48.853 170.976 49.277 171.576 ;
     RECT  49.277 166.416 49.436 168.072 ;
     RECT  49.436 165.84 49.523 168.072 ;
     RECT  48.997 1.152 49.525 1.8 ;
     RECT  49.525 1.104 49.619 1.8 ;
     RECT  47.441 3.936 49.705 3.96 ;
     RECT  49.277 170.976 49.781 171 ;
     RECT  49.765 172.128 50.033 172.152 ;
     RECT  49.619 1.728 50.149 1.8 ;
     RECT  50.149 1.728 50.348 2.088 ;
     RECT  49.705 3.696 50.389 3.96 ;
     RECT  49.169 5.184 50.389 5.736 ;
     RECT  49.523 166.416 50.533 168.072 ;
     RECT  50.341 171.552 50.717 171.576 ;
     RECT  50.533 166.272 50.749 168.072 ;
     RECT  48.997 169.248 50.749 169.32 ;
     RECT  50.605 0.096 50.771 0.12 ;
     RECT  50.149 172.56 51.005 172.728 ;
     RECT  50.348 1.728 51.008 2.712 ;
     RECT  50.389 3.696 51.008 5.736 ;
     RECT  45.904 8.976 51.008 9 ;
     RECT  50.3 122.496 51.008 122.52 ;
     RECT  50.749 166.272 51.008 169.32 ;
     RECT  49.957 170.448 51.008 170.472 ;
     RECT  51.008 1.728 51.185 171 ;
     RECT  51.005 172.56 51.299 172.584 ;
     RECT  51.185 1.728 51.304 170.472 ;
     RECT  51.304 1.728 51.329 2.28 ;
     RECT  51.304 3.408 51.445 3.96 ;
     RECT  51.304 169.296 51.689 169.32 ;
     RECT  52.021 171.552 52.121 171.576 ;
     RECT  51.304 166.416 52.265 167.592 ;
     RECT  52.265 166.416 52.301 167.208 ;
     RECT  51.329 1.728 52.333 1.848 ;
     RECT  52.333 1.728 52.451 2.088 ;
     RECT  51.304 170.448 52.789 170.472 ;
     RECT  52.513 172.128 53.021 172.152 ;
     RECT  52.301 166.464 53.057 167.208 ;
     RECT  51.304 5.184 53.093 5.736 ;
     RECT  51.445 3.936 53.125 3.96 ;
     RECT  53.093 5.184 53.125 5.208 ;
     RECT  52.789 170.448 53.125 171 ;
     RECT  53.125 3.936 53.201 5.208 ;
     RECT  53.057 166.464 53.297 166.92 ;
     RECT  53.297 166.416 53.593 166.92 ;
     RECT  52.451 1.728 53.66 1.8 ;
     RECT  53.201 4.56 53.849 5.208 ;
     RECT  53.125 170.448 53.921 171.576 ;
     RECT  53.921 170.448 54.131 171 ;
     RECT  53.849 5.184 54.273 5.208 ;
     RECT  54.277 172.128 54.533 172.152 ;
     RECT  53.593 166.368 54.997 166.92 ;
     RECT  54.205 6.24 55.001 6.264 ;
     RECT  54.131 170.976 55.177 171 ;
     RECT  54.997 166.368 55.237 167.016 ;
     RECT  55.237 166.368 55.285 167.208 ;
     RECT  55.285 133.344 55.369 133.368 ;
     RECT  55.177 170.4 55.381 171 ;
     RECT  55.381 170.4 55.753 171.576 ;
     RECT  55.429 5.76 55.861 5.784 ;
     RECT  55.285 166.368 55.957 168.168 ;
     RECT  55.957 166.368 55.969 168.744 ;
     RECT  55.753 170.352 56.293 171.576 ;
     RECT  56.293 170.352 56.387 171.624 ;
     RECT  53.66 1.728 56.408 2.28 ;
     RECT  55.429 3.888 56.408 3.912 ;
     RECT  55.861 5.04 56.408 5.784 ;
     RECT  54.181 7.632 56.408 7.656 ;
     RECT  51.304 8.976 56.408 9 ;
     RECT  55.969 166.368 56.408 169.272 ;
     RECT  56.387 170.352 56.408 171 ;
     RECT  56.408 1.728 56.704 171 ;
     RECT  56.533 172.704 56.819 172.728 ;
     RECT  56.704 1.728 56.909 2.904 ;
     RECT  56.704 170.88 56.981 171 ;
     RECT  56.941 0.528 57.107 0.552 ;
     RECT  56.704 4.512 57.701 5.88 ;
     RECT  56.704 166.176 58.133 167.208 ;
     RECT  56.981 170.976 58.213 171 ;
     RECT  57.157 172.128 58.213 172.152 ;
     RECT  58.213 170.976 58.313 172.152 ;
     RECT  58.313 170.976 58.405 171 ;
     RECT  56.909 1.728 58.451 2.28 ;
     RECT  58.345 138.528 58.493 138.552 ;
     RECT  58.46 33.024 58.547 33.048 ;
     RECT  56.704 41.04 58.547 41.064 ;
     RECT  57.701 5.04 58.549 5.88 ;
     RECT  56.704 7.632 58.625 7.656 ;
     RECT  58.549 5.04 58.691 6.264 ;
     RECT  58.625 7.632 58.709 7.896 ;
     RECT  58.691 5.04 58.745 6.168 ;
     RECT  58.745 5.04 58.781 5.16 ;
     RECT  58.133 167.184 58.933 167.208 ;
     RECT  58.709 7.872 58.997 7.896 ;
     RECT  58.313 172.128 59.171 172.152 ;
     RECT  58.405 170.688 59.245 171 ;
     RECT  58.451 1.728 59.285 1.896 ;
     RECT  59.137 0.528 59.363 0.552 ;
     RECT  58.781 5.04 59.429 5.064 ;
     RECT  59.245 170.4 59.569 171 ;
     RECT  58.501 25.584 59.573 25.608 ;
     RECT  58.933 167.184 59.789 167.256 ;
     RECT  59.569 169.584 59.861 171 ;
     RECT  59.789 167.184 59.933 167.208 ;
     RECT  59.713 3.408 60.073 3.432 ;
     RECT  59.861 169.584 60.077 170.952 ;
     RECT  60.077 169.584 60.329 169.608 ;
     RECT  60.077 170.928 60.401 170.952 ;
     RECT  59.285 1.728 60.437 1.752 ;
     RECT  60.073 2.832 60.581 3.432 ;
     RECT  59.317 168.528 60.797 168.552 ;
     RECT  60.581 3.408 61.808 3.432 ;
     RECT  56.704 8.976 61.808 9 ;
     RECT  61.808 2.148 61.912 170.652 ;
     RECT  61.912 2.418 62.104 170.382 ;
    LAYER M5 ;
     RECT  4.08 0.016 59.928 0.611 ;
     RECT  4.272 0.611 59.928 1.763 ;
     RECT  4.656 1.763 22.632 1.811 ;
     RECT  23.76 1.763 25.656 1.811 ;
     RECT  41.52 1.763 59.16 1.811 ;
     RECT  24 1.811 24.888 1.859 ;
     RECT  26.928 1.763 40.512 1.859 ;
     RECT  41.52 1.811 44.376 1.859 ;
     RECT  50.16 1.811 59.16 1.859 ;
     RECT  4.656 1.811 15.528 1.907 ;
     RECT  26.928 1.859 30.696 1.907 ;
     RECT  52.416 1.859 59.16 1.907 ;
     RECT  50.16 1.859 51.312 2.099 ;
     RECT  52.416 1.907 58.44 2.099 ;
     RECT  2.4 2.137 2.52 2.151 ;
     RECT  61.8 2.137 61.92 2.151 ;
     RECT  4.656 1.907 6.744 2.243 ;
     RECT  4.656 2.243 5.4 2.291 ;
     RECT  6.72 2.243 6.744 2.291 ;
     RECT  7.8 1.907 14.232 2.291 ;
     RECT  16.8 1.811 21 2.291 ;
     RECT  22.608 1.811 22.632 2.291 ;
     RECT  24 1.859 24.504 2.291 ;
     RECT  26.928 1.907 29.712 2.291 ;
     RECT  48.672 1.811 48.696 2.291 ;
     RECT  53.136 2.099 58.44 2.291 ;
     RECT  27.888 2.291 29.712 2.339 ;
     RECT  31.968 1.859 40.512 2.339 ;
     RECT  42.096 1.859 44.376 2.773 ;
     RECT  15.504 1.907 15.528 2.821 ;
     RECT  16.8 2.291 16.824 2.821 ;
     RECT  42.096 2.773 44.424 2.821 ;
     RECT  45.6 1.811 46.68 2.821 ;
     RECT  7.8 2.291 8.232 2.867 ;
     RECT  9.36 2.291 13.896 2.915 ;
     RECT  15.504 2.821 16.824 2.915 ;
     RECT  32.16 2.339 40.512 3.205 ;
     RECT  32.16 3.205 40.776 3.301 ;
     RECT  42.096 2.821 46.68 3.301 ;
     RECT  50.4 2.099 51.312 3.397 ;
     RECT  10.848 2.915 13.896 3.443 ;
     RECT  27.888 2.339 27.912 3.443 ;
     RECT  32.16 3.301 46.68 3.443 ;
     RECT  18.192 2.291 21 3.491 ;
     RECT  10.944 3.443 13.896 3.685 ;
     RECT  10.944 3.685 14.136 3.733 ;
     RECT  7.8 2.867 8.112 3.925 ;
     RECT  10.944 3.733 14.232 4.019 ;
     RECT  38.592 3.443 46.68 4.019 ;
     RECT  7.392 3.925 8.112 4.067 ;
     RECT  32.16 3.443 37.416 4.067 ;
     RECT  38.592 4.019 46.296 4.067 ;
     RECT  26.352 3.685 26.376 4.115 ;
     RECT  38.592 4.067 46.008 4.115 ;
     RECT  38.592 4.115 45.912 4.211 ;
     RECT  18.192 3.491 19.992 4.501 ;
     RECT  21.072 3.733 21.096 4.501 ;
     RECT  29.4 2.339 29.712 4.501 ;
     RECT  32.16 4.067 35.88 4.501 ;
     RECT  6.24 3.397 6.264 4.595 ;
     RECT  9.36 2.915 9.384 4.595 ;
     RECT  15.504 2.915 16.536 4.595 ;
     RECT  31.872 4.501 35.88 4.595 ;
     RECT  37.008 4.067 37.416 4.595 ;
     RECT  39.744 4.211 45.912 4.595 ;
     RECT  50.4 3.397 51.432 4.595 ;
     RECT  53.136 2.291 53.16 4.595 ;
     RECT  50.88 4.595 51.432 4.691 ;
     RECT  13.2 4.019 14.232 5.077 ;
     RECT  15.36 4.741 15.384 5.077 ;
     RECT  33.12 4.595 35.88 5.171 ;
     RECT  39.744 4.595 43.896 5.171 ;
     RECT  44.928 4.595 45.912 5.171 ;
     RECT  58.032 2.291 58.056 5.171 ;
     RECT  42.048 5.171 43.896 5.267 ;
     RECT  29.04 4.501 29.712 5.605 ;
     RECT  10.944 4.019 12.12 5.747 ;
     RECT  13.2 5.077 15.384 5.747 ;
     RECT  18.192 4.501 21.096 5.747 ;
     RECT  33.12 5.171 35.208 5.747 ;
     RECT  42.048 5.267 43.8 5.747 ;
     RECT  51 4.691 51.432 5.747 ;
     RECT  14.592 5.747 15.384 5.843 ;
     RECT  33.12 5.747 35.112 5.891 ;
     RECT  7.8 4.067 8.112 5.893 ;
     RECT  31.872 4.595 31.896 5.893 ;
     RECT  38.592 4.211 38.76 5.893 ;
     RECT  39.744 5.171 41.016 5.893 ;
     RECT  42.048 5.747 43.416 5.987 ;
     RECT  4.176 3.685 4.2 6.181 ;
     RECT  38.592 5.893 41.016 6.181 ;
     RECT  11.76 5.747 12.12 6.229 ;
     RECT  13.2 5.747 13.512 6.229 ;
     RECT  37.248 4.595 37.416 6.229 ;
     RECT  38.592 6.181 41.784 6.229 ;
     RECT  58.56 6.133 58.584 6.229 ;
     RECT  58.56 6.229 58.68 6.275 ;
     RECT  11.76 6.229 13.512 6.323 ;
     RECT  4.176 6.181 4.92 7.427 ;
     RECT  54.192 5.173 54.216 7.667 ;
     RECT  4.416 7.427 4.92 7.765 ;
     RECT  4.416 7.765 4.968 8.485 ;
     RECT  31.872 5.893 31.992 8.965 ;
     RECT  6.096 6.229 6.12 9.203 ;
     RECT  4.416 8.485 5.112 10.213 ;
     RECT  6.624 10.117 6.648 10.213 ;
     RECT  2.4 2.151 2.712 10.789 ;
     RECT  4.32 10.213 5.112 10.789 ;
     RECT  2.4 10.789 5.112 11.459 ;
     RECT  6.336 10.213 6.648 11.459 ;
     RECT  7.8 5.893 8.52 11.555 ;
     RECT  7.8 11.555 8.232 15.061 ;
     RECT  6.336 11.459 6.36 15.589 ;
     RECT  4.32 11.459 5.112 15.877 ;
     RECT  4.224 15.877 5.112 16.691 ;
     RECT  6.336 15.589 6.744 17.123 ;
     RECT  7.8 15.061 8.28 17.123 ;
     RECT  6.336 17.123 6.36 18.133 ;
     RECT  7.8 17.123 8.112 18.133 ;
     RECT  6.336 18.133 8.112 18.851 ;
     RECT  10.56 6.229 10.584 19.427 ;
     RECT  43.008 5.987 43.416 19.427 ;
     RECT  43.008 19.427 43.32 20.003 ;
     RECT  9.6 20.485 9.624 20.725 ;
     RECT  43.2 20.003 43.32 21.155 ;
     RECT  6.336 18.851 6.36 21.349 ;
     RECT  7.8 18.851 8.112 21.349 ;
     RECT  6.336 21.349 8.112 22.165 ;
     RECT  43.296 21.155 43.32 22.259 ;
     RECT  4.32 16.691 5.112 22.741 ;
     RECT  6.336 22.165 8.52 22.741 ;
     RECT  9.6 20.725 10.584 22.741 ;
     RECT  11.856 6.323 13.512 22.741 ;
     RECT  4.32 22.741 8.52 23.363 ;
     RECT  9.6 22.741 13.512 23.411 ;
     RECT  44.976 5.171 45.912 23.987 ;
     RECT  6.336 23.363 8.112 24.469 ;
     RECT  9.6 23.411 11.256 24.469 ;
     RECT  12.384 23.411 13.512 24.563 ;
     RECT  6.336 24.469 11.256 25.091 ;
     RECT  58.656 6.275 58.68 25.573 ;
     RECT  58.512 25.573 58.68 25.619 ;
     RECT  4.32 23.363 5.112 26.197 ;
     RECT  6.336 25.091 8.112 26.197 ;
     RECT  4.32 26.197 8.112 26.819 ;
     RECT  4.32 26.819 6.36 27.301 ;
     RECT  3.984 27.301 6.36 27.395 ;
     RECT  6.336 27.395 6.36 28.453 ;
     RECT  7.392 26.819 8.112 28.453 ;
     RECT  3.984 27.395 5.112 29.507 ;
     RECT  14.592 5.843 15.048 29.699 ;
     RECT  13.2 24.563 13.512 29.941 ;
     RECT  12.24 29.941 13.512 31.189 ;
     RECT  6.336 28.453 8.112 31.955 ;
     RECT  12.24 31.189 13.704 32.243 ;
     RECT  4.32 29.507 5.112 32.869 ;
     RECT  15.024 29.699 15.048 33.107 ;
     RECT  13.2 32.243 13.704 33.589 ;
     RECT  13.104 33.589 13.704 34.021 ;
     RECT  6.336 31.955 6.36 34.693 ;
     RECT  7.392 31.955 8.112 34.693 ;
     RECT  4.176 32.869 5.112 34.835 ;
     RECT  13.104 34.021 14.088 35.797 ;
     RECT  13.104 35.797 14.232 35.843 ;
     RECT  6.336 34.693 8.112 37.043 ;
     RECT  4.32 34.835 5.112 37.477 ;
     RECT  13.2 35.843 14.232 37.619 ;
     RECT  4.08 37.477 5.112 37.667 ;
     RECT  6.336 37.043 6.36 38.005 ;
     RECT  7.392 37.043 8.112 38.005 ;
     RECT  15.696 35.845 15.72 38.149 ;
     RECT  4.08 37.667 5.064 38.243 ;
     RECT  18.192 5.747 20.472 38.243 ;
     RECT  14.592 38.149 14.616 38.389 ;
     RECT  15.696 38.149 15.864 38.389 ;
     RECT  18.6 38.243 20.472 38.485 ;
     RECT  6.336 38.005 8.112 38.725 ;
     RECT  14.592 38.389 15.864 38.819 ;
     RECT  15.504 38.819 15.864 38.963 ;
     RECT  15.792 38.963 15.864 39.013 ;
     RECT  15.792 39.013 15.96 39.299 ;
     RECT  17.04 39.253 17.064 40.405 ;
     RECT  18.6 38.485 20.52 40.405 ;
     RECT  58.512 25.619 58.536 41.075 ;
     RECT  17.04 40.405 20.52 41.651 ;
     RECT  4.08 38.243 5.016 42.709 ;
     RECT  6.192 38.725 8.112 42.709 ;
     RECT  4.08 42.709 8.112 42.803 ;
     RECT  17.184 41.651 20.52 43.235 ;
     RECT  15.936 39.299 15.96 43.283 ;
     RECT  28.272 5.605 29.712 43.285 ;
     RECT  18 43.235 20.52 43.955 ;
     RECT  4.08 42.803 6.216 44.339 ;
     RECT  6.192 44.339 6.216 45.541 ;
     RECT  7.8 42.803 8.112 45.541 ;
     RECT  20.256 43.955 20.52 46.645 ;
     RECT  20.016 46.645 20.52 47.939 ;
     RECT  6.192 45.541 8.112 48.659 ;
     RECT  20.496 47.939 20.52 48.949 ;
     RECT  4.08 44.339 5.016 48.997 ;
     RECT  9.6 25.091 11.256 49.333 ;
     RECT  20.112 48.949 20.52 50.291 ;
     RECT  4.08 48.997 5.208 51.253 ;
     RECT  6.192 48.659 6.216 51.253 ;
     RECT  20.496 50.291 20.52 51.253 ;
     RECT  9.504 49.333 11.256 51.923 ;
     RECT  20.496 51.253 21.096 52.261 ;
     RECT  24 2.291 24.312 52.405 ;
     RECT  20.16 52.261 21.096 53.555 ;
     RECT  20.16 53.555 20.52 53.603 ;
     RECT  20.16 53.603 20.184 53.891 ;
     RECT  4.08 51.253 6.216 56.677 ;
     RECT  7.8 48.659 8.112 56.677 ;
     RECT  26.544 42.997 26.568 57.059 ;
     RECT  21.216 54.661 21.24 57.875 ;
     RECT  23.232 52.405 24.312 60.085 ;
     RECT  21.744 58.645 21.768 60.995 ;
     RECT  23.232 60.085 24.408 61.379 ;
     RECT  4.08 56.677 8.112 61.619 ;
     RECT  4.08 61.619 6.216 62.629 ;
     RECT  7.8 61.619 8.112 62.629 ;
     RECT  2.4 11.459 2.712 63.205 ;
     RECT  4.08 62.629 8.112 63.205 ;
     RECT  2.4 63.205 8.112 63.683 ;
     RECT  26.736 61.765 26.76 64.357 ;
     RECT  2.4 63.683 6.648 64.451 ;
     RECT  26.736 64.357 26.856 65.651 ;
     RECT  4.08 64.451 6.648 67.283 ;
     RECT  28.176 43.285 29.712 72.901 ;
     RECT  31.536 8.965 31.992 72.901 ;
     RECT  28.176 72.901 31.992 73.571 ;
     RECT  33.552 5.891 35.112 74.147 ;
     RECT  4.08 67.283 6.216 75.541 ;
     RECT  7.8 63.683 8.112 75.541 ;
     RECT  26.736 65.651 26.76 75.541 ;
     RECT  28.176 73.571 31.56 75.541 ;
     RECT  26.736 75.541 31.56 76.403 ;
     RECT  26.736 76.403 27.48 76.931 ;
     RECT  2.4 64.451 2.712 78.037 ;
     RECT  4.08 75.541 8.112 78.037 ;
     RECT  26.736 76.931 26.76 78.037 ;
     RECT  2.4 78.037 8.112 79.187 ;
     RECT  26.736 78.037 27.576 79.475 ;
     RECT  33.984 74.147 35.112 79.621 ;
     RECT  2.4 79.187 6.216 79.715 ;
     RECT  28.752 76.403 31.56 81.877 ;
     RECT  4.08 79.715 6.216 82.115 ;
     RECT  28.752 81.877 32.328 82.691 ;
     RECT  33.888 79.621 35.112 83.221 ;
     RECT  37.248 6.229 41.784 84.419 ;
     RECT  6.192 82.115 6.216 84.901 ;
     RECT  37.344 84.419 41.784 84.995 ;
     RECT  6.048 84.901 6.216 86.099 ;
     RECT  28.752 82.691 31.56 86.147 ;
     RECT  31.824 86.149 31.848 86.339 ;
     RECT  33.216 83.221 35.112 86.341 ;
     RECT  33.216 86.341 36.024 86.483 ;
     RECT  28.752 86.147 30.696 86.581 ;
     RECT  33.6 86.483 36.024 86.725 ;
     RECT  33.6 86.725 36.744 86.963 ;
     RECT  6.192 86.099 6.216 87.157 ;
     RECT  6.192 87.157 6.264 87.827 ;
     RECT  4.08 82.115 5.016 88.933 ;
     RECT  6.192 87.827 6.216 88.933 ;
     RECT  4.08 88.933 6.216 89.699 ;
     RECT  4.08 89.699 5.208 91.187 ;
     RECT  4.08 91.187 5.016 92.821 ;
     RECT  6.192 89.699 6.216 92.821 ;
     RECT  38.736 84.995 41.784 92.963 ;
     RECT  39.504 92.963 41.784 93.925 ;
     RECT  33.888 86.963 36.744 95.557 ;
     RECT  33.888 95.557 37.032 95.603 ;
     RECT  37.008 95.603 37.032 97.381 ;
     RECT  4.08 92.821 6.216 98.245 ;
     RECT  7.8 79.187 8.112 98.245 ;
     RECT  37.008 97.381 37.512 98.531 ;
     RECT  33.888 95.603 36.024 99.157 ;
     RECT  37.008 98.531 37.176 99.157 ;
     RECT  33.888 99.157 37.176 99.875 ;
     RECT  39.36 93.925 41.784 100.355 ;
     RECT  4.08 98.245 8.112 101.315 ;
     RECT  33.888 99.875 37.032 101.891 ;
     RECT  37.008 101.891 37.032 107.125 ;
     RECT  37.008 107.125 37.848 108.131 ;
     RECT  45.6 23.987 45.912 108.805 ;
     RECT  33.888 101.891 36.024 109.381 ;
     RECT  37.008 108.131 37.032 109.381 ;
     RECT  45.6 108.805 46.008 109.957 ;
     RECT  33.888 109.381 37.032 111.059 ;
     RECT  45.6 109.957 46.056 111.109 ;
     RECT  37.008 111.059 37.032 112.837 ;
     RECT  33.888 111.059 36.024 113.029 ;
     RECT  37.008 112.837 37.8 113.029 ;
     RECT  4.08 101.315 6.216 114.421 ;
     RECT  33.888 113.029 37.8 114.517 ;
     RECT  4.08 114.421 6.552 114.949 ;
     RECT  7.8 101.315 8.112 114.949 ;
     RECT  47.952 113.941 47.976 115.669 ;
     RECT  4.08 114.949 8.112 116.243 ;
     RECT  33.888 114.517 37.848 117.251 ;
     RECT  28.56 86.581 30.696 118.019 ;
     RECT  33.888 117.251 37.656 118.067 ;
     RECT  2.4 79.715 2.712 119.653 ;
     RECT  4.08 116.243 6.216 119.653 ;
     RECT  33.888 118.067 36.024 120.709 ;
     RECT  37.008 118.067 37.656 120.709 ;
     RECT  2.4 119.653 6.216 121.043 ;
     RECT  51 5.747 51.312 122.485 ;
     RECT  33.888 120.709 37.656 128.291 ;
     RECT  33.888 128.291 36.84 129.923 ;
     RECT  37.248 129.973 37.272 131.123 ;
     RECT  4.08 121.043 6.216 132.181 ;
     RECT  7.8 116.243 8.112 132.181 ;
     RECT  4.08 132.181 8.112 134.003 ;
     RECT  33.888 129.923 36.024 135.061 ;
     RECT  33.888 135.061 36.504 136.259 ;
     RECT  33.888 136.259 36.024 138.517 ;
     RECT  33.888 138.517 36.744 141.971 ;
     RECT  7.8 134.003 8.112 143.029 ;
     RECT  4.08 134.003 6.216 144.085 ;
     RECT  7.8 143.029 8.424 144.755 ;
     RECT  3.984 144.085 6.216 147.107 ;
     RECT  7.8 144.755 8.112 155.221 ;
     RECT  50.352 122.485 51.312 165.829 ;
     RECT  9.504 51.923 11.112 165.923 ;
     RECT  4.08 147.107 6.216 166.115 ;
     RECT  56.4 2.291 56.712 166.165 ;
     RECT  29.232 118.019 30.696 166.309 ;
     RECT  26.736 79.475 26.76 166.357 ;
     RECT  33.888 141.971 36.024 166.357 ;
     RECT  55.296 133.333 55.32 166.357 ;
     RECT  56.4 166.165 57.672 166.357 ;
     RECT  7.44 155.221 8.112 166.405 ;
     RECT  13.2 37.619 13.608 166.405 ;
     RECT  39.36 100.355 41.208 166.405 ;
     RECT  55.296 166.357 58.056 166.405 ;
     RECT  28.224 165.685 28.248 166.453 ;
     RECT  29.232 166.309 31.272 166.453 ;
     RECT  38.544 166.405 41.208 166.453 ;
     RECT  9.552 165.923 11.112 166.499 ;
     RECT  49.488 165.829 51.312 166.693 ;
     RECT  45.6 111.109 46.152 166.741 ;
     RECT  42.432 101.413 42.456 166.789 ;
     RECT  54.672 166.405 58.056 166.835 ;
     RECT  13.104 166.405 13.608 166.885 ;
     RECT  47.952 115.669 48.264 166.885 ;
     RECT  7.44 166.405 8.424 166.981 ;
     RECT  16.464 166.789 16.488 166.981 ;
     RECT  18 43.955 18.912 166.981 ;
     RECT  20.976 166.405 21 166.981 ;
     RECT  23.232 61.379 24.312 166.981 ;
     RECT  28.224 166.453 31.272 166.981 ;
     RECT  33.888 166.357 36.888 166.981 ;
     RECT  38.16 166.453 41.208 166.981 ;
     RECT  42.432 166.789 42.504 166.981 ;
     RECT  45.456 166.741 46.152 166.981 ;
     RECT  47.136 166.885 48.264 166.981 ;
     RECT  28.224 166.981 31.656 167.027 ;
     RECT  23.232 166.981 24.504 167.029 ;
     RECT  26.016 166.357 26.76 167.029 ;
     RECT  33.696 166.981 36.888 167.029 ;
     RECT  4.08 166.115 5.016 167.075 ;
     RECT  20.736 166.981 21 167.075 ;
     RECT  49.392 166.693 51.672 167.173 ;
     RECT  53.328 166.405 53.352 167.173 ;
     RECT  56.4 166.835 58.056 167.221 ;
     RECT  33.696 167.029 37.08 167.365 ;
     RECT  44.928 166.981 46.152 167.509 ;
     RECT  47.136 166.981 48.312 167.509 ;
     RECT  38.16 166.981 42.504 167.557 ;
     RECT  43.776 166.981 43.8 167.557 ;
     RECT  44.928 167.509 48.312 167.557 ;
     RECT  49.392 167.173 53.352 167.557 ;
     RECT  4.416 167.075 5.016 167.603 ;
     RECT  10.368 166.499 11.112 167.603 ;
     RECT  44.928 167.557 53.352 167.603 ;
     RECT  12.864 166.885 13.608 167.605 ;
     RECT  26.016 167.029 27.528 167.651 ;
     RECT  38.16 167.557 43.8 167.845 ;
     RECT  44.928 167.603 49.416 167.845 ;
     RECT  6.192 166.115 6.216 167.893 ;
     RECT  7.248 166.981 8.952 167.893 ;
     RECT  33.12 167.365 37.08 168.085 ;
     RECT  38.16 167.845 49.416 168.085 ;
     RECT  4.512 167.603 5.016 168.179 ;
     RECT  6.192 167.893 8.952 168.179 ;
     RECT  10.464 167.603 11.112 168.179 ;
     RECT  18 166.981 19.272 168.179 ;
     RECT  28.608 167.027 31.656 168.179 ;
     RECT  33.12 168.085 49.416 168.179 ;
     RECT  48.288 168.179 49.416 168.275 ;
     RECT  54.672 166.835 55.32 168.709 ;
     RECT  56.4 167.221 58.968 168.709 ;
     RECT  11.088 168.179 11.112 168.755 ;
     RECT  18.096 168.179 19.272 168.755 ;
     RECT  4.512 168.179 4.728 168.803 ;
     RECT  22.416 167.029 24.504 168.901 ;
     RECT  31.248 168.179 31.656 169.093 ;
     RECT  33.12 168.179 35.736 169.141 ;
     RECT  36.864 168.179 47.16 169.141 ;
     RECT  26.016 167.651 27.336 169.189 ;
     RECT  25.824 169.189 27.336 169.237 ;
     RECT  28.608 168.179 29.928 169.237 ;
     RECT  31.248 169.093 31.848 169.237 ;
     RECT  48.288 168.275 48.312 169.237 ;
     RECT  49.392 168.275 49.416 169.237 ;
     RECT  25.632 169.237 27.336 169.285 ;
     RECT  28.608 169.237 31.848 169.285 ;
     RECT  5.184 169.669 5.208 169.861 ;
     RECT  20.736 167.075 20.76 169.861 ;
     RECT  22.416 168.901 24.6 169.861 ;
     RECT  4.848 169.861 5.208 170.389 ;
     RECT  12.864 167.605 13.656 170.389 ;
     RECT  25.632 169.285 31.848 170.389 ;
     RECT  33.12 169.141 47.16 170.389 ;
     RECT  6.528 168.179 8.952 170.437 ;
     RECT  11.568 169.813 11.592 170.437 ;
     RECT  12.72 170.389 13.656 170.437 ;
     RECT  20.736 169.861 24.6 170.437 ;
     RECT  25.632 170.389 47.16 170.437 ;
     RECT  48.288 169.237 49.416 170.437 ;
     RECT  50.544 167.603 53.352 170.437 ;
     RECT  54.672 168.709 58.968 170.437 ;
     RECT  2.4 121.043 2.712 170.649 ;
     RECT  61.8 2.151 62.112 170.649 ;
     RECT  2.4 170.649 2.52 170.663 ;
     RECT  61.8 170.649 61.92 170.663 ;
     RECT  48.288 170.437 58.968 170.821 ;
     RECT  11.568 170.437 14.232 170.869 ;
     RECT  48.288 170.821 59.736 170.917 ;
     RECT  4.848 170.389 5.4 170.965 ;
     RECT  6.528 170.437 9.144 170.965 ;
     RECT  11.376 170.869 14.232 170.965 ;
     RECT  16.464 166.981 17.016 170.965 ;
     RECT  18.336 168.755 19.272 170.965 ;
     RECT  20.352 170.437 47.16 170.965 ;
     RECT  48.288 170.917 59.928 170.965 ;
     RECT  4.464 170.965 59.928 171.013 ;
     RECT  4.08 171.013 59.928 172.752 ;
     RECT  22.632 1.763 23.76 1.811 ;
     RECT  25.656 1.763 26.928 1.811 ;
     RECT  40.512 1.763 41.52 1.859 ;
     RECT  15.528 1.811 16.8 2.821 ;
     RECT  22.632 1.811 24 2.291 ;
     RECT  44.376 1.811 45.6 2.773 ;
     RECT  48.696 1.811 50.16 2.099 ;
     RECT  30.696 1.859 31.968 1.907 ;
     RECT  40.512 1.859 42.096 3.205 ;
     RECT  51.312 1.859 52.416 2.099 ;
     RECT  6.744 1.907 7.8 2.291 ;
     RECT  14.232 1.907 15.504 2.291 ;
     RECT  51.312 2.099 51.432 3.397 ;
     RECT  5.4 2.243 6.72 2.291 ;
     RECT  6.24 2.291 6.264 3.397 ;
     RECT  8.232 2.291 9.36 2.867 ;
     RECT  13.896 2.291 15.504 3.685 ;
     RECT  16.824 2.291 18.192 2.915 ;
     RECT  56.712 2.291 58.032 5.171 ;
     RECT  27.912 2.339 29.4 3.443 ;
     RECT  44.424 2.773 45.6 2.821 ;
     RECT  8.112 2.867 9.36 4.595 ;
     RECT  9.384 2.915 10.848 3.443 ;
     RECT  40.776 3.205 42.096 3.301 ;
     RECT  29.04 3.443 29.4 4.501 ;
     RECT  37.416 3.443 38.592 6.229 ;
     RECT  19.992 3.491 21 3.733 ;
     RECT  2.712 3.685 4.176 7.427 ;
     RECT  14.136 3.685 15.504 3.733 ;
     RECT  14.232 3.733 15.504 4.595 ;
     RECT  19.992 3.733 21.072 4.501 ;
     RECT  6.264 3.925 7.392 4.067 ;
     RECT  12.12 4.019 13.2 6.229 ;
     RECT  35.88 4.067 37.008 4.595 ;
     RECT  38.76 4.211 39.744 5.893 ;
     RECT  8.112 4.595 8.52 5.893 ;
     RECT  14.232 4.595 15.384 4.741 ;
     RECT  31.896 4.595 33.12 5.891 ;
     RECT  35.88 4.595 37.248 5.171 ;
     RECT  43.896 4.595 44.928 5.171 ;
     RECT  14.232 4.741 15.36 5.077 ;
     RECT  41.016 5.171 42.048 5.987 ;
     RECT  43.896 5.171 44.976 5.267 ;
     RECT  43.8 5.267 44.976 5.747 ;
     RECT  10.944 5.747 11.76 6.229 ;
     RECT  13.512 5.747 14.592 29.699 ;
     RECT  31.896 5.891 31.992 5.893 ;
     RECT  41.016 5.987 43.008 6.181 ;
     RECT  41.784 6.181 43.008 20.003 ;
     RECT  4.92 6.229 6.096 7.765 ;
     RECT  10.584 6.229 11.76 6.323 ;
     RECT  10.584 6.323 11.856 19.427 ;
     RECT  4.968 7.765 6.096 8.485 ;
     RECT  5.112 8.485 6.096 9.203 ;
     RECT  5.112 9.203 6.12 10.117 ;
     RECT  5.112 10.117 6.624 10.213 ;
     RECT  6.648 10.117 7.8 11.459 ;
     RECT  5.112 10.213 6.336 22.741 ;
     RECT  6.36 11.459 7.8 15.589 ;
     RECT  6.744 15.589 7.8 17.123 ;
     RECT  2.712 15.877 4.224 16.691 ;
     RECT  6.36 17.123 7.8 18.133 ;
     RECT  6.36 18.851 7.8 21.349 ;
     RECT  10.56 19.427 11.856 20.485 ;
     RECT  41.784 20.003 43.2 21.155 ;
     RECT  8.112 20.485 9.6 22.165 ;
     RECT  9.624 20.485 11.856 20.725 ;
     RECT  10.584 20.725 11.856 22.741 ;
     RECT  41.784 21.155 43.296 22.259 ;
     RECT  8.52 22.165 9.6 23.363 ;
     RECT  5.112 23.363 6.336 26.197 ;
     RECT  8.112 23.363 9.6 24.469 ;
     RECT  11.256 23.411 12.384 24.563 ;
     RECT  8.112 25.091 9.6 49.333 ;
     RECT  6.36 26.819 7.392 28.453 ;
     RECT  2.712 27.301 3.984 29.507 ;
     RECT  5.112 27.395 6.336 37.667 ;
     RECT  13.512 29.699 15.024 31.189 ;
     RECT  11.256 29.941 12.24 32.243 ;
     RECT  13.704 31.189 15.024 33.107 ;
     RECT  6.36 31.955 7.392 34.693 ;
     RECT  13.104 32.243 13.2 33.589 ;
     RECT  2.712 32.869 4.176 34.835 ;
     RECT  13.704 33.107 14.088 34.021 ;
     RECT  14.232 35.845 15.696 37.619 ;
     RECT  6.36 37.043 7.392 38.005 ;
     RECT  2.712 37.477 4.08 63.205 ;
     RECT  13.608 37.619 15.696 38.149 ;
     RECT  5.064 37.667 6.336 38.243 ;
     RECT  13.608 38.149 14.592 38.819 ;
     RECT  14.616 38.149 15.696 38.389 ;
     RECT  5.016 38.243 6.336 38.725 ;
     RECT  5.016 38.725 6.192 42.709 ;
     RECT  15.96 39.253 17.04 41.651 ;
     RECT  15.96 41.651 17.184 43.235 ;
     RECT  18.912 43.955 20.256 46.645 ;
     RECT  5.016 44.339 6.192 48.997 ;
     RECT  18.912 46.645 20.016 47.939 ;
     RECT  18.912 47.939 20.496 48.949 ;
     RECT  18.912 48.949 20.112 50.291 ;
     RECT  5.208 48.997 6.192 51.253 ;
     RECT  8.112 49.333 9.504 143.029 ;
     RECT  18.912 52.261 20.16 53.891 ;
     RECT  21.768 58.645 23.232 60.995 ;
     RECT  6.216 61.619 7.8 62.629 ;
     RECT  26.76 61.765 28.176 64.357 ;
     RECT  6.648 63.683 7.8 67.283 ;
     RECT  26.856 64.357 28.176 65.651 ;
     RECT  2.712 64.451 4.08 78.037 ;
     RECT  26.76 65.651 28.176 75.541 ;
     RECT  27.48 76.403 28.752 76.931 ;
     RECT  26.76 76.931 28.752 78.037 ;
     RECT  27.576 78.037 28.752 79.475 ;
     RECT  2.712 79.715 4.08 119.653 ;
     RECT  5.016 82.115 6.192 84.901 ;
     RECT  5.016 84.901 6.048 86.099 ;
     RECT  5.016 86.099 6.192 88.933 ;
     RECT  30.696 86.147 31.56 86.149 ;
     RECT  30.696 86.149 31.824 86.339 ;
     RECT  31.848 86.149 33.216 86.339 ;
     RECT  5.208 89.699 6.192 91.187 ;
     RECT  5.016 91.187 6.192 92.821 ;
     RECT  39.36 92.963 39.504 93.925 ;
     RECT  36.024 95.603 37.008 99.157 ;
     RECT  41.208 100.355 41.784 101.413 ;
     RECT  41.208 101.413 42.432 166.981 ;
     RECT  36.024 101.891 37.008 109.381 ;
     RECT  37.848 107.125 39.36 108.131 ;
     RECT  36.024 111.059 37.008 113.029 ;
     RECT  6.552 114.421 7.8 114.949 ;
     RECT  37.848 114.517 39.36 117.251 ;
     RECT  36.024 118.067 37.008 120.709 ;
     RECT  2.712 121.043 4.08 144.085 ;
     RECT  36.024 129.923 36.84 129.973 ;
     RECT  36.024 129.973 37.248 131.123 ;
     RECT  55.32 133.333 56.4 166.357 ;
     RECT  8.424 143.029 9.504 144.755 ;
     RECT  2.712 144.085 3.984 147.107 ;
     RECT  8.112 144.755 9.504 165.923 ;
     RECT  2.712 147.107 4.08 167.075 ;
     RECT  6.216 155.221 7.44 166.981 ;
     RECT  26.76 165.685 28.224 167.027 ;
     RECT  28.248 165.685 29.232 166.453 ;
     RECT  48.264 165.829 49.488 166.693 ;
     RECT  8.112 165.923 9.552 166.405 ;
     RECT  5.016 166.115 6.192 168.179 ;
     RECT  8.424 166.405 9.552 166.499 ;
     RECT  53.352 166.405 54.672 170.437 ;
     RECT  36.888 166.453 38.16 167.029 ;
     RECT  8.424 166.499 10.368 166.981 ;
     RECT  48.264 166.693 49.392 166.981 ;
     RECT  16.488 166.789 18 166.981 ;
     RECT  55.32 166.835 56.4 168.709 ;
     RECT  46.152 166.885 47.136 167.509 ;
     RECT  6.216 166.981 7.248 167.893 ;
     RECT  8.952 166.981 10.368 167.603 ;
     RECT  17.016 166.981 18 168.179 ;
     RECT  19.272 166.981 20.736 170.437 ;
     RECT  24.504 166.981 26.016 168.901 ;
     RECT  42.504 166.981 43.776 167.557 ;
     RECT  43.8 166.981 44.928 167.845 ;
     RECT  48.312 166.981 49.392 167.557 ;
     RECT  26.76 167.027 28.608 167.029 ;
     RECT  21 167.029 22.416 167.075 ;
     RECT  27.528 167.029 28.608 167.651 ;
     RECT  37.08 167.029 38.16 168.085 ;
     RECT  31.656 167.365 33.12 169.093 ;
     RECT  8.952 167.603 10.464 168.179 ;
     RECT  49.416 167.603 50.544 170.437 ;
     RECT  27.336 167.651 28.608 169.285 ;
     RECT  4.728 168.179 6.528 168.803 ;
     RECT  17.016 168.179 18.096 168.755 ;
     RECT  29.928 168.179 31.248 169.237 ;
     RECT  35.736 168.179 36.864 169.141 ;
     RECT  47.16 168.179 48.288 170.965 ;
     RECT  48.312 168.275 49.392 169.237 ;
     RECT  17.016 168.755 18.336 170.965 ;
     RECT  4.848 168.803 6.528 169.669 ;
     RECT  24.6 168.901 26.016 169.189 ;
     RECT  31.848 169.093 33.12 170.389 ;
     RECT  24.6 169.189 25.824 169.237 ;
     RECT  24.6 169.237 25.632 170.437 ;
     RECT  4.848 169.669 5.184 169.861 ;
     RECT  5.208 169.669 6.528 170.389 ;
     RECT  11.592 169.813 12.864 170.389 ;
     RECT  5.4 170.389 6.528 170.965 ;
     RECT  11.592 170.389 12.72 170.437 ;
     RECT  19.272 170.437 20.352 170.965 ;
  END
END qkd_embedding_static_return_hop
END LIBRARY
